VERSION 5.8 ;
BUSBITCHARS "[]" ;
DIVIDERCHAR "/" ;
UNITS
    DATABASE MICRONS 1000 ;
END UNITS

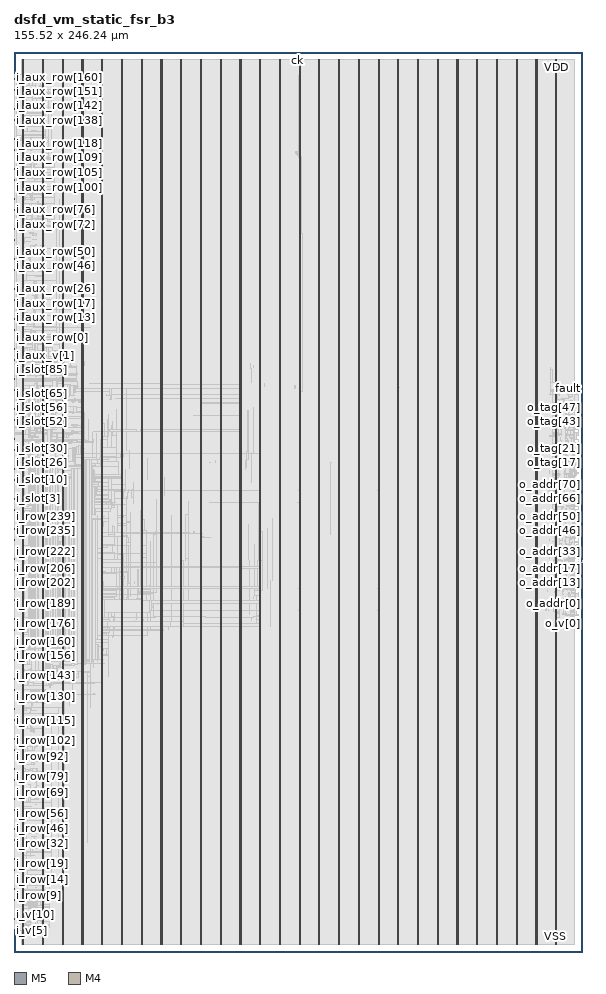
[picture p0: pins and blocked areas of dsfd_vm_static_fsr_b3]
MACRO dsfd_vm_static_fsr_b3
  FOREIGN dsfd_vm_static_fsr_b3 0 0 ;
  CLASS BLOCK ;
  SIZE 155.52 BY 246.24 ;
  PIN ck
    DIRECTION INPUT ;
    USE SIGNAL ;
    PORT
      LAYER M5 ;
        RECT  77.52 246.156 77.544 246.24 ;
    END
  END ck
  PIN fault
    DIRECTION OUTPUT ;
    USE SIGNAL ;
    PORT
      LAYER M4 ;
        RECT  155.436 154.176 155.52 154.2 ;
    END
  END fault
  PIN i_aux_row[0]
    DIRECTION INPUT ;
    USE SIGNAL ;
    PORT
      LAYER M4 ;
        RECT  0 168 0.084 168.024 ;
    END
  END i_aux_row[0]
  PIN i_aux_row[100]
    DIRECTION INPUT ;
    USE SIGNAL ;
    PORT
      LAYER M4 ;
        RECT  0 211.2 0.084 211.224 ;
    END
  END i_aux_row[100]
  PIN i_aux_row[101]
    DIRECTION INPUT ;
    USE SIGNAL ;
    PORT
      LAYER M4 ;
        RECT  0 211.632 0.084 211.656 ;
    END
  END i_aux_row[101]
  PIN i_aux_row[102]
    DIRECTION INPUT ;
    USE SIGNAL ;
    PORT
      LAYER M4 ;
        RECT  0 212.064 0.084 212.088 ;
    END
  END i_aux_row[102]
  PIN i_aux_row[103]
    DIRECTION INPUT ;
    USE SIGNAL ;
    PORT
      LAYER M4 ;
        RECT  0 212.496 0.084 212.52 ;
    END
  END i_aux_row[103]
  PIN i_aux_row[104]
    DIRECTION INPUT ;
    USE SIGNAL ;
    PORT
      LAYER M4 ;
        RECT  0 212.928 0.084 212.952 ;
    END
  END i_aux_row[104]
  PIN i_aux_row[105]
    DIRECTION INPUT ;
    USE SIGNAL ;
    PORT
      LAYER M4 ;
        RECT  0 213.36 0.084 213.384 ;
    END
  END i_aux_row[105]
  PIN i_aux_row[106]
    DIRECTION INPUT ;
    USE SIGNAL ;
    PORT
      LAYER M4 ;
        RECT  0 213.792 0.084 213.816 ;
    END
  END i_aux_row[106]
  PIN i_aux_row[107]
    DIRECTION INPUT ;
    USE SIGNAL ;
    PORT
      LAYER M4 ;
        RECT  0 214.224 0.084 214.248 ;
    END
  END i_aux_row[107]
  PIN i_aux_row[108]
    DIRECTION INPUT ;
    USE SIGNAL ;
    PORT
      LAYER M4 ;
        RECT  0 214.656 0.084 214.68 ;
    END
  END i_aux_row[108]
  PIN i_aux_row[109]
    DIRECTION INPUT ;
    USE SIGNAL ;
    PORT
      LAYER M4 ;
        RECT  0 215.088 0.084 215.112 ;
    END
  END i_aux_row[109]
  PIN i_aux_row[10]
    DIRECTION INPUT ;
    USE SIGNAL ;
    PORT
      LAYER M4 ;
        RECT  0 172.32 0.084 172.344 ;
    END
  END i_aux_row[10]
  PIN i_aux_row[110]
    DIRECTION INPUT ;
    USE SIGNAL ;
    PORT
      LAYER M4 ;
        RECT  0 215.52 0.084 215.544 ;
    END
  END i_aux_row[110]
  PIN i_aux_row[111]
    DIRECTION INPUT ;
    USE SIGNAL ;
    PORT
      LAYER M4 ;
        RECT  0 215.952 0.084 215.976 ;
    END
  END i_aux_row[111]
  PIN i_aux_row[112]
    DIRECTION INPUT ;
    USE SIGNAL ;
    PORT
      LAYER M4 ;
        RECT  0 216.384 0.084 216.408 ;
    END
  END i_aux_row[112]
  PIN i_aux_row[113]
    DIRECTION INPUT ;
    USE SIGNAL ;
    PORT
      LAYER M4 ;
        RECT  0 216.816 0.084 216.84 ;
    END
  END i_aux_row[113]
  PIN i_aux_row[114]
    DIRECTION INPUT ;
    USE SIGNAL ;
    PORT
      LAYER M4 ;
        RECT  0 217.248 0.084 217.272 ;
    END
  END i_aux_row[114]
  PIN i_aux_row[115]
    DIRECTION INPUT ;
    USE SIGNAL ;
    PORT
      LAYER M4 ;
        RECT  0 217.68 0.084 217.704 ;
    END
  END i_aux_row[115]
  PIN i_aux_row[116]
    DIRECTION INPUT ;
    USE SIGNAL ;
    PORT
      LAYER M4 ;
        RECT  0 218.112 0.084 218.136 ;
    END
  END i_aux_row[116]
  PIN i_aux_row[117]
    DIRECTION INPUT ;
    USE SIGNAL ;
    PORT
      LAYER M4 ;
        RECT  0 218.544 0.084 218.568 ;
    END
  END i_aux_row[117]
  PIN i_aux_row[118]
    DIRECTION INPUT ;
    USE SIGNAL ;
    PORT
      LAYER M4 ;
        RECT  0 218.976 0.084 219 ;
    END
  END i_aux_row[118]
  PIN i_aux_row[119]
    DIRECTION INPUT ;
    USE SIGNAL ;
    PORT
      LAYER M4 ;
        RECT  0 219.408 0.084 219.432 ;
    END
  END i_aux_row[119]
  PIN i_aux_row[11]
    DIRECTION INPUT ;
    USE SIGNAL ;
    PORT
      LAYER M4 ;
        RECT  0 172.752 0.084 172.776 ;
    END
  END i_aux_row[11]
  PIN i_aux_row[120]
    DIRECTION INPUT ;
    USE SIGNAL ;
    PORT
      LAYER M4 ;
        RECT  0 219.84 0.084 219.864 ;
    END
  END i_aux_row[120]
  PIN i_aux_row[121]
    DIRECTION INPUT ;
    USE SIGNAL ;
    PORT
      LAYER M4 ;
        RECT  0 220.272 0.084 220.296 ;
    END
  END i_aux_row[121]
  PIN i_aux_row[122]
    DIRECTION INPUT ;
    USE SIGNAL ;
    PORT
      LAYER M4 ;
        RECT  0 220.704 0.084 220.728 ;
    END
  END i_aux_row[122]
  PIN i_aux_row[123]
    DIRECTION INPUT ;
    USE SIGNAL ;
    PORT
      LAYER M4 ;
        RECT  0 221.136 0.084 221.16 ;
    END
  END i_aux_row[123]
  PIN i_aux_row[124]
    DIRECTION INPUT ;
    USE SIGNAL ;
    PORT
      LAYER M4 ;
        RECT  0 221.568 0.084 221.592 ;
    END
  END i_aux_row[124]
  PIN i_aux_row[125]
    DIRECTION INPUT ;
    USE SIGNAL ;
    PORT
      LAYER M4 ;
        RECT  0 222 0.084 222.024 ;
    END
  END i_aux_row[125]
  PIN i_aux_row[126]
    DIRECTION INPUT ;
    USE SIGNAL ;
    PORT
      LAYER M4 ;
        RECT  0 222.432 0.084 222.456 ;
    END
  END i_aux_row[126]
  PIN i_aux_row[127]
    DIRECTION INPUT ;
    USE SIGNAL ;
    PORT
      LAYER M4 ;
        RECT  0 222.864 0.084 222.888 ;
    END
  END i_aux_row[127]
  PIN i_aux_row[128]
    DIRECTION INPUT ;
    USE SIGNAL ;
    PORT
      LAYER M4 ;
        RECT  0 223.296 0.084 223.32 ;
    END
  END i_aux_row[128]
  PIN i_aux_row[129]
    DIRECTION INPUT ;
    USE SIGNAL ;
    PORT
      LAYER M4 ;
        RECT  0 223.728 0.084 223.752 ;
    END
  END i_aux_row[129]
  PIN i_aux_row[12]
    DIRECTION INPUT ;
    USE SIGNAL ;
    PORT
      LAYER M4 ;
        RECT  0 173.184 0.084 173.208 ;
    END
  END i_aux_row[12]
  PIN i_aux_row[130]
    DIRECTION INPUT ;
    USE SIGNAL ;
    PORT
      LAYER M4 ;
        RECT  0 224.16 0.084 224.184 ;
    END
  END i_aux_row[130]
  PIN i_aux_row[131]
    DIRECTION INPUT ;
    USE SIGNAL ;
    PORT
      LAYER M4 ;
        RECT  0 224.592 0.084 224.616 ;
    END
  END i_aux_row[131]
  PIN i_aux_row[132]
    DIRECTION INPUT ;
    USE SIGNAL ;
    PORT
      LAYER M4 ;
        RECT  0 225.024 0.084 225.048 ;
    END
  END i_aux_row[132]
  PIN i_aux_row[133]
    DIRECTION INPUT ;
    USE SIGNAL ;
    PORT
      LAYER M4 ;
        RECT  0 225.456 0.084 225.48 ;
    END
  END i_aux_row[133]
  PIN i_aux_row[134]
    DIRECTION INPUT ;
    USE SIGNAL ;
    PORT
      LAYER M4 ;
        RECT  0 225.888 0.084 225.912 ;
    END
  END i_aux_row[134]
  PIN i_aux_row[135]
    DIRECTION INPUT ;
    USE SIGNAL ;
    PORT
      LAYER M4 ;
        RECT  0 226.32 0.084 226.344 ;
    END
  END i_aux_row[135]
  PIN i_aux_row[136]
    DIRECTION INPUT ;
    USE SIGNAL ;
    PORT
      LAYER M4 ;
        RECT  0 226.752 0.084 226.776 ;
    END
  END i_aux_row[136]
  PIN i_aux_row[137]
    DIRECTION INPUT ;
    USE SIGNAL ;
    PORT
      LAYER M4 ;
        RECT  0 227.184 0.084 227.208 ;
    END
  END i_aux_row[137]
  PIN i_aux_row[138]
    DIRECTION INPUT ;
    USE SIGNAL ;
    PORT
      LAYER M4 ;
        RECT  0 227.616 0.084 227.64 ;
    END
  END i_aux_row[138]
  PIN i_aux_row[139]
    DIRECTION INPUT ;
    USE SIGNAL ;
    PORT
      LAYER M4 ;
        RECT  0 228.048 0.084 228.072 ;
    END
  END i_aux_row[139]
  PIN i_aux_row[13]
    DIRECTION INPUT ;
    USE SIGNAL ;
    PORT
      LAYER M4 ;
        RECT  0 173.616 0.084 173.64 ;
    END
  END i_aux_row[13]
  PIN i_aux_row[140]
    DIRECTION INPUT ;
    USE SIGNAL ;
    PORT
      LAYER M4 ;
        RECT  0 228.48 0.084 228.504 ;
    END
  END i_aux_row[140]
  PIN i_aux_row[141]
    DIRECTION INPUT ;
    USE SIGNAL ;
    PORT
      LAYER M4 ;
        RECT  0 228.912 0.084 228.936 ;
    END
  END i_aux_row[141]
  PIN i_aux_row[142]
    DIRECTION INPUT ;
    USE SIGNAL ;
    PORT
      LAYER M4 ;
        RECT  0 229.344 0.084 229.368 ;
    END
  END i_aux_row[142]
  PIN i_aux_row[143]
    DIRECTION INPUT ;
    USE SIGNAL ;
    PORT
      LAYER M4 ;
        RECT  0 229.776 0.084 229.8 ;
    END
  END i_aux_row[143]
  PIN i_aux_row[144]
    DIRECTION INPUT ;
    USE SIGNAL ;
    PORT
      LAYER M4 ;
        RECT  0 230.208 0.084 230.232 ;
    END
  END i_aux_row[144]
  PIN i_aux_row[145]
    DIRECTION INPUT ;
    USE SIGNAL ;
    PORT
      LAYER M4 ;
        RECT  0 230.64 0.084 230.664 ;
    END
  END i_aux_row[145]
  PIN i_aux_row[146]
    DIRECTION INPUT ;
    USE SIGNAL ;
    PORT
      LAYER M4 ;
        RECT  0 231.072 0.084 231.096 ;
    END
  END i_aux_row[146]
  PIN i_aux_row[147]
    DIRECTION INPUT ;
    USE SIGNAL ;
    PORT
      LAYER M4 ;
        RECT  0 231.504 0.084 231.528 ;
    END
  END i_aux_row[147]
  PIN i_aux_row[148]
    DIRECTION INPUT ;
    USE SIGNAL ;
    PORT
      LAYER M4 ;
        RECT  0 231.936 0.084 231.96 ;
    END
  END i_aux_row[148]
  PIN i_aux_row[149]
    DIRECTION INPUT ;
    USE SIGNAL ;
    PORT
      LAYER M4 ;
        RECT  0 232.368 0.084 232.392 ;
    END
  END i_aux_row[149]
  PIN i_aux_row[14]
    DIRECTION INPUT ;
    USE SIGNAL ;
    PORT
      LAYER M4 ;
        RECT  0 174.048 0.084 174.072 ;
    END
  END i_aux_row[14]
  PIN i_aux_row[150]
    DIRECTION INPUT ;
    USE SIGNAL ;
    PORT
      LAYER M4 ;
        RECT  0 232.8 0.084 232.824 ;
    END
  END i_aux_row[150]
  PIN i_aux_row[151]
    DIRECTION INPUT ;
    USE SIGNAL ;
    PORT
      LAYER M4 ;
        RECT  0 233.232 0.084 233.256 ;
    END
  END i_aux_row[151]
  PIN i_aux_row[152]
    DIRECTION INPUT ;
    USE SIGNAL ;
    PORT
      LAYER M4 ;
        RECT  0 233.664 0.084 233.688 ;
    END
  END i_aux_row[152]
  PIN i_aux_row[153]
    DIRECTION INPUT ;
    USE SIGNAL ;
    PORT
      LAYER M4 ;
        RECT  0 234.096 0.084 234.12 ;
    END
  END i_aux_row[153]
  PIN i_aux_row[154]
    DIRECTION INPUT ;
    USE SIGNAL ;
    PORT
      LAYER M4 ;
        RECT  0 234.528 0.084 234.552 ;
    END
  END i_aux_row[154]
  PIN i_aux_row[155]
    DIRECTION INPUT ;
    USE SIGNAL ;
    PORT
      LAYER M4 ;
        RECT  0 234.96 0.084 234.984 ;
    END
  END i_aux_row[155]
  PIN i_aux_row[156]
    DIRECTION INPUT ;
    USE SIGNAL ;
    PORT
      LAYER M4 ;
        RECT  0 235.392 0.084 235.416 ;
    END
  END i_aux_row[156]
  PIN i_aux_row[157]
    DIRECTION INPUT ;
    USE SIGNAL ;
    PORT
      LAYER M4 ;
        RECT  0 235.824 0.084 235.848 ;
    END
  END i_aux_row[157]
  PIN i_aux_row[158]
    DIRECTION INPUT ;
    USE SIGNAL ;
    PORT
      LAYER M4 ;
        RECT  0 236.256 0.084 236.28 ;
    END
  END i_aux_row[158]
  PIN i_aux_row[159]
    DIRECTION INPUT ;
    USE SIGNAL ;
    PORT
      LAYER M4 ;
        RECT  0 236.688 0.084 236.712 ;
    END
  END i_aux_row[159]
  PIN i_aux_row[15]
    DIRECTION INPUT ;
    USE SIGNAL ;
    PORT
      LAYER M4 ;
        RECT  0 174.48 0.084 174.504 ;
    END
  END i_aux_row[15]
  PIN i_aux_row[160]
    DIRECTION INPUT ;
    USE SIGNAL ;
    PORT
      LAYER M4 ;
        RECT  0 237.12 0.084 237.144 ;
    END
  END i_aux_row[160]
  PIN i_aux_row[161]
    DIRECTION INPUT ;
    USE SIGNAL ;
    PORT
      LAYER M4 ;
        RECT  0 237.552 0.084 237.576 ;
    END
  END i_aux_row[161]
  PIN i_aux_row[162]
    DIRECTION INPUT ;
    USE SIGNAL ;
    PORT
      LAYER M4 ;
        RECT  0 237.984 0.084 238.008 ;
    END
  END i_aux_row[162]
  PIN i_aux_row[163]
    DIRECTION INPUT ;
    USE SIGNAL ;
    PORT
      LAYER M4 ;
        RECT  0 238.416 0.084 238.44 ;
    END
  END i_aux_row[163]
  PIN i_aux_row[164]
    DIRECTION INPUT ;
    USE SIGNAL ;
    PORT
      LAYER M4 ;
        RECT  0 238.848 0.084 238.872 ;
    END
  END i_aux_row[164]
  PIN i_aux_row[165]
    DIRECTION INPUT ;
    USE SIGNAL ;
    PORT
      LAYER M4 ;
        RECT  0 239.28 0.084 239.304 ;
    END
  END i_aux_row[165]
  PIN i_aux_row[166]
    DIRECTION INPUT ;
    USE SIGNAL ;
    PORT
      LAYER M4 ;
        RECT  0 239.712 0.084 239.736 ;
    END
  END i_aux_row[166]
  PIN i_aux_row[167]
    DIRECTION INPUT ;
    USE SIGNAL ;
    PORT
      LAYER M4 ;
        RECT  0 240.144 0.084 240.168 ;
    END
  END i_aux_row[167]
  PIN i_aux_row[16]
    DIRECTION INPUT ;
    USE SIGNAL ;
    PORT
      LAYER M4 ;
        RECT  0 174.912 0.084 174.936 ;
    END
  END i_aux_row[16]
  PIN i_aux_row[17]
    DIRECTION INPUT ;
    USE SIGNAL ;
    PORT
      LAYER M4 ;
        RECT  0 175.344 0.084 175.368 ;
    END
  END i_aux_row[17]
  PIN i_aux_row[18]
    DIRECTION INPUT ;
    USE SIGNAL ;
    PORT
      LAYER M4 ;
        RECT  0 175.776 0.084 175.8 ;
    END
  END i_aux_row[18]
  PIN i_aux_row[19]
    DIRECTION INPUT ;
    USE SIGNAL ;
    PORT
      LAYER M4 ;
        RECT  0 176.208 0.084 176.232 ;
    END
  END i_aux_row[19]
  PIN i_aux_row[1]
    DIRECTION INPUT ;
    USE SIGNAL ;
    PORT
      LAYER M4 ;
        RECT  0 168.432 0.084 168.456 ;
    END
  END i_aux_row[1]
  PIN i_aux_row[20]
    DIRECTION INPUT ;
    USE SIGNAL ;
    PORT
      LAYER M4 ;
        RECT  0 176.64 0.084 176.664 ;
    END
  END i_aux_row[20]
  PIN i_aux_row[21]
    DIRECTION INPUT ;
    USE SIGNAL ;
    PORT
      LAYER M4 ;
        RECT  0 177.072 0.084 177.096 ;
    END
  END i_aux_row[21]
  PIN i_aux_row[22]
    DIRECTION INPUT ;
    USE SIGNAL ;
    PORT
      LAYER M4 ;
        RECT  0 177.504 0.084 177.528 ;
    END
  END i_aux_row[22]
  PIN i_aux_row[23]
    DIRECTION INPUT ;
    USE SIGNAL ;
    PORT
      LAYER M4 ;
        RECT  0 177.936 0.084 177.96 ;
    END
  END i_aux_row[23]
  PIN i_aux_row[24]
    DIRECTION INPUT ;
    USE SIGNAL ;
    PORT
      LAYER M4 ;
        RECT  0 178.368 0.084 178.392 ;
    END
  END i_aux_row[24]
  PIN i_aux_row[25]
    DIRECTION INPUT ;
    USE SIGNAL ;
    PORT
      LAYER M4 ;
        RECT  0 178.8 0.084 178.824 ;
    END
  END i_aux_row[25]
  PIN i_aux_row[26]
    DIRECTION INPUT ;
    USE SIGNAL ;
    PORT
      LAYER M4 ;
        RECT  0 179.232 0.084 179.256 ;
    END
  END i_aux_row[26]
  PIN i_aux_row[27]
    DIRECTION INPUT ;
    USE SIGNAL ;
    PORT
      LAYER M4 ;
        RECT  0 179.664 0.084 179.688 ;
    END
  END i_aux_row[27]
  PIN i_aux_row[28]
    DIRECTION INPUT ;
    USE SIGNAL ;
    PORT
      LAYER M4 ;
        RECT  0 180.096 0.084 180.12 ;
    END
  END i_aux_row[28]
  PIN i_aux_row[29]
    DIRECTION INPUT ;
    USE SIGNAL ;
    PORT
      LAYER M4 ;
        RECT  0 180.528 0.084 180.552 ;
    END
  END i_aux_row[29]
  PIN i_aux_row[2]
    DIRECTION INPUT ;
    USE SIGNAL ;
    PORT
      LAYER M4 ;
        RECT  0 168.864 0.084 168.888 ;
    END
  END i_aux_row[2]
  PIN i_aux_row[30]
    DIRECTION INPUT ;
    USE SIGNAL ;
    PORT
      LAYER M4 ;
        RECT  0 180.96 0.084 180.984 ;
    END
  END i_aux_row[30]
  PIN i_aux_row[31]
    DIRECTION INPUT ;
    USE SIGNAL ;
    PORT
      LAYER M4 ;
        RECT  0 181.392 0.084 181.416 ;
    END
  END i_aux_row[31]
  PIN i_aux_row[32]
    DIRECTION INPUT ;
    USE SIGNAL ;
    PORT
      LAYER M4 ;
        RECT  0 181.824 0.084 181.848 ;
    END
  END i_aux_row[32]
  PIN i_aux_row[33]
    DIRECTION INPUT ;
    USE SIGNAL ;
    PORT
      LAYER M4 ;
        RECT  0 182.256 0.084 182.28 ;
    END
  END i_aux_row[33]
  PIN i_aux_row[34]
    DIRECTION INPUT ;
    USE SIGNAL ;
    PORT
      LAYER M4 ;
        RECT  0 182.688 0.084 182.712 ;
    END
  END i_aux_row[34]
  PIN i_aux_row[35]
    DIRECTION INPUT ;
    USE SIGNAL ;
    PORT
      LAYER M4 ;
        RECT  0 183.12 0.084 183.144 ;
    END
  END i_aux_row[35]
  PIN i_aux_row[36]
    DIRECTION INPUT ;
    USE SIGNAL ;
    PORT
      LAYER M4 ;
        RECT  0 183.552 0.084 183.576 ;
    END
  END i_aux_row[36]
  PIN i_aux_row[37]
    DIRECTION INPUT ;
    USE SIGNAL ;
    PORT
      LAYER M4 ;
        RECT  0 183.984 0.084 184.008 ;
    END
  END i_aux_row[37]
  PIN i_aux_row[38]
    DIRECTION INPUT ;
    USE SIGNAL ;
    PORT
      LAYER M4 ;
        RECT  0 184.416 0.084 184.44 ;
    END
  END i_aux_row[38]
  PIN i_aux_row[39]
    DIRECTION INPUT ;
    USE SIGNAL ;
    PORT
      LAYER M4 ;
        RECT  0 184.848 0.084 184.872 ;
    END
  END i_aux_row[39]
  PIN i_aux_row[3]
    DIRECTION INPUT ;
    USE SIGNAL ;
    PORT
      LAYER M4 ;
        RECT  0 169.296 0.084 169.32 ;
    END
  END i_aux_row[3]
  PIN i_aux_row[40]
    DIRECTION INPUT ;
    USE SIGNAL ;
    PORT
      LAYER M4 ;
        RECT  0 185.28 0.084 185.304 ;
    END
  END i_aux_row[40]
  PIN i_aux_row[41]
    DIRECTION INPUT ;
    USE SIGNAL ;
    PORT
      LAYER M4 ;
        RECT  0 185.712 0.084 185.736 ;
    END
  END i_aux_row[41]
  PIN i_aux_row[42]
    DIRECTION INPUT ;
    USE SIGNAL ;
    PORT
      LAYER M4 ;
        RECT  0 186.144 0.084 186.168 ;
    END
  END i_aux_row[42]
  PIN i_aux_row[43]
    DIRECTION INPUT ;
    USE SIGNAL ;
    PORT
      LAYER M4 ;
        RECT  0 186.576 0.084 186.6 ;
    END
  END i_aux_row[43]
  PIN i_aux_row[44]
    DIRECTION INPUT ;
    USE SIGNAL ;
    PORT
      LAYER M4 ;
        RECT  0 187.008 0.084 187.032 ;
    END
  END i_aux_row[44]
  PIN i_aux_row[45]
    DIRECTION INPUT ;
    USE SIGNAL ;
    PORT
      LAYER M4 ;
        RECT  0 187.44 0.084 187.464 ;
    END
  END i_aux_row[45]
  PIN i_aux_row[46]
    DIRECTION INPUT ;
    USE SIGNAL ;
    PORT
      LAYER M4 ;
        RECT  0 187.872 0.084 187.896 ;
    END
  END i_aux_row[46]
  PIN i_aux_row[47]
    DIRECTION INPUT ;
    USE SIGNAL ;
    PORT
      LAYER M4 ;
        RECT  0 188.304 0.084 188.328 ;
    END
  END i_aux_row[47]
  PIN i_aux_row[48]
    DIRECTION INPUT ;
    USE SIGNAL ;
    PORT
      LAYER M4 ;
        RECT  0 188.736 0.084 188.76 ;
    END
  END i_aux_row[48]
  PIN i_aux_row[49]
    DIRECTION INPUT ;
    USE SIGNAL ;
    PORT
      LAYER M4 ;
        RECT  0 189.168 0.084 189.192 ;
    END
  END i_aux_row[49]
  PIN i_aux_row[4]
    DIRECTION INPUT ;
    USE SIGNAL ;
    PORT
      LAYER M4 ;
        RECT  0 169.728 0.084 169.752 ;
    END
  END i_aux_row[4]
  PIN i_aux_row[50]
    DIRECTION INPUT ;
    USE SIGNAL ;
    PORT
      LAYER M4 ;
        RECT  0 189.6 0.084 189.624 ;
    END
  END i_aux_row[50]
  PIN i_aux_row[51]
    DIRECTION INPUT ;
    USE SIGNAL ;
    PORT
      LAYER M4 ;
        RECT  0 190.032 0.084 190.056 ;
    END
  END i_aux_row[51]
  PIN i_aux_row[52]
    DIRECTION INPUT ;
    USE SIGNAL ;
    PORT
      LAYER M4 ;
        RECT  0 190.464 0.084 190.488 ;
    END
  END i_aux_row[52]
  PIN i_aux_row[53]
    DIRECTION INPUT ;
    USE SIGNAL ;
    PORT
      LAYER M4 ;
        RECT  0 190.896 0.084 190.92 ;
    END
  END i_aux_row[53]
  PIN i_aux_row[54]
    DIRECTION INPUT ;
    USE SIGNAL ;
    PORT
      LAYER M4 ;
        RECT  0 191.328 0.084 191.352 ;
    END
  END i_aux_row[54]
  PIN i_aux_row[55]
    DIRECTION INPUT ;
    USE SIGNAL ;
    PORT
      LAYER M4 ;
        RECT  0 191.76 0.084 191.784 ;
    END
  END i_aux_row[55]
  PIN i_aux_row[56]
    DIRECTION INPUT ;
    USE SIGNAL ;
    PORT
      LAYER M4 ;
        RECT  0 192.192 0.084 192.216 ;
    END
  END i_aux_row[56]
  PIN i_aux_row[57]
    DIRECTION INPUT ;
    USE SIGNAL ;
    PORT
      LAYER M4 ;
        RECT  0 192.624 0.084 192.648 ;
    END
  END i_aux_row[57]
  PIN i_aux_row[58]
    DIRECTION INPUT ;
    USE SIGNAL ;
    PORT
      LAYER M4 ;
        RECT  0 193.056 0.084 193.08 ;
    END
  END i_aux_row[58]
  PIN i_aux_row[59]
    DIRECTION INPUT ;
    USE SIGNAL ;
    PORT
      LAYER M4 ;
        RECT  0 193.488 0.084 193.512 ;
    END
  END i_aux_row[59]
  PIN i_aux_row[5]
    DIRECTION INPUT ;
    USE SIGNAL ;
    PORT
      LAYER M4 ;
        RECT  0 170.16 0.084 170.184 ;
    END
  END i_aux_row[5]
  PIN i_aux_row[60]
    DIRECTION INPUT ;
    USE SIGNAL ;
    PORT
      LAYER M4 ;
        RECT  0 193.92 0.084 193.944 ;
    END
  END i_aux_row[60]
  PIN i_aux_row[61]
    DIRECTION INPUT ;
    USE SIGNAL ;
    PORT
      LAYER M4 ;
        RECT  0 194.352 0.084 194.376 ;
    END
  END i_aux_row[61]
  PIN i_aux_row[62]
    DIRECTION INPUT ;
    USE SIGNAL ;
    PORT
      LAYER M4 ;
        RECT  0 194.784 0.084 194.808 ;
    END
  END i_aux_row[62]
  PIN i_aux_row[63]
    DIRECTION INPUT ;
    USE SIGNAL ;
    PORT
      LAYER M4 ;
        RECT  0 195.216 0.084 195.24 ;
    END
  END i_aux_row[63]
  PIN i_aux_row[64]
    DIRECTION INPUT ;
    USE SIGNAL ;
    PORT
      LAYER M4 ;
        RECT  0 195.648 0.084 195.672 ;
    END
  END i_aux_row[64]
  PIN i_aux_row[65]
    DIRECTION INPUT ;
    USE SIGNAL ;
    PORT
      LAYER M4 ;
        RECT  0 196.08 0.084 196.104 ;
    END
  END i_aux_row[65]
  PIN i_aux_row[66]
    DIRECTION INPUT ;
    USE SIGNAL ;
    PORT
      LAYER M4 ;
        RECT  0 196.512 0.084 196.536 ;
    END
  END i_aux_row[66]
  PIN i_aux_row[67]
    DIRECTION INPUT ;
    USE SIGNAL ;
    PORT
      LAYER M4 ;
        RECT  0 196.944 0.084 196.968 ;
    END
  END i_aux_row[67]
  PIN i_aux_row[68]
    DIRECTION INPUT ;
    USE SIGNAL ;
    PORT
      LAYER M4 ;
        RECT  0 197.376 0.084 197.4 ;
    END
  END i_aux_row[68]
  PIN i_aux_row[69]
    DIRECTION INPUT ;
    USE SIGNAL ;
    PORT
      LAYER M4 ;
        RECT  0 197.808 0.084 197.832 ;
    END
  END i_aux_row[69]
  PIN i_aux_row[6]
    DIRECTION INPUT ;
    USE SIGNAL ;
    PORT
      LAYER M4 ;
        RECT  0 170.592 0.084 170.616 ;
    END
  END i_aux_row[6]
  PIN i_aux_row[70]
    DIRECTION INPUT ;
    USE SIGNAL ;
    PORT
      LAYER M4 ;
        RECT  0 198.24 0.084 198.264 ;
    END
  END i_aux_row[70]
  PIN i_aux_row[71]
    DIRECTION INPUT ;
    USE SIGNAL ;
    PORT
      LAYER M4 ;
        RECT  0 198.672 0.084 198.696 ;
    END
  END i_aux_row[71]
  PIN i_aux_row[72]
    DIRECTION INPUT ;
    USE SIGNAL ;
    PORT
      LAYER M4 ;
        RECT  0 199.104 0.084 199.128 ;
    END
  END i_aux_row[72]
  PIN i_aux_row[73]
    DIRECTION INPUT ;
    USE SIGNAL ;
    PORT
      LAYER M4 ;
        RECT  0 199.536 0.084 199.56 ;
    END
  END i_aux_row[73]
  PIN i_aux_row[74]
    DIRECTION INPUT ;
    USE SIGNAL ;
    PORT
      LAYER M4 ;
        RECT  0 199.968 0.084 199.992 ;
    END
  END i_aux_row[74]
  PIN i_aux_row[75]
    DIRECTION INPUT ;
    USE SIGNAL ;
    PORT
      LAYER M4 ;
        RECT  0 200.4 0.084 200.424 ;
    END
  END i_aux_row[75]
  PIN i_aux_row[76]
    DIRECTION INPUT ;
    USE SIGNAL ;
    PORT
      LAYER M4 ;
        RECT  0 200.832 0.084 200.856 ;
    END
  END i_aux_row[76]
  PIN i_aux_row[77]
    DIRECTION INPUT ;
    USE SIGNAL ;
    PORT
      LAYER M4 ;
        RECT  0 201.264 0.084 201.288 ;
    END
  END i_aux_row[77]
  PIN i_aux_row[78]
    DIRECTION INPUT ;
    USE SIGNAL ;
    PORT
      LAYER M4 ;
        RECT  0 201.696 0.084 201.72 ;
    END
  END i_aux_row[78]
  PIN i_aux_row[79]
    DIRECTION INPUT ;
    USE SIGNAL ;
    PORT
      LAYER M4 ;
        RECT  0 202.128 0.084 202.152 ;
    END
  END i_aux_row[79]
  PIN i_aux_row[7]
    DIRECTION INPUT ;
    USE SIGNAL ;
    PORT
      LAYER M4 ;
        RECT  0 171.024 0.084 171.048 ;
    END
  END i_aux_row[7]
  PIN i_aux_row[80]
    DIRECTION INPUT ;
    USE SIGNAL ;
    PORT
      LAYER M4 ;
        RECT  0 202.56 0.084 202.584 ;
    END
  END i_aux_row[80]
  PIN i_aux_row[81]
    DIRECTION INPUT ;
    USE SIGNAL ;
    PORT
      LAYER M4 ;
        RECT  0 202.992 0.084 203.016 ;
    END
  END i_aux_row[81]
  PIN i_aux_row[82]
    DIRECTION INPUT ;
    USE SIGNAL ;
    PORT
      LAYER M4 ;
        RECT  0 203.424 0.084 203.448 ;
    END
  END i_aux_row[82]
  PIN i_aux_row[83]
    DIRECTION INPUT ;
    USE SIGNAL ;
    PORT
      LAYER M4 ;
        RECT  0 203.856 0.084 203.88 ;
    END
  END i_aux_row[83]
  PIN i_aux_row[84]
    DIRECTION INPUT ;
    USE SIGNAL ;
    PORT
      LAYER M4 ;
        RECT  0 204.288 0.084 204.312 ;
    END
  END i_aux_row[84]
  PIN i_aux_row[85]
    DIRECTION INPUT ;
    USE SIGNAL ;
    PORT
      LAYER M4 ;
        RECT  0 204.72 0.084 204.744 ;
    END
  END i_aux_row[85]
  PIN i_aux_row[86]
    DIRECTION INPUT ;
    USE SIGNAL ;
    PORT
      LAYER M4 ;
        RECT  0 205.152 0.084 205.176 ;
    END
  END i_aux_row[86]
  PIN i_aux_row[87]
    DIRECTION INPUT ;
    USE SIGNAL ;
    PORT
      LAYER M4 ;
        RECT  0 205.584 0.084 205.608 ;
    END
  END i_aux_row[87]
  PIN i_aux_row[88]
    DIRECTION INPUT ;
    USE SIGNAL ;
    PORT
      LAYER M4 ;
        RECT  0 206.016 0.084 206.04 ;
    END
  END i_aux_row[88]
  PIN i_aux_row[89]
    DIRECTION INPUT ;
    USE SIGNAL ;
    PORT
      LAYER M4 ;
        RECT  0 206.448 0.084 206.472 ;
    END
  END i_aux_row[89]
  PIN i_aux_row[8]
    DIRECTION INPUT ;
    USE SIGNAL ;
    PORT
      LAYER M4 ;
        RECT  0 171.456 0.084 171.48 ;
    END
  END i_aux_row[8]
  PIN i_aux_row[90]
    DIRECTION INPUT ;
    USE SIGNAL ;
    PORT
      LAYER M4 ;
        RECT  0 206.88 0.084 206.904 ;
    END
  END i_aux_row[90]
  PIN i_aux_row[91]
    DIRECTION INPUT ;
    USE SIGNAL ;
    PORT
      LAYER M4 ;
        RECT  0 207.312 0.084 207.336 ;
    END
  END i_aux_row[91]
  PIN i_aux_row[92]
    DIRECTION INPUT ;
    USE SIGNAL ;
    PORT
      LAYER M4 ;
        RECT  0 207.744 0.084 207.768 ;
    END
  END i_aux_row[92]
  PIN i_aux_row[93]
    DIRECTION INPUT ;
    USE SIGNAL ;
    PORT
      LAYER M4 ;
        RECT  0 208.176 0.084 208.2 ;
    END
  END i_aux_row[93]
  PIN i_aux_row[94]
    DIRECTION INPUT ;
    USE SIGNAL ;
    PORT
      LAYER M4 ;
        RECT  0 208.608 0.084 208.632 ;
    END
  END i_aux_row[94]
  PIN i_aux_row[95]
    DIRECTION INPUT ;
    USE SIGNAL ;
    PORT
      LAYER M4 ;
        RECT  0 209.04 0.084 209.064 ;
    END
  END i_aux_row[95]
  PIN i_aux_row[96]
    DIRECTION INPUT ;
    USE SIGNAL ;
    PORT
      LAYER M4 ;
        RECT  0 209.472 0.084 209.496 ;
    END
  END i_aux_row[96]
  PIN i_aux_row[97]
    DIRECTION INPUT ;
    USE SIGNAL ;
    PORT
      LAYER M4 ;
        RECT  0 209.904 0.084 209.928 ;
    END
  END i_aux_row[97]
  PIN i_aux_row[98]
    DIRECTION INPUT ;
    USE SIGNAL ;
    PORT
      LAYER M4 ;
        RECT  0 210.336 0.084 210.36 ;
    END
  END i_aux_row[98]
  PIN i_aux_row[99]
    DIRECTION INPUT ;
    USE SIGNAL ;
    PORT
      LAYER M4 ;
        RECT  0 210.768 0.084 210.792 ;
    END
  END i_aux_row[99]
  PIN i_aux_row[9]
    DIRECTION INPUT ;
    USE SIGNAL ;
    PORT
      LAYER M4 ;
        RECT  0 171.888 0.084 171.912 ;
    END
  END i_aux_row[9]
  PIN i_aux_v[0]
    DIRECTION INPUT ;
    USE SIGNAL ;
    PORT
      LAYER M4 ;
        RECT  0 162.816 0.084 162.84 ;
    END
  END i_aux_v[0]
  PIN i_aux_v[10]
    DIRECTION INPUT ;
    USE SIGNAL ;
    PORT
      LAYER M4 ;
        RECT  0 167.136 0.084 167.16 ;
    END
  END i_aux_v[10]
  PIN i_aux_v[11]
    DIRECTION INPUT ;
    USE SIGNAL ;
    PORT
      LAYER M4 ;
        RECT  0 167.568 0.084 167.592 ;
    END
  END i_aux_v[11]
  PIN i_aux_v[1]
    DIRECTION INPUT ;
    USE SIGNAL ;
    PORT
      LAYER M4 ;
        RECT  0 163.248 0.084 163.272 ;
    END
  END i_aux_v[1]
  PIN i_aux_v[2]
    DIRECTION INPUT ;
    USE SIGNAL ;
    PORT
      LAYER M4 ;
        RECT  0 163.68 0.084 163.704 ;
    END
  END i_aux_v[2]
  PIN i_aux_v[3]
    DIRECTION INPUT ;
    USE SIGNAL ;
    PORT
      LAYER M4 ;
        RECT  0 164.112 0.084 164.136 ;
    END
  END i_aux_v[3]
  PIN i_aux_v[4]
    DIRECTION INPUT ;
    USE SIGNAL ;
    PORT
      LAYER M4 ;
        RECT  0 164.544 0.084 164.568 ;
    END
  END i_aux_v[4]
  PIN i_aux_v[5]
    DIRECTION INPUT ;
    USE SIGNAL ;
    PORT
      LAYER M4 ;
        RECT  0 164.976 0.084 165 ;
    END
  END i_aux_v[5]
  PIN i_aux_v[6]
    DIRECTION INPUT ;
    USE SIGNAL ;
    PORT
      LAYER M4 ;
        RECT  0 165.408 0.084 165.432 ;
    END
  END i_aux_v[6]
  PIN i_aux_v[7]
    DIRECTION INPUT ;
    USE SIGNAL ;
    PORT
      LAYER M4 ;
        RECT  0 165.84 0.084 165.864 ;
    END
  END i_aux_v[7]
  PIN i_aux_v[8]
    DIRECTION INPUT ;
    USE SIGNAL ;
    PORT
      LAYER M4 ;
        RECT  0 166.272 0.084 166.296 ;
    END
  END i_aux_v[8]
  PIN i_aux_v[9]
    DIRECTION INPUT ;
    USE SIGNAL ;
    PORT
      LAYER M4 ;
        RECT  0 166.704 0.084 166.728 ;
    END
  END i_aux_v[9]
  PIN i_group[0]
    DIRECTION INPUT ;
    USE SIGNAL ;
    PORT
      LAYER M4 ;
        RECT  0 161.52 0.084 161.544 ;
    END
  END i_group[0]
  PIN i_group[1]
    DIRECTION INPUT ;
    USE SIGNAL ;
    PORT
      LAYER M4 ;
        RECT  0 161.952 0.084 161.976 ;
    END
  END i_group[1]
  PIN i_group[2]
    DIRECTION INPUT ;
    USE SIGNAL ;
    PORT
      LAYER M4 ;
        RECT  0 162.384 0.084 162.408 ;
    END
  END i_group[2]
  PIN i_row[0]
    DIRECTION INPUT ;
    USE SIGNAL ;
    PORT
      LAYER M4 ;
        RECT  0 13.776 0.084 13.8 ;
    END
  END i_row[0]
  PIN i_row[100]
    DIRECTION INPUT ;
    USE SIGNAL ;
    PORT
      LAYER M4 ;
        RECT  0 56.976 0.084 57 ;
    END
  END i_row[100]
  PIN i_row[101]
    DIRECTION INPUT ;
    USE SIGNAL ;
    PORT
      LAYER M4 ;
        RECT  0 57.408 0.084 57.432 ;
    END
  END i_row[101]
  PIN i_row[102]
    DIRECTION INPUT ;
    USE SIGNAL ;
    PORT
      LAYER M4 ;
        RECT  0 57.84 0.084 57.864 ;
    END
  END i_row[102]
  PIN i_row[103]
    DIRECTION INPUT ;
    USE SIGNAL ;
    PORT
      LAYER M4 ;
        RECT  0 58.272 0.084 58.296 ;
    END
  END i_row[103]
  PIN i_row[104]
    DIRECTION INPUT ;
    USE SIGNAL ;
    PORT
      LAYER M4 ;
        RECT  0 58.704 0.084 58.728 ;
    END
  END i_row[104]
  PIN i_row[105]
    DIRECTION INPUT ;
    USE SIGNAL ;
    PORT
      LAYER M4 ;
        RECT  0 59.136 0.084 59.16 ;
    END
  END i_row[105]
  PIN i_row[106]
    DIRECTION INPUT ;
    USE SIGNAL ;
    PORT
      LAYER M4 ;
        RECT  0 59.568 0.084 59.592 ;
    END
  END i_row[106]
  PIN i_row[107]
    DIRECTION INPUT ;
    USE SIGNAL ;
    PORT
      LAYER M4 ;
        RECT  0 60 0.084 60.024 ;
    END
  END i_row[107]
  PIN i_row[108]
    DIRECTION INPUT ;
    USE SIGNAL ;
    PORT
      LAYER M4 ;
        RECT  0 60.432 0.084 60.456 ;
    END
  END i_row[108]
  PIN i_row[109]
    DIRECTION INPUT ;
    USE SIGNAL ;
    PORT
      LAYER M4 ;
        RECT  0 60.864 0.084 60.888 ;
    END
  END i_row[109]
  PIN i_row[10]
    DIRECTION INPUT ;
    USE SIGNAL ;
    PORT
      LAYER M4 ;
        RECT  0 18.096 0.084 18.12 ;
    END
  END i_row[10]
  PIN i_row[110]
    DIRECTION INPUT ;
    USE SIGNAL ;
    PORT
      LAYER M4 ;
        RECT  0 61.296 0.084 61.32 ;
    END
  END i_row[110]
  PIN i_row[111]
    DIRECTION INPUT ;
    USE SIGNAL ;
    PORT
      LAYER M4 ;
        RECT  0 61.728 0.084 61.752 ;
    END
  END i_row[111]
  PIN i_row[112]
    DIRECTION INPUT ;
    USE SIGNAL ;
    PORT
      LAYER M4 ;
        RECT  0 62.16 0.084 62.184 ;
    END
  END i_row[112]
  PIN i_row[113]
    DIRECTION INPUT ;
    USE SIGNAL ;
    PORT
      LAYER M4 ;
        RECT  0 62.592 0.084 62.616 ;
    END
  END i_row[113]
  PIN i_row[114]
    DIRECTION INPUT ;
    USE SIGNAL ;
    PORT
      LAYER M4 ;
        RECT  0 63.024 0.084 63.048 ;
    END
  END i_row[114]
  PIN i_row[115]
    DIRECTION INPUT ;
    USE SIGNAL ;
    PORT
      LAYER M4 ;
        RECT  0 63.456 0.084 63.48 ;
    END
  END i_row[115]
  PIN i_row[116]
    DIRECTION INPUT ;
    USE SIGNAL ;
    PORT
      LAYER M4 ;
        RECT  0 63.888 0.084 63.912 ;
    END
  END i_row[116]
  PIN i_row[117]
    DIRECTION INPUT ;
    USE SIGNAL ;
    PORT
      LAYER M4 ;
        RECT  0 64.32 0.084 64.344 ;
    END
  END i_row[117]
  PIN i_row[118]
    DIRECTION INPUT ;
    USE SIGNAL ;
    PORT
      LAYER M4 ;
        RECT  0 64.752 0.084 64.776 ;
    END
  END i_row[118]
  PIN i_row[119]
    DIRECTION INPUT ;
    USE SIGNAL ;
    PORT
      LAYER M4 ;
        RECT  0 65.184 0.084 65.208 ;
    END
  END i_row[119]
  PIN i_row[11]
    DIRECTION INPUT ;
    USE SIGNAL ;
    PORT
      LAYER M4 ;
        RECT  0 18.528 0.084 18.552 ;
    END
  END i_row[11]
  PIN i_row[120]
    DIRECTION INPUT ;
    USE SIGNAL ;
    PORT
      LAYER M4 ;
        RECT  0 65.616 0.084 65.64 ;
    END
  END i_row[120]
  PIN i_row[121]
    DIRECTION INPUT ;
    USE SIGNAL ;
    PORT
      LAYER M4 ;
        RECT  0 66.048 0.084 66.072 ;
    END
  END i_row[121]
  PIN i_row[122]
    DIRECTION INPUT ;
    USE SIGNAL ;
    PORT
      LAYER M4 ;
        RECT  0 66.48 0.084 66.504 ;
    END
  END i_row[122]
  PIN i_row[123]
    DIRECTION INPUT ;
    USE SIGNAL ;
    PORT
      LAYER M4 ;
        RECT  0 66.912 0.084 66.936 ;
    END
  END i_row[123]
  PIN i_row[124]
    DIRECTION INPUT ;
    USE SIGNAL ;
    PORT
      LAYER M4 ;
        RECT  0 67.344 0.084 67.368 ;
    END
  END i_row[124]
  PIN i_row[125]
    DIRECTION INPUT ;
    USE SIGNAL ;
    PORT
      LAYER M4 ;
        RECT  0 67.776 0.084 67.8 ;
    END
  END i_row[125]
  PIN i_row[126]
    DIRECTION INPUT ;
    USE SIGNAL ;
    PORT
      LAYER M4 ;
        RECT  0 68.208 0.084 68.232 ;
    END
  END i_row[126]
  PIN i_row[127]
    DIRECTION INPUT ;
    USE SIGNAL ;
    PORT
      LAYER M4 ;
        RECT  0 68.64 0.084 68.664 ;
    END
  END i_row[127]
  PIN i_row[128]
    DIRECTION INPUT ;
    USE SIGNAL ;
    PORT
      LAYER M4 ;
        RECT  0 69.072 0.084 69.096 ;
    END
  END i_row[128]
  PIN i_row[129]
    DIRECTION INPUT ;
    USE SIGNAL ;
    PORT
      LAYER M4 ;
        RECT  0 69.504 0.084 69.528 ;
    END
  END i_row[129]
  PIN i_row[12]
    DIRECTION INPUT ;
    USE SIGNAL ;
    PORT
      LAYER M4 ;
        RECT  0 18.96 0.084 18.984 ;
    END
  END i_row[12]
  PIN i_row[130]
    DIRECTION INPUT ;
    USE SIGNAL ;
    PORT
      LAYER M4 ;
        RECT  0 69.936 0.084 69.96 ;
    END
  END i_row[130]
  PIN i_row[131]
    DIRECTION INPUT ;
    USE SIGNAL ;
    PORT
      LAYER M4 ;
        RECT  0 70.368 0.084 70.392 ;
    END
  END i_row[131]
  PIN i_row[132]
    DIRECTION INPUT ;
    USE SIGNAL ;
    PORT
      LAYER M4 ;
        RECT  0 70.8 0.084 70.824 ;
    END
  END i_row[132]
  PIN i_row[133]
    DIRECTION INPUT ;
    USE SIGNAL ;
    PORT
      LAYER M4 ;
        RECT  0 71.232 0.084 71.256 ;
    END
  END i_row[133]
  PIN i_row[134]
    DIRECTION INPUT ;
    USE SIGNAL ;
    PORT
      LAYER M4 ;
        RECT  0 71.664 0.084 71.688 ;
    END
  END i_row[134]
  PIN i_row[135]
    DIRECTION INPUT ;
    USE SIGNAL ;
    PORT
      LAYER M4 ;
        RECT  0 72.096 0.084 72.12 ;
    END
  END i_row[135]
  PIN i_row[136]
    DIRECTION INPUT ;
    USE SIGNAL ;
    PORT
      LAYER M4 ;
        RECT  0 72.528 0.084 72.552 ;
    END
  END i_row[136]
  PIN i_row[137]
    DIRECTION INPUT ;
    USE SIGNAL ;
    PORT
      LAYER M4 ;
        RECT  0 72.96 0.084 72.984 ;
    END
  END i_row[137]
  PIN i_row[138]
    DIRECTION INPUT ;
    USE SIGNAL ;
    PORT
      LAYER M4 ;
        RECT  0 73.392 0.084 73.416 ;
    END
  END i_row[138]
  PIN i_row[139]
    DIRECTION INPUT ;
    USE SIGNAL ;
    PORT
      LAYER M4 ;
        RECT  0 73.824 0.084 73.848 ;
    END
  END i_row[139]
  PIN i_row[13]
    DIRECTION INPUT ;
    USE SIGNAL ;
    PORT
      LAYER M4 ;
        RECT  0 19.392 0.084 19.416 ;
    END
  END i_row[13]
  PIN i_row[140]
    DIRECTION INPUT ;
    USE SIGNAL ;
    PORT
      LAYER M4 ;
        RECT  0 74.256 0.084 74.28 ;
    END
  END i_row[140]
  PIN i_row[141]
    DIRECTION INPUT ;
    USE SIGNAL ;
    PORT
      LAYER M4 ;
        RECT  0 74.688 0.084 74.712 ;
    END
  END i_row[141]
  PIN i_row[142]
    DIRECTION INPUT ;
    USE SIGNAL ;
    PORT
      LAYER M4 ;
        RECT  0 75.12 0.084 75.144 ;
    END
  END i_row[142]
  PIN i_row[143]
    DIRECTION INPUT ;
    USE SIGNAL ;
    PORT
      LAYER M4 ;
        RECT  0 75.552 0.084 75.576 ;
    END
  END i_row[143]
  PIN i_row[144]
    DIRECTION INPUT ;
    USE SIGNAL ;
    PORT
      LAYER M4 ;
        RECT  0 75.984 0.084 76.008 ;
    END
  END i_row[144]
  PIN i_row[145]
    DIRECTION INPUT ;
    USE SIGNAL ;
    PORT
      LAYER M4 ;
        RECT  0 76.416 0.084 76.44 ;
    END
  END i_row[145]
  PIN i_row[146]
    DIRECTION INPUT ;
    USE SIGNAL ;
    PORT
      LAYER M4 ;
        RECT  0 76.848 0.084 76.872 ;
    END
  END i_row[146]
  PIN i_row[147]
    DIRECTION INPUT ;
    USE SIGNAL ;
    PORT
      LAYER M4 ;
        RECT  0 77.28 0.084 77.304 ;
    END
  END i_row[147]
  PIN i_row[148]
    DIRECTION INPUT ;
    USE SIGNAL ;
    PORT
      LAYER M4 ;
        RECT  0 77.712 0.084 77.736 ;
    END
  END i_row[148]
  PIN i_row[149]
    DIRECTION INPUT ;
    USE SIGNAL ;
    PORT
      LAYER M4 ;
        RECT  0 78.144 0.084 78.168 ;
    END
  END i_row[149]
  PIN i_row[14]
    DIRECTION INPUT ;
    USE SIGNAL ;
    PORT
      LAYER M4 ;
        RECT  0 19.824 0.084 19.848 ;
    END
  END i_row[14]
  PIN i_row[150]
    DIRECTION INPUT ;
    USE SIGNAL ;
    PORT
      LAYER M4 ;
        RECT  0 78.576 0.084 78.6 ;
    END
  END i_row[150]
  PIN i_row[151]
    DIRECTION INPUT ;
    USE SIGNAL ;
    PORT
      LAYER M4 ;
        RECT  0 79.008 0.084 79.032 ;
    END
  END i_row[151]
  PIN i_row[152]
    DIRECTION INPUT ;
    USE SIGNAL ;
    PORT
      LAYER M4 ;
        RECT  0 79.44 0.084 79.464 ;
    END
  END i_row[152]
  PIN i_row[153]
    DIRECTION INPUT ;
    USE SIGNAL ;
    PORT
      LAYER M4 ;
        RECT  0 79.872 0.084 79.896 ;
    END
  END i_row[153]
  PIN i_row[154]
    DIRECTION INPUT ;
    USE SIGNAL ;
    PORT
      LAYER M4 ;
        RECT  0 80.304 0.084 80.328 ;
    END
  END i_row[154]
  PIN i_row[155]
    DIRECTION INPUT ;
    USE SIGNAL ;
    PORT
      LAYER M4 ;
        RECT  0 80.736 0.084 80.76 ;
    END
  END i_row[155]
  PIN i_row[156]
    DIRECTION INPUT ;
    USE SIGNAL ;
    PORT
      LAYER M4 ;
        RECT  0 81.168 0.084 81.192 ;
    END
  END i_row[156]
  PIN i_row[157]
    DIRECTION INPUT ;
    USE SIGNAL ;
    PORT
      LAYER M4 ;
        RECT  0 81.6 0.084 81.624 ;
    END
  END i_row[157]
  PIN i_row[158]
    DIRECTION INPUT ;
    USE SIGNAL ;
    PORT
      LAYER M4 ;
        RECT  0 82.032 0.084 82.056 ;
    END
  END i_row[158]
  PIN i_row[159]
    DIRECTION INPUT ;
    USE SIGNAL ;
    PORT
      LAYER M4 ;
        RECT  0 82.464 0.084 82.488 ;
    END
  END i_row[159]
  PIN i_row[15]
    DIRECTION INPUT ;
    USE SIGNAL ;
    PORT
      LAYER M4 ;
        RECT  0 20.256 0.084 20.28 ;
    END
  END i_row[15]
  PIN i_row[160]
    DIRECTION INPUT ;
    USE SIGNAL ;
    PORT
      LAYER M4 ;
        RECT  0 82.896 0.084 82.92 ;
    END
  END i_row[160]
  PIN i_row[161]
    DIRECTION INPUT ;
    USE SIGNAL ;
    PORT
      LAYER M4 ;
        RECT  0 83.328 0.084 83.352 ;
    END
  END i_row[161]
  PIN i_row[162]
    DIRECTION INPUT ;
    USE SIGNAL ;
    PORT
      LAYER M4 ;
        RECT  0 83.76 0.084 83.784 ;
    END
  END i_row[162]
  PIN i_row[163]
    DIRECTION INPUT ;
    USE SIGNAL ;
    PORT
      LAYER M4 ;
        RECT  0 84.192 0.084 84.216 ;
    END
  END i_row[163]
  PIN i_row[164]
    DIRECTION INPUT ;
    USE SIGNAL ;
    PORT
      LAYER M4 ;
        RECT  0 84.624 0.084 84.648 ;
    END
  END i_row[164]
  PIN i_row[165]
    DIRECTION INPUT ;
    USE SIGNAL ;
    PORT
      LAYER M4 ;
        RECT  0 85.056 0.084 85.08 ;
    END
  END i_row[165]
  PIN i_row[166]
    DIRECTION INPUT ;
    USE SIGNAL ;
    PORT
      LAYER M4 ;
        RECT  0 85.488 0.084 85.512 ;
    END
  END i_row[166]
  PIN i_row[167]
    DIRECTION INPUT ;
    USE SIGNAL ;
    PORT
      LAYER M4 ;
        RECT  0 85.92 0.084 85.944 ;
    END
  END i_row[167]
  PIN i_row[168]
    DIRECTION INPUT ;
    USE SIGNAL ;
    PORT
      LAYER M4 ;
        RECT  0 86.352 0.084 86.376 ;
    END
  END i_row[168]
  PIN i_row[169]
    DIRECTION INPUT ;
    USE SIGNAL ;
    PORT
      LAYER M4 ;
        RECT  0 86.784 0.084 86.808 ;
    END
  END i_row[169]
  PIN i_row[16]
    DIRECTION INPUT ;
    USE SIGNAL ;
    PORT
      LAYER M4 ;
        RECT  0 20.688 0.084 20.712 ;
    END
  END i_row[16]
  PIN i_row[170]
    DIRECTION INPUT ;
    USE SIGNAL ;
    PORT
      LAYER M4 ;
        RECT  0 87.216 0.084 87.24 ;
    END
  END i_row[170]
  PIN i_row[171]
    DIRECTION INPUT ;
    USE SIGNAL ;
    PORT
      LAYER M4 ;
        RECT  0 87.648 0.084 87.672 ;
    END
  END i_row[171]
  PIN i_row[172]
    DIRECTION INPUT ;
    USE SIGNAL ;
    PORT
      LAYER M4 ;
        RECT  0 88.08 0.084 88.104 ;
    END
  END i_row[172]
  PIN i_row[173]
    DIRECTION INPUT ;
    USE SIGNAL ;
    PORT
      LAYER M4 ;
        RECT  0 88.512 0.084 88.536 ;
    END
  END i_row[173]
  PIN i_row[174]
    DIRECTION INPUT ;
    USE SIGNAL ;
    PORT
      LAYER M4 ;
        RECT  0 88.944 0.084 88.968 ;
    END
  END i_row[174]
  PIN i_row[175]
    DIRECTION INPUT ;
    USE SIGNAL ;
    PORT
      LAYER M4 ;
        RECT  0 89.376 0.084 89.4 ;
    END
  END i_row[175]
  PIN i_row[176]
    DIRECTION INPUT ;
    USE SIGNAL ;
    PORT
      LAYER M4 ;
        RECT  0 89.808 0.084 89.832 ;
    END
  END i_row[176]
  PIN i_row[177]
    DIRECTION INPUT ;
    USE SIGNAL ;
    PORT
      LAYER M4 ;
        RECT  0 90.24 0.084 90.264 ;
    END
  END i_row[177]
  PIN i_row[178]
    DIRECTION INPUT ;
    USE SIGNAL ;
    PORT
      LAYER M4 ;
        RECT  0 90.672 0.084 90.696 ;
    END
  END i_row[178]
  PIN i_row[179]
    DIRECTION INPUT ;
    USE SIGNAL ;
    PORT
      LAYER M4 ;
        RECT  0 91.104 0.084 91.128 ;
    END
  END i_row[179]
  PIN i_row[17]
    DIRECTION INPUT ;
    USE SIGNAL ;
    PORT
      LAYER M4 ;
        RECT  0 21.12 0.084 21.144 ;
    END
  END i_row[17]
  PIN i_row[180]
    DIRECTION INPUT ;
    USE SIGNAL ;
    PORT
      LAYER M4 ;
        RECT  0 91.536 0.084 91.56 ;
    END
  END i_row[180]
  PIN i_row[181]
    DIRECTION INPUT ;
    USE SIGNAL ;
    PORT
      LAYER M4 ;
        RECT  0 91.968 0.084 91.992 ;
    END
  END i_row[181]
  PIN i_row[182]
    DIRECTION INPUT ;
    USE SIGNAL ;
    PORT
      LAYER M4 ;
        RECT  0 92.4 0.084 92.424 ;
    END
  END i_row[182]
  PIN i_row[183]
    DIRECTION INPUT ;
    USE SIGNAL ;
    PORT
      LAYER M4 ;
        RECT  0 92.832 0.084 92.856 ;
    END
  END i_row[183]
  PIN i_row[184]
    DIRECTION INPUT ;
    USE SIGNAL ;
    PORT
      LAYER M4 ;
        RECT  0 93.264 0.084 93.288 ;
    END
  END i_row[184]
  PIN i_row[185]
    DIRECTION INPUT ;
    USE SIGNAL ;
    PORT
      LAYER M4 ;
        RECT  0 93.696 0.084 93.72 ;
    END
  END i_row[185]
  PIN i_row[186]
    DIRECTION INPUT ;
    USE SIGNAL ;
    PORT
      LAYER M4 ;
        RECT  0 94.128 0.084 94.152 ;
    END
  END i_row[186]
  PIN i_row[187]
    DIRECTION INPUT ;
    USE SIGNAL ;
    PORT
      LAYER M4 ;
        RECT  0 94.56 0.084 94.584 ;
    END
  END i_row[187]
  PIN i_row[188]
    DIRECTION INPUT ;
    USE SIGNAL ;
    PORT
      LAYER M4 ;
        RECT  0 94.992 0.084 95.016 ;
    END
  END i_row[188]
  PIN i_row[189]
    DIRECTION INPUT ;
    USE SIGNAL ;
    PORT
      LAYER M4 ;
        RECT  0 95.424 0.084 95.448 ;
    END
  END i_row[189]
  PIN i_row[18]
    DIRECTION INPUT ;
    USE SIGNAL ;
    PORT
      LAYER M4 ;
        RECT  0 21.552 0.084 21.576 ;
    END
  END i_row[18]
  PIN i_row[190]
    DIRECTION INPUT ;
    USE SIGNAL ;
    PORT
      LAYER M4 ;
        RECT  0 95.856 0.084 95.88 ;
    END
  END i_row[190]
  PIN i_row[191]
    DIRECTION INPUT ;
    USE SIGNAL ;
    PORT
      LAYER M4 ;
        RECT  0 96.288 0.084 96.312 ;
    END
  END i_row[191]
  PIN i_row[192]
    DIRECTION INPUT ;
    USE SIGNAL ;
    PORT
      LAYER M4 ;
        RECT  0 96.72 0.084 96.744 ;
    END
  END i_row[192]
  PIN i_row[193]
    DIRECTION INPUT ;
    USE SIGNAL ;
    PORT
      LAYER M4 ;
        RECT  0 97.152 0.084 97.176 ;
    END
  END i_row[193]
  PIN i_row[194]
    DIRECTION INPUT ;
    USE SIGNAL ;
    PORT
      LAYER M4 ;
        RECT  0 97.584 0.084 97.608 ;
    END
  END i_row[194]
  PIN i_row[195]
    DIRECTION INPUT ;
    USE SIGNAL ;
    PORT
      LAYER M4 ;
        RECT  0 98.016 0.084 98.04 ;
    END
  END i_row[195]
  PIN i_row[196]
    DIRECTION INPUT ;
    USE SIGNAL ;
    PORT
      LAYER M4 ;
        RECT  0 98.448 0.084 98.472 ;
    END
  END i_row[196]
  PIN i_row[197]
    DIRECTION INPUT ;
    USE SIGNAL ;
    PORT
      LAYER M4 ;
        RECT  0 98.88 0.084 98.904 ;
    END
  END i_row[197]
  PIN i_row[198]
    DIRECTION INPUT ;
    USE SIGNAL ;
    PORT
      LAYER M4 ;
        RECT  0 99.312 0.084 99.336 ;
    END
  END i_row[198]
  PIN i_row[199]
    DIRECTION INPUT ;
    USE SIGNAL ;
    PORT
      LAYER M4 ;
        RECT  0 99.744 0.084 99.768 ;
    END
  END i_row[199]
  PIN i_row[19]
    DIRECTION INPUT ;
    USE SIGNAL ;
    PORT
      LAYER M4 ;
        RECT  0 21.984 0.084 22.008 ;
    END
  END i_row[19]
  PIN i_row[1]
    DIRECTION INPUT ;
    USE SIGNAL ;
    PORT
      LAYER M4 ;
        RECT  0 14.208 0.084 14.232 ;
    END
  END i_row[1]
  PIN i_row[200]
    DIRECTION INPUT ;
    USE SIGNAL ;
    PORT
      LAYER M4 ;
        RECT  0 100.176 0.084 100.2 ;
    END
  END i_row[200]
  PIN i_row[201]
    DIRECTION INPUT ;
    USE SIGNAL ;
    PORT
      LAYER M4 ;
        RECT  0 100.608 0.084 100.632 ;
    END
  END i_row[201]
  PIN i_row[202]
    DIRECTION INPUT ;
    USE SIGNAL ;
    PORT
      LAYER M4 ;
        RECT  0 101.04 0.084 101.064 ;
    END
  END i_row[202]
  PIN i_row[203]
    DIRECTION INPUT ;
    USE SIGNAL ;
    PORT
      LAYER M4 ;
        RECT  0 101.472 0.084 101.496 ;
    END
  END i_row[203]
  PIN i_row[204]
    DIRECTION INPUT ;
    USE SIGNAL ;
    PORT
      LAYER M4 ;
        RECT  0 101.904 0.084 101.928 ;
    END
  END i_row[204]
  PIN i_row[205]
    DIRECTION INPUT ;
    USE SIGNAL ;
    PORT
      LAYER M4 ;
        RECT  0 102.336 0.084 102.36 ;
    END
  END i_row[205]
  PIN i_row[206]
    DIRECTION INPUT ;
    USE SIGNAL ;
    PORT
      LAYER M4 ;
        RECT  0 102.768 0.084 102.792 ;
    END
  END i_row[206]
  PIN i_row[207]
    DIRECTION INPUT ;
    USE SIGNAL ;
    PORT
      LAYER M4 ;
        RECT  0 103.2 0.084 103.224 ;
    END
  END i_row[207]
  PIN i_row[208]
    DIRECTION INPUT ;
    USE SIGNAL ;
    PORT
      LAYER M4 ;
        RECT  0 103.632 0.084 103.656 ;
    END
  END i_row[208]
  PIN i_row[209]
    DIRECTION INPUT ;
    USE SIGNAL ;
    PORT
      LAYER M4 ;
        RECT  0 104.064 0.084 104.088 ;
    END
  END i_row[209]
  PIN i_row[20]
    DIRECTION INPUT ;
    USE SIGNAL ;
    PORT
      LAYER M4 ;
        RECT  0 22.416 0.084 22.44 ;
    END
  END i_row[20]
  PIN i_row[210]
    DIRECTION INPUT ;
    USE SIGNAL ;
    PORT
      LAYER M4 ;
        RECT  0 104.496 0.084 104.52 ;
    END
  END i_row[210]
  PIN i_row[211]
    DIRECTION INPUT ;
    USE SIGNAL ;
    PORT
      LAYER M4 ;
        RECT  0 104.928 0.084 104.952 ;
    END
  END i_row[211]
  PIN i_row[212]
    DIRECTION INPUT ;
    USE SIGNAL ;
    PORT
      LAYER M4 ;
        RECT  0 105.36 0.084 105.384 ;
    END
  END i_row[212]
  PIN i_row[213]
    DIRECTION INPUT ;
    USE SIGNAL ;
    PORT
      LAYER M4 ;
        RECT  0 105.792 0.084 105.816 ;
    END
  END i_row[213]
  PIN i_row[214]
    DIRECTION INPUT ;
    USE SIGNAL ;
    PORT
      LAYER M4 ;
        RECT  0 106.224 0.084 106.248 ;
    END
  END i_row[214]
  PIN i_row[215]
    DIRECTION INPUT ;
    USE SIGNAL ;
    PORT
      LAYER M4 ;
        RECT  0 106.656 0.084 106.68 ;
    END
  END i_row[215]
  PIN i_row[216]
    DIRECTION INPUT ;
    USE SIGNAL ;
    PORT
      LAYER M4 ;
        RECT  0 107.088 0.084 107.112 ;
    END
  END i_row[216]
  PIN i_row[217]
    DIRECTION INPUT ;
    USE SIGNAL ;
    PORT
      LAYER M4 ;
        RECT  0 107.52 0.084 107.544 ;
    END
  END i_row[217]
  PIN i_row[218]
    DIRECTION INPUT ;
    USE SIGNAL ;
    PORT
      LAYER M4 ;
        RECT  0 107.952 0.084 107.976 ;
    END
  END i_row[218]
  PIN i_row[219]
    DIRECTION INPUT ;
    USE SIGNAL ;
    PORT
      LAYER M4 ;
        RECT  0 108.384 0.084 108.408 ;
    END
  END i_row[219]
  PIN i_row[21]
    DIRECTION INPUT ;
    USE SIGNAL ;
    PORT
      LAYER M4 ;
        RECT  0 22.848 0.084 22.872 ;
    END
  END i_row[21]
  PIN i_row[220]
    DIRECTION INPUT ;
    USE SIGNAL ;
    PORT
      LAYER M4 ;
        RECT  0 108.816 0.084 108.84 ;
    END
  END i_row[220]
  PIN i_row[221]
    DIRECTION INPUT ;
    USE SIGNAL ;
    PORT
      LAYER M4 ;
        RECT  0 109.248 0.084 109.272 ;
    END
  END i_row[221]
  PIN i_row[222]
    DIRECTION INPUT ;
    USE SIGNAL ;
    PORT
      LAYER M4 ;
        RECT  0 109.68 0.084 109.704 ;
    END
  END i_row[222]
  PIN i_row[223]
    DIRECTION INPUT ;
    USE SIGNAL ;
    PORT
      LAYER M4 ;
        RECT  0 110.112 0.084 110.136 ;
    END
  END i_row[223]
  PIN i_row[224]
    DIRECTION INPUT ;
    USE SIGNAL ;
    PORT
      LAYER M4 ;
        RECT  0 110.544 0.084 110.568 ;
    END
  END i_row[224]
  PIN i_row[225]
    DIRECTION INPUT ;
    USE SIGNAL ;
    PORT
      LAYER M4 ;
        RECT  0 110.976 0.084 111 ;
    END
  END i_row[225]
  PIN i_row[226]
    DIRECTION INPUT ;
    USE SIGNAL ;
    PORT
      LAYER M4 ;
        RECT  0 111.408 0.084 111.432 ;
    END
  END i_row[226]
  PIN i_row[227]
    DIRECTION INPUT ;
    USE SIGNAL ;
    PORT
      LAYER M4 ;
        RECT  0 111.84 0.084 111.864 ;
    END
  END i_row[227]
  PIN i_row[228]
    DIRECTION INPUT ;
    USE SIGNAL ;
    PORT
      LAYER M4 ;
        RECT  0 112.272 0.084 112.296 ;
    END
  END i_row[228]
  PIN i_row[229]
    DIRECTION INPUT ;
    USE SIGNAL ;
    PORT
      LAYER M4 ;
        RECT  0 112.704 0.084 112.728 ;
    END
  END i_row[229]
  PIN i_row[22]
    DIRECTION INPUT ;
    USE SIGNAL ;
    PORT
      LAYER M4 ;
        RECT  0 23.28 0.084 23.304 ;
    END
  END i_row[22]
  PIN i_row[230]
    DIRECTION INPUT ;
    USE SIGNAL ;
    PORT
      LAYER M4 ;
        RECT  0 113.136 0.084 113.16 ;
    END
  END i_row[230]
  PIN i_row[231]
    DIRECTION INPUT ;
    USE SIGNAL ;
    PORT
      LAYER M4 ;
        RECT  0 113.568 0.084 113.592 ;
    END
  END i_row[231]
  PIN i_row[232]
    DIRECTION INPUT ;
    USE SIGNAL ;
    PORT
      LAYER M4 ;
        RECT  0 114 0.084 114.024 ;
    END
  END i_row[232]
  PIN i_row[233]
    DIRECTION INPUT ;
    USE SIGNAL ;
    PORT
      LAYER M4 ;
        RECT  0 114.432 0.084 114.456 ;
    END
  END i_row[233]
  PIN i_row[234]
    DIRECTION INPUT ;
    USE SIGNAL ;
    PORT
      LAYER M4 ;
        RECT  0 114.864 0.084 114.888 ;
    END
  END i_row[234]
  PIN i_row[235]
    DIRECTION INPUT ;
    USE SIGNAL ;
    PORT
      LAYER M4 ;
        RECT  0 115.296 0.084 115.32 ;
    END
  END i_row[235]
  PIN i_row[236]
    DIRECTION INPUT ;
    USE SIGNAL ;
    PORT
      LAYER M4 ;
        RECT  0 115.728 0.084 115.752 ;
    END
  END i_row[236]
  PIN i_row[237]
    DIRECTION INPUT ;
    USE SIGNAL ;
    PORT
      LAYER M4 ;
        RECT  0 116.16 0.084 116.184 ;
    END
  END i_row[237]
  PIN i_row[238]
    DIRECTION INPUT ;
    USE SIGNAL ;
    PORT
      LAYER M4 ;
        RECT  0 116.592 0.084 116.616 ;
    END
  END i_row[238]
  PIN i_row[239]
    DIRECTION INPUT ;
    USE SIGNAL ;
    PORT
      LAYER M4 ;
        RECT  0 117.024 0.084 117.048 ;
    END
  END i_row[239]
  PIN i_row[23]
    DIRECTION INPUT ;
    USE SIGNAL ;
    PORT
      LAYER M4 ;
        RECT  0 23.712 0.084 23.736 ;
    END
  END i_row[23]
  PIN i_row[240]
    DIRECTION INPUT ;
    USE SIGNAL ;
    PORT
      LAYER M4 ;
        RECT  0 117.456 0.084 117.48 ;
    END
  END i_row[240]
  PIN i_row[241]
    DIRECTION INPUT ;
    USE SIGNAL ;
    PORT
      LAYER M4 ;
        RECT  0 117.888 0.084 117.912 ;
    END
  END i_row[241]
  PIN i_row[242]
    DIRECTION INPUT ;
    USE SIGNAL ;
    PORT
      LAYER M4 ;
        RECT  0 118.32 0.084 118.344 ;
    END
  END i_row[242]
  PIN i_row[243]
    DIRECTION INPUT ;
    USE SIGNAL ;
    PORT
      LAYER M4 ;
        RECT  0 118.752 0.084 118.776 ;
    END
  END i_row[243]
  PIN i_row[244]
    DIRECTION INPUT ;
    USE SIGNAL ;
    PORT
      LAYER M4 ;
        RECT  0 119.184 0.084 119.208 ;
    END
  END i_row[244]
  PIN i_row[245]
    DIRECTION INPUT ;
    USE SIGNAL ;
    PORT
      LAYER M4 ;
        RECT  0 119.616 0.084 119.64 ;
    END
  END i_row[245]
  PIN i_row[246]
    DIRECTION INPUT ;
    USE SIGNAL ;
    PORT
      LAYER M4 ;
        RECT  0 120.048 0.084 120.072 ;
    END
  END i_row[246]
  PIN i_row[247]
    DIRECTION INPUT ;
    USE SIGNAL ;
    PORT
      LAYER M4 ;
        RECT  0 120.48 0.084 120.504 ;
    END
  END i_row[247]
  PIN i_row[248]
    DIRECTION INPUT ;
    USE SIGNAL ;
    PORT
      LAYER M4 ;
        RECT  0 120.912 0.084 120.936 ;
    END
  END i_row[248]
  PIN i_row[249]
    DIRECTION INPUT ;
    USE SIGNAL ;
    PORT
      LAYER M4 ;
        RECT  0 121.344 0.084 121.368 ;
    END
  END i_row[249]
  PIN i_row[24]
    DIRECTION INPUT ;
    USE SIGNAL ;
    PORT
      LAYER M4 ;
        RECT  0 24.144 0.084 24.168 ;
    END
  END i_row[24]
  PIN i_row[250]
    DIRECTION INPUT ;
    USE SIGNAL ;
    PORT
      LAYER M4 ;
        RECT  0 121.776 0.084 121.8 ;
    END
  END i_row[250]
  PIN i_row[251]
    DIRECTION INPUT ;
    USE SIGNAL ;
    PORT
      LAYER M4 ;
        RECT  0 122.208 0.084 122.232 ;
    END
  END i_row[251]
  PIN i_row[25]
    DIRECTION INPUT ;
    USE SIGNAL ;
    PORT
      LAYER M4 ;
        RECT  0 24.576 0.084 24.6 ;
    END
  END i_row[25]
  PIN i_row[26]
    DIRECTION INPUT ;
    USE SIGNAL ;
    PORT
      LAYER M4 ;
        RECT  0 25.008 0.084 25.032 ;
    END
  END i_row[26]
  PIN i_row[27]
    DIRECTION INPUT ;
    USE SIGNAL ;
    PORT
      LAYER M4 ;
        RECT  0 25.44 0.084 25.464 ;
    END
  END i_row[27]
  PIN i_row[28]
    DIRECTION INPUT ;
    USE SIGNAL ;
    PORT
      LAYER M4 ;
        RECT  0 25.872 0.084 25.896 ;
    END
  END i_row[28]
  PIN i_row[29]
    DIRECTION INPUT ;
    USE SIGNAL ;
    PORT
      LAYER M4 ;
        RECT  0 26.304 0.084 26.328 ;
    END
  END i_row[29]
  PIN i_row[2]
    DIRECTION INPUT ;
    USE SIGNAL ;
    PORT
      LAYER M4 ;
        RECT  0 14.64 0.084 14.664 ;
    END
  END i_row[2]
  PIN i_row[30]
    DIRECTION INPUT ;
    USE SIGNAL ;
    PORT
      LAYER M4 ;
        RECT  0 26.736 0.084 26.76 ;
    END
  END i_row[30]
  PIN i_row[31]
    DIRECTION INPUT ;
    USE SIGNAL ;
    PORT
      LAYER M4 ;
        RECT  0 27.168 0.084 27.192 ;
    END
  END i_row[31]
  PIN i_row[32]
    DIRECTION INPUT ;
    USE SIGNAL ;
    PORT
      LAYER M4 ;
        RECT  0 27.6 0.084 27.624 ;
    END
  END i_row[32]
  PIN i_row[33]
    DIRECTION INPUT ;
    USE SIGNAL ;
    PORT
      LAYER M4 ;
        RECT  0 28.032 0.084 28.056 ;
    END
  END i_row[33]
  PIN i_row[34]
    DIRECTION INPUT ;
    USE SIGNAL ;
    PORT
      LAYER M4 ;
        RECT  0 28.464 0.084 28.488 ;
    END
  END i_row[34]
  PIN i_row[35]
    DIRECTION INPUT ;
    USE SIGNAL ;
    PORT
      LAYER M4 ;
        RECT  0 28.896 0.084 28.92 ;
    END
  END i_row[35]
  PIN i_row[36]
    DIRECTION INPUT ;
    USE SIGNAL ;
    PORT
      LAYER M4 ;
        RECT  0 29.328 0.084 29.352 ;
    END
  END i_row[36]
  PIN i_row[37]
    DIRECTION INPUT ;
    USE SIGNAL ;
    PORT
      LAYER M4 ;
        RECT  0 29.76 0.084 29.784 ;
    END
  END i_row[37]
  PIN i_row[38]
    DIRECTION INPUT ;
    USE SIGNAL ;
    PORT
      LAYER M4 ;
        RECT  0 30.192 0.084 30.216 ;
    END
  END i_row[38]
  PIN i_row[39]
    DIRECTION INPUT ;
    USE SIGNAL ;
    PORT
      LAYER M4 ;
        RECT  0 30.624 0.084 30.648 ;
    END
  END i_row[39]
  PIN i_row[3]
    DIRECTION INPUT ;
    USE SIGNAL ;
    PORT
      LAYER M4 ;
        RECT  0 15.072 0.084 15.096 ;
    END
  END i_row[3]
  PIN i_row[40]
    DIRECTION INPUT ;
    USE SIGNAL ;
    PORT
      LAYER M4 ;
        RECT  0 31.056 0.084 31.08 ;
    END
  END i_row[40]
  PIN i_row[41]
    DIRECTION INPUT ;
    USE SIGNAL ;
    PORT
      LAYER M4 ;
        RECT  0 31.488 0.084 31.512 ;
    END
  END i_row[41]
  PIN i_row[42]
    DIRECTION INPUT ;
    USE SIGNAL ;
    PORT
      LAYER M4 ;
        RECT  0 31.92 0.084 31.944 ;
    END
  END i_row[42]
  PIN i_row[43]
    DIRECTION INPUT ;
    USE SIGNAL ;
    PORT
      LAYER M4 ;
        RECT  0 32.352 0.084 32.376 ;
    END
  END i_row[43]
  PIN i_row[44]
    DIRECTION INPUT ;
    USE SIGNAL ;
    PORT
      LAYER M4 ;
        RECT  0 32.784 0.084 32.808 ;
    END
  END i_row[44]
  PIN i_row[45]
    DIRECTION INPUT ;
    USE SIGNAL ;
    PORT
      LAYER M4 ;
        RECT  0 33.216 0.084 33.24 ;
    END
  END i_row[45]
  PIN i_row[46]
    DIRECTION INPUT ;
    USE SIGNAL ;
    PORT
      LAYER M4 ;
        RECT  0 33.648 0.084 33.672 ;
    END
  END i_row[46]
  PIN i_row[47]
    DIRECTION INPUT ;
    USE SIGNAL ;
    PORT
      LAYER M4 ;
        RECT  0 34.08 0.084 34.104 ;
    END
  END i_row[47]
  PIN i_row[48]
    DIRECTION INPUT ;
    USE SIGNAL ;
    PORT
      LAYER M4 ;
        RECT  0 34.512 0.084 34.536 ;
    END
  END i_row[48]
  PIN i_row[49]
    DIRECTION INPUT ;
    USE SIGNAL ;
    PORT
      LAYER M4 ;
        RECT  0 34.944 0.084 34.968 ;
    END
  END i_row[49]
  PIN i_row[4]
    DIRECTION INPUT ;
    USE SIGNAL ;
    PORT
      LAYER M4 ;
        RECT  0 15.504 0.084 15.528 ;
    END
  END i_row[4]
  PIN i_row[50]
    DIRECTION INPUT ;
    USE SIGNAL ;
    PORT
      LAYER M4 ;
        RECT  0 35.376 0.084 35.4 ;
    END
  END i_row[50]
  PIN i_row[51]
    DIRECTION INPUT ;
    USE SIGNAL ;
    PORT
      LAYER M4 ;
        RECT  0 35.808 0.084 35.832 ;
    END
  END i_row[51]
  PIN i_row[52]
    DIRECTION INPUT ;
    USE SIGNAL ;
    PORT
      LAYER M4 ;
        RECT  0 36.24 0.084 36.264 ;
    END
  END i_row[52]
  PIN i_row[53]
    DIRECTION INPUT ;
    USE SIGNAL ;
    PORT
      LAYER M4 ;
        RECT  0 36.672 0.084 36.696 ;
    END
  END i_row[53]
  PIN i_row[54]
    DIRECTION INPUT ;
    USE SIGNAL ;
    PORT
      LAYER M4 ;
        RECT  0 37.104 0.084 37.128 ;
    END
  END i_row[54]
  PIN i_row[55]
    DIRECTION INPUT ;
    USE SIGNAL ;
    PORT
      LAYER M4 ;
        RECT  0 37.536 0.084 37.56 ;
    END
  END i_row[55]
  PIN i_row[56]
    DIRECTION INPUT ;
    USE SIGNAL ;
    PORT
      LAYER M4 ;
        RECT  0 37.968 0.084 37.992 ;
    END
  END i_row[56]
  PIN i_row[57]
    DIRECTION INPUT ;
    USE SIGNAL ;
    PORT
      LAYER M4 ;
        RECT  0 38.4 0.084 38.424 ;
    END
  END i_row[57]
  PIN i_row[58]
    DIRECTION INPUT ;
    USE SIGNAL ;
    PORT
      LAYER M4 ;
        RECT  0 38.832 0.084 38.856 ;
    END
  END i_row[58]
  PIN i_row[59]
    DIRECTION INPUT ;
    USE SIGNAL ;
    PORT
      LAYER M4 ;
        RECT  0 39.264 0.084 39.288 ;
    END
  END i_row[59]
  PIN i_row[5]
    DIRECTION INPUT ;
    USE SIGNAL ;
    PORT
      LAYER M4 ;
        RECT  0 15.936 0.084 15.96 ;
    END
  END i_row[5]
  PIN i_row[60]
    DIRECTION INPUT ;
    USE SIGNAL ;
    PORT
      LAYER M4 ;
        RECT  0 39.696 0.084 39.72 ;
    END
  END i_row[60]
  PIN i_row[61]
    DIRECTION INPUT ;
    USE SIGNAL ;
    PORT
      LAYER M4 ;
        RECT  0 40.128 0.084 40.152 ;
    END
  END i_row[61]
  PIN i_row[62]
    DIRECTION INPUT ;
    USE SIGNAL ;
    PORT
      LAYER M4 ;
        RECT  0 40.56 0.084 40.584 ;
    END
  END i_row[62]
  PIN i_row[63]
    DIRECTION INPUT ;
    USE SIGNAL ;
    PORT
      LAYER M4 ;
        RECT  0 40.992 0.084 41.016 ;
    END
  END i_row[63]
  PIN i_row[64]
    DIRECTION INPUT ;
    USE SIGNAL ;
    PORT
      LAYER M4 ;
        RECT  0 41.424 0.084 41.448 ;
    END
  END i_row[64]
  PIN i_row[65]
    DIRECTION INPUT ;
    USE SIGNAL ;
    PORT
      LAYER M4 ;
        RECT  0 41.856 0.084 41.88 ;
    END
  END i_row[65]
  PIN i_row[66]
    DIRECTION INPUT ;
    USE SIGNAL ;
    PORT
      LAYER M4 ;
        RECT  0 42.288 0.084 42.312 ;
    END
  END i_row[66]
  PIN i_row[67]
    DIRECTION INPUT ;
    USE SIGNAL ;
    PORT
      LAYER M4 ;
        RECT  0 42.72 0.084 42.744 ;
    END
  END i_row[67]
  PIN i_row[68]
    DIRECTION INPUT ;
    USE SIGNAL ;
    PORT
      LAYER M4 ;
        RECT  0 43.152 0.084 43.176 ;
    END
  END i_row[68]
  PIN i_row[69]
    DIRECTION INPUT ;
    USE SIGNAL ;
    PORT
      LAYER M4 ;
        RECT  0 43.584 0.084 43.608 ;
    END
  END i_row[69]
  PIN i_row[6]
    DIRECTION INPUT ;
    USE SIGNAL ;
    PORT
      LAYER M4 ;
        RECT  0 16.368 0.084 16.392 ;
    END
  END i_row[6]
  PIN i_row[70]
    DIRECTION INPUT ;
    USE SIGNAL ;
    PORT
      LAYER M4 ;
        RECT  0 44.016 0.084 44.04 ;
    END
  END i_row[70]
  PIN i_row[71]
    DIRECTION INPUT ;
    USE SIGNAL ;
    PORT
      LAYER M4 ;
        RECT  0 44.448 0.084 44.472 ;
    END
  END i_row[71]
  PIN i_row[72]
    DIRECTION INPUT ;
    USE SIGNAL ;
    PORT
      LAYER M4 ;
        RECT  0 44.88 0.084 44.904 ;
    END
  END i_row[72]
  PIN i_row[73]
    DIRECTION INPUT ;
    USE SIGNAL ;
    PORT
      LAYER M4 ;
        RECT  0 45.312 0.084 45.336 ;
    END
  END i_row[73]
  PIN i_row[74]
    DIRECTION INPUT ;
    USE SIGNAL ;
    PORT
      LAYER M4 ;
        RECT  0 45.744 0.084 45.768 ;
    END
  END i_row[74]
  PIN i_row[75]
    DIRECTION INPUT ;
    USE SIGNAL ;
    PORT
      LAYER M4 ;
        RECT  0 46.176 0.084 46.2 ;
    END
  END i_row[75]
  PIN i_row[76]
    DIRECTION INPUT ;
    USE SIGNAL ;
    PORT
      LAYER M4 ;
        RECT  0 46.608 0.084 46.632 ;
    END
  END i_row[76]
  PIN i_row[77]
    DIRECTION INPUT ;
    USE SIGNAL ;
    PORT
      LAYER M4 ;
        RECT  0 47.04 0.084 47.064 ;
    END
  END i_row[77]
  PIN i_row[78]
    DIRECTION INPUT ;
    USE SIGNAL ;
    PORT
      LAYER M4 ;
        RECT  0 47.472 0.084 47.496 ;
    END
  END i_row[78]
  PIN i_row[79]
    DIRECTION INPUT ;
    USE SIGNAL ;
    PORT
      LAYER M4 ;
        RECT  0 47.904 0.084 47.928 ;
    END
  END i_row[79]
  PIN i_row[7]
    DIRECTION INPUT ;
    USE SIGNAL ;
    PORT
      LAYER M4 ;
        RECT  0 16.8 0.084 16.824 ;
    END
  END i_row[7]
  PIN i_row[80]
    DIRECTION INPUT ;
    USE SIGNAL ;
    PORT
      LAYER M4 ;
        RECT  0 48.336 0.084 48.36 ;
    END
  END i_row[80]
  PIN i_row[81]
    DIRECTION INPUT ;
    USE SIGNAL ;
    PORT
      LAYER M4 ;
        RECT  0 48.768 0.084 48.792 ;
    END
  END i_row[81]
  PIN i_row[82]
    DIRECTION INPUT ;
    USE SIGNAL ;
    PORT
      LAYER M4 ;
        RECT  0 49.2 0.084 49.224 ;
    END
  END i_row[82]
  PIN i_row[83]
    DIRECTION INPUT ;
    USE SIGNAL ;
    PORT
      LAYER M4 ;
        RECT  0 49.632 0.084 49.656 ;
    END
  END i_row[83]
  PIN i_row[84]
    DIRECTION INPUT ;
    USE SIGNAL ;
    PORT
      LAYER M4 ;
        RECT  0 50.064 0.084 50.088 ;
    END
  END i_row[84]
  PIN i_row[85]
    DIRECTION INPUT ;
    USE SIGNAL ;
    PORT
      LAYER M4 ;
        RECT  0 50.496 0.084 50.52 ;
    END
  END i_row[85]
  PIN i_row[86]
    DIRECTION INPUT ;
    USE SIGNAL ;
    PORT
      LAYER M4 ;
        RECT  0 50.928 0.084 50.952 ;
    END
  END i_row[86]
  PIN i_row[87]
    DIRECTION INPUT ;
    USE SIGNAL ;
    PORT
      LAYER M4 ;
        RECT  0 51.36 0.084 51.384 ;
    END
  END i_row[87]
  PIN i_row[88]
    DIRECTION INPUT ;
    USE SIGNAL ;
    PORT
      LAYER M4 ;
        RECT  0 51.792 0.084 51.816 ;
    END
  END i_row[88]
  PIN i_row[89]
    DIRECTION INPUT ;
    USE SIGNAL ;
    PORT
      LAYER M4 ;
        RECT  0 52.224 0.084 52.248 ;
    END
  END i_row[89]
  PIN i_row[8]
    DIRECTION INPUT ;
    USE SIGNAL ;
    PORT
      LAYER M4 ;
        RECT  0 17.232 0.084 17.256 ;
    END
  END i_row[8]
  PIN i_row[90]
    DIRECTION INPUT ;
    USE SIGNAL ;
    PORT
      LAYER M4 ;
        RECT  0 52.656 0.084 52.68 ;
    END
  END i_row[90]
  PIN i_row[91]
    DIRECTION INPUT ;
    USE SIGNAL ;
    PORT
      LAYER M4 ;
        RECT  0 53.088 0.084 53.112 ;
    END
  END i_row[91]
  PIN i_row[92]
    DIRECTION INPUT ;
    USE SIGNAL ;
    PORT
      LAYER M4 ;
        RECT  0 53.52 0.084 53.544 ;
    END
  END i_row[92]
  PIN i_row[93]
    DIRECTION INPUT ;
    USE SIGNAL ;
    PORT
      LAYER M4 ;
        RECT  0 53.952 0.084 53.976 ;
    END
  END i_row[93]
  PIN i_row[94]
    DIRECTION INPUT ;
    USE SIGNAL ;
    PORT
      LAYER M4 ;
        RECT  0 54.384 0.084 54.408 ;
    END
  END i_row[94]
  PIN i_row[95]
    DIRECTION INPUT ;
    USE SIGNAL ;
    PORT
      LAYER M4 ;
        RECT  0 54.816 0.084 54.84 ;
    END
  END i_row[95]
  PIN i_row[96]
    DIRECTION INPUT ;
    USE SIGNAL ;
    PORT
      LAYER M4 ;
        RECT  0 55.248 0.084 55.272 ;
    END
  END i_row[96]
  PIN i_row[97]
    DIRECTION INPUT ;
    USE SIGNAL ;
    PORT
      LAYER M4 ;
        RECT  0 55.68 0.084 55.704 ;
    END
  END i_row[97]
  PIN i_row[98]
    DIRECTION INPUT ;
    USE SIGNAL ;
    PORT
      LAYER M4 ;
        RECT  0 56.112 0.084 56.136 ;
    END
  END i_row[98]
  PIN i_row[99]
    DIRECTION INPUT ;
    USE SIGNAL ;
    PORT
      LAYER M4 ;
        RECT  0 56.544 0.084 56.568 ;
    END
  END i_row[99]
  PIN i_row[9]
    DIRECTION INPUT ;
    USE SIGNAL ;
    PORT
      LAYER M4 ;
        RECT  0 17.664 0.084 17.688 ;
    END
  END i_row[9]
  PIN i_slot[0]
    DIRECTION INPUT ;
    USE SIGNAL ;
    PORT
      LAYER M4 ;
        RECT  0 122.64 0.084 122.664 ;
    END
  END i_slot[0]
  PIN i_slot[10]
    DIRECTION INPUT ;
    USE SIGNAL ;
    PORT
      LAYER M4 ;
        RECT  0 126.96 0.084 126.984 ;
    END
  END i_slot[10]
  PIN i_slot[11]
    DIRECTION INPUT ;
    USE SIGNAL ;
    PORT
      LAYER M4 ;
        RECT  0 127.392 0.084 127.416 ;
    END
  END i_slot[11]
  PIN i_slot[12]
    DIRECTION INPUT ;
    USE SIGNAL ;
    PORT
      LAYER M4 ;
        RECT  0 127.824 0.084 127.848 ;
    END
  END i_slot[12]
  PIN i_slot[13]
    DIRECTION INPUT ;
    USE SIGNAL ;
    PORT
      LAYER M4 ;
        RECT  0 128.256 0.084 128.28 ;
    END
  END i_slot[13]
  PIN i_slot[14]
    DIRECTION INPUT ;
    USE SIGNAL ;
    PORT
      LAYER M4 ;
        RECT  0 128.688 0.084 128.712 ;
    END
  END i_slot[14]
  PIN i_slot[15]
    DIRECTION INPUT ;
    USE SIGNAL ;
    PORT
      LAYER M4 ;
        RECT  0 129.12 0.084 129.144 ;
    END
  END i_slot[15]
  PIN i_slot[16]
    DIRECTION INPUT ;
    USE SIGNAL ;
    PORT
      LAYER M4 ;
        RECT  0 129.552 0.084 129.576 ;
    END
  END i_slot[16]
  PIN i_slot[17]
    DIRECTION INPUT ;
    USE SIGNAL ;
    PORT
      LAYER M4 ;
        RECT  0 129.984 0.084 130.008 ;
    END
  END i_slot[17]
  PIN i_slot[18]
    DIRECTION INPUT ;
    USE SIGNAL ;
    PORT
      LAYER M4 ;
        RECT  0 130.416 0.084 130.44 ;
    END
  END i_slot[18]
  PIN i_slot[19]
    DIRECTION INPUT ;
    USE SIGNAL ;
    PORT
      LAYER M4 ;
        RECT  0 130.848 0.084 130.872 ;
    END
  END i_slot[19]
  PIN i_slot[1]
    DIRECTION INPUT ;
    USE SIGNAL ;
    PORT
      LAYER M4 ;
        RECT  0 123.072 0.084 123.096 ;
    END
  END i_slot[1]
  PIN i_slot[20]
    DIRECTION INPUT ;
    USE SIGNAL ;
    PORT
      LAYER M4 ;
        RECT  0 131.28 0.084 131.304 ;
    END
  END i_slot[20]
  PIN i_slot[21]
    DIRECTION INPUT ;
    USE SIGNAL ;
    PORT
      LAYER M4 ;
        RECT  0 131.712 0.084 131.736 ;
    END
  END i_slot[21]
  PIN i_slot[22]
    DIRECTION INPUT ;
    USE SIGNAL ;
    PORT
      LAYER M4 ;
        RECT  0 132.144 0.084 132.168 ;
    END
  END i_slot[22]
  PIN i_slot[23]
    DIRECTION INPUT ;
    USE SIGNAL ;
    PORT
      LAYER M4 ;
        RECT  0 132.576 0.084 132.6 ;
    END
  END i_slot[23]
  PIN i_slot[24]
    DIRECTION INPUT ;
    USE SIGNAL ;
    PORT
      LAYER M4 ;
        RECT  0 133.008 0.084 133.032 ;
    END
  END i_slot[24]
  PIN i_slot[25]
    DIRECTION INPUT ;
    USE SIGNAL ;
    PORT
      LAYER M4 ;
        RECT  0 133.44 0.084 133.464 ;
    END
  END i_slot[25]
  PIN i_slot[26]
    DIRECTION INPUT ;
    USE SIGNAL ;
    PORT
      LAYER M4 ;
        RECT  0 133.872 0.084 133.896 ;
    END
  END i_slot[26]
  PIN i_slot[27]
    DIRECTION INPUT ;
    USE SIGNAL ;
    PORT
      LAYER M4 ;
        RECT  0 134.304 0.084 134.328 ;
    END
  END i_slot[27]
  PIN i_slot[28]
    DIRECTION INPUT ;
    USE SIGNAL ;
    PORT
      LAYER M4 ;
        RECT  0 134.736 0.084 134.76 ;
    END
  END i_slot[28]
  PIN i_slot[29]
    DIRECTION INPUT ;
    USE SIGNAL ;
    PORT
      LAYER M4 ;
        RECT  0 135.168 0.084 135.192 ;
    END
  END i_slot[29]
  PIN i_slot[2]
    DIRECTION INPUT ;
    USE SIGNAL ;
    PORT
      LAYER M4 ;
        RECT  0 123.504 0.084 123.528 ;
    END
  END i_slot[2]
  PIN i_slot[30]
    DIRECTION INPUT ;
    USE SIGNAL ;
    PORT
      LAYER M4 ;
        RECT  0 135.6 0.084 135.624 ;
    END
  END i_slot[30]
  PIN i_slot[31]
    DIRECTION INPUT ;
    USE SIGNAL ;
    PORT
      LAYER M4 ;
        RECT  0 136.032 0.084 136.056 ;
    END
  END i_slot[31]
  PIN i_slot[32]
    DIRECTION INPUT ;
    USE SIGNAL ;
    PORT
      LAYER M4 ;
        RECT  0 136.464 0.084 136.488 ;
    END
  END i_slot[32]
  PIN i_slot[33]
    DIRECTION INPUT ;
    USE SIGNAL ;
    PORT
      LAYER M4 ;
        RECT  0 136.896 0.084 136.92 ;
    END
  END i_slot[33]
  PIN i_slot[34]
    DIRECTION INPUT ;
    USE SIGNAL ;
    PORT
      LAYER M4 ;
        RECT  0 137.328 0.084 137.352 ;
    END
  END i_slot[34]
  PIN i_slot[35]
    DIRECTION INPUT ;
    USE SIGNAL ;
    PORT
      LAYER M4 ;
        RECT  0 137.76 0.084 137.784 ;
    END
  END i_slot[35]
  PIN i_slot[36]
    DIRECTION INPUT ;
    USE SIGNAL ;
    PORT
      LAYER M4 ;
        RECT  0 138.192 0.084 138.216 ;
    END
  END i_slot[36]
  PIN i_slot[37]
    DIRECTION INPUT ;
    USE SIGNAL ;
    PORT
      LAYER M4 ;
        RECT  0 138.624 0.084 138.648 ;
    END
  END i_slot[37]
  PIN i_slot[38]
    DIRECTION INPUT ;
    USE SIGNAL ;
    PORT
      LAYER M4 ;
        RECT  0 139.056 0.084 139.08 ;
    END
  END i_slot[38]
  PIN i_slot[39]
    DIRECTION INPUT ;
    USE SIGNAL ;
    PORT
      LAYER M4 ;
        RECT  0 139.488 0.084 139.512 ;
    END
  END i_slot[39]
  PIN i_slot[3]
    DIRECTION INPUT ;
    USE SIGNAL ;
    PORT
      LAYER M4 ;
        RECT  0 123.936 0.084 123.96 ;
    END
  END i_slot[3]
  PIN i_slot[40]
    DIRECTION INPUT ;
    USE SIGNAL ;
    PORT
      LAYER M4 ;
        RECT  0 139.92 0.084 139.944 ;
    END
  END i_slot[40]
  PIN i_slot[41]
    DIRECTION INPUT ;
    USE SIGNAL ;
    PORT
      LAYER M4 ;
        RECT  0 140.352 0.084 140.376 ;
    END
  END i_slot[41]
  PIN i_slot[42]
    DIRECTION INPUT ;
    USE SIGNAL ;
    PORT
      LAYER M4 ;
        RECT  0 140.784 0.084 140.808 ;
    END
  END i_slot[42]
  PIN i_slot[43]
    DIRECTION INPUT ;
    USE SIGNAL ;
    PORT
      LAYER M4 ;
        RECT  0 141.216 0.084 141.24 ;
    END
  END i_slot[43]
  PIN i_slot[44]
    DIRECTION INPUT ;
    USE SIGNAL ;
    PORT
      LAYER M4 ;
        RECT  0 141.648 0.084 141.672 ;
    END
  END i_slot[44]
  PIN i_slot[45]
    DIRECTION INPUT ;
    USE SIGNAL ;
    PORT
      LAYER M4 ;
        RECT  0 142.08 0.084 142.104 ;
    END
  END i_slot[45]
  PIN i_slot[46]
    DIRECTION INPUT ;
    USE SIGNAL ;
    PORT
      LAYER M4 ;
        RECT  0 142.512 0.084 142.536 ;
    END
  END i_slot[46]
  PIN i_slot[47]
    DIRECTION INPUT ;
    USE SIGNAL ;
    PORT
      LAYER M4 ;
        RECT  0 142.944 0.084 142.968 ;
    END
  END i_slot[47]
  PIN i_slot[48]
    DIRECTION INPUT ;
    USE SIGNAL ;
    PORT
      LAYER M4 ;
        RECT  0 143.376 0.084 143.4 ;
    END
  END i_slot[48]
  PIN i_slot[49]
    DIRECTION INPUT ;
    USE SIGNAL ;
    PORT
      LAYER M4 ;
        RECT  0 143.808 0.084 143.832 ;
    END
  END i_slot[49]
  PIN i_slot[4]
    DIRECTION INPUT ;
    USE SIGNAL ;
    PORT
      LAYER M4 ;
        RECT  0 124.368 0.084 124.392 ;
    END
  END i_slot[4]
  PIN i_slot[50]
    DIRECTION INPUT ;
    USE SIGNAL ;
    PORT
      LAYER M4 ;
        RECT  0 144.24 0.084 144.264 ;
    END
  END i_slot[50]
  PIN i_slot[51]
    DIRECTION INPUT ;
    USE SIGNAL ;
    PORT
      LAYER M4 ;
        RECT  0 144.672 0.084 144.696 ;
    END
  END i_slot[51]
  PIN i_slot[52]
    DIRECTION INPUT ;
    USE SIGNAL ;
    PORT
      LAYER M4 ;
        RECT  0 145.104 0.084 145.128 ;
    END
  END i_slot[52]
  PIN i_slot[53]
    DIRECTION INPUT ;
    USE SIGNAL ;
    PORT
      LAYER M4 ;
        RECT  0 145.536 0.084 145.56 ;
    END
  END i_slot[53]
  PIN i_slot[54]
    DIRECTION INPUT ;
    USE SIGNAL ;
    PORT
      LAYER M4 ;
        RECT  0 145.968 0.084 145.992 ;
    END
  END i_slot[54]
  PIN i_slot[55]
    DIRECTION INPUT ;
    USE SIGNAL ;
    PORT
      LAYER M4 ;
        RECT  0 146.4 0.084 146.424 ;
    END
  END i_slot[55]
  PIN i_slot[56]
    DIRECTION INPUT ;
    USE SIGNAL ;
    PORT
      LAYER M4 ;
        RECT  0 146.832 0.084 146.856 ;
    END
  END i_slot[56]
  PIN i_slot[57]
    DIRECTION INPUT ;
    USE SIGNAL ;
    PORT
      LAYER M4 ;
        RECT  0 147.264 0.084 147.288 ;
    END
  END i_slot[57]
  PIN i_slot[58]
    DIRECTION INPUT ;
    USE SIGNAL ;
    PORT
      LAYER M4 ;
        RECT  0 147.696 0.084 147.72 ;
    END
  END i_slot[58]
  PIN i_slot[59]
    DIRECTION INPUT ;
    USE SIGNAL ;
    PORT
      LAYER M4 ;
        RECT  0 148.128 0.084 148.152 ;
    END
  END i_slot[59]
  PIN i_slot[5]
    DIRECTION INPUT ;
    USE SIGNAL ;
    PORT
      LAYER M4 ;
        RECT  0 124.8 0.084 124.824 ;
    END
  END i_slot[5]
  PIN i_slot[60]
    DIRECTION INPUT ;
    USE SIGNAL ;
    PORT
      LAYER M4 ;
        RECT  0 148.56 0.084 148.584 ;
    END
  END i_slot[60]
  PIN i_slot[61]
    DIRECTION INPUT ;
    USE SIGNAL ;
    PORT
      LAYER M4 ;
        RECT  0 148.992 0.084 149.016 ;
    END
  END i_slot[61]
  PIN i_slot[62]
    DIRECTION INPUT ;
    USE SIGNAL ;
    PORT
      LAYER M4 ;
        RECT  0 149.424 0.084 149.448 ;
    END
  END i_slot[62]
  PIN i_slot[63]
    DIRECTION INPUT ;
    USE SIGNAL ;
    PORT
      LAYER M4 ;
        RECT  0 149.856 0.084 149.88 ;
    END
  END i_slot[63]
  PIN i_slot[64]
    DIRECTION INPUT ;
    USE SIGNAL ;
    PORT
      LAYER M4 ;
        RECT  0 150.288 0.084 150.312 ;
    END
  END i_slot[64]
  PIN i_slot[65]
    DIRECTION INPUT ;
    USE SIGNAL ;
    PORT
      LAYER M4 ;
        RECT  0 150.72 0.084 150.744 ;
    END
  END i_slot[65]
  PIN i_slot[66]
    DIRECTION INPUT ;
    USE SIGNAL ;
    PORT
      LAYER M4 ;
        RECT  0 151.152 0.084 151.176 ;
    END
  END i_slot[66]
  PIN i_slot[67]
    DIRECTION INPUT ;
    USE SIGNAL ;
    PORT
      LAYER M4 ;
        RECT  0 151.584 0.084 151.608 ;
    END
  END i_slot[67]
  PIN i_slot[68]
    DIRECTION INPUT ;
    USE SIGNAL ;
    PORT
      LAYER M4 ;
        RECT  0 152.016 0.084 152.04 ;
    END
  END i_slot[68]
  PIN i_slot[69]
    DIRECTION INPUT ;
    USE SIGNAL ;
    PORT
      LAYER M4 ;
        RECT  0 152.448 0.084 152.472 ;
    END
  END i_slot[69]
  PIN i_slot[6]
    DIRECTION INPUT ;
    USE SIGNAL ;
    PORT
      LAYER M4 ;
        RECT  0 125.232 0.084 125.256 ;
    END
  END i_slot[6]
  PIN i_slot[70]
    DIRECTION INPUT ;
    USE SIGNAL ;
    PORT
      LAYER M4 ;
        RECT  0 152.88 0.084 152.904 ;
    END
  END i_slot[70]
  PIN i_slot[71]
    DIRECTION INPUT ;
    USE SIGNAL ;
    PORT
      LAYER M4 ;
        RECT  0 153.312 0.084 153.336 ;
    END
  END i_slot[71]
  PIN i_slot[72]
    DIRECTION INPUT ;
    USE SIGNAL ;
    PORT
      LAYER M4 ;
        RECT  0 153.744 0.084 153.768 ;
    END
  END i_slot[72]
  PIN i_slot[73]
    DIRECTION INPUT ;
    USE SIGNAL ;
    PORT
      LAYER M4 ;
        RECT  0 154.176 0.084 154.2 ;
    END
  END i_slot[73]
  PIN i_slot[74]
    DIRECTION INPUT ;
    USE SIGNAL ;
    PORT
      LAYER M4 ;
        RECT  0 154.608 0.084 154.632 ;
    END
  END i_slot[74]
  PIN i_slot[75]
    DIRECTION INPUT ;
    USE SIGNAL ;
    PORT
      LAYER M4 ;
        RECT  0 155.04 0.084 155.064 ;
    END
  END i_slot[75]
  PIN i_slot[76]
    DIRECTION INPUT ;
    USE SIGNAL ;
    PORT
      LAYER M4 ;
        RECT  0 155.472 0.084 155.496 ;
    END
  END i_slot[76]
  PIN i_slot[77]
    DIRECTION INPUT ;
    USE SIGNAL ;
    PORT
      LAYER M4 ;
        RECT  0 155.904 0.084 155.928 ;
    END
  END i_slot[77]
  PIN i_slot[78]
    DIRECTION INPUT ;
    USE SIGNAL ;
    PORT
      LAYER M4 ;
        RECT  0 156.336 0.084 156.36 ;
    END
  END i_slot[78]
  PIN i_slot[79]
    DIRECTION INPUT ;
    USE SIGNAL ;
    PORT
      LAYER M4 ;
        RECT  0 156.768 0.084 156.792 ;
    END
  END i_slot[79]
  PIN i_slot[7]
    DIRECTION INPUT ;
    USE SIGNAL ;
    PORT
      LAYER M4 ;
        RECT  0 125.664 0.084 125.688 ;
    END
  END i_slot[7]
  PIN i_slot[80]
    DIRECTION INPUT ;
    USE SIGNAL ;
    PORT
      LAYER M4 ;
        RECT  0 157.2 0.084 157.224 ;
    END
  END i_slot[80]
  PIN i_slot[81]
    DIRECTION INPUT ;
    USE SIGNAL ;
    PORT
      LAYER M4 ;
        RECT  0 157.632 0.084 157.656 ;
    END
  END i_slot[81]
  PIN i_slot[82]
    DIRECTION INPUT ;
    USE SIGNAL ;
    PORT
      LAYER M4 ;
        RECT  0 158.064 0.084 158.088 ;
    END
  END i_slot[82]
  PIN i_slot[83]
    DIRECTION INPUT ;
    USE SIGNAL ;
    PORT
      LAYER M4 ;
        RECT  0 158.496 0.084 158.52 ;
    END
  END i_slot[83]
  PIN i_slot[84]
    DIRECTION INPUT ;
    USE SIGNAL ;
    PORT
      LAYER M4 ;
        RECT  0 158.928 0.084 158.952 ;
    END
  END i_slot[84]
  PIN i_slot[85]
    DIRECTION INPUT ;
    USE SIGNAL ;
    PORT
      LAYER M4 ;
        RECT  0 159.36 0.084 159.384 ;
    END
  END i_slot[85]
  PIN i_slot[86]
    DIRECTION INPUT ;
    USE SIGNAL ;
    PORT
      LAYER M4 ;
        RECT  0 159.792 0.084 159.816 ;
    END
  END i_slot[86]
  PIN i_slot[87]
    DIRECTION INPUT ;
    USE SIGNAL ;
    PORT
      LAYER M4 ;
        RECT  0 160.224 0.084 160.248 ;
    END
  END i_slot[87]
  PIN i_slot[88]
    DIRECTION INPUT ;
    USE SIGNAL ;
    PORT
      LAYER M4 ;
        RECT  0 160.656 0.084 160.68 ;
    END
  END i_slot[88]
  PIN i_slot[89]
    DIRECTION INPUT ;
    USE SIGNAL ;
    PORT
      LAYER M4 ;
        RECT  0 161.088 0.084 161.112 ;
    END
  END i_slot[89]
  PIN i_slot[8]
    DIRECTION INPUT ;
    USE SIGNAL ;
    PORT
      LAYER M4 ;
        RECT  0 126.096 0.084 126.12 ;
    END
  END i_slot[8]
  PIN i_slot[9]
    DIRECTION INPUT ;
    USE SIGNAL ;
    PORT
      LAYER M4 ;
        RECT  0 126.528 0.084 126.552 ;
    END
  END i_slot[9]
  PIN i_v[0]
    DIRECTION INPUT ;
    USE SIGNAL ;
    PORT
      LAYER M4 ;
        RECT  0 6 0.084 6.024 ;
    END
  END i_v[0]
  PIN i_v[10]
    DIRECTION INPUT ;
    USE SIGNAL ;
    PORT
      LAYER M4 ;
        RECT  0 10.32 0.084 10.344 ;
    END
  END i_v[10]
  PIN i_v[11]
    DIRECTION INPUT ;
    USE SIGNAL ;
    PORT
      LAYER M4 ;
        RECT  0 10.752 0.084 10.776 ;
    END
  END i_v[11]
  PIN i_v[12]
    DIRECTION INPUT ;
    USE SIGNAL ;
    PORT
      LAYER M4 ;
        RECT  0 11.184 0.084 11.208 ;
    END
  END i_v[12]
  PIN i_v[13]
    DIRECTION INPUT ;
    USE SIGNAL ;
    PORT
      LAYER M4 ;
        RECT  0 11.616 0.084 11.64 ;
    END
  END i_v[13]
  PIN i_v[14]
    DIRECTION INPUT ;
    USE SIGNAL ;
    PORT
      LAYER M4 ;
        RECT  0 12.048 0.084 12.072 ;
    END
  END i_v[14]
  PIN i_v[15]
    DIRECTION INPUT ;
    USE SIGNAL ;
    PORT
      LAYER M4 ;
        RECT  0 12.48 0.084 12.504 ;
    END
  END i_v[15]
  PIN i_v[16]
    DIRECTION INPUT ;
    USE SIGNAL ;
    PORT
      LAYER M4 ;
        RECT  0 12.912 0.084 12.936 ;
    END
  END i_v[16]
  PIN i_v[17]
    DIRECTION INPUT ;
    USE SIGNAL ;
    PORT
      LAYER M4 ;
        RECT  0 13.344 0.084 13.368 ;
    END
  END i_v[17]
  PIN i_v[1]
    DIRECTION INPUT ;
    USE SIGNAL ;
    PORT
      LAYER M4 ;
        RECT  0 6.432 0.084 6.456 ;
    END
  END i_v[1]
  PIN i_v[2]
    DIRECTION INPUT ;
    USE SIGNAL ;
    PORT
      LAYER M4 ;
        RECT  0 6.864 0.084 6.888 ;
    END
  END i_v[2]
  PIN i_v[3]
    DIRECTION INPUT ;
    USE SIGNAL ;
    PORT
      LAYER M4 ;
        RECT  0 7.296 0.084 7.32 ;
    END
  END i_v[3]
  PIN i_v[4]
    DIRECTION INPUT ;
    USE SIGNAL ;
    PORT
      LAYER M4 ;
        RECT  0 7.728 0.084 7.752 ;
    END
  END i_v[4]
  PIN i_v[5]
    DIRECTION INPUT ;
    USE SIGNAL ;
    PORT
      LAYER M4 ;
        RECT  0 8.16 0.084 8.184 ;
    END
  END i_v[5]
  PIN i_v[6]
    DIRECTION INPUT ;
    USE SIGNAL ;
    PORT
      LAYER M4 ;
        RECT  0 8.592 0.084 8.616 ;
    END
  END i_v[6]
  PIN i_v[7]
    DIRECTION INPUT ;
    USE SIGNAL ;
    PORT
      LAYER M4 ;
        RECT  0 9.024 0.084 9.048 ;
    END
  END i_v[7]
  PIN i_v[8]
    DIRECTION INPUT ;
    USE SIGNAL ;
    PORT
      LAYER M4 ;
        RECT  0 9.456 0.084 9.48 ;
    END
  END i_v[8]
  PIN i_v[9]
    DIRECTION INPUT ;
    USE SIGNAL ;
    PORT
      LAYER M4 ;
        RECT  0 9.888 0.084 9.912 ;
    END
  END i_v[9]
  PIN o_addr[0]
    DIRECTION OUTPUT ;
    USE SIGNAL ;
    PORT
      LAYER M4 ;
        RECT  155.436 95.424 155.52 95.448 ;
    END
  END o_addr[0]
  PIN o_addr[10]
    DIRECTION OUTPUT ;
    USE SIGNAL ;
    PORT
      LAYER M4 ;
        RECT  155.436 99.744 155.52 99.768 ;
    END
  END o_addr[10]
  PIN o_addr[11]
    DIRECTION OUTPUT ;
    USE SIGNAL ;
    PORT
      LAYER M4 ;
        RECT  155.436 100.176 155.52 100.2 ;
    END
  END o_addr[11]
  PIN o_addr[12]
    DIRECTION OUTPUT ;
    USE SIGNAL ;
    PORT
      LAYER M4 ;
        RECT  155.436 100.608 155.52 100.632 ;
    END
  END o_addr[12]
  PIN o_addr[13]
    DIRECTION OUTPUT ;
    USE SIGNAL ;
    PORT
      LAYER M4 ;
        RECT  155.436 101.04 155.52 101.064 ;
    END
  END o_addr[13]
  PIN o_addr[14]
    DIRECTION OUTPUT ;
    USE SIGNAL ;
    PORT
      LAYER M4 ;
        RECT  155.436 101.472 155.52 101.496 ;
    END
  END o_addr[14]
  PIN o_addr[15]
    DIRECTION OUTPUT ;
    USE SIGNAL ;
    PORT
      LAYER M4 ;
        RECT  155.436 101.904 155.52 101.928 ;
    END
  END o_addr[15]
  PIN o_addr[16]
    DIRECTION OUTPUT ;
    USE SIGNAL ;
    PORT
      LAYER M4 ;
        RECT  155.436 102.336 155.52 102.36 ;
    END
  END o_addr[16]
  PIN o_addr[17]
    DIRECTION OUTPUT ;
    USE SIGNAL ;
    PORT
      LAYER M4 ;
        RECT  155.436 102.768 155.52 102.792 ;
    END
  END o_addr[17]
  PIN o_addr[18]
    DIRECTION OUTPUT ;
    USE SIGNAL ;
    PORT
      LAYER M4 ;
        RECT  155.436 103.2 155.52 103.224 ;
    END
  END o_addr[18]
  PIN o_addr[19]
    DIRECTION OUTPUT ;
    USE SIGNAL ;
    PORT
      LAYER M4 ;
        RECT  155.436 103.632 155.52 103.656 ;
    END
  END o_addr[19]
  PIN o_addr[1]
    DIRECTION OUTPUT ;
    USE SIGNAL ;
    PORT
      LAYER M4 ;
        RECT  155.436 95.856 155.52 95.88 ;
    END
  END o_addr[1]
  PIN o_addr[20]
    DIRECTION OUTPUT ;
    USE SIGNAL ;
    PORT
      LAYER M4 ;
        RECT  155.436 104.064 155.52 104.088 ;
    END
  END o_addr[20]
  PIN o_addr[21]
    DIRECTION OUTPUT ;
    USE SIGNAL ;
    PORT
      LAYER M4 ;
        RECT  155.436 104.496 155.52 104.52 ;
    END
  END o_addr[21]
  PIN o_addr[22]
    DIRECTION OUTPUT ;
    USE SIGNAL ;
    PORT
      LAYER M4 ;
        RECT  155.436 104.928 155.52 104.952 ;
    END
  END o_addr[22]
  PIN o_addr[23]
    DIRECTION OUTPUT ;
    USE SIGNAL ;
    PORT
      LAYER M4 ;
        RECT  155.436 105.36 155.52 105.384 ;
    END
  END o_addr[23]
  PIN o_addr[24]
    DIRECTION OUTPUT ;
    USE SIGNAL ;
    PORT
      LAYER M4 ;
        RECT  155.436 105.792 155.52 105.816 ;
    END
  END o_addr[24]
  PIN o_addr[25]
    DIRECTION OUTPUT ;
    USE SIGNAL ;
    PORT
      LAYER M4 ;
        RECT  155.436 106.224 155.52 106.248 ;
    END
  END o_addr[25]
  PIN o_addr[26]
    DIRECTION OUTPUT ;
    USE SIGNAL ;
    PORT
      LAYER M4 ;
        RECT  155.436 106.656 155.52 106.68 ;
    END
  END o_addr[26]
  PIN o_addr[27]
    DIRECTION OUTPUT ;
    USE SIGNAL ;
    PORT
      LAYER M4 ;
        RECT  155.436 107.088 155.52 107.112 ;
    END
  END o_addr[27]
  PIN o_addr[28]
    DIRECTION OUTPUT ;
    USE SIGNAL ;
    PORT
      LAYER M4 ;
        RECT  155.436 107.52 155.52 107.544 ;
    END
  END o_addr[28]
  PIN o_addr[29]
    DIRECTION OUTPUT ;
    USE SIGNAL ;
    PORT
      LAYER M4 ;
        RECT  155.436 107.952 155.52 107.976 ;
    END
  END o_addr[29]
  PIN o_addr[2]
    DIRECTION OUTPUT ;
    USE SIGNAL ;
    PORT
      LAYER M4 ;
        RECT  155.436 96.288 155.52 96.312 ;
    END
  END o_addr[2]
  PIN o_addr[30]
    DIRECTION OUTPUT ;
    USE SIGNAL ;
    PORT
      LAYER M4 ;
        RECT  155.436 108.384 155.52 108.408 ;
    END
  END o_addr[30]
  PIN o_addr[31]
    DIRECTION OUTPUT ;
    USE SIGNAL ;
    PORT
      LAYER M4 ;
        RECT  155.436 108.816 155.52 108.84 ;
    END
  END o_addr[31]
  PIN o_addr[32]
    DIRECTION OUTPUT ;
    USE SIGNAL ;
    PORT
      LAYER M4 ;
        RECT  155.436 109.248 155.52 109.272 ;
    END
  END o_addr[32]
  PIN o_addr[33]
    DIRECTION OUTPUT ;
    USE SIGNAL ;
    PORT
      LAYER M4 ;
        RECT  155.436 109.68 155.52 109.704 ;
    END
  END o_addr[33]
  PIN o_addr[34]
    DIRECTION OUTPUT ;
    USE SIGNAL ;
    PORT
      LAYER M4 ;
        RECT  155.436 110.112 155.52 110.136 ;
    END
  END o_addr[34]
  PIN o_addr[35]
    DIRECTION OUTPUT ;
    USE SIGNAL ;
    PORT
      LAYER M4 ;
        RECT  155.436 110.544 155.52 110.568 ;
    END
  END o_addr[35]
  PIN o_addr[36]
    DIRECTION OUTPUT ;
    USE SIGNAL ;
    PORT
      LAYER M4 ;
        RECT  155.436 110.976 155.52 111 ;
    END
  END o_addr[36]
  PIN o_addr[37]
    DIRECTION OUTPUT ;
    USE SIGNAL ;
    PORT
      LAYER M4 ;
        RECT  155.436 111.408 155.52 111.432 ;
    END
  END o_addr[37]
  PIN o_addr[38]
    DIRECTION OUTPUT ;
    USE SIGNAL ;
    PORT
      LAYER M4 ;
        RECT  155.436 111.84 155.52 111.864 ;
    END
  END o_addr[38]
  PIN o_addr[39]
    DIRECTION OUTPUT ;
    USE SIGNAL ;
    PORT
      LAYER M4 ;
        RECT  155.436 112.272 155.52 112.296 ;
    END
  END o_addr[39]
  PIN o_addr[3]
    DIRECTION OUTPUT ;
    USE SIGNAL ;
    PORT
      LAYER M4 ;
        RECT  155.436 96.72 155.52 96.744 ;
    END
  END o_addr[3]
  PIN o_addr[40]
    DIRECTION OUTPUT ;
    USE SIGNAL ;
    PORT
      LAYER M4 ;
        RECT  155.436 112.704 155.52 112.728 ;
    END
  END o_addr[40]
  PIN o_addr[41]
    DIRECTION OUTPUT ;
    USE SIGNAL ;
    PORT
      LAYER M4 ;
        RECT  155.436 113.136 155.52 113.16 ;
    END
  END o_addr[41]
  PIN o_addr[42]
    DIRECTION OUTPUT ;
    USE SIGNAL ;
    PORT
      LAYER M4 ;
        RECT  155.436 113.568 155.52 113.592 ;
    END
  END o_addr[42]
  PIN o_addr[43]
    DIRECTION OUTPUT ;
    USE SIGNAL ;
    PORT
      LAYER M4 ;
        RECT  155.436 114 155.52 114.024 ;
    END
  END o_addr[43]
  PIN o_addr[44]
    DIRECTION OUTPUT ;
    USE SIGNAL ;
    PORT
      LAYER M4 ;
        RECT  155.436 114.432 155.52 114.456 ;
    END
  END o_addr[44]
  PIN o_addr[45]
    DIRECTION OUTPUT ;
    USE SIGNAL ;
    PORT
      LAYER M4 ;
        RECT  155.436 114.864 155.52 114.888 ;
    END
  END o_addr[45]
  PIN o_addr[46]
    DIRECTION OUTPUT ;
    USE SIGNAL ;
    PORT
      LAYER M4 ;
        RECT  155.436 115.296 155.52 115.32 ;
    END
  END o_addr[46]
  PIN o_addr[47]
    DIRECTION OUTPUT ;
    USE SIGNAL ;
    PORT
      LAYER M4 ;
        RECT  155.436 115.728 155.52 115.752 ;
    END
  END o_addr[47]
  PIN o_addr[48]
    DIRECTION OUTPUT ;
    USE SIGNAL ;
    PORT
      LAYER M4 ;
        RECT  155.436 116.16 155.52 116.184 ;
    END
  END o_addr[48]
  PIN o_addr[49]
    DIRECTION OUTPUT ;
    USE SIGNAL ;
    PORT
      LAYER M4 ;
        RECT  155.436 116.592 155.52 116.616 ;
    END
  END o_addr[49]
  PIN o_addr[4]
    DIRECTION OUTPUT ;
    USE SIGNAL ;
    PORT
      LAYER M4 ;
        RECT  155.436 97.152 155.52 97.176 ;
    END
  END o_addr[4]
  PIN o_addr[50]
    DIRECTION OUTPUT ;
    USE SIGNAL ;
    PORT
      LAYER M4 ;
        RECT  155.436 117.024 155.52 117.048 ;
    END
  END o_addr[50]
  PIN o_addr[51]
    DIRECTION OUTPUT ;
    USE SIGNAL ;
    PORT
      LAYER M4 ;
        RECT  155.436 117.456 155.52 117.48 ;
    END
  END o_addr[51]
  PIN o_addr[52]
    DIRECTION OUTPUT ;
    USE SIGNAL ;
    PORT
      LAYER M4 ;
        RECT  155.436 117.888 155.52 117.912 ;
    END
  END o_addr[52]
  PIN o_addr[53]
    DIRECTION OUTPUT ;
    USE SIGNAL ;
    PORT
      LAYER M4 ;
        RECT  155.436 118.32 155.52 118.344 ;
    END
  END o_addr[53]
  PIN o_addr[54]
    DIRECTION OUTPUT ;
    USE SIGNAL ;
    PORT
      LAYER M4 ;
        RECT  155.436 118.752 155.52 118.776 ;
    END
  END o_addr[54]
  PIN o_addr[55]
    DIRECTION OUTPUT ;
    USE SIGNAL ;
    PORT
      LAYER M4 ;
        RECT  155.436 119.184 155.52 119.208 ;
    END
  END o_addr[55]
  PIN o_addr[56]
    DIRECTION OUTPUT ;
    USE SIGNAL ;
    PORT
      LAYER M4 ;
        RECT  155.436 119.616 155.52 119.64 ;
    END
  END o_addr[56]
  PIN o_addr[57]
    DIRECTION OUTPUT ;
    USE SIGNAL ;
    PORT
      LAYER M4 ;
        RECT  155.436 120.048 155.52 120.072 ;
    END
  END o_addr[57]
  PIN o_addr[58]
    DIRECTION OUTPUT ;
    USE SIGNAL ;
    PORT
      LAYER M4 ;
        RECT  155.436 120.48 155.52 120.504 ;
    END
  END o_addr[58]
  PIN o_addr[59]
    DIRECTION OUTPUT ;
    USE SIGNAL ;
    PORT
      LAYER M4 ;
        RECT  155.436 120.912 155.52 120.936 ;
    END
  END o_addr[59]
  PIN o_addr[5]
    DIRECTION OUTPUT ;
    USE SIGNAL ;
    PORT
      LAYER M4 ;
        RECT  155.436 97.584 155.52 97.608 ;
    END
  END o_addr[5]
  PIN o_addr[60]
    DIRECTION OUTPUT ;
    USE SIGNAL ;
    PORT
      LAYER M4 ;
        RECT  155.436 121.344 155.52 121.368 ;
    END
  END o_addr[60]
  PIN o_addr[61]
    DIRECTION OUTPUT ;
    USE SIGNAL ;
    PORT
      LAYER M4 ;
        RECT  155.436 121.776 155.52 121.8 ;
    END
  END o_addr[61]
  PIN o_addr[62]
    DIRECTION OUTPUT ;
    USE SIGNAL ;
    PORT
      LAYER M4 ;
        RECT  155.436 122.208 155.52 122.232 ;
    END
  END o_addr[62]
  PIN o_addr[63]
    DIRECTION OUTPUT ;
    USE SIGNAL ;
    PORT
      LAYER M4 ;
        RECT  155.436 122.64 155.52 122.664 ;
    END
  END o_addr[63]
  PIN o_addr[64]
    DIRECTION OUTPUT ;
    USE SIGNAL ;
    PORT
      LAYER M4 ;
        RECT  155.436 123.072 155.52 123.096 ;
    END
  END o_addr[64]
  PIN o_addr[65]
    DIRECTION OUTPUT ;
    USE SIGNAL ;
    PORT
      LAYER M4 ;
        RECT  155.436 123.504 155.52 123.528 ;
    END
  END o_addr[65]
  PIN o_addr[66]
    DIRECTION OUTPUT ;
    USE SIGNAL ;
    PORT
      LAYER M4 ;
        RECT  155.436 123.936 155.52 123.96 ;
    END
  END o_addr[66]
  PIN o_addr[67]
    DIRECTION OUTPUT ;
    USE SIGNAL ;
    PORT
      LAYER M4 ;
        RECT  155.436 124.368 155.52 124.392 ;
    END
  END o_addr[67]
  PIN o_addr[68]
    DIRECTION OUTPUT ;
    USE SIGNAL ;
    PORT
      LAYER M4 ;
        RECT  155.436 124.8 155.52 124.824 ;
    END
  END o_addr[68]
  PIN o_addr[69]
    DIRECTION OUTPUT ;
    USE SIGNAL ;
    PORT
      LAYER M4 ;
        RECT  155.436 125.232 155.52 125.256 ;
    END
  END o_addr[69]
  PIN o_addr[6]
    DIRECTION OUTPUT ;
    USE SIGNAL ;
    PORT
      LAYER M4 ;
        RECT  155.436 98.016 155.52 98.04 ;
    END
  END o_addr[6]
  PIN o_addr[70]
    DIRECTION OUTPUT ;
    USE SIGNAL ;
    PORT
      LAYER M4 ;
        RECT  155.436 125.664 155.52 125.688 ;
    END
  END o_addr[70]
  PIN o_addr[71]
    DIRECTION OUTPUT ;
    USE SIGNAL ;
    PORT
      LAYER M4 ;
        RECT  155.436 126.096 155.52 126.12 ;
    END
  END o_addr[71]
  PIN o_addr[7]
    DIRECTION OUTPUT ;
    USE SIGNAL ;
    PORT
      LAYER M4 ;
        RECT  155.436 98.448 155.52 98.472 ;
    END
  END o_addr[7]
  PIN o_addr[8]
    DIRECTION OUTPUT ;
    USE SIGNAL ;
    PORT
      LAYER M4 ;
        RECT  155.436 98.88 155.52 98.904 ;
    END
  END o_addr[8]
  PIN o_addr[9]
    DIRECTION OUTPUT ;
    USE SIGNAL ;
    PORT
      LAYER M4 ;
        RECT  155.436 99.312 155.52 99.336 ;
    END
  END o_addr[9]
  PIN o_tag[0]
    DIRECTION OUTPUT ;
    USE SIGNAL ;
    PORT
      LAYER M4 ;
        RECT  155.436 126.528 155.52 126.552 ;
    END
  END o_tag[0]
  PIN o_tag[10]
    DIRECTION OUTPUT ;
    USE SIGNAL ;
    PORT
      LAYER M4 ;
        RECT  155.436 130.848 155.52 130.872 ;
    END
  END o_tag[10]
  PIN o_tag[11]
    DIRECTION OUTPUT ;
    USE SIGNAL ;
    PORT
      LAYER M4 ;
        RECT  155.436 131.28 155.52 131.304 ;
    END
  END o_tag[11]
  PIN o_tag[12]
    DIRECTION OUTPUT ;
    USE SIGNAL ;
    PORT
      LAYER M4 ;
        RECT  155.436 131.712 155.52 131.736 ;
    END
  END o_tag[12]
  PIN o_tag[13]
    DIRECTION OUTPUT ;
    USE SIGNAL ;
    PORT
      LAYER M4 ;
        RECT  155.436 132.144 155.52 132.168 ;
    END
  END o_tag[13]
  PIN o_tag[14]
    DIRECTION OUTPUT ;
    USE SIGNAL ;
    PORT
      LAYER M4 ;
        RECT  155.436 132.576 155.52 132.6 ;
    END
  END o_tag[14]
  PIN o_tag[15]
    DIRECTION OUTPUT ;
    USE SIGNAL ;
    PORT
      LAYER M4 ;
        RECT  155.436 133.008 155.52 133.032 ;
    END
  END o_tag[15]
  PIN o_tag[16]
    DIRECTION OUTPUT ;
    USE SIGNAL ;
    PORT
      LAYER M4 ;
        RECT  155.436 133.44 155.52 133.464 ;
    END
  END o_tag[16]
  PIN o_tag[17]
    DIRECTION OUTPUT ;
    USE SIGNAL ;
    PORT
      LAYER M4 ;
        RECT  155.436 133.872 155.52 133.896 ;
    END
  END o_tag[17]
  PIN o_tag[18]
    DIRECTION OUTPUT ;
    USE SIGNAL ;
    PORT
      LAYER M4 ;
        RECT  155.436 134.304 155.52 134.328 ;
    END
  END o_tag[18]
  PIN o_tag[19]
    DIRECTION OUTPUT ;
    USE SIGNAL ;
    PORT
      LAYER M4 ;
        RECT  155.436 134.736 155.52 134.76 ;
    END
  END o_tag[19]
  PIN o_tag[1]
    DIRECTION OUTPUT ;
    USE SIGNAL ;
    PORT
      LAYER M4 ;
        RECT  155.436 126.96 155.52 126.984 ;
    END
  END o_tag[1]
  PIN o_tag[20]
    DIRECTION OUTPUT ;
    USE SIGNAL ;
    PORT
      LAYER M4 ;
        RECT  155.436 135.168 155.52 135.192 ;
    END
  END o_tag[20]
  PIN o_tag[21]
    DIRECTION OUTPUT ;
    USE SIGNAL ;
    PORT
      LAYER M4 ;
        RECT  155.436 135.6 155.52 135.624 ;
    END
  END o_tag[21]
  PIN o_tag[22]
    DIRECTION OUTPUT ;
    USE SIGNAL ;
    PORT
      LAYER M4 ;
        RECT  155.436 136.032 155.52 136.056 ;
    END
  END o_tag[22]
  PIN o_tag[23]
    DIRECTION OUTPUT ;
    USE SIGNAL ;
    PORT
      LAYER M4 ;
        RECT  155.436 136.464 155.52 136.488 ;
    END
  END o_tag[23]
  PIN o_tag[24]
    DIRECTION OUTPUT ;
    USE SIGNAL ;
    PORT
      LAYER M4 ;
        RECT  155.436 136.896 155.52 136.92 ;
    END
  END o_tag[24]
  PIN o_tag[25]
    DIRECTION OUTPUT ;
    USE SIGNAL ;
    PORT
      LAYER M4 ;
        RECT  155.436 137.328 155.52 137.352 ;
    END
  END o_tag[25]
  PIN o_tag[26]
    DIRECTION OUTPUT ;
    USE SIGNAL ;
    PORT
      LAYER M4 ;
        RECT  155.436 137.76 155.52 137.784 ;
    END
  END o_tag[26]
  PIN o_tag[27]
    DIRECTION OUTPUT ;
    USE SIGNAL ;
    PORT
      LAYER M4 ;
        RECT  155.436 138.192 155.52 138.216 ;
    END
  END o_tag[27]
  PIN o_tag[28]
    DIRECTION OUTPUT ;
    USE SIGNAL ;
    PORT
      LAYER M4 ;
        RECT  155.436 138.624 155.52 138.648 ;
    END
  END o_tag[28]
  PIN o_tag[29]
    DIRECTION OUTPUT ;
    USE SIGNAL ;
    PORT
      LAYER M4 ;
        RECT  155.436 139.056 155.52 139.08 ;
    END
  END o_tag[29]
  PIN o_tag[2]
    DIRECTION OUTPUT ;
    USE SIGNAL ;
    PORT
      LAYER M4 ;
        RECT  155.436 127.392 155.52 127.416 ;
    END
  END o_tag[2]
  PIN o_tag[30]
    DIRECTION OUTPUT ;
    USE SIGNAL ;
    PORT
      LAYER M4 ;
        RECT  155.436 139.488 155.52 139.512 ;
    END
  END o_tag[30]
  PIN o_tag[31]
    DIRECTION OUTPUT ;
    USE SIGNAL ;
    PORT
      LAYER M4 ;
        RECT  155.436 139.92 155.52 139.944 ;
    END
  END o_tag[31]
  PIN o_tag[32]
    DIRECTION OUTPUT ;
    USE SIGNAL ;
    PORT
      LAYER M4 ;
        RECT  155.436 140.352 155.52 140.376 ;
    END
  END o_tag[32]
  PIN o_tag[33]
    DIRECTION OUTPUT ;
    USE SIGNAL ;
    PORT
      LAYER M4 ;
        RECT  155.436 140.784 155.52 140.808 ;
    END
  END o_tag[33]
  PIN o_tag[34]
    DIRECTION OUTPUT ;
    USE SIGNAL ;
    PORT
      LAYER M4 ;
        RECT  155.436 141.216 155.52 141.24 ;
    END
  END o_tag[34]
  PIN o_tag[35]
    DIRECTION OUTPUT ;
    USE SIGNAL ;
    PORT
      LAYER M4 ;
        RECT  155.436 141.648 155.52 141.672 ;
    END
  END o_tag[35]
  PIN o_tag[36]
    DIRECTION OUTPUT ;
    USE SIGNAL ;
    PORT
      LAYER M4 ;
        RECT  155.436 142.08 155.52 142.104 ;
    END
  END o_tag[36]
  PIN o_tag[37]
    DIRECTION OUTPUT ;
    USE SIGNAL ;
    PORT
      LAYER M4 ;
        RECT  155.436 142.512 155.52 142.536 ;
    END
  END o_tag[37]
  PIN o_tag[38]
    DIRECTION OUTPUT ;
    USE SIGNAL ;
    PORT
      LAYER M4 ;
        RECT  155.436 142.944 155.52 142.968 ;
    END
  END o_tag[38]
  PIN o_tag[39]
    DIRECTION OUTPUT ;
    USE SIGNAL ;
    PORT
      LAYER M4 ;
        RECT  155.436 143.376 155.52 143.4 ;
    END
  END o_tag[39]
  PIN o_tag[3]
    DIRECTION OUTPUT ;
    USE SIGNAL ;
    PORT
      LAYER M4 ;
        RECT  155.436 127.824 155.52 127.848 ;
    END
  END o_tag[3]
  PIN o_tag[40]
    DIRECTION OUTPUT ;
    USE SIGNAL ;
    PORT
      LAYER M4 ;
        RECT  155.436 143.808 155.52 143.832 ;
    END
  END o_tag[40]
  PIN o_tag[41]
    DIRECTION OUTPUT ;
    USE SIGNAL ;
    PORT
      LAYER M4 ;
        RECT  155.436 144.24 155.52 144.264 ;
    END
  END o_tag[41]
  PIN o_tag[42]
    DIRECTION OUTPUT ;
    USE SIGNAL ;
    PORT
      LAYER M4 ;
        RECT  155.436 144.672 155.52 144.696 ;
    END
  END o_tag[42]
  PIN o_tag[43]
    DIRECTION OUTPUT ;
    USE SIGNAL ;
    PORT
      LAYER M4 ;
        RECT  155.436 145.104 155.52 145.128 ;
    END
  END o_tag[43]
  PIN o_tag[44]
    DIRECTION OUTPUT ;
    USE SIGNAL ;
    PORT
      LAYER M4 ;
        RECT  155.436 145.536 155.52 145.56 ;
    END
  END o_tag[44]
  PIN o_tag[45]
    DIRECTION OUTPUT ;
    USE SIGNAL ;
    PORT
      LAYER M4 ;
        RECT  155.436 145.968 155.52 145.992 ;
    END
  END o_tag[45]
  PIN o_tag[46]
    DIRECTION OUTPUT ;
    USE SIGNAL ;
    PORT
      LAYER M4 ;
        RECT  155.436 146.4 155.52 146.424 ;
    END
  END o_tag[46]
  PIN o_tag[47]
    DIRECTION OUTPUT ;
    USE SIGNAL ;
    PORT
      LAYER M4 ;
        RECT  155.436 146.832 155.52 146.856 ;
    END
  END o_tag[47]
  PIN o_tag[48]
    DIRECTION OUTPUT ;
    USE SIGNAL ;
    PORT
      LAYER M4 ;
        RECT  155.436 147.264 155.52 147.288 ;
    END
  END o_tag[48]
  PIN o_tag[49]
    DIRECTION OUTPUT ;
    USE SIGNAL ;
    PORT
      LAYER M4 ;
        RECT  155.436 147.696 155.52 147.72 ;
    END
  END o_tag[49]
  PIN o_tag[4]
    DIRECTION OUTPUT ;
    USE SIGNAL ;
    PORT
      LAYER M4 ;
        RECT  155.436 128.256 155.52 128.28 ;
    END
  END o_tag[4]
  PIN o_tag[50]
    DIRECTION OUTPUT ;
    USE SIGNAL ;
    PORT
      LAYER M4 ;
        RECT  155.436 148.128 155.52 148.152 ;
    END
  END o_tag[50]
  PIN o_tag[51]
    DIRECTION OUTPUT ;
    USE SIGNAL ;
    PORT
      LAYER M4 ;
        RECT  155.436 148.56 155.52 148.584 ;
    END
  END o_tag[51]
  PIN o_tag[52]
    DIRECTION OUTPUT ;
    USE SIGNAL ;
    PORT
      LAYER M4 ;
        RECT  155.436 148.992 155.52 149.016 ;
    END
  END o_tag[52]
  PIN o_tag[53]
    DIRECTION OUTPUT ;
    USE SIGNAL ;
    PORT
      LAYER M4 ;
        RECT  155.436 149.424 155.52 149.448 ;
    END
  END o_tag[53]
  PIN o_tag[54]
    DIRECTION OUTPUT ;
    USE SIGNAL ;
    PORT
      LAYER M4 ;
        RECT  155.436 149.856 155.52 149.88 ;
    END
  END o_tag[54]
  PIN o_tag[55]
    DIRECTION OUTPUT ;
    USE SIGNAL ;
    PORT
      LAYER M4 ;
        RECT  155.436 150.288 155.52 150.312 ;
    END
  END o_tag[55]
  PIN o_tag[56]
    DIRECTION OUTPUT ;
    USE SIGNAL ;
    PORT
      LAYER M4 ;
        RECT  155.436 150.72 155.52 150.744 ;
    END
  END o_tag[56]
  PIN o_tag[57]
    DIRECTION OUTPUT ;
    USE SIGNAL ;
    PORT
      LAYER M4 ;
        RECT  155.436 151.152 155.52 151.176 ;
    END
  END o_tag[57]
  PIN o_tag[58]
    DIRECTION OUTPUT ;
    USE SIGNAL ;
    PORT
      LAYER M4 ;
        RECT  155.436 151.584 155.52 151.608 ;
    END
  END o_tag[58]
  PIN o_tag[59]
    DIRECTION OUTPUT ;
    USE SIGNAL ;
    PORT
      LAYER M4 ;
        RECT  155.436 152.016 155.52 152.04 ;
    END
  END o_tag[59]
  PIN o_tag[5]
    DIRECTION OUTPUT ;
    USE SIGNAL ;
    PORT
      LAYER M4 ;
        RECT  155.436 128.688 155.52 128.712 ;
    END
  END o_tag[5]
  PIN o_tag[60]
    DIRECTION OUTPUT ;
    USE SIGNAL ;
    PORT
      LAYER M4 ;
        RECT  155.436 152.448 155.52 152.472 ;
    END
  END o_tag[60]
  PIN o_tag[61]
    DIRECTION OUTPUT ;
    USE SIGNAL ;
    PORT
      LAYER M4 ;
        RECT  155.436 152.88 155.52 152.904 ;
    END
  END o_tag[61]
  PIN o_tag[62]
    DIRECTION OUTPUT ;
    USE SIGNAL ;
    PORT
      LAYER M4 ;
        RECT  155.436 153.312 155.52 153.336 ;
    END
  END o_tag[62]
  PIN o_tag[63]
    DIRECTION OUTPUT ;
    USE SIGNAL ;
    PORT
      LAYER M4 ;
        RECT  155.436 153.744 155.52 153.768 ;
    END
  END o_tag[63]
  PIN o_tag[6]
    DIRECTION OUTPUT ;
    USE SIGNAL ;
    PORT
      LAYER M4 ;
        RECT  155.436 129.12 155.52 129.144 ;
    END
  END o_tag[6]
  PIN o_tag[7]
    DIRECTION OUTPUT ;
    USE SIGNAL ;
    PORT
      LAYER M4 ;
        RECT  155.436 129.552 155.52 129.576 ;
    END
  END o_tag[7]
  PIN o_tag[8]
    DIRECTION OUTPUT ;
    USE SIGNAL ;
    PORT
      LAYER M4 ;
        RECT  155.436 129.984 155.52 130.008 ;
    END
  END o_tag[8]
  PIN o_tag[9]
    DIRECTION OUTPUT ;
    USE SIGNAL ;
    PORT
      LAYER M4 ;
        RECT  155.436 130.416 155.52 130.44 ;
    END
  END o_tag[9]
  PIN o_v[0]
    DIRECTION OUTPUT ;
    USE SIGNAL ;
    PORT
      LAYER M4 ;
        RECT  155.436 91.968 155.52 91.992 ;
    END
  END o_v[0]
  PIN o_v[1]
    DIRECTION OUTPUT ;
    USE SIGNAL ;
    PORT
      LAYER M4 ;
        RECT  155.436 92.4 155.52 92.424 ;
    END
  END o_v[1]
  PIN o_v[2]
    DIRECTION OUTPUT ;
    USE SIGNAL ;
    PORT
      LAYER M4 ;
        RECT  155.436 92.832 155.52 92.856 ;
    END
  END o_v[2]
  PIN o_v[3]
    DIRECTION OUTPUT ;
    USE SIGNAL ;
    PORT
      LAYER M4 ;
        RECT  155.436 93.264 155.52 93.288 ;
    END
  END o_v[3]
  PIN o_v[4]
    DIRECTION OUTPUT ;
    USE SIGNAL ;
    PORT
      LAYER M4 ;
        RECT  155.436 93.696 155.52 93.72 ;
    END
  END o_v[4]
  PIN o_v[5]
    DIRECTION OUTPUT ;
    USE SIGNAL ;
    PORT
      LAYER M4 ;
        RECT  155.436 94.128 155.52 94.152 ;
    END
  END o_v[5]
  PIN o_v[6]
    DIRECTION OUTPUT ;
    USE SIGNAL ;
    PORT
      LAYER M4 ;
        RECT  155.436 94.56 155.52 94.584 ;
    END
  END o_v[6]
  PIN o_v[7]
    DIRECTION OUTPUT ;
    USE SIGNAL ;
    PORT
      LAYER M4 ;
        RECT  155.436 94.992 155.52 95.016 ;
    END
  END o_v[7]
  PIN rst_n
    DIRECTION INPUT ;
    USE SIGNAL ;
    PORT
      LAYER M5 ;
        RECT  77.952 246.156 77.976 246.24 ;
    END
  END rst_n
  PIN VDD
    DIRECTION INOUT ;
    USE POWER ;
    PORT
      LAYER M5 ;
        RECT  148.392 2.151 148.512 244.089 ;
        RECT  142.992 2.151 143.112 244.089 ;
        RECT  137.592 2.151 137.712 244.089 ;
        RECT  132.192 2.151 132.312 244.089 ;
        RECT  126.792 2.151 126.912 244.089 ;
        RECT  121.392 2.151 121.512 244.089 ;
        RECT  115.992 2.151 116.112 244.089 ;
        RECT  110.592 2.151 110.712 244.089 ;
        RECT  105.192 2.151 105.312 244.089 ;
        RECT  99.792 2.151 99.912 244.089 ;
        RECT  94.392 2.151 94.512 244.089 ;
        RECT  88.992 2.151 89.112 244.089 ;
        RECT  83.592 2.151 83.712 244.089 ;
        RECT  78.192 2.151 78.312 244.089 ;
        RECT  72.792 2.151 72.912 244.089 ;
        RECT  67.392 2.151 67.512 244.089 ;
        RECT  61.992 2.151 62.112 244.089 ;
        RECT  56.592 2.151 56.712 244.089 ;
        RECT  51.192 2.151 51.312 244.089 ;
        RECT  45.792 2.151 45.912 244.089 ;
        RECT  40.392 2.151 40.512 244.089 ;
        RECT  34.992 2.151 35.112 244.089 ;
        RECT  29.592 2.151 29.712 244.089 ;
        RECT  24.192 2.151 24.312 244.089 ;
        RECT  18.792 2.151 18.912 244.089 ;
        RECT  13.392 2.151 13.512 244.089 ;
        RECT  7.992 2.151 8.112 244.089 ;
        RECT  2.592 2.151 2.712 244.089 ;
    END
  END VDD
  PIN VSS
    DIRECTION INOUT ;
    USE GROUND ;
    PORT
      LAYER M5 ;
        RECT  148.2 2.137 148.32 244.103 ;
        RECT  142.8 2.137 142.92 244.103 ;
        RECT  137.4 2.137 137.52 244.103 ;
        RECT  132 2.137 132.12 244.103 ;
        RECT  126.6 2.137 126.72 244.103 ;
        RECT  121.2 2.137 121.32 244.103 ;
        RECT  115.8 2.137 115.92 244.103 ;
        RECT  110.4 2.137 110.52 244.103 ;
        RECT  105 2.137 105.12 244.103 ;
        RECT  99.6 2.137 99.72 244.103 ;
        RECT  94.2 2.137 94.32 244.103 ;
        RECT  88.8 2.137 88.92 244.103 ;
        RECT  83.4 2.137 83.52 244.103 ;
        RECT  78 2.137 78.12 244.103 ;
        RECT  72.6 2.137 72.72 244.103 ;
        RECT  67.2 2.137 67.32 244.103 ;
        RECT  61.8 2.137 61.92 244.103 ;
        RECT  56.4 2.137 56.52 244.103 ;
        RECT  51 2.137 51.12 244.103 ;
        RECT  45.6 2.137 45.72 244.103 ;
        RECT  40.2 2.137 40.32 244.103 ;
        RECT  34.8 2.137 34.92 244.103 ;
        RECT  29.4 2.137 29.52 244.103 ;
        RECT  24 2.137 24.12 244.103 ;
        RECT  18.6 2.137 18.72 244.103 ;
        RECT  13.2 2.137 13.32 244.103 ;
        RECT  7.8 2.137 7.92 244.103 ;
        RECT  2.4 2.137 2.52 244.103 ;
    END
  END VSS
  # OT_OBS_CLOSED layer=M5 d_um=1.536 added=72
  OBS
    LAYER RVTN ;
     RECT  2.16 2.16 153.36 2.295 ;
     RECT  2.16 2.565 153.36 2.835 ;
     RECT  2.16 3.105 153.36 3.375 ;
     RECT  2.16 3.645 153.36 3.915 ;
     RECT  2.16 4.185 153.36 4.455 ;
     RECT  2.16 4.725 153.36 4.995 ;
     RECT  2.16 5.265 153.36 5.535 ;
     RECT  2.16 5.805 153.36 6.075 ;
     RECT  2.16 6.345 153.36 6.615 ;
     RECT  2.16 6.885 153.36 7.155 ;
     RECT  2.16 7.425 153.36 7.695 ;
     RECT  2.16 7.965 153.36 8.235 ;
     RECT  2.16 8.505 153.36 8.775 ;
     RECT  2.16 9.045 153.36 9.315 ;
     RECT  2.16 9.585 153.36 9.855 ;
     RECT  2.16 10.125 153.36 10.395 ;
     RECT  2.16 10.665 153.36 10.935 ;
     RECT  2.16 11.205 153.36 11.475 ;
     RECT  2.16 11.745 153.36 12.015 ;
     RECT  2.16 12.285 153.36 12.555 ;
     RECT  2.16 12.825 153.36 13.095 ;
     RECT  2.16 13.365 153.36 13.635 ;
     RECT  2.16 13.905 153.36 14.175 ;
     RECT  2.16 14.445 153.36 14.715 ;
     RECT  2.16 14.985 153.36 15.255 ;
     RECT  2.16 15.525 153.36 15.795 ;
     RECT  2.16 16.065 153.36 16.335 ;
     RECT  2.16 16.605 153.36 16.875 ;
     RECT  2.16 17.145 153.36 17.415 ;
     RECT  2.16 17.685 153.36 17.955 ;
     RECT  2.16 18.225 153.36 18.495 ;
     RECT  2.16 18.765 153.36 19.035 ;
     RECT  2.16 19.305 153.36 19.575 ;
     RECT  2.16 19.845 153.36 20.115 ;
     RECT  2.16 20.385 153.36 20.655 ;
     RECT  2.16 20.925 153.36 21.195 ;
     RECT  2.16 21.465 153.36 21.735 ;
     RECT  2.16 22.005 153.36 22.275 ;
     RECT  2.16 22.545 153.36 22.815 ;
     RECT  2.16 23.085 153.36 23.355 ;
     RECT  2.16 23.625 153.36 23.895 ;
     RECT  2.16 24.165 153.36 24.435 ;
     RECT  2.16 24.705 153.36 24.975 ;
     RECT  2.16 25.245 153.36 25.515 ;
     RECT  2.16 25.785 153.36 26.055 ;
     RECT  2.16 26.325 153.36 26.595 ;
     RECT  2.16 26.865 153.36 27.135 ;
     RECT  2.16 27.405 153.36 27.675 ;
     RECT  2.16 27.945 153.36 28.215 ;
     RECT  2.16 28.485 153.36 28.755 ;
     RECT  2.16 29.025 153.36 29.295 ;
     RECT  2.16 29.565 153.36 29.835 ;
     RECT  2.16 30.105 153.36 30.375 ;
     RECT  2.16 30.645 153.36 30.915 ;
     RECT  2.16 31.185 153.36 31.455 ;
     RECT  2.16 31.725 153.36 31.995 ;
     RECT  2.16 32.265 153.36 32.535 ;
     RECT  2.16 32.805 153.36 33.075 ;
     RECT  2.16 33.345 153.36 33.615 ;
     RECT  2.16 33.885 153.36 34.155 ;
     RECT  2.16 34.425 153.36 34.695 ;
     RECT  2.16 34.965 153.36 35.235 ;
     RECT  2.16 35.505 153.36 35.775 ;
     RECT  2.16 36.045 153.36 36.315 ;
     RECT  2.16 36.585 153.36 36.855 ;
     RECT  2.16 37.125 153.36 37.395 ;
     RECT  2.16 37.665 153.36 37.935 ;
     RECT  2.16 38.205 153.36 38.475 ;
     RECT  2.16 38.745 153.36 39.015 ;
     RECT  2.16 39.285 153.36 39.555 ;
     RECT  2.16 39.825 153.36 40.095 ;
     RECT  2.16 40.365 153.36 40.635 ;
     RECT  2.16 40.905 153.36 41.175 ;
     RECT  2.16 41.445 153.36 41.715 ;
     RECT  2.16 41.985 153.36 42.255 ;
     RECT  2.16 42.525 153.36 42.795 ;
     RECT  2.16 43.065 153.36 43.335 ;
     RECT  2.16 43.605 153.36 43.875 ;
     RECT  2.16 44.145 153.36 44.415 ;
     RECT  2.16 44.685 153.36 44.955 ;
     RECT  2.16 45.225 153.36 45.495 ;
     RECT  2.16 45.765 153.36 46.035 ;
     RECT  2.16 46.305 153.36 46.575 ;
     RECT  2.16 46.845 153.36 47.115 ;
     RECT  2.16 47.385 153.36 47.655 ;
     RECT  2.16 47.925 153.36 48.195 ;
     RECT  2.16 48.465 153.36 48.735 ;
     RECT  2.16 49.005 153.36 49.275 ;
     RECT  2.16 49.545 153.36 49.815 ;
     RECT  2.16 50.085 153.36 50.355 ;
     RECT  2.16 50.625 153.36 50.895 ;
     RECT  2.16 51.165 153.36 51.435 ;
     RECT  2.16 51.705 153.36 51.975 ;
     RECT  2.16 52.245 153.36 52.515 ;
     RECT  2.16 52.785 153.36 53.055 ;
     RECT  2.16 53.325 153.36 53.595 ;
     RECT  2.16 53.865 153.36 54.135 ;
     RECT  2.16 54.405 153.36 54.675 ;
     RECT  2.16 54.945 153.36 55.215 ;
     RECT  2.16 55.485 153.36 55.755 ;
     RECT  2.16 56.025 153.36 56.295 ;
     RECT  2.16 56.565 153.36 56.835 ;
     RECT  2.16 57.105 153.36 57.375 ;
     RECT  2.16 57.645 153.36 57.915 ;
     RECT  2.16 58.185 153.36 58.455 ;
     RECT  2.16 58.725 153.36 58.995 ;
     RECT  2.16 59.265 153.36 59.535 ;
     RECT  2.16 59.805 153.36 60.075 ;
     RECT  2.16 60.345 153.36 60.615 ;
     RECT  2.16 60.885 153.36 61.155 ;
     RECT  2.16 61.425 153.36 61.695 ;
     RECT  2.16 61.965 153.36 62.235 ;
     RECT  2.16 62.505 153.36 62.775 ;
     RECT  2.16 63.045 153.36 63.315 ;
     RECT  2.16 63.585 153.36 63.855 ;
     RECT  2.16 64.125 153.36 64.395 ;
     RECT  2.16 64.665 153.36 64.935 ;
     RECT  2.16 65.205 153.36 65.475 ;
     RECT  2.16 65.745 153.36 66.015 ;
     RECT  2.16 66.285 153.36 66.555 ;
     RECT  2.16 66.825 153.36 67.095 ;
     RECT  2.16 67.365 153.36 67.635 ;
     RECT  2.16 67.905 153.36 68.175 ;
     RECT  2.16 68.445 153.36 68.715 ;
     RECT  2.16 68.985 153.36 69.255 ;
     RECT  2.16 69.525 153.36 69.795 ;
     RECT  2.16 70.065 153.36 70.335 ;
     RECT  2.16 70.605 153.36 70.875 ;
     RECT  2.16 71.145 153.36 71.415 ;
     RECT  2.16 71.685 153.36 71.955 ;
     RECT  2.16 72.225 153.36 72.495 ;
     RECT  2.16 72.765 153.36 73.035 ;
     RECT  2.16 73.305 153.36 73.575 ;
     RECT  2.16 73.845 153.36 74.115 ;
     RECT  2.16 74.385 153.36 74.655 ;
     RECT  2.16 74.925 153.36 75.195 ;
     RECT  2.16 75.465 153.36 75.735 ;
     RECT  2.16 76.005 153.36 76.275 ;
     RECT  2.16 76.545 153.36 76.815 ;
     RECT  2.16 77.085 153.36 77.355 ;
     RECT  2.16 77.625 153.36 77.895 ;
     RECT  2.16 78.165 153.36 78.435 ;
     RECT  2.16 78.705 153.36 78.975 ;
     RECT  2.16 79.245 153.36 79.515 ;
     RECT  2.16 79.785 153.36 80.055 ;
     RECT  2.16 80.325 153.36 80.595 ;
     RECT  2.16 80.865 153.36 81.135 ;
     RECT  2.16 81.405 153.36 81.675 ;
     RECT  2.16 81.945 153.36 82.215 ;
     RECT  2.16 82.485 153.36 82.755 ;
     RECT  2.16 83.025 153.36 83.295 ;
     RECT  2.16 83.565 153.36 83.835 ;
     RECT  2.16 84.105 153.36 84.375 ;
     RECT  2.16 84.645 153.36 84.915 ;
     RECT  2.16 85.185 153.36 85.455 ;
     RECT  2.16 85.725 153.36 85.995 ;
     RECT  2.16 86.265 153.36 86.535 ;
     RECT  2.16 86.805 153.36 87.075 ;
     RECT  2.16 87.345 153.36 87.615 ;
     RECT  2.16 87.885 153.36 88.155 ;
     RECT  2.16 88.425 153.36 88.695 ;
     RECT  2.16 88.965 153.36 89.235 ;
     RECT  2.16 89.505 153.36 89.775 ;
     RECT  2.16 90.045 153.36 90.315 ;
     RECT  2.16 90.585 153.36 90.855 ;
     RECT  2.16 91.125 153.36 91.395 ;
     RECT  2.16 91.665 153.36 91.935 ;
     RECT  2.16 92.205 153.36 92.475 ;
     RECT  2.16 92.745 153.36 93.015 ;
     RECT  2.16 93.285 153.36 93.555 ;
     RECT  2.16 93.825 153.36 94.095 ;
     RECT  2.16 94.365 153.36 94.635 ;
     RECT  2.16 94.905 153.36 95.175 ;
     RECT  2.16 95.445 153.36 95.715 ;
     RECT  2.16 95.985 153.36 96.255 ;
     RECT  2.16 96.525 153.36 96.795 ;
     RECT  2.16 97.065 153.36 97.335 ;
     RECT  2.16 97.605 153.36 97.875 ;
     RECT  2.16 98.145 153.36 98.415 ;
     RECT  2.16 98.685 153.36 98.955 ;
     RECT  2.16 99.225 153.36 99.495 ;
     RECT  2.16 99.765 153.36 100.035 ;
     RECT  2.16 100.305 153.36 100.575 ;
     RECT  2.16 100.845 153.36 101.115 ;
     RECT  2.16 101.385 153.36 101.655 ;
     RECT  2.16 101.925 153.36 102.195 ;
     RECT  2.16 102.465 153.36 102.735 ;
     RECT  2.16 103.005 153.36 103.275 ;
     RECT  2.16 103.545 153.36 103.815 ;
     RECT  2.16 104.085 153.36 104.355 ;
     RECT  2.16 104.625 153.36 104.895 ;
     RECT  2.16 105.165 153.36 105.435 ;
     RECT  2.16 105.705 153.36 105.975 ;
     RECT  2.16 106.245 153.36 106.515 ;
     RECT  2.16 106.785 153.36 107.055 ;
     RECT  2.16 107.325 153.36 107.595 ;
     RECT  2.16 107.865 153.36 108.135 ;
     RECT  2.16 108.405 153.36 108.675 ;
     RECT  2.16 108.945 153.36 109.215 ;
     RECT  2.16 109.485 153.36 109.755 ;
     RECT  2.16 110.025 153.36 110.295 ;
     RECT  2.16 110.565 153.36 110.835 ;
     RECT  2.16 111.105 153.36 111.375 ;
     RECT  2.16 111.645 153.36 111.915 ;
     RECT  2.16 112.185 153.36 112.455 ;
     RECT  2.16 112.725 153.36 112.995 ;
     RECT  2.16 113.265 153.36 113.535 ;
     RECT  2.16 113.805 153.36 114.075 ;
     RECT  2.16 114.345 153.36 114.615 ;
     RECT  2.16 114.885 153.36 115.155 ;
     RECT  2.16 115.425 153.36 115.695 ;
     RECT  2.16 115.965 153.36 116.235 ;
     RECT  2.16 116.505 153.36 116.775 ;
     RECT  2.16 117.045 153.36 117.315 ;
     RECT  2.16 117.585 153.36 117.855 ;
     RECT  2.16 118.125 153.36 118.395 ;
     RECT  2.16 118.665 153.36 118.935 ;
     RECT  2.16 119.205 153.36 119.475 ;
     RECT  2.16 119.745 153.36 120.015 ;
     RECT  2.16 120.285 153.36 120.555 ;
     RECT  2.16 120.825 153.36 121.095 ;
     RECT  2.16 121.365 153.36 121.635 ;
     RECT  2.16 121.905 153.36 122.175 ;
     RECT  2.16 122.445 153.36 122.715 ;
     RECT  2.16 122.985 153.36 123.255 ;
     RECT  2.16 123.525 153.36 123.795 ;
     RECT  2.16 124.065 153.36 124.335 ;
     RECT  2.16 124.605 153.36 124.875 ;
     RECT  2.16 125.145 153.36 125.415 ;
     RECT  2.16 125.685 153.36 125.955 ;
     RECT  2.16 126.225 153.36 126.495 ;
     RECT  2.16 126.765 153.36 127.035 ;
     RECT  2.16 127.305 153.36 127.575 ;
     RECT  2.16 127.845 153.36 128.115 ;
     RECT  2.16 128.385 153.36 128.655 ;
     RECT  2.16 128.925 153.36 129.195 ;
     RECT  2.16 129.465 153.36 129.735 ;
     RECT  2.16 130.005 153.36 130.275 ;
     RECT  2.16 130.545 153.36 130.815 ;
     RECT  2.16 131.085 153.36 131.355 ;
     RECT  2.16 131.625 153.36 131.895 ;
     RECT  2.16 132.165 153.36 132.435 ;
     RECT  2.16 132.705 153.36 132.975 ;
     RECT  2.16 133.245 153.36 133.515 ;
     RECT  2.16 133.785 153.36 134.055 ;
     RECT  2.16 134.325 153.36 134.595 ;
     RECT  2.16 134.865 153.36 135.135 ;
     RECT  2.16 135.405 153.36 135.675 ;
     RECT  2.16 135.945 153.36 136.215 ;
     RECT  2.16 136.485 153.36 136.755 ;
     RECT  2.16 137.025 153.36 137.295 ;
     RECT  2.16 137.565 153.36 137.835 ;
     RECT  2.16 138.105 153.36 138.375 ;
     RECT  2.16 138.645 153.36 138.915 ;
     RECT  2.16 139.185 153.36 139.455 ;
     RECT  2.16 139.725 153.36 139.995 ;
     RECT  2.16 140.265 153.36 140.535 ;
     RECT  2.16 140.805 153.36 141.075 ;
     RECT  2.16 141.345 153.36 141.615 ;
     RECT  2.16 141.885 153.36 142.155 ;
     RECT  2.16 142.425 153.36 142.695 ;
     RECT  2.16 142.965 153.36 143.235 ;
     RECT  2.16 143.505 153.36 143.775 ;
     RECT  2.16 144.045 153.36 144.315 ;
     RECT  2.16 144.585 153.36 144.855 ;
     RECT  2.16 145.125 153.36 145.395 ;
     RECT  2.16 145.665 153.36 145.935 ;
     RECT  2.16 146.205 153.36 146.475 ;
     RECT  2.16 146.745 153.36 147.015 ;
     RECT  2.16 147.285 153.36 147.555 ;
     RECT  2.16 147.825 153.36 148.095 ;
     RECT  2.16 148.365 153.36 148.635 ;
     RECT  2.16 148.905 153.36 149.175 ;
     RECT  2.16 149.445 153.36 149.715 ;
     RECT  2.16 149.985 153.36 150.255 ;
     RECT  2.16 150.525 153.36 150.795 ;
     RECT  2.16 151.065 153.36 151.335 ;
     RECT  2.16 151.605 153.36 151.875 ;
     RECT  2.16 152.145 153.36 152.415 ;
     RECT  2.16 152.685 153.36 152.955 ;
     RECT  2.16 153.225 153.36 153.495 ;
     RECT  2.16 153.765 153.36 154.035 ;
     RECT  2.16 154.305 153.36 154.575 ;
     RECT  2.16 154.845 153.36 155.115 ;
     RECT  2.16 155.385 153.36 155.655 ;
     RECT  2.16 155.925 153.36 156.195 ;
     RECT  2.16 156.465 153.36 156.735 ;
     RECT  2.16 157.005 153.36 157.275 ;
     RECT  2.16 157.545 153.36 157.815 ;
     RECT  2.16 158.085 153.36 158.355 ;
     RECT  2.16 158.625 153.36 158.895 ;
     RECT  2.16 159.165 153.36 159.435 ;
     RECT  2.16 159.705 153.36 159.975 ;
     RECT  2.16 160.245 153.36 160.515 ;
     RECT  2.16 160.785 153.36 161.055 ;
     RECT  2.16 161.325 153.36 161.595 ;
     RECT  2.16 161.865 153.36 162.135 ;
     RECT  2.16 162.405 153.36 162.675 ;
     RECT  2.16 162.945 153.36 163.215 ;
     RECT  2.16 163.485 153.36 163.755 ;
     RECT  2.16 164.025 153.36 164.295 ;
     RECT  2.16 164.565 153.36 164.835 ;
     RECT  2.16 165.105 153.36 165.375 ;
     RECT  2.16 165.645 153.36 165.915 ;
     RECT  2.16 166.185 153.36 166.455 ;
     RECT  2.16 166.725 153.36 166.995 ;
     RECT  2.16 167.265 153.36 167.535 ;
     RECT  2.16 167.805 153.36 168.075 ;
     RECT  2.16 168.345 153.36 168.615 ;
     RECT  2.16 168.885 153.36 169.155 ;
     RECT  2.16 169.425 153.36 169.695 ;
     RECT  2.16 169.965 153.36 170.235 ;
     RECT  2.16 170.505 153.36 170.775 ;
     RECT  2.16 171.045 153.36 171.315 ;
     RECT  2.16 171.585 153.36 171.855 ;
     RECT  2.16 172.125 153.36 172.395 ;
     RECT  2.16 172.665 153.36 172.935 ;
     RECT  2.16 173.205 153.36 173.475 ;
     RECT  2.16 173.745 153.36 174.015 ;
     RECT  2.16 174.285 153.36 174.555 ;
     RECT  2.16 174.825 153.36 175.095 ;
     RECT  2.16 175.365 153.36 175.635 ;
     RECT  2.16 175.905 153.36 176.175 ;
     RECT  2.16 176.445 153.36 176.715 ;
     RECT  2.16 176.985 153.36 177.255 ;
     RECT  2.16 177.525 153.36 177.795 ;
     RECT  2.16 178.065 153.36 178.335 ;
     RECT  2.16 178.605 153.36 178.875 ;
     RECT  2.16 179.145 153.36 179.415 ;
     RECT  2.16 179.685 153.36 179.955 ;
     RECT  2.16 180.225 153.36 180.495 ;
     RECT  2.16 180.765 153.36 181.035 ;
     RECT  2.16 181.305 153.36 181.575 ;
     RECT  2.16 181.845 153.36 182.115 ;
     RECT  2.16 182.385 153.36 182.655 ;
     RECT  2.16 182.925 153.36 183.195 ;
     RECT  2.16 183.465 153.36 183.735 ;
     RECT  2.16 184.005 153.36 184.275 ;
     RECT  2.16 184.545 153.36 184.815 ;
     RECT  2.16 185.085 153.36 185.355 ;
     RECT  2.16 185.625 153.36 185.895 ;
     RECT  2.16 186.165 153.36 186.435 ;
     RECT  2.16 186.705 153.36 186.975 ;
     RECT  2.16 187.245 153.36 187.515 ;
     RECT  2.16 187.785 153.36 188.055 ;
     RECT  2.16 188.325 153.36 188.595 ;
     RECT  2.16 188.865 153.36 189.135 ;
     RECT  2.16 189.405 153.36 189.675 ;
     RECT  2.16 189.945 153.36 190.215 ;
     RECT  2.16 190.485 153.36 190.755 ;
     RECT  2.16 191.025 153.36 191.295 ;
     RECT  2.16 191.565 153.36 191.835 ;
     RECT  2.16 192.105 153.36 192.375 ;
     RECT  2.16 192.645 153.36 192.915 ;
     RECT  2.16 193.185 153.36 193.455 ;
     RECT  2.16 193.725 153.36 193.995 ;
     RECT  2.16 194.265 153.36 194.535 ;
     RECT  2.16 194.805 153.36 195.075 ;
     RECT  2.16 195.345 153.36 195.615 ;
     RECT  2.16 195.885 153.36 196.155 ;
     RECT  2.16 196.425 153.36 196.695 ;
     RECT  2.16 196.965 153.36 197.235 ;
     RECT  2.16 197.505 153.36 197.775 ;
     RECT  2.16 198.045 153.36 198.315 ;
     RECT  2.16 198.585 153.36 198.855 ;
     RECT  2.16 199.125 153.36 199.395 ;
     RECT  2.16 199.665 153.36 199.935 ;
     RECT  2.16 200.205 153.36 200.475 ;
     RECT  2.16 200.745 153.36 201.015 ;
     RECT  2.16 201.285 153.36 201.555 ;
     RECT  2.16 201.825 153.36 202.095 ;
     RECT  2.16 202.365 153.36 202.635 ;
     RECT  2.16 202.905 153.36 203.175 ;
     RECT  2.16 203.445 153.36 203.715 ;
     RECT  2.16 203.985 153.36 204.255 ;
     RECT  2.16 204.525 153.36 204.795 ;
     RECT  2.16 205.065 153.36 205.335 ;
     RECT  2.16 205.605 153.36 205.875 ;
     RECT  2.16 206.145 153.36 206.415 ;
     RECT  2.16 206.685 153.36 206.955 ;
     RECT  2.16 207.225 153.36 207.495 ;
     RECT  2.16 207.765 153.36 208.035 ;
     RECT  2.16 208.305 153.36 208.575 ;
     RECT  2.16 208.845 153.36 209.115 ;
     RECT  2.16 209.385 153.36 209.655 ;
     RECT  2.16 209.925 153.36 210.195 ;
     RECT  2.16 210.465 153.36 210.735 ;
     RECT  2.16 211.005 153.36 211.275 ;
     RECT  2.16 211.545 153.36 211.815 ;
     RECT  2.16 212.085 153.36 212.355 ;
     RECT  2.16 212.625 153.36 212.895 ;
     RECT  2.16 213.165 153.36 213.435 ;
     RECT  2.16 213.705 153.36 213.975 ;
     RECT  2.16 214.245 153.36 214.515 ;
     RECT  2.16 214.785 153.36 215.055 ;
     RECT  2.16 215.325 153.36 215.595 ;
     RECT  2.16 215.865 153.36 216.135 ;
     RECT  2.16 216.405 153.36 216.675 ;
     RECT  2.16 216.945 153.36 217.215 ;
     RECT  2.16 217.485 153.36 217.755 ;
     RECT  2.16 218.025 153.36 218.295 ;
     RECT  2.16 218.565 153.36 218.835 ;
     RECT  2.16 219.105 153.36 219.375 ;
     RECT  2.16 219.645 153.36 219.915 ;
     RECT  2.16 220.185 153.36 220.455 ;
     RECT  2.16 220.725 153.36 220.995 ;
     RECT  2.16 221.265 153.36 221.535 ;
     RECT  2.16 221.805 153.36 222.075 ;
     RECT  2.16 222.345 153.36 222.615 ;
     RECT  2.16 222.885 153.36 223.155 ;
     RECT  2.16 223.425 153.36 223.695 ;
     RECT  2.16 223.965 153.36 224.235 ;
     RECT  2.16 224.505 153.36 224.775 ;
     RECT  2.16 225.045 153.36 225.315 ;
     RECT  2.16 225.585 153.36 225.855 ;
     RECT  2.16 226.125 153.36 226.395 ;
     RECT  2.16 226.665 153.36 226.935 ;
     RECT  2.16 227.205 153.36 227.475 ;
     RECT  2.16 227.745 153.36 228.015 ;
     RECT  2.16 228.285 153.36 228.555 ;
     RECT  2.16 228.825 153.36 229.095 ;
     RECT  2.16 229.365 153.36 229.635 ;
     RECT  2.16 229.905 153.36 230.175 ;
     RECT  2.16 230.445 153.36 230.715 ;
     RECT  2.16 230.985 153.36 231.255 ;
     RECT  2.16 231.525 153.36 231.795 ;
     RECT  2.16 232.065 153.36 232.335 ;
     RECT  2.16 232.605 153.36 232.875 ;
     RECT  2.16 233.145 153.36 233.415 ;
     RECT  2.16 233.685 153.36 233.955 ;
     RECT  2.16 234.225 153.36 234.495 ;
     RECT  2.16 234.765 153.36 235.035 ;
     RECT  2.16 235.305 153.36 235.575 ;
     RECT  2.16 235.845 153.36 236.115 ;
     RECT  2.16 236.385 153.36 236.655 ;
     RECT  2.16 236.925 153.36 237.195 ;
     RECT  2.16 237.465 153.36 237.735 ;
     RECT  2.16 238.005 153.36 238.275 ;
     RECT  2.16 238.545 153.36 238.815 ;
     RECT  2.16 239.085 153.36 239.355 ;
     RECT  2.16 239.625 153.36 239.895 ;
     RECT  2.16 240.165 153.36 240.435 ;
     RECT  2.16 240.705 153.36 240.975 ;
     RECT  2.16 241.245 153.36 241.515 ;
     RECT  2.16 241.785 153.36 242.055 ;
     RECT  2.16 242.325 153.36 242.595 ;
     RECT  2.16 242.865 153.36 243.135 ;
     RECT  2.16 243.405 153.36 243.675 ;
     RECT  2.16 243.945 153.36 244.08 ;
    LAYER RVTP ;
     RECT  2.16 2.295 153.36 2.565 ;
     RECT  2.16 2.835 153.36 3.105 ;
     RECT  2.16 3.375 153.36 3.645 ;
     RECT  2.16 3.915 153.36 4.185 ;
     RECT  2.16 4.455 153.36 4.725 ;
     RECT  2.16 4.995 153.36 5.265 ;
     RECT  2.16 5.535 153.36 5.805 ;
     RECT  2.16 6.075 153.36 6.345 ;
     RECT  2.16 6.615 153.36 6.885 ;
     RECT  2.16 7.155 153.36 7.425 ;
     RECT  2.16 7.695 153.36 7.965 ;
     RECT  2.16 8.235 153.36 8.505 ;
     RECT  2.16 8.775 153.36 9.045 ;
     RECT  2.16 9.315 153.36 9.585 ;
     RECT  2.16 9.855 153.36 10.125 ;
     RECT  2.16 10.395 153.36 10.665 ;
     RECT  2.16 10.935 153.36 11.205 ;
     RECT  2.16 11.475 153.36 11.745 ;
     RECT  2.16 12.015 153.36 12.285 ;
     RECT  2.16 12.555 153.36 12.825 ;
     RECT  2.16 13.095 153.36 13.365 ;
     RECT  2.16 13.635 153.36 13.905 ;
     RECT  2.16 14.175 153.36 14.445 ;
     RECT  2.16 14.715 153.36 14.985 ;
     RECT  2.16 15.255 153.36 15.525 ;
     RECT  2.16 15.795 153.36 16.065 ;
     RECT  2.16 16.335 153.36 16.605 ;
     RECT  2.16 16.875 153.36 17.145 ;
     RECT  2.16 17.415 153.36 17.685 ;
     RECT  2.16 17.955 153.36 18.225 ;
     RECT  2.16 18.495 153.36 18.765 ;
     RECT  2.16 19.035 153.36 19.305 ;
     RECT  2.16 19.575 153.36 19.845 ;
     RECT  2.16 20.115 153.36 20.385 ;
     RECT  2.16 20.655 153.36 20.925 ;
     RECT  2.16 21.195 153.36 21.465 ;
     RECT  2.16 21.735 153.36 22.005 ;
     RECT  2.16 22.275 153.36 22.545 ;
     RECT  2.16 22.815 153.36 23.085 ;
     RECT  2.16 23.355 153.36 23.625 ;
     RECT  2.16 23.895 153.36 24.165 ;
     RECT  2.16 24.435 153.36 24.705 ;
     RECT  2.16 24.975 153.36 25.245 ;
     RECT  2.16 25.515 153.36 25.785 ;
     RECT  2.16 26.055 153.36 26.325 ;
     RECT  2.16 26.595 153.36 26.865 ;
     RECT  2.16 27.135 153.36 27.405 ;
     RECT  2.16 27.675 153.36 27.945 ;
     RECT  2.16 28.215 153.36 28.485 ;
     RECT  2.16 28.755 153.36 29.025 ;
     RECT  2.16 29.295 153.36 29.565 ;
     RECT  2.16 29.835 153.36 30.105 ;
     RECT  2.16 30.375 153.36 30.645 ;
     RECT  2.16 30.915 153.36 31.185 ;
     RECT  2.16 31.455 153.36 31.725 ;
     RECT  2.16 31.995 153.36 32.265 ;
     RECT  2.16 32.535 153.36 32.805 ;
     RECT  2.16 33.075 153.36 33.345 ;
     RECT  2.16 33.615 153.36 33.885 ;
     RECT  2.16 34.155 153.36 34.425 ;
     RECT  2.16 34.695 153.36 34.965 ;
     RECT  2.16 35.235 153.36 35.505 ;
     RECT  2.16 35.775 153.36 36.045 ;
     RECT  2.16 36.315 153.36 36.585 ;
     RECT  2.16 36.855 153.36 37.125 ;
     RECT  2.16 37.395 153.36 37.665 ;
     RECT  2.16 37.935 153.36 38.205 ;
     RECT  2.16 38.475 153.36 38.745 ;
     RECT  2.16 39.015 153.36 39.285 ;
     RECT  2.16 39.555 153.36 39.825 ;
     RECT  2.16 40.095 153.36 40.365 ;
     RECT  2.16 40.635 153.36 40.905 ;
     RECT  2.16 41.175 153.36 41.445 ;
     RECT  2.16 41.715 153.36 41.985 ;
     RECT  2.16 42.255 153.36 42.525 ;
     RECT  2.16 42.795 153.36 43.065 ;
     RECT  2.16 43.335 153.36 43.605 ;
     RECT  2.16 43.875 153.36 44.145 ;
     RECT  2.16 44.415 153.36 44.685 ;
     RECT  2.16 44.955 153.36 45.225 ;
     RECT  2.16 45.495 153.36 45.765 ;
     RECT  2.16 46.035 153.36 46.305 ;
     RECT  2.16 46.575 153.36 46.845 ;
     RECT  2.16 47.115 153.36 47.385 ;
     RECT  2.16 47.655 153.36 47.925 ;
     RECT  2.16 48.195 153.36 48.465 ;
     RECT  2.16 48.735 153.36 49.005 ;
     RECT  2.16 49.275 153.36 49.545 ;
     RECT  2.16 49.815 153.36 50.085 ;
     RECT  2.16 50.355 153.36 50.625 ;
     RECT  2.16 50.895 153.36 51.165 ;
     RECT  2.16 51.435 153.36 51.705 ;
     RECT  2.16 51.975 153.36 52.245 ;
     RECT  2.16 52.515 153.36 52.785 ;
     RECT  2.16 53.055 153.36 53.325 ;
     RECT  2.16 53.595 153.36 53.865 ;
     RECT  2.16 54.135 153.36 54.405 ;
     RECT  2.16 54.675 153.36 54.945 ;
     RECT  2.16 55.215 153.36 55.485 ;
     RECT  2.16 55.755 153.36 56.025 ;
     RECT  2.16 56.295 153.36 56.565 ;
     RECT  2.16 56.835 153.36 57.105 ;
     RECT  2.16 57.375 153.36 57.645 ;
     RECT  2.16 57.915 153.36 58.185 ;
     RECT  2.16 58.455 153.36 58.725 ;
     RECT  2.16 58.995 153.36 59.265 ;
     RECT  2.16 59.535 153.36 59.805 ;
     RECT  2.16 60.075 153.36 60.345 ;
     RECT  2.16 60.615 153.36 60.885 ;
     RECT  2.16 61.155 153.36 61.425 ;
     RECT  2.16 61.695 153.36 61.965 ;
     RECT  2.16 62.235 153.36 62.505 ;
     RECT  2.16 62.775 153.36 63.045 ;
     RECT  2.16 63.315 153.36 63.585 ;
     RECT  2.16 63.855 153.36 64.125 ;
     RECT  2.16 64.395 153.36 64.665 ;
     RECT  2.16 64.935 153.36 65.205 ;
     RECT  2.16 65.475 153.36 65.745 ;
     RECT  2.16 66.015 153.36 66.285 ;
     RECT  2.16 66.555 153.36 66.825 ;
     RECT  2.16 67.095 153.36 67.365 ;
     RECT  2.16 67.635 153.36 67.905 ;
     RECT  2.16 68.175 153.36 68.445 ;
     RECT  2.16 68.715 153.36 68.985 ;
     RECT  2.16 69.255 153.36 69.525 ;
     RECT  2.16 69.795 153.36 70.065 ;
     RECT  2.16 70.335 153.36 70.605 ;
     RECT  2.16 70.875 153.36 71.145 ;
     RECT  2.16 71.415 153.36 71.685 ;
     RECT  2.16 71.955 153.36 72.225 ;
     RECT  2.16 72.495 153.36 72.765 ;
     RECT  2.16 73.035 153.36 73.305 ;
     RECT  2.16 73.575 153.36 73.845 ;
     RECT  2.16 74.115 153.36 74.385 ;
     RECT  2.16 74.655 153.36 74.925 ;
     RECT  2.16 75.195 153.36 75.465 ;
     RECT  2.16 75.735 153.36 76.005 ;
     RECT  2.16 76.275 153.36 76.545 ;
     RECT  2.16 76.815 153.36 77.085 ;
     RECT  2.16 77.355 153.36 77.625 ;
     RECT  2.16 77.895 153.36 78.165 ;
     RECT  2.16 78.435 153.36 78.705 ;
     RECT  2.16 78.975 153.36 79.245 ;
     RECT  2.16 79.515 153.36 79.785 ;
     RECT  2.16 80.055 153.36 80.325 ;
     RECT  2.16 80.595 153.36 80.865 ;
     RECT  2.16 81.135 153.36 81.405 ;
     RECT  2.16 81.675 153.36 81.945 ;
     RECT  2.16 82.215 153.36 82.485 ;
     RECT  2.16 82.755 153.36 83.025 ;
     RECT  2.16 83.295 153.36 83.565 ;
     RECT  2.16 83.835 153.36 84.105 ;
     RECT  2.16 84.375 153.36 84.645 ;
     RECT  2.16 84.915 153.36 85.185 ;
     RECT  2.16 85.455 153.36 85.725 ;
     RECT  2.16 85.995 153.36 86.265 ;
     RECT  2.16 86.535 153.36 86.805 ;
     RECT  2.16 87.075 153.36 87.345 ;
     RECT  2.16 87.615 153.36 87.885 ;
     RECT  2.16 88.155 153.36 88.425 ;
     RECT  2.16 88.695 153.36 88.965 ;
     RECT  2.16 89.235 153.36 89.505 ;
     RECT  2.16 89.775 153.36 90.045 ;
     RECT  2.16 90.315 153.36 90.585 ;
     RECT  2.16 90.855 153.36 91.125 ;
     RECT  2.16 91.395 153.36 91.665 ;
     RECT  2.16 91.935 153.36 92.205 ;
     RECT  2.16 92.475 153.36 92.745 ;
     RECT  2.16 93.015 153.36 93.285 ;
     RECT  2.16 93.555 153.36 93.825 ;
     RECT  2.16 94.095 153.36 94.365 ;
     RECT  2.16 94.635 153.36 94.905 ;
     RECT  2.16 95.175 153.36 95.445 ;
     RECT  2.16 95.715 153.36 95.985 ;
     RECT  2.16 96.255 153.36 96.525 ;
     RECT  2.16 96.795 153.36 97.065 ;
     RECT  2.16 97.335 153.36 97.605 ;
     RECT  2.16 97.875 153.36 98.145 ;
     RECT  2.16 98.415 153.36 98.685 ;
     RECT  2.16 98.955 153.36 99.225 ;
     RECT  2.16 99.495 153.36 99.765 ;
     RECT  2.16 100.035 153.36 100.305 ;
     RECT  2.16 100.575 153.36 100.845 ;
     RECT  2.16 101.115 153.36 101.385 ;
     RECT  2.16 101.655 153.36 101.925 ;
     RECT  2.16 102.195 153.36 102.465 ;
     RECT  2.16 102.735 153.36 103.005 ;
     RECT  2.16 103.275 153.36 103.545 ;
     RECT  2.16 103.815 153.36 104.085 ;
     RECT  2.16 104.355 153.36 104.625 ;
     RECT  2.16 104.895 153.36 105.165 ;
     RECT  2.16 105.435 153.36 105.705 ;
     RECT  2.16 105.975 153.36 106.245 ;
     RECT  2.16 106.515 153.36 106.785 ;
     RECT  2.16 107.055 153.36 107.325 ;
     RECT  2.16 107.595 153.36 107.865 ;
     RECT  2.16 108.135 153.36 108.405 ;
     RECT  2.16 108.675 153.36 108.945 ;
     RECT  2.16 109.215 153.36 109.485 ;
     RECT  2.16 109.755 153.36 110.025 ;
     RECT  2.16 110.295 153.36 110.565 ;
     RECT  2.16 110.835 153.36 111.105 ;
     RECT  2.16 111.375 153.36 111.645 ;
     RECT  2.16 111.915 153.36 112.185 ;
     RECT  2.16 112.455 153.36 112.725 ;
     RECT  2.16 112.995 153.36 113.265 ;
     RECT  2.16 113.535 153.36 113.805 ;
     RECT  2.16 114.075 153.36 114.345 ;
     RECT  2.16 114.615 153.36 114.885 ;
     RECT  2.16 115.155 153.36 115.425 ;
     RECT  2.16 115.695 153.36 115.965 ;
     RECT  2.16 116.235 153.36 116.505 ;
     RECT  2.16 116.775 153.36 117.045 ;
     RECT  2.16 117.315 153.36 117.585 ;
     RECT  2.16 117.855 153.36 118.125 ;
     RECT  2.16 118.395 153.36 118.665 ;
     RECT  2.16 118.935 153.36 119.205 ;
     RECT  2.16 119.475 153.36 119.745 ;
     RECT  2.16 120.015 153.36 120.285 ;
     RECT  2.16 120.555 153.36 120.825 ;
     RECT  2.16 121.095 153.36 121.365 ;
     RECT  2.16 121.635 153.36 121.905 ;
     RECT  2.16 122.175 153.36 122.445 ;
     RECT  2.16 122.715 153.36 122.985 ;
     RECT  2.16 123.255 153.36 123.525 ;
     RECT  2.16 123.795 153.36 124.065 ;
     RECT  2.16 124.335 153.36 124.605 ;
     RECT  2.16 124.875 153.36 125.145 ;
     RECT  2.16 125.415 153.36 125.685 ;
     RECT  2.16 125.955 153.36 126.225 ;
     RECT  2.16 126.495 153.36 126.765 ;
     RECT  2.16 127.035 153.36 127.305 ;
     RECT  2.16 127.575 153.36 127.845 ;
     RECT  2.16 128.115 153.36 128.385 ;
     RECT  2.16 128.655 153.36 128.925 ;
     RECT  2.16 129.195 153.36 129.465 ;
     RECT  2.16 129.735 153.36 130.005 ;
     RECT  2.16 130.275 153.36 130.545 ;
     RECT  2.16 130.815 153.36 131.085 ;
     RECT  2.16 131.355 153.36 131.625 ;
     RECT  2.16 131.895 153.36 132.165 ;
     RECT  2.16 132.435 153.36 132.705 ;
     RECT  2.16 132.975 153.36 133.245 ;
     RECT  2.16 133.515 153.36 133.785 ;
     RECT  2.16 134.055 153.36 134.325 ;
     RECT  2.16 134.595 153.36 134.865 ;
     RECT  2.16 135.135 153.36 135.405 ;
     RECT  2.16 135.675 153.36 135.945 ;
     RECT  2.16 136.215 153.36 136.485 ;
     RECT  2.16 136.755 153.36 137.025 ;
     RECT  2.16 137.295 153.36 137.565 ;
     RECT  2.16 137.835 153.36 138.105 ;
     RECT  2.16 138.375 153.36 138.645 ;
     RECT  2.16 138.915 153.36 139.185 ;
     RECT  2.16 139.455 153.36 139.725 ;
     RECT  2.16 139.995 153.36 140.265 ;
     RECT  2.16 140.535 153.36 140.805 ;
     RECT  2.16 141.075 153.36 141.345 ;
     RECT  2.16 141.615 153.36 141.885 ;
     RECT  2.16 142.155 153.36 142.425 ;
     RECT  2.16 142.695 153.36 142.965 ;
     RECT  2.16 143.235 153.36 143.505 ;
     RECT  2.16 143.775 153.36 144.045 ;
     RECT  2.16 144.315 153.36 144.585 ;
     RECT  2.16 144.855 153.36 145.125 ;
     RECT  2.16 145.395 153.36 145.665 ;
     RECT  2.16 145.935 153.36 146.205 ;
     RECT  2.16 146.475 153.36 146.745 ;
     RECT  2.16 147.015 153.36 147.285 ;
     RECT  2.16 147.555 153.36 147.825 ;
     RECT  2.16 148.095 153.36 148.365 ;
     RECT  2.16 148.635 153.36 148.905 ;
     RECT  2.16 149.175 153.36 149.445 ;
     RECT  2.16 149.715 153.36 149.985 ;
     RECT  2.16 150.255 153.36 150.525 ;
     RECT  2.16 150.795 153.36 151.065 ;
     RECT  2.16 151.335 153.36 151.605 ;
     RECT  2.16 151.875 153.36 152.145 ;
     RECT  2.16 152.415 153.36 152.685 ;
     RECT  2.16 152.955 153.36 153.225 ;
     RECT  2.16 153.495 153.36 153.765 ;
     RECT  2.16 154.035 153.36 154.305 ;
     RECT  2.16 154.575 153.36 154.845 ;
     RECT  2.16 155.115 153.36 155.385 ;
     RECT  2.16 155.655 153.36 155.925 ;
     RECT  2.16 156.195 153.36 156.465 ;
     RECT  2.16 156.735 153.36 157.005 ;
     RECT  2.16 157.275 153.36 157.545 ;
     RECT  2.16 157.815 153.36 158.085 ;
     RECT  2.16 158.355 153.36 158.625 ;
     RECT  2.16 158.895 153.36 159.165 ;
     RECT  2.16 159.435 153.36 159.705 ;
     RECT  2.16 159.975 153.36 160.245 ;
     RECT  2.16 160.515 153.36 160.785 ;
     RECT  2.16 161.055 153.36 161.325 ;
     RECT  2.16 161.595 153.36 161.865 ;
     RECT  2.16 162.135 153.36 162.405 ;
     RECT  2.16 162.675 153.36 162.945 ;
     RECT  2.16 163.215 153.36 163.485 ;
     RECT  2.16 163.755 153.36 164.025 ;
     RECT  2.16 164.295 153.36 164.565 ;
     RECT  2.16 164.835 153.36 165.105 ;
     RECT  2.16 165.375 153.36 165.645 ;
     RECT  2.16 165.915 153.36 166.185 ;
     RECT  2.16 166.455 153.36 166.725 ;
     RECT  2.16 166.995 153.36 167.265 ;
     RECT  2.16 167.535 153.36 167.805 ;
     RECT  2.16 168.075 153.36 168.345 ;
     RECT  2.16 168.615 153.36 168.885 ;
     RECT  2.16 169.155 153.36 169.425 ;
     RECT  2.16 169.695 153.36 169.965 ;
     RECT  2.16 170.235 153.36 170.505 ;
     RECT  2.16 170.775 153.36 171.045 ;
     RECT  2.16 171.315 153.36 171.585 ;
     RECT  2.16 171.855 153.36 172.125 ;
     RECT  2.16 172.395 153.36 172.665 ;
     RECT  2.16 172.935 153.36 173.205 ;
     RECT  2.16 173.475 153.36 173.745 ;
     RECT  2.16 174.015 153.36 174.285 ;
     RECT  2.16 174.555 153.36 174.825 ;
     RECT  2.16 175.095 153.36 175.365 ;
     RECT  2.16 175.635 153.36 175.905 ;
     RECT  2.16 176.175 153.36 176.445 ;
     RECT  2.16 176.715 153.36 176.985 ;
     RECT  2.16 177.255 153.36 177.525 ;
     RECT  2.16 177.795 153.36 178.065 ;
     RECT  2.16 178.335 153.36 178.605 ;
     RECT  2.16 178.875 153.36 179.145 ;
     RECT  2.16 179.415 153.36 179.685 ;
     RECT  2.16 179.955 153.36 180.225 ;
     RECT  2.16 180.495 153.36 180.765 ;
     RECT  2.16 181.035 153.36 181.305 ;
     RECT  2.16 181.575 153.36 181.845 ;
     RECT  2.16 182.115 153.36 182.385 ;
     RECT  2.16 182.655 153.36 182.925 ;
     RECT  2.16 183.195 153.36 183.465 ;
     RECT  2.16 183.735 153.36 184.005 ;
     RECT  2.16 184.275 153.36 184.545 ;
     RECT  2.16 184.815 153.36 185.085 ;
     RECT  2.16 185.355 153.36 185.625 ;
     RECT  2.16 185.895 153.36 186.165 ;
     RECT  2.16 186.435 153.36 186.705 ;
     RECT  2.16 186.975 153.36 187.245 ;
     RECT  2.16 187.515 153.36 187.785 ;
     RECT  2.16 188.055 153.36 188.325 ;
     RECT  2.16 188.595 153.36 188.865 ;
     RECT  2.16 189.135 153.36 189.405 ;
     RECT  2.16 189.675 153.36 189.945 ;
     RECT  2.16 190.215 153.36 190.485 ;
     RECT  2.16 190.755 153.36 191.025 ;
     RECT  2.16 191.295 153.36 191.565 ;
     RECT  2.16 191.835 153.36 192.105 ;
     RECT  2.16 192.375 153.36 192.645 ;
     RECT  2.16 192.915 153.36 193.185 ;
     RECT  2.16 193.455 153.36 193.725 ;
     RECT  2.16 193.995 153.36 194.265 ;
     RECT  2.16 194.535 153.36 194.805 ;
     RECT  2.16 195.075 153.36 195.345 ;
     RECT  2.16 195.615 153.36 195.885 ;
     RECT  2.16 196.155 153.36 196.425 ;
     RECT  2.16 196.695 153.36 196.965 ;
     RECT  2.16 197.235 153.36 197.505 ;
     RECT  2.16 197.775 153.36 198.045 ;
     RECT  2.16 198.315 153.36 198.585 ;
     RECT  2.16 198.855 153.36 199.125 ;
     RECT  2.16 199.395 153.36 199.665 ;
     RECT  2.16 199.935 153.36 200.205 ;
     RECT  2.16 200.475 153.36 200.745 ;
     RECT  2.16 201.015 153.36 201.285 ;
     RECT  2.16 201.555 153.36 201.825 ;
     RECT  2.16 202.095 153.36 202.365 ;
     RECT  2.16 202.635 153.36 202.905 ;
     RECT  2.16 203.175 153.36 203.445 ;
     RECT  2.16 203.715 153.36 203.985 ;
     RECT  2.16 204.255 153.36 204.525 ;
     RECT  2.16 204.795 153.36 205.065 ;
     RECT  2.16 205.335 153.36 205.605 ;
     RECT  2.16 205.875 153.36 206.145 ;
     RECT  2.16 206.415 153.36 206.685 ;
     RECT  2.16 206.955 153.36 207.225 ;
     RECT  2.16 207.495 153.36 207.765 ;
     RECT  2.16 208.035 153.36 208.305 ;
     RECT  2.16 208.575 153.36 208.845 ;
     RECT  2.16 209.115 153.36 209.385 ;
     RECT  2.16 209.655 153.36 209.925 ;
     RECT  2.16 210.195 153.36 210.465 ;
     RECT  2.16 210.735 153.36 211.005 ;
     RECT  2.16 211.275 153.36 211.545 ;
     RECT  2.16 211.815 153.36 212.085 ;
     RECT  2.16 212.355 153.36 212.625 ;
     RECT  2.16 212.895 153.36 213.165 ;
     RECT  2.16 213.435 153.36 213.705 ;
     RECT  2.16 213.975 153.36 214.245 ;
     RECT  2.16 214.515 153.36 214.785 ;
     RECT  2.16 215.055 153.36 215.325 ;
     RECT  2.16 215.595 153.36 215.865 ;
     RECT  2.16 216.135 153.36 216.405 ;
     RECT  2.16 216.675 153.36 216.945 ;
     RECT  2.16 217.215 153.36 217.485 ;
     RECT  2.16 217.755 153.36 218.025 ;
     RECT  2.16 218.295 153.36 218.565 ;
     RECT  2.16 218.835 153.36 219.105 ;
     RECT  2.16 219.375 153.36 219.645 ;
     RECT  2.16 219.915 153.36 220.185 ;
     RECT  2.16 220.455 153.36 220.725 ;
     RECT  2.16 220.995 153.36 221.265 ;
     RECT  2.16 221.535 153.36 221.805 ;
     RECT  2.16 222.075 153.36 222.345 ;
     RECT  2.16 222.615 153.36 222.885 ;
     RECT  2.16 223.155 153.36 223.425 ;
     RECT  2.16 223.695 153.36 223.965 ;
     RECT  2.16 224.235 153.36 224.505 ;
     RECT  2.16 224.775 153.36 225.045 ;
     RECT  2.16 225.315 153.36 225.585 ;
     RECT  2.16 225.855 153.36 226.125 ;
     RECT  2.16 226.395 153.36 226.665 ;
     RECT  2.16 226.935 153.36 227.205 ;
     RECT  2.16 227.475 153.36 227.745 ;
     RECT  2.16 228.015 153.36 228.285 ;
     RECT  2.16 228.555 153.36 228.825 ;
     RECT  2.16 229.095 153.36 229.365 ;
     RECT  2.16 229.635 153.36 229.905 ;
     RECT  2.16 230.175 153.36 230.445 ;
     RECT  2.16 230.715 153.36 230.985 ;
     RECT  2.16 231.255 153.36 231.525 ;
     RECT  2.16 231.795 153.36 232.065 ;
     RECT  2.16 232.335 153.36 232.605 ;
     RECT  2.16 232.875 153.36 233.145 ;
     RECT  2.16 233.415 153.36 233.685 ;
     RECT  2.16 233.955 153.36 234.225 ;
     RECT  2.16 234.495 153.36 234.765 ;
     RECT  2.16 235.035 153.36 235.305 ;
     RECT  2.16 235.575 153.36 235.845 ;
     RECT  2.16 236.115 153.36 236.385 ;
     RECT  2.16 236.655 153.36 236.925 ;
     RECT  2.16 237.195 153.36 237.465 ;
     RECT  2.16 237.735 153.36 238.005 ;
     RECT  2.16 238.275 153.36 238.545 ;
     RECT  2.16 238.815 153.36 239.085 ;
     RECT  2.16 239.355 153.36 239.625 ;
     RECT  2.16 239.895 153.36 240.165 ;
     RECT  2.16 240.435 153.36 240.705 ;
     RECT  2.16 240.975 153.36 241.245 ;
     RECT  2.16 241.515 153.36 241.785 ;
     RECT  2.16 242.055 153.36 242.325 ;
     RECT  2.16 242.595 153.36 242.865 ;
     RECT  2.16 243.135 153.36 243.405 ;
     RECT  2.16 243.675 153.36 243.945 ;
    LAYER M1 ;
     RECT  2.16 2.151 153.36 244.089 ;
    LAYER M2 ;
     RECT  0.103 125.19 0.319 125.208 ;
     RECT  0.427 170.046 0.463 170.064 ;
     RECT  0.463 178.416 0.499 178.434 ;
     RECT  0.103 129.942 0.535 129.96 ;
     RECT  0.463 181.89 0.535 182.412 ;
     RECT  0.463 183.636 0.535 183.654 ;
     RECT  0.103 222.282 0.535 222.3 ;
     RECT  0.463 170.046 0.563 171.108 ;
     RECT  0.499 178.146 0.563 178.434 ;
     RECT  0.535 181.782 0.563 182.412 ;
     RECT  0.535 183.51 0.563 183.654 ;
     RECT  0.463 186.408 0.563 187.119 ;
     RECT  0.103 79.758 0.787 79.776 ;
     RECT  0.319 125.19 0.823 125.514 ;
     RECT  0.103 88.902 0.859 88.92 ;
     RECT  0.751 98.082 0.895 98.1 ;
     RECT  0.859 119.826 0.895 119.844 ;
     RECT  0.103 151.002 0.895 151.02 ;
     RECT  0.751 102.546 0.931 102.564 ;
     RECT  0.931 102.474 0.959 102.564 ;
     RECT  0.427 96.606 0.967 96.624 ;
     RECT  0.895 97.416 0.967 98.64 ;
     RECT  0.535 129.744 0.967 129.96 ;
     RECT  0.103 167.544 0.967 167.562 ;
     RECT  0.967 36.9 1.003 36.918 ;
     RECT  0.967 167.076 1.003 167.562 ;
     RECT  0.391 166.158 1.039 166.176 ;
     RECT  0.895 30.96 1.075 30.978 ;
     RECT  0.463 24.444 1.111 24.462 ;
     RECT  0.823 124.956 1.147 125.514 ;
     RECT  1.039 166.158 1.175 166.284 ;
     RECT  0.103 126.432 1.435 126.45 ;
     RECT  0.967 129.744 1.435 130.068 ;
     RECT  0.103 197.712 1.435 197.73 ;
     RECT  1.435 91.44 1.471 91.458 ;
     RECT  1.435 129.744 1.471 130.104 ;
     RECT  1.471 91.44 1.507 91.494 ;
     RECT  0.787 79.758 1.543 79.884 ;
     RECT  0.895 119.754 1.543 119.844 ;
     RECT  1.111 192.456 1.543 192.474 ;
     RECT  1.111 118.134 1.579 118.152 ;
     RECT  1.543 191.916 1.579 192.474 ;
     RECT  1.579 118.134 1.615 118.224 ;
     RECT  1.579 191.916 1.615 193.014 ;
     RECT  0.931 124.11 1.723 124.128 ;
     RECT  1.543 79.758 1.831 80.118 ;
     RECT  0.931 80.946 1.831 80.964 ;
     RECT  1.651 32.31 1.867 32.328 ;
     RECT  0.959 102.474 1.867 102.492 ;
     RECT  1.831 117.09 1.939 117.108 ;
     RECT  1.615 118.134 1.939 118.494 ;
     RECT  1.075 121.986 1.975 122.004 ;
     RECT  0.895 151.002 1.975 151.128 ;
     RECT  1.003 104.976 2.011 104.994 ;
     RECT  1.831 79.758 2.047 80.964 ;
     RECT  1.723 123.192 2.083 124.128 ;
     RECT  1.147 124.884 2.083 125.514 ;
     RECT  0.535 200.754 2.083 200.772 ;
     RECT  1.471 129.006 2.119 130.104 ;
     RECT  2.083 133.056 2.119 133.074 ;
     RECT  1.003 36.9 2.155 37.494 ;
     RECT  2.011 104.976 2.155 105.12 ;
     RECT  2.119 133.056 2.155 133.614 ;
     RECT  2.119 204.804 2.155 204.822 ;
     RECT  0.103 6.822 2.16 6.84 ;
     RECT  0.103 8.514 2.16 8.532 ;
     RECT  0.103 17.658 2.16 17.676 ;
     RECT  0.535 20.196 2.16 20.214 ;
     RECT  0.103 22.752 2.16 22.77 ;
     RECT  1.111 24.444 2.16 24.732 ;
     RECT  1.075 30.96 2.16 31.518 ;
     RECT  1.867 32.31 2.16 32.868 ;
     RECT  2.155 36.9 2.16 37.764 ;
     RECT  1.579 43.11 2.16 43.128 ;
     RECT  1.615 45.27 2.16 45.288 ;
     RECT  0.103 58.662 2.16 58.68 ;
     RECT  0.103 74.592 2.16 74.61 ;
     RECT  2.119 78.408 2.16 78.426 ;
     RECT  2.047 79.596 2.16 80.964 ;
     RECT  1.975 82.53 2.16 82.548 ;
     RECT  0.283 84.726 2.16 84.744 ;
     RECT  0.859 88.902 2.16 89.064 ;
     RECT  0.319 90.018 2.16 90.036 ;
     RECT  1.507 90.9 2.16 91.494 ;
     RECT  1.147 92.952 2.16 92.97 ;
     RECT  0.391 94.95 2.16 94.968 ;
     RECT  0.967 96.606 2.16 98.982 ;
     RECT  0.463 100.926 2.16 100.944 ;
     RECT  1.867 102.474 2.16 103.032 ;
     RECT  2.155 104.706 2.16 105.12 ;
     RECT  0.283 107.91 2.16 107.928 ;
     RECT  1.147 108.882 2.16 108.9 ;
     RECT  1.975 113.274 2.16 113.292 ;
     RECT  2.011 116.046 2.16 116.064 ;
     RECT  1.939 117.09 2.16 118.494 ;
     RECT  1.543 119.556 2.16 119.844 ;
     RECT  0.787 120.6 2.16 120.618 ;
     RECT  1.975 121.68 2.16 122.004 ;
     RECT  2.083 123.192 2.16 125.514 ;
     RECT  1.435 126.432 2.16 126.594 ;
     RECT  1.471 128.016 2.16 128.034 ;
     RECT  2.119 129.006 2.16 130.644 ;
     RECT  2.155 131.976 2.16 131.994 ;
     RECT  2.155 133.056 2.16 133.884 ;
     RECT  2.047 136.566 2.16 136.584 ;
     RECT  0.103 142.092 2.16 143.46 ;
     RECT  0.355 144.666 2.16 144.684 ;
     RECT  0.103 145.872 2.16 145.89 ;
     RECT  1.975 151.002 2.16 151.362 ;
     RECT  0.103 156.708 2.16 156.726 ;
     RECT  0.211 157.896 2.16 157.914 ;
     RECT  2.011 162.486 2.16 162.504 ;
     RECT  1.687 164.772 2.16 164.79 ;
     RECT  1.175 166.158 2.16 166.212 ;
     RECT  1.003 167.076 2.16 167.868 ;
     RECT  1.507 169.164 2.16 169.182 ;
     RECT  0.563 170.046 2.16 170.064 ;
     RECT  0.563 170.982 2.16 171 ;
     RECT  0.103 176.112 2.16 176.13 ;
     RECT  0.563 178.146 2.16 178.164 ;
     RECT  1.075 180.846 2.16 180.864 ;
     RECT  0.563 181.782 2.16 181.8 ;
     RECT  0.563 183.51 2.16 183.528 ;
     RECT  0.563 186.912 2.16 186.93 ;
     RECT  1.615 191.916 2.16 193.284 ;
     RECT  1.651 194.508 2.16 194.526 ;
     RECT  1.435 197.712 2.16 198.414 ;
     RECT  2.083 200.286 2.16 200.772 ;
     RECT  2.155 204.804 2.16 204.894 ;
     RECT  0.103 208.512 2.16 208.53 ;
     RECT  0.535 212.022 2.16 212.04 ;
     RECT  0.103 213.642 2.16 213.66 ;
     RECT  0.103 217.152 2.16 217.17 ;
     RECT  0.535 222.282 2.16 222.876 ;
     RECT  0.103 227.952 2.16 227.97 ;
     RECT  0.103 238.788 2.16 238.806 ;
     RECT  2.16 2.151 153.36 244.089 ;
     RECT  153.36 130.284 153.455 139.374 ;
     RECT  153.36 113.346 153.491 121.014 ;
     RECT  153.36 142.866 153.527 143.604 ;
     RECT  153.36 105.714 153.599 106.704 ;
     RECT  153.455 130.284 153.599 133.974 ;
     RECT  153.36 94.536 153.635 98.244 ;
     RECT  153.36 140.166 153.887 142.11 ;
     RECT  153.36 144.486 153.887 149.904 ;
     RECT  153.36 154.206 153.887 155.034 ;
     RECT  153.36 91.98 153.923 93.744 ;
     RECT  153.599 105.786 153.923 106.704 ;
     RECT  153.491 113.346 153.923 118.854 ;
     RECT  153.599 130.356 153.923 133.974 ;
     RECT  153.887 144.486 153.923 146.394 ;
     RECT  153.887 147.6 153.923 149.904 ;
     RECT  153.635 94.536 154.427 98.172 ;
     RECT  153.36 104.526 154.427 104.814 ;
     RECT  153.36 150.732 154.427 152.604 ;
     RECT  153.887 154.206 154.427 154.224 ;
     RECT  153.923 91.98 154.463 92.43 ;
     RECT  153.923 93.726 154.463 93.744 ;
     RECT  154.427 94.536 154.463 95.904 ;
     RECT  154.427 96.696 154.463 98.172 ;
     RECT  153.36 99.162 154.463 100.764 ;
     RECT  153.36 101.556 154.463 103.734 ;
     RECT  154.427 104.526 154.463 104.724 ;
     RECT  153.923 106.218 154.463 106.704 ;
     RECT  153.36 107.532 154.463 109.134 ;
     RECT  153.36 109.926 154.463 111.294 ;
     RECT  153.36 112.086 154.463 112.374 ;
     RECT  153.923 115.056 154.463 118.854 ;
     RECT  153.491 119.682 154.463 121.014 ;
     RECT  153.36 121.842 154.463 122.094 ;
     RECT  153.36 123.156 154.463 124.254 ;
     RECT  153.36 125.046 154.463 129.384 ;
     RECT  153.923 130.896 154.463 131.31 ;
     RECT  153.923 132.138 154.463 133.974 ;
     RECT  153.455 135.036 154.463 139.374 ;
     RECT  153.887 140.166 154.463 140.184 ;
     RECT  153.887 141.246 154.463 142.11 ;
     RECT  153.527 142.866 154.463 143.532 ;
     RECT  153.923 144.486 154.463 145.854 ;
     RECT  153.923 147.6 154.463 148.662 ;
     RECT  153.923 149.418 154.463 149.904 ;
     RECT  154.427 150.732 154.463 151.254 ;
     RECT  154.427 152.046 154.463 152.604 ;
     RECT  153.887 155.016 154.463 155.034 ;
     RECT  154.463 95.148 154.499 95.166 ;
     RECT  154.463 99.162 154.499 99.756 ;
     RECT  154.463 100.656 154.499 100.674 ;
     RECT  154.463 102.276 154.499 102.294 ;
     RECT  154.463 104.526 154.499 104.544 ;
     RECT  154.463 108.846 154.499 108.864 ;
     RECT  153.923 113.346 154.499 113.994 ;
     RECT  154.463 115.506 154.499 115.524 ;
     RECT  154.463 119.682 154.499 119.7 ;
     RECT  154.463 121.842 154.499 121.86 ;
     RECT  154.463 124.146 154.499 124.164 ;
     RECT  154.463 126.306 154.499 126.324 ;
     RECT  154.463 128.196 154.499 128.214 ;
     RECT  154.463 129.366 154.499 129.384 ;
     RECT  154.463 136.764 154.499 136.782 ;
     RECT  154.463 138.996 154.499 139.014 ;
     RECT  154.463 143.514 154.499 143.532 ;
     RECT  154.463 145.746 154.499 145.764 ;
     RECT  154.463 147.6 154.499 147.618 ;
     RECT  154.463 148.644 154.499 148.662 ;
     RECT  154.463 106.56 155.435 106.578 ;
    LAYER M3 ;
     RECT  2.415 2.143 2.505 2.413 ;
     RECT  7.815 2.143 7.905 2.413 ;
     RECT  13.215 2.143 13.305 2.413 ;
     RECT  18.615 2.143 18.705 2.413 ;
     RECT  24.015 2.143 24.105 2.413 ;
     RECT  29.415 2.143 29.505 2.413 ;
     RECT  34.815 2.143 34.905 2.413 ;
     RECT  40.215 2.143 40.305 2.413 ;
     RECT  45.615 2.143 45.705 2.413 ;
     RECT  51.015 2.143 51.105 2.413 ;
     RECT  56.415 2.143 56.505 2.413 ;
     RECT  61.815 2.143 61.905 2.413 ;
     RECT  67.215 2.143 67.305 2.413 ;
     RECT  72.615 2.143 72.705 2.413 ;
     RECT  78.015 2.143 78.105 2.413 ;
     RECT  83.415 2.143 83.505 2.413 ;
     RECT  88.815 2.143 88.905 2.413 ;
     RECT  94.215 2.143 94.305 2.413 ;
     RECT  99.615 2.143 99.705 2.413 ;
     RECT  105.015 2.143 105.105 2.413 ;
     RECT  110.415 2.143 110.505 2.413 ;
     RECT  115.815 2.143 115.905 2.413 ;
     RECT  121.215 2.143 121.305 2.413 ;
     RECT  126.615 2.143 126.705 2.413 ;
     RECT  132.015 2.143 132.105 2.413 ;
     RECT  137.415 2.143 137.505 2.413 ;
     RECT  142.815 2.143 142.905 2.413 ;
     RECT  148.215 2.143 148.305 2.413 ;
     RECT  2.415 2.413 2.697 5.845 ;
     RECT  2.415 5.845 3.366 5.881 ;
     RECT  2.415 5.881 3.438 5.995 ;
     RECT  2.304 5.995 3.438 6.079 ;
     RECT  2.304 6.079 3.834 6.115 ;
     RECT  2.304 6.115 4.086 6.575 ;
     RECT  2.412 6.575 4.086 6.655 ;
     RECT  4.824 6.283 4.842 6.655 ;
     RECT  6.192 6.151 6.21 6.691 ;
     RECT  7.815 2.413 8.097 6.691 ;
     RECT  5.616 6.691 6.21 6.781 ;
     RECT  2.412 6.655 4.842 6.845 ;
     RECT  0.108 6.817 0.126 6.893 ;
     RECT  7.524 6.691 8.097 6.925 ;
     RECT  5.616 6.781 6.318 7.051 ;
     RECT  5.148 7.051 6.318 7.151 ;
     RECT  5.796 7.151 6.318 7.231 ;
     RECT  7.2 6.925 8.097 7.231 ;
     RECT  9.576 6.781 9.594 7.231 ;
     RECT  2.412 6.845 4.266 7.385 ;
     RECT  5.796 7.231 8.097 7.393 ;
     RECT  9.288 7.231 9.594 7.393 ;
     RECT  5.796 7.393 9.594 7.427 ;
     RECT  2.415 7.385 4.266 7.591 ;
     RECT  2.415 7.591 4.626 8.041 ;
     RECT  2.415 8.041 4.914 8.275 ;
     RECT  5.796 7.427 6.318 8.275 ;
     RECT  2.415 8.275 6.318 8.299 ;
     RECT  7.416 7.427 9.594 8.437 ;
     RECT  2.415 8.299 6.462 8.465 ;
     RECT  0.108 8.509 0.126 8.621 ;
     RECT  5.364 8.465 6.462 8.779 ;
     RECT  7.2 8.437 9.594 8.779 ;
     RECT  2.415 8.465 4.302 8.977 ;
     RECT  2.412 8.977 4.302 9.211 ;
     RECT  2.412 9.211 4.518 9.451 ;
     RECT  2.304 9.451 4.518 9.545 ;
     RECT  2.412 9.545 4.518 9.661 ;
     RECT  5.364 8.779 9.594 9.689 ;
     RECT  2.412 9.661 4.59 9.815 ;
     RECT  5.364 9.689 6.318 9.931 ;
     RECT  4.824 9.931 6.318 10.085 ;
     RECT  5.004 10.085 6.318 10.319 ;
     RECT  5.292 10.319 6.318 10.669 ;
     RECT  2.412 9.815 3.978 10.705 ;
     RECT  5.292 10.669 6.462 10.733 ;
     RECT  2.412 10.705 4.086 10.747 ;
     RECT  2.304 10.747 4.086 10.831 ;
     RECT  2.304 10.831 4.302 11.137 ;
     RECT  2.304 11.137 4.446 11.281 ;
     RECT  2.304 11.281 4.518 11.371 ;
     RECT  5.292 10.733 6.318 11.371 ;
     RECT  2.304 11.371 6.318 11.975 ;
     RECT  3.96 11.975 6.318 12.181 ;
     RECT  7.2 9.689 9.594 12.181 ;
     RECT  3.96 12.181 9.594 12.479 ;
     RECT  3.96 12.479 6.354 12.557 ;
     RECT  3.96 12.557 6.318 12.865 ;
     RECT  2.304 11.975 2.697 12.901 ;
     RECT  3.456 12.865 6.318 12.901 ;
     RECT  7.2 12.479 9.594 12.991 ;
     RECT  2.304 12.901 6.318 13.373 ;
     RECT  2.415 13.373 6.318 13.595 ;
     RECT  3.42 13.595 6.318 13.819 ;
     RECT  7.2 12.991 9.63 13.819 ;
     RECT  2.415 13.595 2.697 14.203 ;
     RECT  3.42 13.819 9.63 14.405 ;
     RECT  3.744 14.405 9.63 14.441 ;
     RECT  3.744 14.441 5.31 15.331 ;
     RECT  6.084 14.441 9.63 15.331 ;
     RECT  2.304 14.203 2.697 15.457 ;
     RECT  2.304 15.457 2.826 15.533 ;
     RECT  3.744 15.331 9.63 15.601 ;
     RECT  3.564 15.601 9.63 15.755 ;
     RECT  2.304 15.533 2.697 16.403 ;
     RECT  2.415 16.403 2.697 16.951 ;
     RECT  3.672 15.755 9.63 16.951 ;
     RECT  2.415 16.951 9.63 17.105 ;
     RECT  2.415 17.105 2.697 17.227 ;
     RECT  0.108 17.653 0.126 17.693 ;
     RECT  2.304 17.227 2.697 18.031 ;
     RECT  2.268 18.031 2.697 18.265 ;
     RECT  3.708 17.105 9.63 18.265 ;
     RECT  2.268 18.265 9.63 18.725 ;
     RECT  2.268 18.725 3.798 19.301 ;
     RECT  4.752 18.725 9.63 19.651 ;
     RECT  2.268 19.301 3.438 20.191 ;
     RECT  4.284 19.651 9.63 20.191 ;
     RECT  2.268 20.191 9.63 20.551 ;
     RECT  2.268 20.551 10.35 20.885 ;
     RECT  3.6 20.885 10.35 21.155 ;
     RECT  2.268 20.885 2.697 21.937 ;
     RECT  2.268 21.937 2.754 22.081 ;
     RECT  2.268 22.081 2.934 22.199 ;
     RECT  3.708 21.155 10.35 22.207 ;
     RECT  0.54 20.191 0.558 22.747 ;
     RECT  0.108 22.747 0.558 22.877 ;
     RECT  2.268 22.199 2.697 23.275 ;
     RECT  2.268 23.275 2.754 23.315 ;
     RECT  3.528 22.207 10.35 23.701 ;
     RECT  0.54 22.877 0.558 24.439 ;
     RECT  2.268 23.315 2.697 24.511 ;
     RECT  3.456 23.701 10.35 24.511 ;
     RECT  0.468 24.439 0.558 24.709 ;
     RECT  2.268 24.511 10.35 24.737 ;
     RECT  3.456 24.737 10.35 27.301 ;
     RECT  3.42 27.301 10.35 27.599 ;
     RECT  3.456 27.599 10.35 30.181 ;
     RECT  2.268 24.737 2.697 30.613 ;
     RECT  3.42 30.181 10.35 30.613 ;
     RECT  2.268 30.613 10.35 30.653 ;
     RECT  0.468 24.709 1.134 32.305 ;
     RECT  2.268 30.653 2.697 32.305 ;
     RECT  3.456 30.653 10.35 32.305 ;
     RECT  0.468 32.305 10.35 32.873 ;
     RECT  0.468 32.873 2.697 34.231 ;
     RECT  3.456 32.873 10.35 34.231 ;
     RECT  0.468 34.231 10.35 36.005 ;
     RECT  0.468 36.005 2.697 36.823 ;
     RECT  3.456 36.005 10.35 36.823 ;
     RECT  13.215 2.413 13.497 37.021 ;
     RECT  0.468 36.823 10.35 37.355 ;
     RECT  3.42 37.355 10.35 37.895 ;
     RECT  0.468 37.355 2.697 39.289 ;
     RECT  3.456 37.895 10.35 39.289 ;
     RECT  0.468 39.289 10.35 40.891 ;
     RECT  0.108 40.891 10.35 41.021 ;
     RECT  12.24 23.521 12.258 54.301 ;
     RECT  0.468 41.021 10.35 58.657 ;
     RECT  0.108 58.657 10.35 58.733 ;
     RECT  12.096 54.301 12.258 62.203 ;
     RECT  0.468 58.733 10.35 62.401 ;
     RECT  0.468 62.401 10.53 63.121 ;
     RECT  0.468 63.121 10.962 65.209 ;
     RECT  11.808 62.203 12.258 65.209 ;
     RECT  0.468 65.209 12.258 66.991 ;
     RECT  13.215 37.021 13.806 66.991 ;
     RECT  15.084 67.405 15.102 68.611 ;
     RECT  15.84 68.341 15.858 68.611 ;
     RECT  0.468 66.991 13.806 68.989 ;
     RECT  15.084 68.611 15.858 68.989 ;
     RECT  22.212 70.501 22.23 70.541 ;
     RECT  21.888 70.645 21.906 70.685 ;
     RECT  0.468 68.989 15.858 71.149 ;
     RECT  0.468 71.149 15.93 73.345 ;
     RECT  18.615 2.413 18.897 73.531 ;
     RECT  18.615 73.531 18.954 73.651 ;
     RECT  18.615 73.651 19.206 73.769 ;
     RECT  0.468 73.345 16.182 74.587 ;
     RECT  0.108 74.587 16.182 74.717 ;
     RECT  17.1 74.929 17.118 75.199 ;
     RECT  20.196 30.001 20.214 75.397 ;
     RECT  21.024 66.793 21.042 75.397 ;
     RECT  0.468 74.717 16.182 76.315 ;
     RECT  17.1 75.199 17.658 76.315 ;
     RECT  18.615 73.769 18.897 76.351 ;
     RECT  18.615 76.351 18.954 76.513 ;
     RECT  20.196 75.397 21.042 76.513 ;
     RECT  0.468 76.315 17.658 76.711 ;
     RECT  18.615 76.513 21.042 76.711 ;
     RECT  0.468 76.711 21.042 79.411 ;
     RECT  21.852 77.935 21.87 79.411 ;
     RECT  0.468 79.411 21.87 79.753 ;
     RECT  0.108 79.753 21.87 79.901 ;
     RECT  22.788 79.483 22.806 79.963 ;
     RECT  0.468 79.901 21.87 80.059 ;
     RECT  22.788 79.963 22.842 80.093 ;
     RECT  0.468 80.059 21.906 80.329 ;
     RECT  22.788 80.093 22.806 80.329 ;
     RECT  24.015 2.413 24.297 81.139 ;
     RECT  25.848 75.271 25.866 81.175 ;
     RECT  0.468 80.329 22.806 81.307 ;
     RECT  23.688 81.139 24.297 81.307 ;
     RECT  25.272 81.175 25.866 81.337 ;
     RECT  0.468 81.307 24.297 82.939 ;
     RECT  25.2 81.337 25.866 82.939 ;
     RECT  0.468 82.939 25.866 84.721 ;
     RECT  27.036 86.071 27.054 86.225 ;
     RECT  36.324 86.467 36.342 86.525 ;
     RECT  0.288 84.721 25.866 87.421 ;
     RECT  40.215 2.413 40.497 88.075 ;
     RECT  27.288 86.341 27.306 88.231 ;
     RECT  40.215 88.075 40.914 88.349 ;
     RECT  0.288 87.421 26.262 88.897 ;
     RECT  42.192 88.321 42.21 88.925 ;
     RECT  0.108 88.897 26.262 88.973 ;
     RECT  0.288 88.973 26.262 89.159 ;
     RECT  43.056 89.041 43.074 90.379 ;
     RECT  0.288 89.159 25.866 90.391 ;
     RECT  45.615 2.413 45.897 90.523 ;
     RECT  42.768 90.379 43.074 90.557 ;
     RECT  33.084 89.941 33.102 90.779 ;
     RECT  34.815 2.413 35.097 90.787 ;
     RECT  66.384 89.947 66.402 90.895 ;
     RECT  67.215 2.413 67.497 90.895 ;
     RECT  0.288 90.391 26.262 90.959 ;
     RECT  34.815 90.787 35.442 90.959 ;
     RECT  148.215 2.413 148.497 91.471 ;
     RECT  64.98 90.787 64.998 91.499 ;
     RECT  38.232 91.471 38.25 91.561 ;
     RECT  38.232 91.561 38.754 91.613 ;
     RECT  65.412 91.624 65.43 91.661 ;
     RECT  51.015 2.413 51.297 91.669 ;
     RECT  52.344 91.627 52.362 91.669 ;
     RECT  153.036 91.669 153.054 91.705 ;
     RECT  38.232 91.613 38.43 91.709 ;
     RECT  51.015 91.669 52.362 91.709 ;
     RECT  66.384 90.895 67.497 91.723 ;
     RECT  152.424 91.705 153.054 91.741 ;
     RECT  52.344 91.709 52.362 91.757 ;
     RECT  65.772 91.723 67.497 91.769 ;
     RECT  27.288 88.231 27.45 91.831 ;
     RECT  152.424 91.741 153.234 91.831 ;
     RECT  151.416 91.939 151.434 91.975 ;
     RECT  152.244 91.831 153.234 91.975 ;
     RECT  151.416 91.975 153.234 92.011 ;
     RECT  66.384 91.769 67.497 92.165 ;
     RECT  154.44 91.963 154.458 92.435 ;
     RECT  150.804 92.011 153.234 92.443 ;
     RECT  150.192 92.443 153.234 92.471 ;
     RECT  150.192 92.471 151.29 92.515 ;
     RECT  148.215 91.471 149.202 92.551 ;
     RECT  150.012 92.515 151.29 92.669 ;
     RECT  36.576 86.611 36.594 92.779 ;
     RECT  37.368 87.961 37.386 92.779 ;
     RECT  152.136 92.471 153.234 92.861 ;
     RECT  148.215 92.551 149.274 92.909 ;
     RECT  0.288 90.959 25.866 92.911 ;
     RECT  26.748 91.831 27.45 92.911 ;
     RECT  148.215 92.909 149.202 93.055 ;
     RECT  152.136 92.861 153.054 93.209 ;
     RECT  29.415 2.413 29.697 93.211 ;
     RECT  153.9 93.091 153.918 93.293 ;
     RECT  142.815 2.413 143.097 93.307 ;
     RECT  152.136 93.209 152.982 93.325 ;
     RECT  150.264 92.669 150.822 93.437 ;
     RECT  34.815 90.959 35.097 93.445 ;
     RECT  110.415 2.413 110.697 93.445 ;
     RECT  45.615 90.523 46.422 93.451 ;
     RECT  56.415 2.413 56.697 93.451 ;
     RECT  66.384 92.165 66.402 93.451 ;
     RECT  67.176 92.165 67.497 93.451 ;
     RECT  78.015 2.413 78.297 93.451 ;
     RECT  88.815 2.413 89.097 93.451 ;
     RECT  99.615 2.413 99.897 93.451 ;
     RECT  121.215 2.413 121.497 93.451 ;
     RECT  132.015 2.413 132.297 93.451 ;
     RECT  34.704 93.445 35.097 93.485 ;
     RECT  110.304 93.445 110.697 93.485 ;
     RECT  142.524 93.307 143.097 93.485 ;
     RECT  45.504 93.451 46.422 93.488 ;
     RECT  56.304 93.451 56.697 93.488 ;
     RECT  66.384 93.451 67.497 93.488 ;
     RECT  77.904 93.451 78.297 93.488 ;
     RECT  88.704 93.451 89.097 93.488 ;
     RECT  99.504 93.451 99.897 93.488 ;
     RECT  121.104 93.451 121.497 93.488 ;
     RECT  131.904 93.451 132.297 93.488 ;
     RECT  34.815 93.485 35.097 93.595 ;
     RECT  145.548 93.307 145.566 93.595 ;
     RECT  34.815 93.595 35.154 93.749 ;
     RECT  36.576 92.779 37.386 93.865 ;
     RECT  150.804 93.437 150.822 93.901 ;
     RECT  146.34 93.559 146.358 94.013 ;
     RECT  152.028 93.325 152.982 94.019 ;
     RECT  145.404 93.595 145.566 94.024 ;
     RECT  35.892 93.865 37.386 94.055 ;
     RECT  145.404 94.024 145.962 94.055 ;
     RECT  150.804 93.901 150.966 94.075 ;
     RECT  152.028 94.019 152.73 94.075 ;
     RECT  147.6 93.055 149.202 94.219 ;
     RECT  34.815 93.749 35.097 94.267 ;
     RECT  147.6 94.219 149.274 94.289 ;
     RECT  150.804 94.075 152.73 94.289 ;
     RECT  150.012 94.075 150.03 94.297 ;
     RECT  32.544 94.261 32.562 94.349 ;
     RECT  36.144 94.055 37.386 94.363 ;
     RECT  38.232 91.709 38.25 94.363 ;
     RECT  34.776 94.267 35.097 94.397 ;
     RECT  33.516 90.931 33.534 94.441 ;
     RECT  149.976 94.297 150.03 94.531 ;
     RECT  150.804 94.289 151.47 94.531 ;
     RECT  154.44 93.691 154.458 94.555 ;
     RECT  149.976 94.531 151.47 94.559 ;
     RECT  149.976 94.559 150.966 94.595 ;
     RECT  147.6 94.289 149.202 94.631 ;
     RECT  150.48 94.595 150.498 94.631 ;
     RECT  36.144 94.363 38.25 94.739 ;
     RECT  154.404 94.555 154.458 94.829 ;
     RECT  0.288 92.911 27.45 94.891 ;
     RECT  31.176 94.531 31.194 94.945 ;
     RECT  145.944 94.055 145.962 94.945 ;
     RECT  36.144 94.739 37.386 95.071 ;
     RECT  33.084 94.441 33.534 95.135 ;
     RECT  154.44 94.829 154.458 95.143 ;
     RECT  145.944 94.945 146.214 95.173 ;
     RECT  145.944 95.173 146.61 95.213 ;
     RECT  152.208 94.289 152.73 95.215 ;
     RECT  66.384 93.488 66.402 95.227 ;
     RECT  67.176 93.488 67.497 95.227 ;
     RECT  145.944 95.213 145.962 95.243 ;
     RECT  33.516 95.135 33.534 95.251 ;
     RECT  146.88 95.215 146.898 95.369 ;
     RECT  39.348 94.981 39.366 95.405 ;
     RECT  152.208 95.215 153.054 95.449 ;
     RECT  154.44 95.143 154.494 95.453 ;
     RECT  40.215 88.349 40.497 95.485 ;
     RECT  150.444 95.449 150.462 95.521 ;
     RECT  151.884 95.449 153.054 95.521 ;
     RECT  150.444 95.521 150.858 95.639 ;
     RECT  151.812 95.521 153.054 95.639 ;
     RECT  28.764 93.211 29.697 95.647 ;
     RECT  35.928 95.071 37.386 95.675 ;
     RECT  150.444 95.639 150.714 95.741 ;
     RECT  151.812 95.639 152.226 95.791 ;
     RECT  33.516 95.251 33.93 95.909 ;
     RECT  150.156 95.791 150.354 95.909 ;
     RECT  150.156 95.909 150.318 95.945 ;
     RECT  151.632 95.791 152.226 95.945 ;
     RECT  31.104 94.945 31.194 96.187 ;
     RECT  148.215 94.631 149.202 96.187 ;
     RECT  30.636 96.187 31.194 96.224 ;
     RECT  148.215 96.187 149.454 96.224 ;
     RECT  33.624 95.909 33.93 96.427 ;
     RECT  34.815 94.397 35.097 96.427 ;
     RECT  150.264 95.945 150.318 96.485 ;
     RECT  28.512 95.647 29.697 96.529 ;
     RECT  28.512 96.529 29.826 96.557 ;
     RECT  152.064 95.945 152.226 96.601 ;
     RECT  153.036 96.565 153.054 96.601 ;
     RECT  154.44 95.453 154.458 96.601 ;
     RECT  150.3 96.485 150.318 96.719 ;
     RECT  148.215 96.224 149.058 96.749 ;
     RECT  154.404 96.601 154.458 96.749 ;
     RECT  33.624 96.427 35.097 96.755 ;
     RECT  147.348 96.715 147.366 96.755 ;
     RECT  152.064 96.601 153.054 96.989 ;
     RECT  30.744 96.224 31.194 97.025 ;
     RECT  0.252 94.891 27.45 97.051 ;
     RECT  148.215 96.749 148.734 97.097 ;
     RECT  152.064 96.989 153.018 97.141 ;
     RECT  148.215 97.097 148.662 97.181 ;
     RECT  150.84 97.105 150.858 97.181 ;
     RECT  0.216 97.051 27.45 97.231 ;
     RECT  65.592 96.601 65.61 97.295 ;
     RECT  151.812 97.141 153.018 97.331 ;
     RECT  66.384 95.227 67.497 97.411 ;
     RECT  151.812 97.331 152.334 97.681 ;
     RECT  36.144 95.675 37.386 97.771 ;
     RECT  150.336 97.723 150.354 97.771 ;
     RECT  150.156 97.771 150.354 97.799 ;
     RECT  151.452 97.681 152.334 97.799 ;
     RECT  36.144 97.771 37.458 97.951 ;
     RECT  38.232 94.739 38.25 97.951 ;
     RECT  0.216 97.231 27.954 98.105 ;
     RECT  153.612 98.011 153.63 98.185 ;
     RECT  33.912 96.755 35.097 98.221 ;
     RECT  36.144 97.951 38.25 98.221 ;
     RECT  152.64 98.185 153.63 98.249 ;
     RECT  151.704 97.799 151.902 98.375 ;
     RECT  148.215 97.181 148.497 98.455 ;
     RECT  154.44 96.749 154.458 98.477 ;
     RECT  33.912 98.221 38.25 98.483 ;
     RECT  38.232 98.483 38.25 98.491 ;
     RECT  150.156 97.799 150.174 98.581 ;
     RECT  147.78 98.455 148.497 98.621 ;
     RECT  33.912 98.483 37.386 98.645 ;
     RECT  152.64 98.249 153.522 98.851 ;
     RECT  148.215 98.621 148.497 98.875 ;
     RECT  146.052 98.725 146.07 98.909 ;
     RECT  65.844 97.411 67.497 98.915 ;
     RECT  66.708 98.915 67.497 98.959 ;
     RECT  0.216 98.105 27.918 99.031 ;
     RECT  28.764 96.557 29.826 99.031 ;
     RECT  148.215 98.875 149.094 99.031 ;
     RECT  34.704 98.645 37.386 99.059 ;
     RECT  151.38 99.031 151.398 99.121 ;
     RECT  152.136 98.851 153.522 99.121 ;
     RECT  148.215 99.031 149.238 99.149 ;
     RECT  150.156 98.581 150.462 99.163 ;
     RECT  148.215 99.149 149.094 99.208 ;
     RECT  0.216 99.031 27.99 99.301 ;
     RECT  28.764 99.031 29.898 99.301 ;
     RECT  149.904 99.163 150.462 99.301 ;
     RECT  151.38 99.121 153.522 99.301 ;
     RECT  34.704 99.059 36.162 99.391 ;
     RECT  45.615 93.488 46.422 99.391 ;
     RECT  56.415 93.488 56.697 99.391 ;
     RECT  78.015 93.488 78.297 99.391 ;
     RECT  88.815 93.488 89.097 99.391 ;
     RECT  99.615 93.488 99.897 99.391 ;
     RECT  110.415 93.485 110.697 99.391 ;
     RECT  121.215 93.488 121.497 99.391 ;
     RECT  132.015 93.488 132.297 99.391 ;
     RECT  142.815 93.485 143.097 99.391 ;
     RECT  149.904 99.301 153.522 99.419 ;
     RECT  34.668 99.391 36.162 99.437 ;
     RECT  45.504 99.391 46.422 99.437 ;
     RECT  56.304 99.391 56.697 99.437 ;
     RECT  77.904 99.391 78.297 99.437 ;
     RECT  88.704 99.391 89.097 99.437 ;
     RECT  99.504 99.391 99.897 99.437 ;
     RECT  110.304 99.391 110.697 99.437 ;
     RECT  121.104 99.391 121.497 99.437 ;
     RECT  131.904 99.391 132.297 99.437 ;
     RECT  142.704 99.391 143.097 99.437 ;
     RECT  0.216 99.301 29.898 99.455 ;
     RECT  149.904 99.419 151.47 99.455 ;
     RECT  150.912 99.455 151.47 99.527 ;
     RECT  146.484 99.403 146.502 99.533 ;
     RECT  154.476 99.157 154.494 99.773 ;
     RECT  37.152 99.059 37.386 99.869 ;
     RECT  147.456 99.841 147.474 99.883 ;
     RECT  147.312 99.883 147.474 99.959 ;
     RECT  150.912 99.527 151.038 99.959 ;
     RECT  148.215 99.208 148.497 99.979 ;
     RECT  150.912 99.959 150.93 99.995 ;
     RECT  152.424 99.419 153.522 99.995 ;
     RECT  31.104 97.025 31.194 100.111 ;
     RECT  31.932 97.141 31.95 100.111 ;
     RECT  152.568 99.995 153.522 100.139 ;
     RECT  37.152 99.869 37.242 100.409 ;
     RECT  149.904 99.455 150.066 100.499 ;
     RECT  154.44 100.171 154.458 100.651 ;
     RECT  31.104 100.111 31.95 100.769 ;
     RECT  150.84 100.651 150.858 100.805 ;
     RECT  152.568 100.139 153.018 100.885 ;
     RECT  40.215 95.485 40.59 101.039 ;
     RECT  152.568 100.885 153.054 101.039 ;
     RECT  154.44 100.651 154.494 101.069 ;
     RECT  147.924 99.979 148.497 101.155 ;
     RECT  152.568 101.039 153.018 101.191 ;
     RECT  151.02 101.191 151.038 101.309 ;
     RECT  33.084 100.741 33.102 101.345 ;
     RECT  149.904 100.499 149.922 101.345 ;
     RECT  147.924 101.155 148.986 101.419 ;
     RECT  152.388 101.191 153.018 101.425 ;
     RECT  147.6 101.419 148.986 101.453 ;
     RECT  70.128 89.179 70.146 101.579 ;
     RECT  152.208 101.425 153.018 101.651 ;
     RECT  152.208 101.651 152.946 101.731 ;
     RECT  150.156 101.731 150.174 101.885 ;
     RECT  28.764 99.455 29.898 102.091 ;
     RECT  147.6 101.453 148.497 102.119 ;
     RECT  147.888 102.119 148.497 102.271 ;
     RECT  154.44 101.069 154.458 102.271 ;
     RECT  151.812 101.731 152.946 102.389 ;
     RECT  147.888 102.271 148.914 102.425 ;
     RECT  152.136 102.389 152.946 102.541 ;
     RECT  147.888 102.425 148.497 102.605 ;
     RECT  28.764 102.091 30.186 102.667 ;
     RECT  28.764 102.667 30.258 102.767 ;
     RECT  154.44 102.271 154.494 102.797 ;
     RECT  152.136 102.541 153.09 102.929 ;
     RECT  152.496 102.929 153.09 102.965 ;
     RECT  146.484 101.587 146.502 103.073 ;
     RECT  149.904 102.811 149.922 103.081 ;
     RECT  152.496 102.965 153.054 103.271 ;
     RECT  149.328 103.081 149.922 103.351 ;
     RECT  151.056 102.811 151.074 103.351 ;
     RECT  149.328 103.351 150.066 103.505 ;
     RECT  150.84 103.351 151.074 103.505 ;
     RECT  0.216 99.455 27.99 103.531 ;
     RECT  0.108 103.531 27.99 103.649 ;
     RECT  0.108 103.649 26.802 103.661 ;
     RECT  28.764 102.767 29.898 103.711 ;
     RECT  147.924 102.605 148.497 103.711 ;
     RECT  146.88 103.621 147.042 103.739 ;
     RECT  147.924 103.711 148.806 103.855 ;
     RECT  28.764 103.711 30.294 103.891 ;
     RECT  31.104 100.769 31.194 103.891 ;
     RECT  149.904 103.505 150.066 103.891 ;
     RECT  147.852 103.855 148.806 104.009 ;
     RECT  149.904 103.891 150.606 104.009 ;
     RECT  152.568 103.271 153.054 104.009 ;
     RECT  28.764 103.891 31.194 104.045 ;
     RECT  30.672 104.045 31.194 104.153 ;
     RECT  149.904 104.009 150.426 104.153 ;
     RECT  152.568 104.009 152.982 104.161 ;
     RECT  154.44 102.797 154.458 104.491 ;
     RECT  154.404 104.491 154.458 104.521 ;
     RECT  147.852 104.009 148.497 104.665 ;
     RECT  33.912 98.645 33.93 104.729 ;
     RECT  147.78 104.665 148.497 104.779 ;
     RECT  147.636 104.779 148.497 104.819 ;
     RECT  154.404 104.521 154.494 104.819 ;
     RECT  147.708 104.819 148.497 104.861 ;
     RECT  61.815 2.413 62.097 104.923 ;
     RECT  154.476 104.819 154.494 104.957 ;
     RECT  147.924 104.861 148.497 104.971 ;
     RECT  150.228 104.153 150.426 105.061 ;
     RECT  151.38 104.161 152.982 105.061 ;
     RECT  94.215 2.413 94.497 105.067 ;
     RECT  61.815 104.923 62.73 105.089 ;
     RECT  147.924 104.971 148.878 105.089 ;
     RECT  150.228 105.061 152.982 105.089 ;
     RECT  58.716 105.067 58.734 105.197 ;
     RECT  94.215 105.067 94.626 105.197 ;
     RECT  63.036 105.163 63.054 105.269 ;
     RECT  91.26 105.163 91.278 105.269 ;
     RECT  150.264 105.089 152.982 105.355 ;
     RECT  0.216 103.661 26.802 105.511 ;
     RECT  27.612 103.649 27.99 105.511 ;
     RECT  147.924 105.089 148.77 105.629 ;
     RECT  150.264 105.355 153.594 105.629 ;
     RECT  151.992 105.629 153.594 105.737 ;
     RECT  0.216 105.511 27.99 105.739 ;
     RECT  28.764 104.045 29.898 105.739 ;
     RECT  150.264 105.629 150.75 105.809 ;
     RECT  153.9 105.781 153.918 105.821 ;
     RECT  151.992 105.737 153.054 105.899 ;
     RECT  38.232 98.491 38.97 106.447 ;
     RECT  38.196 106.447 38.97 106.493 ;
     RECT  146.484 105.067 146.502 106.511 ;
     RECT  147.924 105.629 148.662 106.549 ;
     RECT  151.992 105.899 153.018 106.555 ;
     RECT  147.924 106.549 148.806 106.681 ;
     RECT  154.44 106.213 154.458 106.709 ;
     RECT  149.904 106.555 149.922 106.825 ;
     RECT  151.596 106.555 153.018 106.825 ;
     RECT  149.904 106.825 149.994 106.861 ;
     RECT  45.615 99.437 46.422 106.979 ;
     RECT  149.688 106.861 149.994 106.979 ;
     RECT  151.596 106.825 153.054 106.979 ;
     RECT  66.708 98.959 67.914 107.015 ;
     RECT  147.708 106.681 148.806 107.095 ;
     RECT  155.412 106.555 155.43 107.117 ;
     RECT  147.564 107.095 148.806 107.131 ;
     RECT  149.688 106.979 149.85 107.131 ;
     RECT  150.732 105.809 150.75 107.131 ;
     RECT  151.596 106.979 153.018 107.131 ;
     RECT  147.564 107.131 149.85 107.165 ;
     RECT  64.332 92.371 64.35 107.249 ;
     RECT  150.732 107.131 153.018 107.249 ;
     RECT  147.924 107.165 149.634 107.285 ;
     RECT  150.732 107.249 152.946 107.285 ;
     RECT  0.216 105.739 29.898 107.357 ;
     RECT  46.836 107.131 46.854 107.555 ;
     RECT  151.164 107.285 152.946 107.555 ;
     RECT  47.628 95.251 47.646 107.671 ;
     RECT  146.484 107.761 146.502 107.897 ;
     RECT  34.704 99.437 36.162 108.059 ;
     RECT  151.668 107.555 152.946 108.059 ;
     RECT  149.76 107.941 149.778 108.095 ;
     RECT  147.924 107.285 148.806 108.175 ;
     RECT  147.78 108.175 148.806 108.221 ;
     RECT  150.768 108.175 150.786 108.329 ;
     RECT  152.46 108.059 152.946 108.329 ;
     RECT  149.94 108.211 149.958 108.365 ;
     RECT  151.668 108.059 151.686 108.599 ;
     RECT  154.44 107.515 154.458 108.841 ;
     RECT  28.44 107.357 29.898 108.869 ;
     RECT  34.704 108.059 35.097 108.955 ;
     RECT  36.144 108.059 36.162 108.955 ;
     RECT  153 108.445 153.018 108.985 ;
     RECT  146.268 108.985 146.286 109.037 ;
     RECT  151.704 108.841 151.722 109.111 ;
     RECT  150.444 108.841 150.606 109.139 ;
     RECT  147.924 108.221 148.497 109.183 ;
     RECT  149.292 108.841 149.31 109.183 ;
     RECT  0.216 107.357 27.63 109.211 ;
     RECT  147.924 109.183 149.31 109.255 ;
     RECT  154.44 108.841 154.494 109.277 ;
     RECT  147.924 109.255 149.346 109.283 ;
     RECT  149.328 109.283 149.346 109.291 ;
     RECT  151.704 109.111 152.262 109.381 ;
     RECT  153 108.985 153.054 109.381 ;
     RECT  151.704 109.381 153.054 109.759 ;
     RECT  151.524 109.759 153.054 109.949 ;
     RECT  150.66 109.831 150.678 109.985 ;
     RECT  151.74 109.949 153.054 109.985 ;
     RECT  149.328 109.291 149.814 109.997 ;
     RECT  152.856 109.985 153.054 110.107 ;
     RECT  147.924 109.283 148.497 110.191 ;
     RECT  149.328 109.997 149.562 110.191 ;
     RECT  151.74 109.985 152.01 110.219 ;
     RECT  152.856 110.107 153.522 110.219 ;
     RECT  147.924 110.191 149.562 110.227 ;
     RECT  147.492 110.227 149.562 110.237 ;
     RECT  146.484 110.191 146.502 110.399 ;
     RECT  153 110.219 153.522 110.399 ;
     RECT  150.408 110.371 150.426 110.489 ;
     RECT  147.492 110.237 148.497 110.497 ;
     RECT  147.348 110.497 148.497 110.573 ;
     RECT  152.1 110.911 152.118 111.001 ;
     RECT  153 110.399 153.018 111.001 ;
     RECT  154.44 109.277 154.458 111.073 ;
     RECT  0.216 109.211 27.054 111.181 ;
     RECT  149.328 110.237 149.562 111.181 ;
     RECT  34.704 108.955 36.162 111.209 ;
     RECT  149.328 111.181 150.066 111.299 ;
     RECT  30.852 104.153 31.194 111.307 ;
     RECT  31.932 100.769 31.95 111.307 ;
     RECT  152.1 111.001 153.018 111.335 ;
     RECT  151.128 110.839 151.146 111.415 ;
     RECT  153.9 111.073 154.458 111.437 ;
     RECT  0.216 111.181 27.27 111.451 ;
     RECT  150.948 111.415 151.146 111.451 ;
     RECT  152.1 111.335 152.586 111.451 ;
     RECT  150.84 111.451 151.146 111.541 ;
     RECT  151.92 111.451 152.586 111.541 ;
     RECT  65.844 98.915 65.862 111.569 ;
     RECT  150.84 111.541 152.586 111.605 ;
     RECT  150.84 111.605 151.29 111.641 ;
     RECT  149.328 111.299 149.742 111.725 ;
     RECT  150.948 111.641 151.29 111.875 ;
     RECT  30.852 111.307 31.95 112.019 ;
     RECT  152.1 111.605 152.586 112.019 ;
     RECT  152.892 112.081 152.91 112.181 ;
     RECT  147.924 110.573 148.497 112.315 ;
     RECT  37.224 100.409 37.242 112.379 ;
     RECT  150.948 111.875 151.002 112.387 ;
     RECT  147.348 112.315 148.497 112.415 ;
     RECT  147.924 112.415 148.497 112.531 ;
     RECT  150.48 112.387 151.002 112.559 ;
     RECT  147.924 112.531 148.554 112.649 ;
     RECT  149.328 111.725 149.346 112.651 ;
     RECT  150.84 112.559 151.002 112.685 ;
     RECT  152.1 112.019 152.118 112.801 ;
     RECT  146.484 112.621 146.502 112.829 ;
     RECT  151.92 112.801 152.55 113.071 ;
     RECT  151.92 113.071 153.018 113.131 ;
     RECT  150.984 112.685 151.002 113.341 ;
     RECT  151.92 113.131 153.558 113.341 ;
     RECT  154.44 111.437 154.458 113.341 ;
     RECT  147.924 112.649 148.497 113.419 ;
     RECT  149.328 112.651 150.066 113.419 ;
     RECT  30.852 112.019 31.194 113.459 ;
     RECT  52.272 113.419 52.29 113.459 ;
     RECT  150.984 113.341 153.558 113.459 ;
     RECT  154.44 113.341 154.494 113.459 ;
     RECT  150.984 113.459 151.146 113.495 ;
     RECT  151.92 113.459 153.558 113.495 ;
     RECT  51.015 91.709 51.297 113.503 ;
     RECT  151.92 113.495 152.154 113.531 ;
     RECT  51.015 113.503 51.93 113.549 ;
     RECT  28.44 108.869 29.697 113.563 ;
     RECT  30.852 113.459 30.942 113.563 ;
     RECT  152.892 113.495 153.558 113.639 ;
     RECT  150.984 113.495 151.11 113.881 ;
     RECT  147.924 113.419 150.066 113.885 ;
     RECT  28.44 113.563 30.942 113.999 ;
     RECT  150.912 113.881 151.11 113.999 ;
     RECT  154.476 113.459 154.494 114.029 ;
     RECT  149.364 113.885 150.066 114.035 ;
     RECT  38.232 106.493 38.97 114.269 ;
     RECT  38.376 114.269 38.97 114.377 ;
     RECT  152.892 113.639 152.946 114.385 ;
     RECT  153.9 114.421 153.918 114.461 ;
     RECT  34.74 111.209 36.162 114.511 ;
     RECT  45.615 106.979 45.897 114.511 ;
     RECT  51.015 113.549 51.297 114.511 ;
     RECT  149.652 114.035 150.066 114.511 ;
     RECT  150.912 113.999 151.038 114.511 ;
     RECT  28.44 113.999 30.87 114.539 ;
     RECT  149.652 114.511 151.038 114.539 ;
     RECT  152.892 114.385 152.982 114.539 ;
     RECT  30.744 114.539 30.87 114.557 ;
     RECT  34.704 114.511 36.162 114.557 ;
     RECT  45.504 114.511 45.897 114.557 ;
     RECT  50.724 114.511 51.606 114.557 ;
     RECT  152.136 113.531 152.154 114.655 ;
     RECT  46.98 107.671 47.646 114.781 ;
     RECT  0.216 111.451 27.522 114.809 ;
     RECT  46.98 114.781 48.114 114.845 ;
     RECT  0.216 114.809 25.938 114.893 ;
     RECT  152.136 114.655 152.802 114.961 ;
     RECT  66.852 107.015 67.914 114.989 ;
     RECT  147.924 113.885 148.497 115.087 ;
     RECT  38.628 114.377 38.97 115.115 ;
     RECT  49.212 114.961 49.23 115.133 ;
     RECT  147.924 115.087 149.094 115.133 ;
     RECT  150.084 114.539 151.038 115.133 ;
     RECT  150.984 115.133 151.038 115.231 ;
     RECT  151.812 114.961 152.802 115.231 ;
     RECT  150.084 115.133 150.246 115.393 ;
     RECT  34.74 114.557 36.162 115.421 ;
     RECT  150.984 115.231 152.802 115.465 ;
     RECT  154.44 114.859 154.458 115.501 ;
     RECT  149.868 115.393 150.246 115.591 ;
     RECT  149.292 115.591 150.246 115.619 ;
     RECT  147.924 115.133 148.497 115.627 ;
     RECT  147.78 115.627 148.497 115.709 ;
     RECT  154.44 115.501 154.494 115.757 ;
     RECT  150.984 115.465 152.946 115.867 ;
     RECT  69.336 99.571 69.354 115.889 ;
     RECT  150.84 115.867 152.946 115.889 ;
     RECT  149.292 115.619 149.886 115.925 ;
     RECT  150.84 115.889 151.002 115.925 ;
     RECT  146.484 115.861 146.502 116.069 ;
     RECT  151.812 115.889 152.874 116.195 ;
     RECT  148.215 115.709 148.497 116.311 ;
     RECT  27.036 114.809 27.522 116.339 ;
     RECT  148.215 116.311 148.986 116.429 ;
     RECT  151.992 116.195 152.874 116.429 ;
     RECT  152.532 116.429 152.874 116.501 ;
     RECT  28.44 114.539 29.697 116.581 ;
     RECT  30.852 114.557 30.87 116.581 ;
     RECT  149.76 115.925 149.886 116.671 ;
     RECT  27.036 116.339 27.054 116.699 ;
     RECT  152.568 116.501 152.874 116.969 ;
     RECT  64.08 107.365 64.098 117.077 ;
     RECT  152.856 116.969 152.874 117.085 ;
     RECT  28.44 116.581 30.87 117.275 ;
     RECT  149.364 116.671 149.886 117.275 ;
     RECT  30.852 117.275 30.87 117.391 ;
     RECT  31.932 112.019 31.95 117.391 ;
     RECT  150.984 115.925 151.002 117.451 ;
     RECT  150.84 117.451 151.002 117.509 ;
     RECT  150.84 117.509 150.858 117.545 ;
     RECT  154.44 115.757 154.458 117.661 ;
     RECT  30.852 117.391 31.95 117.779 ;
     RECT  149.868 117.275 149.886 117.787 ;
     RECT  151.812 117.661 151.83 117.815 ;
     RECT  152.856 117.085 153.018 117.815 ;
     RECT  149.868 117.787 150.498 117.887 ;
     RECT  153.9 117.661 154.458 117.917 ;
     RECT  147.384 117.481 147.402 117.931 ;
     RECT  148.215 116.429 148.497 117.931 ;
     RECT  152.856 117.815 152.874 117.931 ;
     RECT  146.592 117.895 146.61 117.965 ;
     RECT  152.136 117.931 152.874 118.049 ;
     RECT  30.852 117.779 30.87 118.165 ;
     RECT  147.384 117.931 148.497 118.201 ;
     RECT  34.74 115.421 35.622 118.229 ;
     RECT  147.384 118.201 148.986 118.319 ;
     RECT  152.424 118.049 152.874 118.319 ;
     RECT  30.744 118.165 30.87 118.355 ;
     RECT  0.216 114.893 25.866 118.471 ;
     RECT  147.384 118.319 148.842 118.499 ;
     RECT  0.216 118.471 26.118 118.541 ;
     RECT  151.164 118.471 151.182 118.589 ;
     RECT  152.424 118.319 152.802 118.589 ;
     RECT  149.868 117.887 149.922 118.625 ;
     RECT  70.596 101.731 70.614 118.697 ;
     RECT  146.484 118.561 146.502 118.697 ;
     RECT  147.384 118.499 148.497 118.739 ;
     RECT  152.424 118.589 152.55 118.831 ;
     RECT  154.44 117.917 154.458 118.859 ;
     RECT  152.028 118.831 152.55 118.931 ;
     RECT  28.44 117.275 29.697 119.011 ;
     RECT  148.215 118.739 148.497 119.281 ;
     RECT  43.056 90.557 43.074 119.399 ;
     RECT  148.215 119.281 148.698 119.399 ;
     RECT  146.556 119.371 146.574 119.435 ;
     RECT  28.44 119.011 30.042 119.443 ;
     RECT  30.852 118.355 30.87 119.443 ;
     RECT  153.468 119.179 153.486 119.507 ;
     RECT  149.868 118.625 149.886 119.551 ;
     RECT  46.98 114.845 47.646 119.579 ;
     RECT  152.244 118.931 152.55 119.641 ;
     RECT  149.868 119.551 150.282 119.669 ;
     RECT  154.44 119.611 154.458 119.677 ;
     RECT  149.868 119.669 150.102 119.705 ;
     RECT  152.244 119.641 152.694 119.785 ;
     RECT  154.44 119.677 154.494 120.077 ;
     RECT  149.868 119.705 149.886 120.091 ;
     RECT  31.932 117.779 31.95 120.119 ;
     RECT  149.616 120.091 149.886 120.139 ;
     RECT  149.472 120.139 149.886 120.209 ;
     RECT  152.244 119.785 153.054 120.209 ;
     RECT  151.164 119.821 151.326 120.217 ;
     RECT  147.384 118.739 147.438 120.475 ;
     RECT  148.215 119.399 148.497 120.475 ;
     RECT  152.244 120.209 153.018 120.479 ;
     RECT  150.948 120.217 151.326 120.515 ;
     RECT  151.02 120.515 151.326 120.595 ;
     RECT  0.216 118.541 25.866 120.631 ;
     RECT  147.384 120.475 148.497 120.631 ;
     RECT  151.02 120.595 151.398 120.749 ;
     RECT  147.384 120.631 148.914 120.785 ;
     RECT  34.74 118.229 35.097 120.929 ;
     RECT  147.384 120.785 148.626 121.019 ;
     RECT  146.484 120.829 146.502 121.055 ;
     RECT  152.496 120.479 153.018 121.091 ;
     RECT  0.216 120.631 26.514 121.325 ;
     RECT  151.02 120.749 151.038 121.369 ;
     RECT  152.496 121.091 152.982 121.369 ;
     RECT  149.868 120.209 149.886 121.387 ;
     RECT  150.84 121.369 151.038 121.421 ;
     RECT  152.352 121.369 152.982 121.441 ;
     RECT  149.868 121.387 150.102 121.531 ;
     RECT  26.748 121.369 26.766 121.675 ;
     RECT  154.44 120.077 154.458 121.771 ;
     RECT  151.92 121.441 152.982 121.801 ;
     RECT  149.868 121.531 150.282 121.829 ;
     RECT  153.9 121.771 154.458 121.837 ;
     RECT  153.9 121.837 154.494 121.937 ;
     RECT  148.215 121.019 148.626 121.945 ;
     RECT  149.868 121.829 150.102 121.945 ;
     RECT  151.776 121.801 152.982 121.945 ;
     RECT  148.215 121.945 150.102 121.973 ;
     RECT  151.776 121.945 153.054 121.981 ;
     RECT  151.056 121.981 153.054 122.099 ;
     RECT  151.056 122.099 151.074 122.135 ;
     RECT  154.44 121.937 154.494 122.237 ;
     RECT  26.748 121.675 27.486 122.251 ;
     RECT  152.568 122.099 153.054 122.369 ;
     RECT  26.748 122.251 27.558 122.405 ;
     RECT  28.44 119.443 30.87 122.449 ;
     RECT  0.216 121.325 25.974 122.485 ;
     RECT  26.748 122.405 26.838 122.485 ;
     RECT  0.216 122.485 26.838 122.525 ;
     RECT  147.384 121.019 147.438 122.539 ;
     RECT  148.215 121.973 149.886 122.539 ;
     RECT  66.852 114.989 67.497 122.675 ;
     RECT  26.748 122.525 26.838 122.819 ;
     RECT  78.015 99.437 78.297 122.872 ;
     RECT  26.748 122.819 26.802 122.945 ;
     RECT  147.384 122.539 149.886 122.945 ;
     RECT  77.832 122.872 78.297 122.953 ;
     RECT  74.664 122.875 74.682 123.005 ;
     RECT  77.508 122.953 78.297 123.005 ;
     RECT  152.568 122.369 153.018 123.061 ;
     RECT  154.44 122.237 154.458 123.067 ;
     RECT  152.424 123.061 153.018 123.215 ;
     RECT  47.628 119.579 47.646 123.251 ;
     RECT  0.216 122.525 25.974 123.331 ;
     RECT  26.748 122.945 26.766 123.331 ;
     RECT  150.804 123.295 150.822 123.331 ;
     RECT  149.724 122.945 149.886 123.421 ;
     RECT  150.66 123.331 150.966 123.421 ;
     RECT  149.724 123.421 150.966 123.449 ;
     RECT  154.404 123.067 154.458 123.449 ;
     RECT  149.76 123.449 150.966 123.485 ;
     RECT  146.484 123.223 146.502 123.557 ;
     RECT  150.948 123.485 150.966 123.557 ;
     RECT  152.424 123.215 152.586 123.601 ;
     RECT  0.216 123.331 26.766 123.677 ;
     RECT  38.952 115.115 38.97 123.755 ;
     RECT  147.384 122.945 148.806 123.869 ;
     RECT  152.244 123.601 152.586 123.899 ;
     RECT  27.612 122.449 30.87 123.989 ;
     RECT  151.236 123.871 151.326 123.989 ;
     RECT  26.748 123.677 26.766 123.997 ;
     RECT  0.216 123.677 25.974 124.025 ;
     RECT  149.76 123.485 149.778 124.025 ;
     RECT  30.78 123.989 30.87 124.069 ;
     RECT  26.748 123.997 26.802 124.097 ;
     RECT  154.44 123.449 154.458 124.141 ;
     RECT  30.78 124.069 31.086 124.295 ;
     RECT  152.244 123.899 152.262 124.295 ;
     RECT  153 124.105 153.054 124.331 ;
     RECT  32.76 122.647 32.778 124.375 ;
     RECT  154.44 124.141 154.494 124.397 ;
     RECT  147.384 123.869 148.497 124.411 ;
     RECT  153.036 124.331 153.054 124.529 ;
     RECT  146.952 124.411 148.497 124.645 ;
     RECT  146.808 124.645 148.497 124.681 ;
     RECT  30.852 124.295 31.086 124.709 ;
     RECT  0.216 124.025 25.938 124.771 ;
     RECT  150.84 124.609 150.858 124.795 ;
     RECT  146.808 124.681 148.77 124.799 ;
     RECT  150.696 124.795 150.858 124.807 ;
     RECT  150.336 124.807 150.858 124.835 ;
     RECT  151.632 124.951 152.01 125.105 ;
     RECT  0.216 124.771 25.974 125.185 ;
     RECT  0.108 125.185 25.974 125.261 ;
     RECT  150.336 124.835 150.354 125.375 ;
     RECT  151.632 125.105 151.866 125.411 ;
     RECT  31.068 124.709 31.086 125.609 ;
     RECT  151.236 125.419 151.362 125.609 ;
     RECT  151.236 125.609 151.254 125.645 ;
     RECT  149.364 125.761 149.382 125.915 ;
     RECT  27.612 123.989 30.042 126.031 ;
     RECT  146.808 124.799 148.59 126.031 ;
     RECT  146.484 126.031 148.59 126.121 ;
     RECT  146.34 126.121 148.59 126.173 ;
     RECT  153 125.725 153.018 126.265 ;
     RECT  34.815 120.929 35.097 126.283 ;
     RECT  45.615 114.557 45.897 126.283 ;
     RECT  56.415 99.437 56.697 126.283 ;
     RECT  67.215 122.675 67.497 126.283 ;
     RECT  78.015 123.005 78.297 126.283 ;
     RECT  88.815 99.437 89.097 126.283 ;
     RECT  99.615 99.437 99.897 126.283 ;
     RECT  110.415 99.437 110.697 126.283 ;
     RECT  121.215 99.437 121.497 126.283 ;
     RECT  132.015 99.437 132.297 126.283 ;
     RECT  142.815 99.437 143.097 126.283 ;
     RECT  147.276 126.173 148.59 126.301 ;
     RECT  154.44 124.397 154.458 126.301 ;
     RECT  34.704 126.283 35.097 126.329 ;
     RECT  45.504 126.283 45.897 126.329 ;
     RECT  56.304 126.283 56.697 126.329 ;
     RECT  67.104 126.283 67.497 126.329 ;
     RECT  77.904 126.283 78.297 126.329 ;
     RECT  88.704 126.283 89.097 126.329 ;
     RECT  99.504 126.283 99.897 126.329 ;
     RECT  110.304 126.283 110.697 126.329 ;
     RECT  121.104 126.283 121.497 126.329 ;
     RECT  131.904 126.283 132.297 126.329 ;
     RECT  142.704 126.283 143.097 126.329 ;
     RECT  26.748 124.097 26.766 126.391 ;
     RECT  27.612 126.031 30.258 126.391 ;
     RECT  147.276 126.301 148.662 126.419 ;
     RECT  0.216 125.261 25.974 126.427 ;
     RECT  26.748 126.391 30.258 126.427 ;
     RECT  150.48 126.121 150.498 126.427 ;
     RECT  31.248 125.761 31.266 126.455 ;
     RECT  147.276 126.419 148.497 126.455 ;
     RECT  150.48 126.427 151.002 126.455 ;
     RECT  146.484 126.173 146.502 126.461 ;
     RECT  150.624 126.455 151.002 126.535 ;
     RECT  0.108 126.427 25.974 126.557 ;
     RECT  32.148 124.375 32.778 126.563 ;
     RECT  152.928 126.265 153.018 126.571 ;
     RECT  154.44 126.301 154.494 126.653 ;
     RECT  155.412 126.523 155.43 126.653 ;
     RECT  149.832 126.571 149.85 126.661 ;
     RECT  149.688 126.661 149.85 126.689 ;
     RECT  150.624 126.535 151.038 126.689 ;
     RECT  149.688 126.689 149.706 126.701 ;
     RECT  152.928 126.571 153.054 126.725 ;
     RECT  152.172 126.391 152.19 126.841 ;
     RECT  152.928 126.725 153.018 126.841 ;
     RECT  150.624 126.689 151.002 126.995 ;
     RECT  0.216 126.557 25.974 127.265 ;
     RECT  151.992 126.841 153.018 127.301 ;
     RECT  150.984 126.995 151.002 127.741 ;
     RECT  151.992 127.301 152.802 127.741 ;
     RECT  150.984 127.741 152.802 127.805 ;
     RECT  0.216 127.265 23.094 127.819 ;
     RECT  154.44 126.653 154.458 127.819 ;
     RECT  26.748 126.427 30.474 127.877 ;
     RECT  147.384 126.455 148.497 127.921 ;
     RECT  0.108 127.819 23.094 127.949 ;
     RECT  146.484 127.849 146.502 127.949 ;
     RECT  153.9 127.819 154.458 127.949 ;
     RECT  147.384 127.921 148.806 128.039 ;
     RECT  150.984 127.805 151.686 128.039 ;
     RECT  147.384 128.039 148.59 128.075 ;
     RECT  152.424 127.805 152.802 128.155 ;
     RECT  154.44 127.949 154.458 128.191 ;
     RECT  152.424 128.155 153.018 128.461 ;
     RECT  0.216 127.949 23.094 128.551 ;
     RECT  24.015 127.265 25.974 128.551 ;
     RECT  32.76 126.563 32.778 128.579 ;
     RECT  152.424 128.461 153.054 128.615 ;
     RECT  150.984 128.039 151.002 128.965 ;
     RECT  150.84 128.965 151.002 129.001 ;
     RECT  152.424 128.615 153.018 129.001 ;
     RECT  150.84 129.001 153.018 129.119 ;
     RECT  147.384 128.075 148.497 129.127 ;
     RECT  154.44 128.191 154.494 129.149 ;
     RECT  147.384 129.127 148.806 129.271 ;
     RECT  150.84 129.119 151.722 129.271 ;
     RECT  147.384 129.271 149.13 129.355 ;
     RECT  150.48 129.271 151.722 129.425 ;
     RECT  0.216 128.551 25.974 129.541 ;
     RECT  26.748 127.877 29.697 129.541 ;
     RECT  147.384 129.355 149.382 129.541 ;
     RECT  154.476 129.149 154.494 129.581 ;
     RECT  147.384 129.541 149.526 129.659 ;
     RECT  147.384 129.659 148.95 129.731 ;
     RECT  41.292 124.807 41.31 129.839 ;
     RECT  150.66 129.425 151.722 129.839 ;
     RECT  150.66 129.839 151.038 129.929 ;
     RECT  0.216 129.541 29.697 129.937 ;
     RECT  152.568 129.119 153.018 129.937 ;
     RECT  151.776 129.937 153.018 129.979 ;
     RECT  0.108 129.937 29.697 130.013 ;
     RECT  151.776 129.979 153.594 130.307 ;
     RECT  153.9 130.351 153.918 130.445 ;
     RECT  147.384 129.731 148.878 130.507 ;
     RECT  147.384 130.507 149.382 130.621 ;
     RECT  150.696 129.929 151.038 130.621 ;
     RECT  151.776 130.307 152.874 130.621 ;
     RECT  0.216 130.013 29.697 130.649 ;
     RECT  147.384 130.621 149.526 130.739 ;
     RECT  147.384 130.739 149.382 130.781 ;
     RECT  150.696 130.621 152.874 130.819 ;
     RECT  150.48 130.819 152.874 130.891 ;
     RECT  150.3 130.891 152.874 131.045 ;
     RECT  146.376 131.017 146.394 131.069 ;
     RECT  151.884 131.045 152.874 131.315 ;
     RECT  154.44 130.843 154.458 131.315 ;
     RECT  151.92 131.315 152.874 131.395 ;
     RECT  150.696 131.045 151.002 131.645 ;
     RECT  146.484 131.521 146.502 131.657 ;
     RECT  153.9 131.593 153.918 131.741 ;
     RECT  151.92 131.395 153.018 131.855 ;
     RECT  30.456 127.877 30.474 131.963 ;
     RECT  152.1 131.855 153.018 132.089 ;
     RECT  31.5 132.205 31.518 132.331 ;
     RECT  31.5 132.331 31.662 132.395 ;
     RECT  147.384 130.781 148.878 132.475 ;
     RECT  147.384 132.475 149.562 132.511 ;
     RECT  150.984 131.645 151.002 132.511 ;
     RECT  63.288 131.935 63.306 132.637 ;
     RECT  150.516 132.511 151.038 132.665 ;
     RECT  152.208 132.089 153.018 132.665 ;
     RECT  0.216 130.649 28.494 132.899 ;
     RECT  146.736 132.511 149.562 133.015 ;
     RECT  150.732 132.665 151.038 133.051 ;
     RECT  152.208 132.665 152.226 133.051 ;
     RECT  0.216 132.899 22.41 133.169 ;
     RECT  146.736 133.015 149.742 133.169 ;
     RECT  150.732 133.051 152.226 133.313 ;
     RECT  146.736 133.169 149.562 133.325 ;
     RECT  86.688 114.277 86.706 133.951 ;
     RECT  146.736 133.325 148.878 133.951 ;
     RECT  154.44 132.133 154.458 133.979 ;
     RECT  53.604 133.951 53.622 133.997 ;
     RECT  86.688 133.951 86.958 134.015 ;
     RECT  150.156 133.963 150.174 134.015 ;
     RECT  86.94 134.015 86.958 134.051 ;
     RECT  153 132.665 153.018 134.095 ;
     RECT  23.616 132.899 28.494 134.123 ;
     RECT  146.484 133.951 148.878 134.123 ;
     RECT  0.216 133.169 22.194 134.131 ;
     RECT  146.556 134.123 148.878 134.131 ;
     RECT  150.984 133.313 152.226 134.131 ;
     RECT  152.964 134.095 153.018 134.131 ;
     RECT  146.556 134.131 149.094 134.249 ;
     RECT  150.3 134.131 153.018 134.249 ;
     RECT  150.912 134.249 153.018 134.285 ;
     RECT  151.812 134.285 153.018 134.299 ;
     RECT  146.592 134.249 149.094 134.401 ;
     RECT  151.812 134.299 153.45 134.429 ;
     RECT  63.288 132.637 63.594 134.519 ;
     RECT  146.592 134.401 149.454 134.519 ;
     RECT  151.812 134.429 153.234 134.519 ;
     RECT  55.152 134.059 55.17 134.525 ;
     RECT  146.592 134.519 149.094 134.555 ;
     RECT  146.592 134.555 148.878 134.573 ;
     RECT  63.576 134.519 63.594 134.671 ;
     RECT  36.504 129.271 36.522 134.969 ;
     RECT  150.912 134.285 151.002 135.019 ;
     RECT  150.732 135.019 151.002 135.095 ;
     RECT  151.992 134.519 153.234 135.197 ;
     RECT  0.216 134.131 22.554 135.239 ;
     RECT  23.616 134.123 27.954 135.301 ;
     RECT  151.992 135.197 153.054 135.329 ;
     RECT  23.616 135.301 28.53 135.341 ;
     RECT  151.992 135.329 153.018 135.365 ;
     RECT  29.415 130.649 29.697 135.481 ;
     RECT  149.904 135.547 149.922 135.571 ;
     RECT  23.616 135.341 27.954 135.635 ;
     RECT  147.204 134.573 148.878 135.643 ;
     RECT  150.984 135.095 151.002 135.643 ;
     RECT  149.832 135.571 149.922 135.671 ;
     RECT  152.244 135.365 153.018 135.671 ;
     RECT  29.232 135.481 29.697 135.677 ;
     RECT  150.984 135.643 151.254 135.751 ;
     RECT  150.984 135.751 151.434 135.869 ;
     RECT  152.784 135.671 153.018 135.869 ;
     RECT  150.984 135.869 151.254 135.905 ;
     RECT  147.204 135.643 148.914 135.977 ;
     RECT  67.215 126.329 67.497 136.111 ;
     RECT  150.984 135.905 151.182 136.183 ;
     RECT  152.82 135.869 153.018 136.255 ;
     RECT  150.372 136.183 151.182 136.409 ;
     RECT  150.372 136.409 151.146 136.445 ;
     RECT  154.44 134.731 154.458 136.459 ;
     RECT  153.864 136.459 154.458 136.589 ;
     RECT  152.82 136.255 153.054 136.651 ;
     RECT  65.052 128.587 65.07 136.679 ;
     RECT  149.724 136.759 150.066 136.831 ;
     RECT  154.476 136.759 154.494 136.925 ;
     RECT  63.576 134.671 64.242 136.949 ;
     RECT  149.616 136.831 150.066 136.985 ;
     RECT  152.352 136.651 153.054 137.065 ;
     RECT  31.644 132.395 31.662 137.129 ;
     RECT  149.904 136.985 150.066 137.179 ;
     RECT  150.984 136.445 151.146 137.179 ;
     RECT  149.904 137.179 151.146 137.219 ;
     RECT  152.028 137.065 153.054 137.219 ;
     RECT  150.444 137.219 151.146 137.255 ;
     RECT  150.48 137.255 151.146 137.641 ;
     RECT  150.48 137.641 151.362 137.759 ;
     RECT  147.204 135.977 148.806 137.911 ;
     RECT  147.204 137.911 149.094 138.001 ;
     RECT  150.48 137.759 151.002 138.029 ;
     RECT  146.484 138.001 149.094 138.065 ;
     RECT  23.796 135.635 27.954 138.137 ;
     RECT  146.484 138.065 148.914 138.137 ;
     RECT  152.568 137.219 153.018 138.145 ;
     RECT  147.204 138.137 148.914 138.299 ;
     RECT  151.776 138.145 153.018 138.721 ;
     RECT  151.74 138.721 153.018 138.955 ;
     RECT  154.44 137.323 154.458 138.991 ;
     RECT  154.44 138.991 154.494 139.051 ;
     RECT  147.204 138.299 148.806 139.109 ;
     RECT  154.404 139.051 154.494 139.109 ;
     RECT  150.876 138.029 151.002 139.261 ;
     RECT  150.84 139.261 151.002 139.415 ;
     RECT  151.74 138.955 153.054 139.451 ;
     RECT  154.44 139.109 154.494 139.517 ;
     RECT  0.216 135.239 21.474 139.531 ;
     RECT  150.984 139.415 151.002 139.621 ;
     RECT  0.216 139.531 21.654 139.685 ;
     RECT  0.216 139.685 20.358 139.721 ;
     RECT  150.984 139.621 151.722 139.919 ;
     RECT  0.216 139.721 20.286 139.955 ;
     RECT  149.904 139.081 149.922 139.955 ;
     RECT  0.216 139.955 19.53 140.189 ;
     RECT  23.796 138.137 25.542 140.189 ;
     RECT  149.616 140.071 149.634 140.189 ;
     RECT  154.44 139.517 154.458 140.189 ;
     RECT  21.456 139.685 21.654 140.225 ;
     RECT  150.984 139.919 151.362 140.459 ;
     RECT  152.496 139.451 153.054 140.611 ;
     RECT  152.136 140.611 153.054 140.701 ;
     RECT  152.064 140.701 153.054 140.729 ;
     RECT  149.58 140.611 149.598 140.765 ;
     RECT  24.015 140.189 25.542 140.999 ;
     RECT  25.524 140.999 25.542 141.151 ;
     RECT  147.204 139.109 148.626 141.151 ;
     RECT  153.864 140.347 153.882 141.179 ;
     RECT  26.748 138.137 27.954 141.269 ;
     RECT  146.484 141.151 148.77 141.269 ;
     RECT  150.984 140.459 151.218 141.313 ;
     RECT  152.064 140.729 153.018 141.313 ;
     RECT  147.204 141.269 148.77 141.355 ;
     RECT  147.204 141.355 149.166 141.499 ;
     RECT  149.904 141.277 149.922 141.499 ;
     RECT  150.984 141.313 153.018 141.539 ;
     RECT  22.536 135.239 22.554 141.809 ;
     RECT  147.204 141.499 149.922 141.809 ;
     RECT  150.984 141.539 151.398 141.809 ;
     RECT  149.832 141.809 149.922 141.881 ;
     RECT  0.216 140.189 19.35 141.925 ;
     RECT  0.216 141.925 19.422 142.075 ;
     RECT  0.108 142.075 19.422 142.079 ;
     RECT  147.204 141.809 148.986 142.079 ;
     RECT  21.456 140.225 21.474 142.151 ;
     RECT  40.215 101.039 40.497 142.357 ;
     RECT  41.58 142.321 41.598 142.357 ;
     RECT  40.215 142.357 41.598 142.397 ;
     RECT  150.984 141.809 151.362 142.771 ;
     RECT  152.136 141.539 153.018 142.771 ;
     RECT  34.815 126.329 35.097 142.888 ;
     RECT  150.84 142.771 153.054 142.889 ;
     RECT  33.408 142.861 33.426 142.925 ;
     RECT  34.524 142.888 35.097 142.925 ;
     RECT  147.204 142.079 148.842 142.925 ;
     RECT  149.904 141.881 149.922 143.083 ;
     RECT  149.652 143.083 149.922 143.117 ;
     RECT  154.44 141.211 154.458 143.159 ;
     RECT  150.84 142.889 151.002 143.311 ;
     RECT  151.776 142.889 153.054 143.371 ;
     RECT  151.776 143.371 153.522 143.429 ;
     RECT  0.108 142.079 19.35 143.465 ;
     RECT  151.884 143.429 153.522 143.609 ;
     RECT  147.204 142.925 148.806 143.699 ;
     RECT  154.476 143.509 154.494 143.837 ;
     RECT  149.652 143.117 149.67 143.851 ;
     RECT  150.624 143.311 151.002 143.851 ;
     RECT  147.204 143.699 148.662 143.885 ;
     RECT  147.204 143.885 148.59 143.941 ;
     RECT  26.748 141.269 27.054 143.969 ;
     RECT  149.58 143.851 149.742 143.969 ;
     RECT  151.884 143.609 153.018 143.969 ;
     RECT  149.58 143.969 149.598 144.005 ;
     RECT  151.884 143.969 152.874 144.275 ;
     RECT  152.568 144.275 152.874 144.311 ;
     RECT  24.015 140.999 24.786 144.509 ;
     RECT  150.588 143.851 151.002 144.545 ;
     RECT  150.804 144.545 151.002 144.589 ;
     RECT  146.484 143.941 148.59 144.653 ;
     RECT  154.44 144.235 154.458 144.661 ;
     RECT  153.864 144.661 154.458 144.701 ;
     RECT  152.604 144.311 152.874 144.779 ;
     RECT  150.804 144.589 151.83 144.815 ;
     RECT  147.024 144.653 148.59 144.895 ;
     RECT  147.024 144.895 149.202 144.941 ;
     RECT  142.815 126.329 143.097 145.021 ;
     RECT  27.036 143.969 27.054 145.049 ;
     RECT  147.024 144.941 148.59 145.085 ;
     RECT  150.804 144.815 151.002 145.085 ;
     RECT  142.524 145.021 143.097 145.193 ;
     RECT  147.204 145.085 148.59 145.355 ;
     RECT  20.268 139.955 20.286 145.625 ;
     RECT  152.676 144.779 152.694 145.669 ;
     RECT  25.524 141.151 25.938 145.697 ;
     RECT  151.812 144.815 151.83 145.741 ;
     RECT  152.676 145.669 153.054 145.741 ;
     RECT  154.44 144.701 154.458 145.741 ;
     RECT  0.216 143.465 19.35 145.867 ;
     RECT  150.84 145.085 151.002 145.901 ;
     RECT  0.108 145.867 19.35 145.997 ;
     RECT  154.44 145.741 154.494 145.997 ;
     RECT  151.812 145.741 153.054 146.129 ;
     RECT  0.216 145.997 19.35 146.399 ;
     RECT  153.9 146.371 153.918 146.429 ;
     RECT  150.984 145.901 151.002 146.443 ;
     RECT  151.812 146.129 152.982 146.443 ;
     RECT  150.984 146.443 152.982 146.669 ;
     RECT  147.204 145.355 147.294 146.677 ;
     RECT  149.688 145.867 149.706 146.785 ;
     RECT  147.204 146.677 147.402 146.821 ;
     RECT  148.215 145.355 148.59 146.821 ;
     RECT  150.984 146.669 152.802 146.821 ;
     RECT  147.204 146.821 148.59 146.911 ;
     RECT  149.688 146.785 149.85 146.911 ;
     RECT  147.204 146.911 149.85 146.939 ;
     RECT  150.768 146.821 152.802 146.939 ;
     RECT  153.864 146.827 153.882 146.939 ;
     RECT  150.768 146.939 151.038 146.975 ;
     RECT  147.204 146.939 147.366 147.005 ;
     RECT  148.215 146.939 149.85 147.101 ;
     RECT  25.92 145.697 25.938 147.119 ;
     RECT  148.215 147.101 149.634 147.209 ;
     RECT  150.84 146.975 151.038 147.209 ;
     RECT  148.215 147.209 148.986 147.245 ;
     RECT  150.84 147.209 151.002 147.245 ;
     RECT  0.216 146.399 19.17 147.479 ;
     RECT  151.812 146.939 152.802 147.515 ;
     RECT  152.136 147.515 152.802 147.595 ;
     RECT  154.44 147.259 154.458 147.595 ;
     RECT  154.44 147.595 154.494 147.691 ;
     RECT  152.136 147.595 153.054 147.749 ;
     RECT  154.404 147.691 154.494 147.749 ;
     RECT  0.216 147.479 18.99 147.821 ;
     RECT  63.792 136.949 64.242 148.019 ;
     RECT  150.984 147.245 151.002 148.171 ;
     RECT  63.792 148.019 63.81 148.289 ;
     RECT  150.624 148.171 151.074 148.289 ;
     RECT  148.215 147.245 148.554 148.405 ;
     RECT  149.292 148.135 149.31 148.405 ;
     RECT  147.204 147.005 147.294 148.441 ;
     RECT  148.215 148.405 149.31 148.441 ;
     RECT  27.936 141.269 27.954 148.469 ;
     RECT  154.44 147.749 154.494 148.555 ;
     RECT  146.484 148.441 147.294 148.559 ;
     RECT  148.215 148.441 149.598 148.595 ;
     RECT  148.215 148.595 149.382 148.651 ;
     RECT  152.424 147.749 153.054 148.675 ;
     RECT  148.032 148.651 149.382 148.685 ;
     RECT  148.032 148.685 148.554 148.703 ;
     RECT  150.624 148.289 151.002 148.711 ;
     RECT  153.9 148.555 154.494 148.739 ;
     RECT  150.48 148.711 151.002 148.801 ;
     RECT  152.244 148.675 153.054 148.829 ;
     RECT  149.364 148.685 149.382 148.865 ;
     RECT  65.52 136.759 65.538 148.937 ;
     RECT  150.444 148.801 151.002 148.937 ;
     RECT  152.244 148.829 153.018 148.981 ;
     RECT  150.48 148.937 151.002 149.009 ;
     RECT  154.44 148.739 154.494 149.021 ;
     RECT  151.812 148.981 153.018 149.135 ;
     RECT  152.1 149.135 153.018 149.369 ;
     RECT  148.215 148.703 148.554 149.611 ;
     RECT  148.215 149.611 148.59 149.755 ;
     RECT  148.215 149.755 149.346 149.791 ;
     RECT  150.876 149.009 151.002 149.791 ;
     RECT  154.44 149.021 154.458 149.791 ;
     RECT  150.876 149.791 151.146 149.909 ;
     RECT  152.712 149.369 153.018 149.909 ;
     RECT  153.9 149.791 154.458 149.909 ;
     RECT  148.215 149.791 149.67 150.089 ;
     RECT  152.856 149.909 153.018 150.179 ;
     RECT  147.204 148.559 147.294 150.181 ;
     RECT  147.204 150.181 147.402 150.295 ;
     RECT  148.215 150.089 149.346 150.295 ;
     RECT  153.9 149.909 153.918 150.317 ;
     RECT  147.204 150.295 149.346 150.323 ;
     RECT  150.876 149.909 151.002 150.331 ;
     RECT  147.204 150.323 149.202 150.449 ;
     RECT  150.372 150.331 151.002 150.449 ;
     RECT  151.992 150.223 152.046 150.449 ;
     RECT  147.204 150.449 147.366 150.485 ;
     RECT  152.028 150.449 152.046 150.799 ;
     RECT  152.856 150.179 152.874 150.799 ;
     RECT  67.215 136.111 67.554 150.989 ;
     RECT  152.028 150.799 152.874 150.989 ;
     RECT  0.216 147.821 18.897 150.997 ;
     RECT  152.856 150.989 152.874 151.025 ;
     RECT  148.215 150.449 149.202 151.105 ;
     RECT  150.372 150.449 150.642 151.105 ;
     RECT  148.215 151.105 150.642 151.133 ;
     RECT  0.108 150.997 18.897 151.181 ;
     RECT  149.904 151.133 150.642 151.375 ;
     RECT  149.904 151.375 151.11 151.411 ;
     RECT  149.904 151.411 151.722 151.469 ;
     RECT  27.648 151.501 27.666 151.565 ;
     RECT  150.048 151.469 151.722 151.565 ;
     RECT  151.704 151.565 151.722 151.771 ;
     RECT  151.704 151.771 152.154 151.915 ;
     RECT  154.44 150.715 154.458 151.951 ;
     RECT  154.404 151.951 154.458 152.045 ;
     RECT  147.204 150.485 147.294 152.443 ;
     RECT  150.732 152.443 150.75 152.455 ;
     RECT  146.484 152.443 147.294 152.491 ;
     RECT  148.215 151.133 148.59 152.491 ;
     RECT  149.328 152.221 149.346 152.491 ;
     RECT  151.704 151.915 152.694 152.491 ;
     RECT  150.588 152.455 150.75 152.525 ;
     RECT  26.532 151.051 26.55 152.581 ;
     RECT  151.524 152.491 152.694 152.581 ;
     RECT  25.344 152.203 25.362 152.609 ;
     RECT  26.208 152.581 26.55 152.609 ;
     RECT  146.484 152.491 149.346 152.609 ;
     RECT  154.44 152.045 154.458 152.609 ;
     RECT  26.208 152.609 26.226 152.621 ;
     RECT  146.484 152.609 148.95 152.621 ;
     RECT  146.736 152.621 148.95 152.645 ;
     RECT  27.324 152.581 27.342 152.669 ;
     RECT  151.524 152.581 152.874 152.725 ;
     RECT  151.524 152.725 153.054 152.879 ;
     RECT  151.524 152.879 153.018 153.031 ;
     RECT  150.84 153.031 153.018 153.149 ;
     RECT  150.84 153.149 150.858 153.185 ;
     RECT  79.128 153.157 79.146 153.197 ;
     RECT  95.868 153.157 95.886 153.197 ;
     RECT  96.984 153.121 97.002 153.197 ;
     RECT  0.216 151.181 18.897 153.221 ;
     RECT  78.015 126.329 78.297 153.301 ;
     RECT  29.415 135.677 29.697 153.355 ;
     RECT  149.904 153.019 149.922 153.389 ;
     RECT  78.015 153.301 78.39 153.391 ;
     RECT  146.736 152.645 147.294 153.391 ;
     RECT  148.215 152.645 148.95 153.391 ;
     RECT  30.852 137.101 30.87 153.419 ;
     RECT  29.415 153.355 29.754 153.451 ;
     RECT  0.216 153.221 17.442 153.527 ;
     RECT  29.415 153.451 30.762 153.527 ;
     RECT  146.736 153.391 148.95 153.571 ;
     RECT  146.736 153.571 149.742 153.599 ;
     RECT  149.544 153.599 149.742 153.689 ;
     RECT  149.544 153.689 149.562 153.725 ;
     RECT  153.864 152.875 154.422 153.739 ;
     RECT  146.736 153.599 148.806 153.959 ;
     RECT  146.736 153.959 148.662 153.995 ;
     RECT  150.48 153.841 150.498 154.111 ;
     RECT  153.828 153.739 154.422 154.171 ;
     RECT  53.532 154.075 53.55 154.201 ;
     RECT  150.444 154.111 150.498 154.201 ;
     RECT  151.236 154.111 151.254 154.201 ;
     RECT  53.532 154.201 54.018 154.229 ;
     RECT  150.444 154.201 151.254 154.229 ;
     RECT  150.516 154.229 151.254 154.265 ;
     RECT  54 154.229 54.018 154.301 ;
     RECT  150.696 154.265 151.11 154.301 ;
     RECT  151.092 154.301 151.11 154.349 ;
     RECT  0.216 153.527 17.226 154.381 ;
     RECT  152.1 153.149 153.018 154.381 ;
     RECT  105.015 2.413 105.297 154.507 ;
     RECT  151.92 154.381 153.018 154.535 ;
     RECT  105.015 154.507 105.39 154.544 ;
     RECT  0.216 154.381 17.442 154.615 ;
     RECT  0.216 154.615 17.514 154.769 ;
     RECT  152.1 154.535 153.018 154.769 ;
     RECT  103.824 154.651 103.842 154.781 ;
     RECT  152.532 154.769 153.018 154.805 ;
     RECT  76.824 154.201 76.95 154.877 ;
     RECT  153.828 154.171 154.458 154.949 ;
     RECT  77.184 154.921 77.202 154.973 ;
     RECT  0.216 154.769 17.406 155.039 ;
     RECT  154.44 154.949 154.458 155.039 ;
     RECT  153 154.805 153.018 155.075 ;
     RECT  40.215 142.397 40.497 155.371 ;
     RECT  67.215 150.989 67.497 155.371 ;
     RECT  24.015 144.509 24.297 155.551 ;
     RECT  34.815 142.925 35.097 155.551 ;
     RECT  40.104 155.371 40.497 155.563 ;
     RECT  67.104 155.371 67.497 155.579 ;
     RECT  68.652 154.747 68.67 155.579 ;
     RECT  23.904 155.551 24.297 155.597 ;
     RECT  34.704 155.551 35.097 155.597 ;
     RECT  40.032 155.563 40.497 155.759 ;
     RECT  146.736 153.995 148.497 155.921 ;
     RECT  0.216 155.039 17.262 155.957 ;
     RECT  0.216 155.957 17.226 156.191 ;
     RECT  0.216 156.191 17.154 156.461 ;
     RECT  0.216 156.461 17.118 156.703 ;
     RECT  0.108 156.703 17.118 156.797 ;
     RECT  0.216 156.797 17.118 157.621 ;
     RECT  0.216 157.621 17.226 157.891 ;
     RECT  0.216 157.891 17.334 157.919 ;
     RECT  0.396 157.919 17.334 158.009 ;
     RECT  0.396 158.009 17.298 158.279 ;
     RECT  0.396 158.279 17.118 158.315 ;
     RECT  146.736 155.921 147.258 159.359 ;
     RECT  64.908 155.893 64.926 159.629 ;
     RECT  146.736 159.359 146.754 159.899 ;
     RECT  0.396 158.315 17.082 159.943 ;
     RECT  0.396 159.943 17.19 160.043 ;
     RECT  0.396 160.043 13.842 160.169 ;
     RECT  14.76 160.043 17.19 160.169 ;
     RECT  14.76 160.169 17.01 160.277 ;
     RECT  16.524 160.277 17.01 160.313 ;
     RECT  14.76 160.277 15.714 160.439 ;
     RECT  18.615 153.221 18.897 160.447 ;
     RECT  15.408 160.439 15.714 160.475 ;
     RECT  16.992 160.313 17.01 160.475 ;
     RECT  65.592 160.015 65.61 160.475 ;
     RECT  64.764 159.745 64.782 161.051 ;
     RECT  0.396 160.169 13.554 161.401 ;
     RECT  0.396 161.401 13.842 161.555 ;
     RECT  18.615 160.447 19.422 161.663 ;
     RECT  0.396 161.555 13.698 161.789 ;
     RECT  15.408 160.475 15.426 161.969 ;
     RECT  0.396 161.789 13.662 162.059 ;
     RECT  0.396 162.059 13.497 162.473 ;
     RECT  0.396 162.473 12.474 162.599 ;
     RECT  0.396 162.599 12.402 166.181 ;
     RECT  0.432 166.181 12.402 167.539 ;
     RECT  0.108 167.539 12.402 167.597 ;
     RECT  0.432 167.597 12.402 167.999 ;
     RECT  0.432 167.999 11.574 170.069 ;
     RECT  17.352 170.779 17.37 171.005 ;
     RECT  0.468 170.069 11.574 171.113 ;
     RECT  0.504 171.113 11.574 174.043 ;
     RECT  0.108 174.043 11.574 174.173 ;
     RECT  20.808 173.851 20.826 174.181 ;
     RECT  20.808 174.181 21.15 174.209 ;
     RECT  21.132 174.209 21.15 174.221 ;
     RECT  0.504 174.173 11.574 176.107 ;
     RECT  0.108 176.107 11.574 176.237 ;
     RECT  0.504 176.237 11.574 178.411 ;
     RECT  0.468 178.411 11.574 183.659 ;
     RECT  0.54 183.659 11.574 186.403 ;
     RECT  0.468 186.403 11.574 187.124 ;
     RECT  0.54 187.124 11.574 192.479 ;
     RECT  78.015 153.391 78.822 196.619 ;
     RECT  0.54 192.479 0.558 197.707 ;
     RECT  0.108 197.707 0.558 197.837 ;
     RECT  1.44 192.479 11.574 198.419 ;
     RECT  2.088 198.419 11.574 198.779 ;
     RECT  2.088 198.779 10.962 200.309 ;
     RECT  0.54 197.837 0.558 200.777 ;
     RECT  2.124 200.309 10.962 204.827 ;
     RECT  2.16 204.827 10.962 204.899 ;
     RECT  12.384 167.999 12.402 205.799 ;
     RECT  2.304 204.899 10.962 206.483 ;
     RECT  2.376 206.483 10.962 207.307 ;
     RECT  2.304 207.307 10.962 207.455 ;
     RECT  0.108 208.507 0.126 208.637 ;
     RECT  2.376 207.455 10.962 208.637 ;
     RECT  2.412 208.637 10.962 209.425 ;
     RECT  2.304 209.425 10.962 210.803 ;
     RECT  2.415 210.803 10.962 211.627 ;
     RECT  0.54 212.017 0.558 212.093 ;
     RECT  2.304 211.627 10.962 212.585 ;
     RECT  2.415 212.585 10.962 213.355 ;
     RECT  2.304 213.355 10.962 213.395 ;
     RECT  0.108 213.637 0.126 213.821 ;
     RECT  2.415 213.395 10.962 214.177 ;
     RECT  2.412 214.177 10.962 214.651 ;
     RECT  2.304 214.651 10.962 214.745 ;
     RECT  2.415 214.745 10.962 215.905 ;
     RECT  2.304 215.905 10.962 215.981 ;
     RECT  2.412 215.981 10.962 216.239 ;
     RECT  2.412 216.239 10.53 216.811 ;
     RECT  2.304 216.811 10.53 216.905 ;
     RECT  2.415 216.905 10.53 217.049 ;
     RECT  0.108 217.147 0.126 217.277 ;
     RECT  78.015 196.619 78.714 217.381 ;
     RECT  2.415 217.049 10.278 217.409 ;
     RECT  77.904 217.381 78.714 217.489 ;
     RECT  77.832 217.489 78.714 217.561 ;
     RECT  2.415 217.409 9.45 217.675 ;
     RECT  77.796 217.561 78.714 217.679 ;
     RECT  77.796 217.679 78.354 217.795 ;
     RECT  77.508 217.795 78.354 217.949 ;
     RECT  77.508 217.949 78.297 218.299 ;
     RECT  2.304 217.675 9.45 218.489 ;
     RECT  77.184 218.299 78.297 218.605 ;
     RECT  77.04 218.605 78.297 218.875 ;
     RECT  77.04 218.875 78.354 218.911 ;
     RECT  76.968 218.911 78.354 219.029 ;
     RECT  77.652 219.029 78.354 219.065 ;
     RECT  77.724 219.065 78.354 219.299 ;
     RECT  2.304 218.489 9.414 219.443 ;
     RECT  2.415 219.443 9.414 220.267 ;
     RECT  2.304 220.267 9.414 220.415 ;
     RECT  2.415 220.415 9.414 221.563 ;
     RECT  2.304 221.563 9.414 222.035 ;
     RECT  0.108 222.277 0.126 222.461 ;
     RECT  2.415 222.035 9.414 222.809 ;
     RECT  0.54 222.853 0.558 222.893 ;
     RECT  2.415 222.809 8.658 223.291 ;
     RECT  2.412 223.291 8.658 223.723 ;
     RECT  2.304 223.723 8.658 223.763 ;
     RECT  2.412 223.763 8.658 224.587 ;
     RECT  2.304 224.587 8.658 225.923 ;
     RECT  2.415 225.923 8.658 226.705 ;
     RECT  2.304 226.705 8.658 226.781 ;
     RECT  2.415 226.781 8.658 227.611 ;
     RECT  2.304 227.611 8.658 227.705 ;
     RECT  0.108 227.947 0.126 228.077 ;
     RECT  2.415 227.705 8.658 228.475 ;
     RECT  2.412 228.475 8.658 228.865 ;
     RECT  2.304 228.865 8.658 228.941 ;
     RECT  2.34 228.941 8.658 229.433 ;
     RECT  3.528 229.433 8.658 229.595 ;
     RECT  2.34 229.433 2.697 229.771 ;
     RECT  2.304 229.771 2.697 229.865 ;
     RECT  2.412 229.865 2.697 230.243 ;
     RECT  2.415 230.243 2.697 231.067 ;
     RECT  2.304 231.067 2.697 231.215 ;
     RECT  2.412 231.215 2.697 231.533 ;
     RECT  77.724 219.299 78.297 232.025 ;
     RECT  3.564 229.595 8.658 232.141 ;
     RECT  2.415 231.533 2.697 232.363 ;
     RECT  2.304 232.363 2.697 232.375 ;
     RECT  3.456 232.141 8.658 232.375 ;
     RECT  2.304 232.375 8.658 233.609 ;
     RECT  6.768 233.609 8.658 233.879 ;
     RECT  10.26 217.409 10.278 234.149 ;
     RECT  2.304 233.609 5.814 234.185 ;
     RECT  2.415 234.185 5.814 234.805 ;
     RECT  9.396 222.809 9.414 234.859 ;
     RECT  2.415 234.805 6.21 234.995 ;
     RECT  3.996 234.995 6.21 235.003 ;
     RECT  7.128 233.879 8.658 235.003 ;
     RECT  9.396 234.859 10.026 235.229 ;
     RECT  0.108 235.291 0.126 235.421 ;
     RECT  3.996 235.003 8.658 235.499 ;
     RECT  2.415 234.995 3.114 235.535 ;
     RECT  9.396 235.229 9.414 235.571 ;
     RECT  2.415 235.535 2.826 235.853 ;
     RECT  3.996 235.499 8.097 235.885 ;
     RECT  2.415 235.853 2.697 236.251 ;
     RECT  2.304 236.251 2.697 236.345 ;
     RECT  3.708 235.885 8.097 236.461 ;
     RECT  3.528 236.461 8.097 236.573 ;
     RECT  6.768 236.573 8.097 236.579 ;
     RECT  6.948 236.579 8.097 236.885 ;
     RECT  2.415 236.345 2.697 237.115 ;
     RECT  7.092 236.885 8.097 237.119 ;
     RECT  3.528 236.573 5.814 237.155 ;
     RECT  2.412 237.115 2.697 237.505 ;
     RECT  2.304 237.505 2.697 237.581 ;
     RECT  4.932 237.155 5.814 237.929 ;
     RECT  2.415 237.581 2.697 237.973 ;
     RECT  3.852 237.155 4.158 238.045 ;
     RECT  4.932 237.929 5.058 238.045 ;
     RECT  5.796 237.929 5.814 238.199 ;
     RECT  2.415 237.973 2.826 238.351 ;
     RECT  2.415 238.351 3.042 238.411 ;
     RECT  2.34 238.411 3.042 238.441 ;
     RECT  3.852 238.045 5.058 238.441 ;
     RECT  2.34 238.441 5.058 238.505 ;
     RECT  3.528 238.505 5.058 238.541 ;
     RECT  7.128 237.119 8.097 238.739 ;
     RECT  6.12 238.711 6.246 238.829 ;
     RECT  0.108 238.783 0.126 238.877 ;
     RECT  6.228 238.829 6.246 239.009 ;
     RECT  3.636 238.541 5.058 239.125 ;
     RECT  2.415 238.505 2.697 239.275 ;
     RECT  3.636 239.125 5.13 239.279 ;
     RECT  2.304 239.275 2.697 239.395 ;
     RECT  3.636 239.279 4.626 239.395 ;
     RECT  2.304 239.395 4.626 239.549 ;
     RECT  2.304 239.549 3.15 239.585 ;
     RECT  6.84 239.521 6.858 239.597 ;
     RECT  77.832 232.025 78.297 239.657 ;
     RECT  7.815 238.739 8.097 239.755 ;
     RECT  5.472 239.701 5.49 239.803 ;
     RECT  5.472 239.803 5.778 239.819 ;
     RECT  7.524 239.755 8.097 239.819 ;
     RECT  2.304 239.585 2.826 239.855 ;
     RECT  5.76 239.819 5.778 239.855 ;
     RECT  77.94 239.657 78.297 239.885 ;
     RECT  5.904 239.863 5.922 240.089 ;
     RECT  2.415 239.855 2.826 240.173 ;
     RECT  3.996 239.549 4.626 240.205 ;
     RECT  3.996 240.205 4.95 240.359 ;
     RECT  3.996 240.359 4.518 240.395 ;
     RECT  4.5 240.395 4.518 240.431 ;
     RECT  78.015 239.885 78.297 243.175 ;
     RECT  78.012 243.175 78.297 243.389 ;
     RECT  2.415 240.173 2.697 243.827 ;
     RECT  7.815 239.819 8.097 243.827 ;
     RECT  13.215 162.473 13.497 243.827 ;
     RECT  18.615 161.663 18.897 243.827 ;
     RECT  24.015 155.597 24.297 243.827 ;
     RECT  29.415 153.527 29.697 243.827 ;
     RECT  34.815 155.597 35.097 243.827 ;
     RECT  40.215 155.759 40.497 243.827 ;
     RECT  45.615 126.329 45.897 243.827 ;
     RECT  51.015 114.557 51.297 243.827 ;
     RECT  56.415 126.329 56.697 243.827 ;
     RECT  61.815 105.089 62.097 243.827 ;
     RECT  67.215 155.579 67.497 243.827 ;
     RECT  72.615 2.413 72.897 243.827 ;
     RECT  78.015 243.389 78.297 243.827 ;
     RECT  83.415 2.413 83.697 243.827 ;
     RECT  88.815 126.329 89.097 243.827 ;
     RECT  94.215 105.197 94.497 243.827 ;
     RECT  99.615 126.329 99.897 243.827 ;
     RECT  105.015 154.544 105.297 243.827 ;
     RECT  110.415 126.329 110.697 243.827 ;
     RECT  115.815 2.413 116.097 243.827 ;
     RECT  121.215 126.329 121.497 243.827 ;
     RECT  126.615 2.413 126.897 243.827 ;
     RECT  132.015 126.329 132.297 243.827 ;
     RECT  137.415 2.413 137.697 243.827 ;
     RECT  142.815 145.193 143.097 243.827 ;
     RECT  148.215 155.921 148.497 243.827 ;
     RECT  2.415 243.827 2.505 244.097 ;
     RECT  7.815 243.827 7.905 244.097 ;
     RECT  13.215 243.827 13.305 244.097 ;
     RECT  18.615 243.827 18.705 244.097 ;
     RECT  24.015 243.827 24.105 244.097 ;
     RECT  29.415 243.827 29.505 244.097 ;
     RECT  34.815 243.827 34.905 244.097 ;
     RECT  40.215 243.827 40.305 244.097 ;
     RECT  45.615 243.827 45.705 244.097 ;
     RECT  51.015 243.827 51.105 244.097 ;
     RECT  56.415 243.827 56.505 244.097 ;
     RECT  61.815 243.827 61.905 244.097 ;
     RECT  67.215 243.827 67.305 244.097 ;
     RECT  72.615 243.827 72.705 244.097 ;
     RECT  78.015 243.827 78.105 244.097 ;
     RECT  83.415 243.827 83.505 244.097 ;
     RECT  88.815 243.827 88.905 244.097 ;
     RECT  94.215 243.827 94.305 244.097 ;
     RECT  99.615 243.827 99.705 244.097 ;
     RECT  105.015 243.827 105.105 244.097 ;
     RECT  110.415 243.827 110.505 244.097 ;
     RECT  115.815 243.827 115.905 244.097 ;
     RECT  121.215 243.827 121.305 244.097 ;
     RECT  126.615 243.827 126.705 244.097 ;
     RECT  132.015 243.827 132.105 244.097 ;
     RECT  137.415 243.827 137.505 244.097 ;
     RECT  142.815 243.827 142.905 244.097 ;
     RECT  148.215 243.827 148.305 244.097 ;
    LAYER M4 ;
     RECT  0.06 6 0.137 240.168 ;
     RECT  0.137 143.808 0.569 240.168 ;
     RECT  0.137 6 2.408 141.672 ;
     RECT  0.569 143.808 2.408 222.024 ;
     RECT  0.569 223.296 2.408 240.168 ;
     RECT  2.408 2.148 2.512 244.092 ;
     RECT  2.512 2.418 2.704 243.822 ;
     RECT  2.704 140.784 2.729 147.288 ;
     RECT  2.704 21.984 2.765 22.008 ;
     RECT  2.704 23.28 2.765 23.304 ;
     RECT  2.704 76.944 2.765 77.304 ;
     RECT  2.704 156.528 2.765 165.432 ;
     RECT  2.704 190.464 2.765 192.648 ;
     RECT  2.704 193.92 2.765 195.528 ;
     RECT  2.704 30.192 2.801 30.648 ;
     RECT  2.704 91.392 2.801 110.04 ;
     RECT  2.704 118.944 2.801 120.84 ;
     RECT  2.704 121.968 2.801 136.056 ;
     RECT  2.704 176.928 2.801 178.632 ;
     RECT  2.704 226.32 2.801 227.544 ;
     RECT  2.704 171.648 2.819 175.416 ;
     RECT  2.704 15.504 2.837 15.528 ;
     RECT  2.704 34.944 2.837 35.88 ;
     RECT  2.704 51.312 2.837 52.248 ;
     RECT  2.704 66.048 2.837 68.952 ;
     RECT  2.704 81.504 2.837 84.12 ;
     RECT  2.704 179.664 2.837 181.272 ;
     RECT  2.765 194.304 2.837 195.528 ;
     RECT  2.704 205.584 2.837 207.48 ;
     RECT  2.704 235.296 2.837 235.848 ;
     RECT  2.704 237.984 2.837 238.008 ;
     RECT  2.704 239.568 2.837 240.168 ;
     RECT  2.837 205.776 2.845 207.48 ;
     RECT  2.837 194.304 2.867 194.52 ;
     RECT  2.704 208.608 2.873 209.784 ;
     RECT  2.704 211.44 2.873 212.088 ;
     RECT  2.704 219.408 2.873 219.432 ;
     RECT  2.704 223.44 2.873 223.464 ;
     RECT  2.765 156.528 2.88 160.2 ;
     RECT  2.704 199.392 2.917 204.072 ;
     RECT  2.729 141.504 3.011 147.096 ;
     RECT  2.765 190.464 3.011 192.072 ;
     RECT  2.704 49.44 3.089 50.328 ;
     RECT  2.837 235.296 3.125 235.32 ;
     RECT  2.845 205.776 3.203 206.952 ;
     RECT  2.704 53.568 3.241 56.232 ;
     RECT  2.704 12.768 3.305 13.128 ;
     RECT  2.837 66.048 3.305 66.696 ;
     RECT  2.704 166.416 3.305 166.488 ;
     RECT  2.704 7.872 3.34 7.896 ;
     RECT  2.704 10.848 3.34 11.208 ;
     RECT  2.704 232.416 3.34 233.784 ;
     RECT  2.704 40.896 3.341 42.168 ;
     RECT  2.704 9.12 3.349 9.624 ;
     RECT  3.34 10.848 3.349 10.872 ;
     RECT  2.704 183.696 3.377 187.704 ;
     RECT  2.88 158.16 3.395 160.2 ;
     RECT  2.765 161.52 3.395 163.992 ;
     RECT  3.377 185.088 3.395 187.704 ;
     RECT  2.704 149.376 3.443 152.664 ;
     RECT  2.704 182.352 3.443 182.472 ;
     RECT  2.801 226.32 3.443 226.392 ;
     RECT  2.917 199.584 3.449 204.072 ;
     RECT  3.443 149.376 3.539 151.656 ;
     RECT  3.203 206.928 3.539 206.952 ;
     RECT  3.241 54.096 3.557 56.232 ;
     RECT  2.819 171.648 3.601 175.032 ;
     RECT  3.443 152.64 3.635 152.664 ;
     RECT  3.395 162.576 3.635 163.992 ;
     RECT  2.704 168.672 3.635 168.696 ;
     RECT  3.557 54.096 3.673 55.08 ;
     RECT  2.704 78.624 3.685 78.648 ;
     RECT  2.704 79.872 3.685 80.328 ;
     RECT  2.704 61.104 3.697 61.992 ;
     RECT  2.704 63.024 3.697 63.192 ;
     RECT  3.635 163.056 3.733 163.992 ;
     RECT  2.765 165.072 3.733 165.432 ;
     RECT  2.704 224.544 3.733 225.192 ;
     RECT  3.685 75.168 3.769 75.192 ;
     RECT  2.765 76.944 3.769 76.968 ;
     RECT  2.88 156.528 3.773 156.792 ;
     RECT  3.733 224.496 3.773 225.192 ;
     RECT  2.704 116.592 3.781 117.864 ;
     RECT  2.801 176.928 3.805 178.536 ;
     RECT  2.704 72.816 3.829 74.088 ;
     RECT  3.769 75.168 3.829 76.968 ;
     RECT  2.704 88.608 3.829 89.976 ;
     RECT  3.011 145.296 3.841 147.096 ;
     RECT  2.873 208.704 3.877 209.784 ;
     RECT  3.805 176.688 3.889 178.536 ;
     RECT  3.341 41.232 3.913 42.168 ;
     RECT  2.801 121.968 3.913 121.992 ;
     RECT  3.011 141.504 3.913 143.016 ;
     RECT  2.704 213.408 3.916 213.72 ;
     RECT  3.443 182.448 3.917 182.472 ;
     RECT  3.089 49.44 3.923 50.04 ;
     RECT  2.837 180.144 3.923 181.272 ;
     RECT  3.877 47.808 3.949 48.408 ;
     RECT  2.704 85.392 3.949 86.76 ;
     RECT  3.829 87.792 3.949 89.976 ;
     RECT  2.704 111.168 3.949 114.312 ;
     RECT  2.801 123.312 3.949 136.056 ;
     RECT  3.829 72.816 3.971 76.968 ;
     RECT  2.801 91.488 3.973 110.04 ;
     RECT  3.781 116.304 3.973 117.864 ;
     RECT  3.841 145.296 3.973 147.288 ;
     RECT  3.913 121.968 3.989 122.088 ;
     RECT  3.913 41.232 4.019 42.216 ;
     RECT  3.949 47.28 4.019 48.408 ;
     RECT  3.539 150.192 4.019 151.656 ;
     RECT  3.971 75.168 4.021 76.968 ;
     RECT  2.837 82.848 4.021 84.12 ;
     RECT  2.704 137.28 4.021 139.656 ;
     RECT  3.973 145.152 4.021 147.288 ;
     RECT  3.011 190.464 4.021 191.592 ;
     RECT  3.949 111.168 4.057 114.504 ;
     RECT  3.443 226.32 4.057 226.344 ;
     RECT  3.989 122.064 4.061 122.088 ;
     RECT  3.98 52.944 4.067 52.968 ;
     RECT  4.021 189.84 4.067 191.592 ;
     RECT  3.973 91.44 4.093 110.04 ;
     RECT  4.057 111.168 4.093 115.272 ;
     RECT  3.973 116.304 4.093 118.008 ;
     RECT  4.067 189.84 4.115 190.488 ;
     RECT  3.913 140.736 4.117 143.016 ;
     RECT  4.021 144.336 4.117 147.288 ;
     RECT  3.685 78.624 4.124 80.328 ;
     RECT  2.837 81.504 4.124 81.528 ;
     RECT  4.021 82.656 4.124 84.12 ;
     RECT  4.093 111.168 4.129 118.008 ;
     RECT  2.801 119.04 4.129 120.84 ;
     RECT  4.117 144.192 4.129 147.288 ;
     RECT  4.124 82.656 4.163 84.216 ;
     RECT  4.093 91.296 4.165 110.04 ;
     RECT  2.704 154.272 4.165 155.064 ;
     RECT  3.395 187.392 4.165 187.704 ;
     RECT  2.704 188.688 4.165 188.808 ;
     RECT  4.057 226.272 4.169 226.344 ;
     RECT  3.949 123.264 4.201 136.056 ;
     RECT  4.019 150.432 4.205 151.608 ;
     RECT  4.124 78.624 4.211 81.528 ;
     RECT  4.165 187.392 4.213 188.808 ;
     RECT  4.115 189.84 4.213 190.344 ;
     RECT  2.873 212.064 4.237 212.088 ;
     RECT  2.837 35.856 4.277 35.88 ;
     RECT  3.733 163.056 4.277 165.432 ;
     RECT  4.019 47.28 4.307 47.304 ;
     RECT  2.837 195.504 4.309 195.528 ;
     RECT  3.449 201.456 4.345 204.072 ;
     RECT  4.237 211.872 4.373 212.088 ;
     RECT  3.916 213.408 4.373 213.432 ;
     RECT  4.117 140.736 4.381 143.112 ;
     RECT  4.129 144.192 4.381 147.624 ;
     RECT  3.395 186.096 4.381 186.36 ;
     RECT  4.213 187.392 4.381 190.344 ;
     RECT  4.019 41.232 4.403 42.168 ;
     RECT  2.704 26.496 4.405 26.52 ;
     RECT  3.913 27.6 4.405 27.624 ;
     RECT  3.697 61.104 4.405 63.192 ;
     RECT  2.704 70.56 4.405 71.688 ;
     RECT  4.201 122.112 4.405 136.056 ;
     RECT  4.021 137.04 4.405 139.656 ;
     RECT  3.913 168.72 4.405 168.744 ;
     RECT  3.973 45.84 4.412 45.864 ;
     RECT  2.704 43.824 4.453 43.848 ;
     RECT  4.412 44.976 4.453 45.864 ;
     RECT  3.395 159.888 4.453 160.2 ;
     RECT  3.395 161.52 4.453 161.544 ;
     RECT  4.316 192.576 4.453 192.6 ;
     RECT  4.373 211.872 4.457 213.432 ;
     RECT  4.453 220.08 4.481 220.104 ;
     RECT  4.201 221.184 4.481 221.208 ;
     RECT  3.557 56.208 4.489 56.232 ;
     RECT  4.405 61.104 4.489 63.24 ;
     RECT  4.021 75.168 4.489 77.352 ;
     RECT  4.405 26.208 4.493 27.624 ;
     RECT  4.489 60.384 4.493 63.24 ;
     RECT  4.453 159.888 4.493 161.544 ;
     RECT  2.867 194.304 4.493 194.328 ;
     RECT  4.165 91.008 4.501 110.04 ;
     RECT  4.129 111.168 4.501 120.84 ;
     RECT  4.481 220.08 4.501 221.208 ;
     RECT  2.704 14.496 4.525 14.52 ;
     RECT  4.497 22.464 4.525 22.488 ;
     RECT  4.405 168.72 4.525 168.792 ;
     RECT  2.704 169.872 4.525 170.424 ;
     RECT  2.837 239.568 4.525 239.784 ;
     RECT  4.493 26.208 4.529 26.52 ;
     RECT  4.453 43.824 4.529 45.864 ;
     RECT  3.773 156.768 4.529 156.792 ;
     RECT  4.493 27.6 4.549 27.624 ;
     RECT  4.345 28.656 4.549 28.68 ;
     RECT  3.923 49.536 4.549 50.04 ;
     RECT  3.949 85.392 4.549 89.976 ;
     RECT  4.501 91.008 4.549 120.84 ;
     RECT  2.704 214.896 4.549 215.496 ;
     RECT  4.021 216.864 4.549 216.888 ;
     RECT  4.529 43.824 4.561 45 ;
     RECT  4.165 65.52 4.561 65.544 ;
     RECT  3.305 66.672 4.561 66.696 ;
     RECT  2.704 197.808 4.561 197.832 ;
     RECT  3.203 205.776 4.561 205.8 ;
     RECT  4.345 206.88 4.561 206.904 ;
     RECT  4.561 43.776 4.565 45 ;
     RECT  4.525 168.72 4.565 170.424 ;
     RECT  4.381 186.096 4.565 190.344 ;
     RECT  4.501 219.216 4.588 221.208 ;
     RECT  4.549 214.896 4.595 217.416 ;
     RECT  4.405 70.368 4.597 71.688 ;
     RECT  3.973 149.088 4.597 149.112 ;
     RECT  4.277 163.056 4.597 163.176 ;
     RECT  4.019 48.384 4.601 48.408 ;
     RECT  4.561 65.52 4.601 66.696 ;
     RECT  4.381 140.736 4.601 147.72 ;
     RECT  4.309 195.456 4.601 195.528 ;
     RECT  4.525 22.464 4.609 23.4 ;
     RECT  4.163 82.704 4.637 84.216 ;
     RECT  4.601 140.736 4.637 147.624 ;
     RECT  3.889 177.168 4.643 178.536 ;
     RECT  3.877 222.24 4.645 222.264 ;
     RECT  4.597 70.08 4.655 71.688 ;
     RECT  2.837 68.16 4.669 68.952 ;
     RECT  4.655 70.08 4.669 71.832 ;
     RECT  4.595 217.392 4.669 217.416 ;
     RECT  4.549 182.4 4.691 182.424 ;
     RECT  4.565 190.32 4.691 190.344 ;
     RECT  4.645 222.24 4.691 222.888 ;
     RECT  4.561 205.776 4.693 206.904 ;
     RECT  4.652 235.152 4.693 235.176 ;
     RECT  4.489 75.168 4.709 77.448 ;
     RECT  4.669 217.392 4.709 217.752 ;
     RECT  4.669 68.16 4.739 71.832 ;
     RECT  2.704 18.768 4.741 18.792 ;
     RECT  4.601 66.144 4.741 66.696 ;
     RECT  4.739 68.16 4.741 70.584 ;
     RECT  3.923 180.672 4.741 181.272 ;
     RECT  3.449 199.584 4.741 199.752 ;
     RECT  4.345 201.456 4.741 204.744 ;
     RECT  3.773 224.496 4.741 224.52 ;
     RECT  2.704 39.888 4.745 39.912 ;
     RECT  4.067 191.52 4.745 191.592 ;
     RECT  4.165 153.408 4.748 155.064 ;
     RECT  4.489 56.208 4.777 56.616 ;
     RECT  4.345 57.6 4.777 57.624 ;
     RECT  4.493 60.384 4.781 63.192 ;
     RECT  4.597 163.008 4.781 163.176 ;
     RECT  4.565 169.008 4.781 170.424 ;
     RECT  4.7 17.52 4.787 17.544 ;
     RECT  4.7 36.432 4.787 36.456 ;
     RECT  4.741 66.144 4.787 70.584 ;
     RECT  3.349 9.12 4.789 9.144 ;
     RECT  2.837 51.312 4.789 51.336 ;
     RECT  4.709 76.944 4.789 77.448 ;
     RECT  4.211 78.624 4.789 80.28 ;
     RECT  4.525 14.496 4.805 15.384 ;
     RECT  3.305 12.768 4.813 12.792 ;
     RECT  3.395 158.64 4.813 158.664 ;
     RECT  4.741 224.496 4.813 224.712 ;
     RECT  4.777 56.208 4.817 57.624 ;
     RECT  4.643 177.648 4.817 178.536 ;
     RECT  4.741 199.584 4.817 204.744 ;
     RECT  4.748 152.64 4.835 155.064 ;
     RECT  4.588 219.264 4.835 221.208 ;
     RECT  4.813 11.952 4.837 12.792 ;
     RECT  4.805 13.92 4.837 15.384 ;
     RECT  4.595 214.896 4.844 215.928 ;
     RECT  3.305 166.416 4.849 166.44 ;
     RECT  2.704 167.568 4.849 167.592 ;
     RECT  2.704 6.288 4.853 6.312 ;
     RECT  4.789 8.304 4.876 10.056 ;
     RECT  4.835 220.032 4.876 221.208 ;
     RECT  4.693 235.152 4.883 235.992 ;
     RECT  4.549 85.392 4.885 120.84 ;
     RECT  4.405 122.112 4.885 139.656 ;
     RECT  4.637 140.736 4.885 141.288 ;
     RECT  4.457 213.168 4.885 213.432 ;
     RECT  4.844 214.704 4.885 215.928 ;
     RECT  4.693 205.776 4.895 207.576 ;
     RECT  4.837 11.952 4.897 15.384 ;
     RECT  4.561 197.808 4.921 198.456 ;
     RECT  4.897 12.768 4.924 15.384 ;
     RECT  4.849 166.416 4.925 167.592 ;
     RECT  4.817 199.584 4.931 204.36 ;
     RECT  4.813 224.4 4.931 224.712 ;
     RECT  4.417 230.832 4.933 230.856 ;
     RECT  3.34 232.56 4.933 233.784 ;
     RECT  4.549 27.6 4.961 29.208 ;
     RECT  4.741 18.672 4.979 19.416 ;
     RECT  4.933 230.832 4.979 234.264 ;
     RECT  4.777 33.024 4.981 33.048 ;
     RECT  4.549 49.536 4.981 50.088 ;
     RECT  4.895 205.488 4.981 207.576 ;
     RECT  3.877 208.608 4.981 209.784 ;
     RECT  4.165 196.704 4.988 196.728 ;
     RECT  3.673 55.056 4.993 55.08 ;
     RECT  4.817 56.208 4.993 57.48 ;
     RECT  4.277 164.736 4.993 165.432 ;
     RECT  4.925 166.416 4.993 167.544 ;
     RECT  4.493 159.888 4.997 160.776 ;
     RECT  4.931 199.584 4.997 203.016 ;
     RECT  4.979 231.6 5.02 234.264 ;
     RECT  4.981 33.024 5.027 33.384 ;
     RECT  4.981 205.488 5.027 209.784 ;
     RECT  4.957 34.848 5.029 34.872 ;
     RECT  3.769 37.632 5.033 37.656 ;
     RECT  5.027 207.456 5.069 207.72 ;
     RECT  4.565 43.776 5.075 44.088 ;
     RECT  4.787 67.488 5.075 70.584 ;
     RECT  4.565 186.096 5.075 188.808 ;
     RECT  5.027 205.488 5.075 206.328 ;
     RECT  2.704 24.672 5.077 24.696 ;
     RECT  4.885 85.392 5.101 120.984 ;
     RECT  4.885 122.112 5.101 141.288 ;
     RECT  2.801 227.52 5.101 227.544 ;
     RECT  4.997 201.888 5.105 203.016 ;
     RECT  5.069 207.552 5.105 207.72 ;
     RECT  5.029 34.56 5.123 34.872 ;
     RECT  4.781 60.384 5.123 61.56 ;
     RECT  5.101 85.392 5.123 141.288 ;
     RECT  4.924 13.824 5.137 15.384 ;
     RECT  5.073 16.752 5.137 16.776 ;
     RECT  4.637 84.096 5.137 84.216 ;
     RECT  5.123 85.392 5.137 138.744 ;
     RECT  4.961 28.416 5.141 29.208 ;
     RECT  5.077 24.672 5.164 25.416 ;
     RECT  4.979 19.392 5.171 19.416 ;
     RECT  5.137 13.824 5.177 16.776 ;
     RECT  3.377 183.696 5.209 183.72 ;
     RECT  4.883 235.968 5.209 235.992 ;
     RECT  4.781 169.008 5.213 169.896 ;
     RECT  5.075 186.096 5.213 186.984 ;
     RECT  4.885 213.168 5.249 215.928 ;
     RECT  3.971 72.816 5.269 73.8 ;
     RECT  4.745 191.568 5.281 191.592 ;
     RECT  4.453 192.576 5.281 193.272 ;
     RECT  4.169 226.32 5.285 226.344 ;
     RECT  4.876 220.032 5.329 220.056 ;
     RECT  5.125 20.544 5.357 20.568 ;
     RECT  5.077 58.704 5.357 58.728 ;
     RECT  5.137 84.096 5.357 138.744 ;
     RECT  3.601 171.648 5.365 174.744 ;
     RECT  4.876 8.304 5.393 9.672 ;
     RECT  5.164 24.672 5.393 25.08 ;
     RECT  5.075 68.16 5.411 70.584 ;
     RECT  5.269 72.816 5.411 74.088 ;
     RECT  5.123 140.64 5.411 141.288 ;
     RECT  4.205 151.008 5.413 151.608 ;
     RECT  5.123 60.384 5.42 61.272 ;
     RECT  4.988 196.032 5.429 196.728 ;
     RECT  4.789 51.312 5.461 51.816 ;
     RECT  5.365 170.976 5.461 174.744 ;
     RECT  4.559 176.16 5.461 176.184 ;
     RECT  4.529 26.496 5.501 26.52 ;
     RECT  5.461 51.312 5.501 52.2 ;
     RECT  5.105 201.888 5.501 202.968 ;
     RECT  5.249 213.408 5.501 215.928 ;
     RECT  5.177 16.224 5.507 16.776 ;
     RECT  5.42 60.192 5.507 61.272 ;
     RECT  5.393 9.648 5.509 9.672 ;
     RECT  5.281 191.568 5.509 193.272 ;
     RECT  5.413 150.384 5.533 151.608 ;
     RECT  4.817 177.696 5.533 178.536 ;
     RECT  4.993 179.568 5.533 179.592 ;
     RECT  5.075 205.776 5.537 206.328 ;
     RECT  5.501 214.32 5.537 215.928 ;
     RECT  2.801 30.192 5.569 30.216 ;
     RECT  4.849 31.632 5.569 31.656 ;
     RECT  5.497 48.432 5.581 48.456 ;
     RECT  4.637 142.704 5.605 147.624 ;
     RECT  4.403 41.808 5.609 42.168 ;
     RECT  4.993 55.056 5.609 57.48 ;
     RECT  5.507 60.384 5.609 61.272 ;
     RECT  5.461 170.976 5.609 176.184 ;
     RECT  5.209 182.88 5.609 183.72 ;
     RECT  4.211 81.504 5.641 81.528 ;
     RECT  4.637 82.704 5.641 82.968 ;
     RECT  5.609 41.856 5.651 42.168 ;
     RECT  5.569 30.192 5.653 31.656 ;
     RECT  5.281 210.816 5.653 210.84 ;
     RECT  4.457 211.872 5.653 212.088 ;
     RECT  5.653 210.816 5.699 212.088 ;
     RECT  4.835 153.408 5.701 155.064 ;
     RECT  4.813 158.496 5.701 158.664 ;
     RECT  4.993 164.736 5.701 167.544 ;
     RECT  5.641 81.504 5.708 82.968 ;
     RECT  5.357 84.096 5.708 135.672 ;
     RECT  5.411 140.784 5.708 141.288 ;
     RECT  5.609 55.872 5.717 57.48 ;
     RECT  5.708 140.784 5.749 141.72 ;
     RECT  5.605 142.704 5.749 147.672 ;
     RECT  5.701 158.4 5.749 158.664 ;
     RECT  5.213 186.912 5.753 186.984 ;
     RECT  5.537 206.304 5.753 206.328 ;
     RECT  5.717 57.456 5.785 57.48 ;
     RECT  4.781 163.056 5.789 163.176 ;
     RECT  5.701 164.16 5.789 167.544 ;
     RECT  4.709 217.728 5.789 217.752 ;
     RECT  5.708 81.504 5.795 135.672 ;
     RECT  5.749 140.784 5.795 147.672 ;
     RECT  4.709 75.168 5.804 75.192 ;
     RECT  4.597 148.752 5.821 149.112 ;
     RECT  5.533 150.384 5.821 152.232 ;
     RECT  5.789 163.152 5.821 163.176 ;
     RECT  5.789 164.16 5.821 166.536 ;
     RECT  5.795 142.08 5.825 147.672 ;
     RECT  5.101 46.944 5.857 46.968 ;
     RECT  3.395 185.088 5.857 185.112 ;
     RECT  4.739 71.616 5.861 71.832 ;
     RECT  5.804 75.072 5.861 75.192 ;
     RECT  5.785 57.456 5.869 57.576 ;
     RECT  5.861 75.072 5.891 75.096 ;
     RECT  5.749 158.4 5.891 159.576 ;
     RECT  5.717 55.872 5.897 56.424 ;
     RECT  5.609 172.368 5.897 176.184 ;
     RECT  5.075 188.688 5.897 188.808 ;
     RECT  5.857 46.464 5.929 46.968 ;
     RECT  4.789 76.944 5.929 80.28 ;
     RECT  5.795 81.504 5.929 83.064 ;
     RECT  4.849 64.32 5.933 64.344 ;
     RECT  5.213 169.392 5.933 169.896 ;
     RECT  5.825 142.08 5.939 145.416 ;
     RECT  5.533 177.696 5.941 179.592 ;
     RECT  4.741 180.672 5.941 181.464 ;
     RECT  5.101 227.52 5.941 227.976 ;
     RECT  5.941 226.752 5.969 228.36 ;
     RECT  5.9 38.592 5.987 38.616 ;
     RECT  5.969 227.952 5.987 228.36 ;
     RECT  5.857 229.728 5.987 229.752 ;
     RECT  5.941 177.696 5.989 181.464 ;
     RECT  4.921 197.712 5.989 198.456 ;
     RECT  4.997 199.584 5.989 200.664 ;
     RECT  5.989 197.712 5.996 200.664 ;
     RECT  5.509 193.248 5.999 193.272 ;
     RECT  5.411 69.84 6.005 70.584 ;
     RECT  5.027 208.704 6.005 209.784 ;
     RECT  5.987 228.336 6.028 228.36 ;
     RECT  5.996 197.616 6.035 200.664 ;
     RECT  4.781 62.736 6.037 63.192 ;
     RECT  5.965 157.344 6.037 157.368 ;
     RECT  5.891 158.4 6.037 158.616 ;
     RECT  5.957 17.616 6.041 17.64 ;
     RECT  5.653 31.632 6.041 31.656 ;
     RECT  5.027 33.36 6.041 33.384 ;
     RECT  5.941 40.464 6.041 40.488 ;
     RECT  5.501 201.888 6.041 202.632 ;
     RECT  5.989 177.264 6.048 181.464 ;
     RECT  6.035 197.616 6.076 198.936 ;
     RECT  5.075 43.776 6.077 43.848 ;
     RECT  4.705 53.568 6.077 53.592 ;
     RECT  5.869 57.456 6.077 57.48 ;
     RECT  4.787 66.144 6.077 66.168 ;
     RECT  5.939 142.08 6.077 145.32 ;
     RECT  5.537 215.472 6.077 215.928 ;
     RECT  4.876 221.184 6.077 221.208 ;
     RECT  4.691 222.864 6.077 222.888 ;
     RECT  4.931 224.688 6.077 224.712 ;
     RECT  5.609 182.88 6.083 183.528 ;
     RECT  5.429 196.032 6.083 196.632 ;
     RECT  6.076 197.616 6.083 198.456 ;
     RECT  6.083 197.712 6.085 198.456 ;
     RECT  4.525 239.568 6.085 239.832 ;
     RECT  5.101 194.928 6.121 194.952 ;
     RECT  6.083 183.504 6.124 183.528 ;
     RECT  5.893 37.008 6.131 37.032 ;
     RECT  6.077 144.336 6.131 145.32 ;
     RECT  6.085 238.8 6.131 239.832 ;
     RECT  6.048 177.264 6.149 181.224 ;
     RECT  5.969 226.752 6.149 226.776 ;
     RECT  5.02 231.6 6.149 233.4 ;
     RECT  6.131 238.8 6.172 239.784 ;
     RECT  5.933 169.392 6.179 169.512 ;
     RECT  4.609 22.464 6.185 22.488 ;
     RECT  6.005 209.184 6.227 209.784 ;
     RECT  5.533 44.976 6.229 45 ;
     RECT  5.929 46.464 6.229 47.256 ;
     RECT  4.981 49.488 6.229 50.088 ;
     RECT  5.701 153.408 6.229 155.496 ;
     RECT  5.789 167.52 6.229 167.544 ;
     RECT  6.077 215.904 6.229 215.928 ;
     RECT  6.227 209.76 6.257 209.784 ;
     RECT  6.229 44.976 6.275 47.256 ;
     RECT  6.037 157.344 6.275 158.616 ;
     RECT  6.179 169.392 6.275 169.416 ;
     RECT  6.109 187.536 6.275 187.56 ;
     RECT  5.999 193.248 6.275 193.608 ;
     RECT  6.229 215.904 6.275 216.36 ;
     RECT  6.229 153.408 6.277 156.024 ;
     RECT  6.181 234.816 6.277 234.84 ;
     RECT  5.209 235.968 6.277 236.568 ;
     RECT  5.609 61.104 6.293 61.272 ;
     RECT  5.795 84.096 6.293 135.672 ;
     RECT  6.149 178.368 6.293 181.224 ;
     RECT  6.149 231.6 6.293 232.584 ;
     RECT  6.277 234.816 6.323 236.568 ;
     RECT  4.924 12.768 6.325 12.792 ;
     RECT  5.821 148.752 6.325 152.232 ;
     RECT  6.277 153.264 6.325 156.024 ;
     RECT  5.509 191.568 6.325 192.024 ;
     RECT  6.293 178.368 6.329 179.016 ;
     RECT  6.229 190.32 6.329 190.344 ;
     RECT  6.229 49.008 6.365 50.088 ;
     RECT  5.897 56.208 6.365 56.424 ;
     RECT  5.795 140.784 6.373 141 ;
     RECT  6.293 134.832 6.419 135.672 ;
     RECT  6.077 142.08 6.419 143.16 ;
     RECT  5.393 8.304 6.433 8.328 ;
     RECT  5.699 211.344 6.437 211.368 ;
     RECT  6.325 12.528 6.469 12.792 ;
     RECT  5.357 136.656 6.469 138.744 ;
     RECT  6.433 8.304 6.473 8.52 ;
     RECT  5.177 13.824 6.473 14.52 ;
     RECT  5.821 163.152 6.473 166.536 ;
     RECT  6.229 167.52 6.473 167.592 ;
     RECT  5.537 214.32 6.473 214.344 ;
     RECT  6.293 84.096 6.509 133.272 ;
     RECT  6.035 200.64 6.517 200.664 ;
     RECT  6.041 201.888 6.517 202.44 ;
     RECT  4.931 204.336 6.533 204.36 ;
     RECT  6.325 191.52 6.541 192.024 ;
     RECT  5.393 25.056 6.545 25.08 ;
     RECT  6.131 144.384 6.545 145.32 ;
     RECT  6.325 148.752 6.545 156.024 ;
     RECT  6.005 69.984 6.577 70.584 ;
     RECT  5.861 71.616 6.577 71.736 ;
     RECT  5.141 28.416 6.581 28.44 ;
     RECT  5.651 41.856 6.581 41.88 ;
     RECT  6.509 115.536 6.581 133.272 ;
     RECT  6.469 135.84 6.581 138.744 ;
     RECT  5.105 207.696 6.581 207.72 ;
     RECT  6.275 45.648 6.617 45.672 ;
     RECT  5.929 76.944 6.617 83.064 ;
     RECT  6.533 204.336 6.617 205.224 ;
     RECT  5.501 52.176 6.653 52.2 ;
     RECT  6.149 177.264 6.653 177.288 ;
     RECT  6.541 191.52 6.659 192.12 ;
     RECT  5.123 34.848 6.689 34.872 ;
     RECT  6.037 62.736 6.725 63.24 ;
     RECT  6.581 115.632 6.725 133.272 ;
     RECT  4.997 160.752 6.725 160.776 ;
     RECT  6.517 200.64 6.725 202.44 ;
     RECT  6.577 168.24 6.749 168.264 ;
     RECT  6.509 84.096 6.757 114.552 ;
     RECT  5.641 21.12 6.761 21.144 ;
     RECT  5.857 184.8 6.764 185.112 ;
     RECT  5.825 146.4 6.793 147.672 ;
     RECT  6.545 148.752 6.793 155.112 ;
     RECT  6.749 168.24 6.803 168.84 ;
     RECT  6.581 136.656 6.829 138.744 ;
     RECT  6.793 139.728 6.829 139.752 ;
     RECT  6.253 186.336 6.829 186.36 ;
     RECT  6.757 231.168 6.829 231.192 ;
     RECT  6.365 56.4 6.833 56.424 ;
     RECT  6.373 140.736 6.833 141 ;
     RECT  5.897 188.784 6.833 188.808 ;
     RECT  6.473 8.496 6.853 8.52 ;
     RECT  6.433 10.704 6.853 10.728 ;
     RECT  6.275 158.256 6.965 158.616 ;
     RECT  6.473 163.152 7.009 164.616 ;
     RECT  7.009 162.864 7.045 164.616 ;
     RECT  7.045 161.904 7.081 164.616 ;
     RECT  6.577 69.984 7.093 71.736 ;
     RECT  6.829 136.656 7.117 139.752 ;
     RECT  6.419 142.416 7.189 143.16 ;
     RECT  6.545 144.384 7.189 144.792 ;
     RECT  6.617 204.336 7.189 204.6 ;
     RECT  6.793 146.4 7.237 155.112 ;
     RECT  7.237 146.352 7.297 155.112 ;
     RECT  6.829 231.024 7.333 231.192 ;
     RECT  6.293 180.528 7.369 181.224 ;
     RECT  7.189 204.048 7.549 204.6 ;
     RECT  7.513 66.768 7.669 66.792 ;
     RECT  5.411 72.816 7.693 73.56 ;
     RECT  6.757 84.048 7.693 114.552 ;
     RECT  5.411 68.16 7.729 68.664 ;
     RECT  7.093 69.888 7.729 71.736 ;
     RECT  6.725 200.64 7.729 201.192 ;
     RECT  6.853 7.392 7.808 7.416 ;
     RECT  6.853 8.496 7.808 9.672 ;
     RECT  6.853 10.704 7.808 11.016 ;
     RECT  6.469 12.192 7.808 12.792 ;
     RECT  6.473 13.824 7.808 13.848 ;
     RECT  5.507 16.224 7.808 16.248 ;
     RECT  5.653 30.192 7.808 30.216 ;
     RECT  6.077 43.824 7.808 43.848 ;
     RECT  6.365 49.488 7.808 49.512 ;
     RECT  6.293 61.104 7.808 61.128 ;
     RECT  6.725 63.024 7.808 63.24 ;
     RECT  6.901 64.416 7.808 64.44 ;
     RECT  7.669 66.768 7.808 67.08 ;
     RECT  7.729 68.16 7.808 71.736 ;
     RECT  7.693 72.816 7.808 73.8 ;
     RECT  6.617 77.136 7.808 83.064 ;
     RECT  7.693 84.048 7.808 114.6 ;
     RECT  6.725 115.968 7.808 133.272 ;
     RECT  6.419 134.832 7.808 134.856 ;
     RECT  7.117 136.656 7.808 140.088 ;
     RECT  7.189 142.416 7.808 144.792 ;
     RECT  7.297 145.968 7.808 155.112 ;
     RECT  6.965 158.256 7.808 159.192 ;
     RECT  7.081 161.328 7.808 164.616 ;
     RECT  6.473 166.224 7.808 166.536 ;
     RECT  6.803 168.576 7.808 168.84 ;
     RECT  5.609 170.976 7.808 171 ;
     RECT  5.897 172.368 7.808 175.704 ;
     RECT  7.369 180.144 7.808 181.224 ;
     RECT  6.764 184.704 7.808 185.112 ;
     RECT  6.829 186.192 7.808 186.36 ;
     RECT  6.659 191.52 7.808 191.544 ;
     RECT  7.285 193.248 7.808 193.272 ;
     RECT  6.085 197.712 7.808 197.736 ;
     RECT  7.729 199.872 7.808 201.192 ;
     RECT  6.725 202.416 7.808 202.44 ;
     RECT  7.549 203.664 7.808 204.6 ;
     RECT  7.541 206.928 7.808 206.952 ;
     RECT  7.513 212.064 7.808 212.088 ;
     RECT  6.275 216.336 7.808 216.36 ;
     RECT  7.405 218.88 7.808 218.904 ;
     RECT  6.325 220.608 7.808 220.632 ;
     RECT  7.333 231.024 7.808 232.008 ;
     RECT  6.323 235.008 7.808 236.568 ;
     RECT  6.172 239.568 7.808 239.784 ;
     RECT  7.808 2.148 7.912 244.092 ;
     RECT  7.912 2.418 8.104 243.822 ;
     RECT  8.104 76.896 8.165 136.008 ;
     RECT  8.104 63.072 8.201 63.096 ;
     RECT  8.104 139.2 8.237 141.576 ;
     RECT  8.104 162.336 8.273 166.488 ;
     RECT  8.104 193.248 8.353 193.272 ;
     RECT  8.104 153.216 8.381 155.112 ;
     RECT  8.381 153.216 8.435 155.016 ;
     RECT  8.104 185.808 8.461 186.216 ;
     RECT  8.104 213.744 8.483 213.768 ;
     RECT  8.165 76.896 8.525 135.96 ;
     RECT  8.104 137.04 8.525 138.12 ;
     RECT  8.104 149.184 8.531 150.504 ;
     RECT  8.104 158.4 8.531 159.192 ;
     RECT  8.104 71.664 8.633 71.688 ;
     RECT  8.525 76.896 8.669 135.672 ;
     RECT  8.273 166.464 8.675 166.488 ;
     RECT  8.104 203.664 8.723 204.6 ;
     RECT  8.104 175.68 8.771 175.848 ;
     RECT  8.104 72.816 8.777 75.72 ;
     RECT  8.669 76.896 8.819 135.144 ;
     RECT  8.273 162.336 8.819 165.336 ;
     RECT  8.531 158.496 8.885 159.192 ;
     RECT  8.885 158.88 8.957 159.192 ;
     RECT  8.104 13.056 9.001 13.08 ;
     RECT  8.104 152.208 9.073 152.232 ;
     RECT  8.104 199.872 9.107 200.664 ;
     RECT  8.104 67.92 9.133 68.664 ;
     RECT  8.104 11.376 9.145 11.4 ;
     RECT  8.723 203.664 9.155 203.688 ;
     RECT  9.133 67.92 9.157 68.856 ;
     RECT  8.237 139.44 9.157 141.576 ;
     RECT  8.104 142.752 9.157 143.064 ;
     RECT  9.097 151.056 9.169 151.08 ;
     RECT  9.157 67.92 9.173 68.952 ;
     RECT  8.104 145.968 9.203 146.472 ;
     RECT  8.104 212.064 9.203 212.088 ;
     RECT  8.525 137.04 9.205 137.064 ;
     RECT  8.531 149.184 9.209 149.64 ;
     RECT  9.173 68.16 9.245 68.952 ;
     RECT  8.104 180.144 9.251 180.552 ;
     RECT  8.104 69.984 9.277 70.68 ;
     RECT  9.097 156.432 9.277 156.456 ;
     RECT  8.819 76.896 9.281 135.048 ;
     RECT  8.461 186.192 9.299 186.216 ;
     RECT  9.097 64.32 9.347 64.344 ;
     RECT  9.203 146.064 9.347 146.472 ;
     RECT  9.277 156.288 9.385 156.456 ;
     RECT  9.245 68.16 9.389 68.856 ;
     RECT  9.281 76.896 9.389 109.512 ;
     RECT  8.819 162.336 9.443 165.288 ;
     RECT  8.777 72.96 9.493 75.72 ;
     RECT  9.389 76.896 9.493 80.088 ;
     RECT  9.205 136.752 9.529 137.064 ;
     RECT  9.347 146.448 9.533 146.472 ;
     RECT  9.493 72.96 9.569 80.088 ;
     RECT  9.277 69.984 9.637 70.728 ;
     RECT  9.569 72.96 9.641 79.608 ;
     RECT  9.281 110.592 9.641 135.048 ;
     RECT  9.529 136.176 9.641 137.064 ;
     RECT  9.389 68.16 9.677 68.712 ;
     RECT  9.641 75.168 9.713 79.608 ;
     RECT  8.957 158.88 9.713 158.904 ;
     RECT  8.104 19.776 9.731 19.8 ;
     RECT  8.104 210.96 9.731 210.984 ;
     RECT  9.457 186.336 9.779 186.36 ;
     RECT  9.637 69.984 9.781 70.968 ;
     RECT  8.435 153.264 9.781 155.016 ;
     RECT  9.781 69.984 9.817 71.112 ;
     RECT  9.641 72.96 9.829 73.8 ;
     RECT  8.525 138.096 9.853 138.12 ;
     RECT  9.157 139.44 9.853 143.064 ;
     RECT  9.169 151.056 9.889 151.656 ;
     RECT  9.641 110.592 9.893 133.944 ;
     RECT  9.889 151.008 9.893 151.656 ;
     RECT  9.713 75.168 9.929 78.696 ;
     RECT  9.829 72.288 9.965 73.8 ;
     RECT  8.104 235.008 9.971 235.032 ;
     RECT  9.781 152.832 10.001 155.016 ;
     RECT  9.893 151.008 10.021 151.176 ;
     RECT  9.781 147.888 10.028 147.912 ;
     RECT  9.209 149.184 10.028 149.4 ;
     RECT  9.929 75.792 10.067 78.696 ;
     RECT  8.104 160.464 10.069 160.488 ;
     RECT  9.389 81.696 10.073 109.512 ;
     RECT  9.997 234.864 10.081 234.888 ;
     RECT  10.069 160.416 10.105 160.488 ;
     RECT  9.157 144.192 10.241 144.216 ;
     RECT  9.641 135.024 10.253 135.048 ;
     RECT  9.853 138.096 10.253 143.064 ;
     RECT  10.241 144.192 10.325 144.792 ;
     RECT  10.253 140.064 10.355 143.064 ;
     RECT  10.028 147.888 10.357 149.4 ;
     RECT  9.965 72.816 10.361 73.8 ;
     RECT  9.893 115.92 10.397 133.944 ;
     RECT  9.385 156.288 10.397 156.744 ;
     RECT  9.443 164.352 10.403 165.288 ;
     RECT  10.355 140.976 10.429 143.064 ;
     RECT  10.073 81.696 10.432 82.104 ;
     RECT  9.251 180.144 10.451 180.168 ;
     RECT  10.432 81.648 10.501 82.104 ;
     RECT  10.001 152.88 10.501 155.016 ;
     RECT  10.397 156.288 10.501 156.312 ;
     RECT  10.429 140.976 10.513 143.976 ;
     RECT  10.073 83.088 10.537 109.512 ;
     RECT  9.893 110.592 10.537 114.936 ;
     RECT  10.397 115.92 10.541 133.752 ;
     RECT  10.513 140.976 10.541 143.064 ;
     RECT  10.105 160.32 10.573 160.488 ;
     RECT  10.067 75.792 10.577 78.648 ;
     RECT  9.641 136.368 10.604 137.064 ;
     RECT  10.253 138.096 10.604 138.6 ;
     RECT  10.357 146.976 10.609 149.4 ;
     RECT  10.501 80.976 10.645 82.104 ;
     RECT  10.537 83.088 10.685 114.936 ;
     RECT  10.021 150.384 10.685 151.176 ;
     RECT  8.104 231.024 10.691 231.048 ;
     RECT  10.609 146.448 10.717 149.4 ;
     RECT  10.645 80.4 10.739 82.104 ;
     RECT  10.361 73.152 10.757 73.8 ;
     RECT  10.573 160.32 10.757 160.68 ;
     RECT  10.717 145.776 10.793 149.4 ;
     RECT  10.793 145.776 10.835 145.8 ;
     RECT  9.457 212.592 10.835 212.616 ;
     RECT  8.104 236.064 10.883 236.088 ;
     RECT  10.757 73.248 10.901 73.8 ;
     RECT  10.739 80.4 10.931 81.816 ;
     RECT  9.443 162.336 10.931 162.888 ;
     RECT  10.577 77.568 10.937 78.504 ;
     RECT  10.604 136.368 10.937 138.6 ;
     RECT  10.285 157.776 10.937 157.8 ;
     RECT  9.817 69.984 11.075 71.208 ;
     RECT  10.577 75.792 11.161 75.816 ;
     RECT  10.931 162.336 11.171 162.84 ;
     RECT  10.757 160.32 11.221 160.344 ;
     RECT  10.793 146.976 11.225 149.4 ;
     RECT  10.685 83.184 11.257 114.936 ;
     RECT  10.541 115.92 11.257 133.032 ;
     RECT  10.937 136.368 11.269 138.12 ;
     RECT  10.685 150.48 11.333 151.176 ;
     RECT  11.221 134.832 11.365 134.856 ;
     RECT  11.269 136.08 11.365 138.12 ;
     RECT  11.365 134.832 11.411 138.12 ;
     RECT  11.411 134.832 11.438 136.824 ;
     RECT  11.438 134.832 11.473 136.776 ;
     RECT  11.473 134.544 11.477 136.776 ;
     RECT  11.225 147.888 11.513 149.4 ;
     RECT  10.541 140.976 11.581 141.816 ;
     RECT  10.501 152.88 11.581 156.312 ;
     RECT  10.937 77.568 11.617 78.456 ;
     RECT  11.581 152.88 11.693 157.128 ;
     RECT  10.541 143.04 11.747 143.064 ;
     RECT  11.693 152.88 11.801 156.312 ;
     RECT  11.581 140.208 11.845 141.96 ;
     RECT  11.333 150.48 11.873 150.744 ;
     RECT  11.873 150.48 11.909 150.504 ;
     RECT  11.509 144.768 11.945 144.792 ;
     RECT  11.257 83.184 11.969 133.032 ;
     RECT  10.931 80.928 11.977 81.816 ;
     RECT  11.969 83.184 11.977 133.416 ;
     RECT  11.617 76.944 11.981 78.456 ;
     RECT  11.977 82.992 11.981 133.416 ;
     RECT  11.845 140.112 11.987 141.96 ;
     RECT  11.171 162.672 11.987 162.84 ;
     RECT  11.981 77.76 12.017 78.456 ;
     RECT  11.941 161.328 12.179 161.352 ;
     RECT  12.017 77.952 12.193 78.456 ;
     RECT  11.981 82.992 12.227 132.12 ;
     RECT  11.411 137.856 12.236 138.12 ;
     RECT  12.121 76.512 12.265 76.776 ;
     RECT  11.977 80.832 12.284 81.816 ;
     RECT  11.941 146.352 12.409 146.376 ;
     RECT  12.265 76.464 12.437 76.776 ;
     RECT  12.409 146.256 12.445 146.376 ;
     RECT  12.193 77.952 12.481 78.504 ;
     RECT  12.284 80.496 12.517 81.816 ;
     RECT  12.227 82.992 12.517 112.44 ;
     RECT  11.981 133.392 12.517 133.416 ;
     RECT  11.477 134.544 12.517 135.624 ;
     RECT  11.477 136.752 12.517 136.776 ;
     RECT  12.236 137.856 12.517 138.36 ;
     RECT  12.445 146.256 12.553 146.424 ;
     RECT  12.553 146.208 12.589 146.424 ;
     RECT  12.481 77.952 12.661 79.032 ;
     RECT  12.517 80.496 12.661 112.44 ;
     RECT  11.513 147.888 12.661 148.104 ;
     RECT  12.517 136.752 12.805 138.36 ;
     RECT  12.553 139.488 12.805 139.512 ;
     RECT  12.437 76.368 13.093 76.776 ;
     RECT  9.677 68.688 13.208 68.712 ;
     RECT  11.075 69.984 13.208 70.536 ;
     RECT  10.901 73.536 13.208 73.8 ;
     RECT  13.093 76.368 13.208 76.872 ;
     RECT  12.661 77.952 13.208 112.44 ;
     RECT  12.227 113.568 13.208 132.12 ;
     RECT  12.517 133.392 13.208 135.624 ;
     RECT  12.805 136.752 13.208 139.512 ;
     RECT  11.987 140.88 13.208 141.96 ;
     RECT  12.589 145.872 13.208 146.472 ;
     RECT  12.661 147.6 13.208 148.104 ;
     RECT  11.513 149.136 13.208 149.4 ;
     RECT  12.445 151.488 13.208 151.608 ;
     RECT  11.801 152.88 13.208 155.64 ;
     RECT  12.553 157.296 13.208 157.32 ;
     RECT  11.221 160.176 13.208 160.344 ;
     RECT  11.987 162.672 13.208 162.696 ;
     RECT  10.403 164.352 13.208 164.52 ;
     RECT  8.104 168.288 13.208 168.84 ;
     RECT  8.104 170.976 13.208 171 ;
     RECT  8.104 174.192 13.208 174.216 ;
     RECT  8.771 175.824 13.208 175.848 ;
     RECT  8.104 197.712 13.208 197.736 ;
     RECT  9.107 199.872 13.208 199.896 ;
     RECT  8.104 216.336 13.208 216.36 ;
     RECT  13.208 2.148 13.312 244.092 ;
     RECT  13.312 2.418 13.504 243.822 ;
     RECT  13.504 76.464 13.667 131.976 ;
     RECT  13.667 78.336 13.673 131.976 ;
     RECT  13.504 140.736 13.673 143.112 ;
     RECT  13.673 79.824 13.709 131.976 ;
     RECT  13.504 168.816 13.715 168.84 ;
     RECT  13.667 76.464 13.745 76.872 ;
     RECT  13.709 130.752 13.745 131.976 ;
     RECT  13.504 146.112 13.763 149.256 ;
     RECT  13.504 133.968 13.853 138.024 ;
     RECT  13.673 140.736 13.933 142.536 ;
     RECT  13.504 159.984 13.997 160.008 ;
     RECT  13.709 79.824 14.003 129.768 ;
     RECT  13.763 146.208 14.033 149.256 ;
     RECT  13.504 139.104 14.041 139.512 ;
     RECT  14.003 80.4 14.099 129.768 ;
     RECT  13.853 134.064 14.208 138.024 ;
     RECT  14.033 146.256 14.213 149.256 ;
     RECT  14.099 117.552 14.249 129.768 ;
     RECT  13.504 150.48 14.249 150.504 ;
     RECT  13.504 158.544 14.285 158.568 ;
     RECT  13.504 164.352 14.291 164.52 ;
     RECT  14.213 146.448 14.429 149.256 ;
     RECT  13.933 140.736 14.465 141.72 ;
     RECT  13.504 68.688 14.531 68.712 ;
     RECT  14.429 147.456 14.537 149.256 ;
     RECT  14.537 147.456 14.609 147.912 ;
     RECT  13.504 152.88 14.713 155.16 ;
     RECT  14.465 140.832 14.825 141.72 ;
     RECT  14.099 80.4 14.861 116.472 ;
     RECT  13.504 162.672 14.867 162.696 ;
     RECT  14.537 149.136 14.915 149.256 ;
     RECT  14.208 134.064 15.011 137.88 ;
     RECT  13.673 78.336 15.037 78.648 ;
     RECT  14.861 80.496 15.061 116.472 ;
     RECT  14.249 117.552 15.061 129.528 ;
     RECT  13.504 199.872 15.107 199.896 ;
     RECT  14.713 151.92 15.113 155.16 ;
     RECT  14.825 141.36 15.185 141.72 ;
     RECT  15.113 152.16 15.401 155.16 ;
     RECT  13.504 175.824 15.443 175.848 ;
     RECT  15.397 132.768 15.539 132.792 ;
     RECT  13.745 76.464 15.541 76.488 ;
     RECT  14.429 146.448 15.581 146.472 ;
     RECT  15.185 141.696 15.613 141.72 ;
     RECT  15.541 76.464 15.649 76.872 ;
     RECT  13.745 130.752 15.649 131.688 ;
     RECT  14.041 139.2 15.649 139.512 ;
     RECT  15.649 139.2 15.685 139.752 ;
     RECT  15.037 78.336 15.721 78.696 ;
     RECT  14.609 147.888 15.721 147.912 ;
     RECT  15.613 141.696 15.793 142.488 ;
     RECT  15.649 76.464 15.833 76.968 ;
     RECT  15.685 139.2 15.833 140.088 ;
     RECT  15.061 80.496 15.865 129.528 ;
     RECT  15.649 130.752 15.865 132.408 ;
     RECT  15.721 147.504 15.937 147.912 ;
     RECT  15.011 134.256 15.973 137.88 ;
     RECT  14.291 164.352 16.019 164.376 ;
     RECT  15.833 76.464 16.049 76.872 ;
     RECT  15.833 139.488 16.049 140.088 ;
     RECT  15.793 141.696 16.049 142.632 ;
     RECT  15.829 150.72 16.117 150.744 ;
     RECT  16.117 150.48 16.229 150.744 ;
     RECT  15.865 144.144 16.261 144.36 ;
     RECT  15.401 152.16 16.301 154.968 ;
     RECT  15.865 80.496 16.333 132.408 ;
     RECT  15.973 134.256 16.333 138.024 ;
     RECT  16.049 142.464 16.373 142.632 ;
     RECT  15.937 147.264 16.373 147.912 ;
     RECT  16.373 147.504 16.405 147.912 ;
     RECT  14.915 149.232 16.405 149.256 ;
     RECT  16.333 80.304 16.413 132.408 ;
     RECT  16.229 150.72 16.441 150.744 ;
     RECT  16.301 152.16 16.445 152.184 ;
     RECT  16.301 153.168 16.445 154.968 ;
     RECT  16.441 150.72 16.513 151.08 ;
     RECT  15.721 78.336 16.517 78.984 ;
     RECT  16.049 76.848 16.553 76.872 ;
     RECT  16.261 143.76 16.553 144.36 ;
     RECT  16.333 134.256 16.585 138.072 ;
     RECT  16.517 78.528 16.621 78.984 ;
     RECT  16.413 80.256 16.621 132.408 ;
     RECT  16.585 133.44 16.697 138.072 ;
     RECT  16.513 150.72 16.733 151.368 ;
     RECT  16.445 153.168 16.769 154.536 ;
     RECT  16.733 150.72 16.877 151.08 ;
     RECT  16.769 153.456 16.877 154.536 ;
     RECT  16.877 150.72 16.913 150.744 ;
     RECT  16.697 136.176 16.981 138.072 ;
     RECT  16.049 139.488 17.057 139.992 ;
     RECT  16.553 143.76 17.129 144.216 ;
     RECT  16.405 147.504 17.129 149.256 ;
     RECT  17.129 147.504 17.165 149.112 ;
     RECT  17.165 148.944 17.237 149.112 ;
     RECT  13.504 170.976 17.341 171 ;
     RECT  16.621 78.528 17.363 132.408 ;
     RECT  17.341 170.784 17.381 171 ;
     RECT  17.057 139.728 17.413 139.992 ;
     RECT  17.129 144.144 17.497 144.216 ;
     RECT  16.373 142.464 17.665 142.488 ;
     RECT  16.981 136.176 17.701 138.408 ;
     RECT  17.701 136.176 18.097 138.456 ;
     RECT  17.413 139.728 18.457 140.088 ;
     RECT  13.504 70.512 18.608 70.536 ;
     RECT  13.504 73.536 18.608 73.8 ;
     RECT  17.363 78.96 18.608 132.408 ;
     RECT  16.697 133.44 18.608 135.192 ;
     RECT  18.097 136.176 18.608 138.504 ;
     RECT  18.457 139.584 18.608 140.088 ;
     RECT  17.665 141.936 18.608 142.488 ;
     RECT  17.497 144.144 18.608 144.168 ;
     RECT  17.165 147.888 18.608 147.912 ;
     RECT  17.237 149.088 18.608 149.112 ;
     RECT  17.688 150.432 18.608 150.552 ;
     RECT  16.877 153.456 18.608 154.248 ;
     RECT  17.381 170.784 18.608 170.808 ;
     RECT  13.504 174.192 18.608 174.216 ;
     RECT  18.608 2.148 18.712 244.092 ;
     RECT  18.712 2.418 18.904 243.822 ;
     RECT  18.904 139.728 18.929 139.944 ;
     RECT  18.904 136.416 18.965 137.832 ;
     RECT  18.904 142.464 19.181 142.488 ;
     RECT  18.904 78.624 19.331 134.856 ;
     RECT  18.965 137.808 19.397 137.832 ;
     RECT  18.929 139.92 19.505 139.944 ;
     RECT  19.331 78.672 19.613 134.856 ;
     RECT  19.613 78.912 19.757 134.856 ;
     RECT  19.757 80.064 20.725 134.856 ;
     RECT  18.904 174.192 20.753 174.216 ;
     RECT  19.757 78.912 20.761 78.984 ;
     RECT  20.725 79.968 20.761 134.856 ;
     RECT  18.904 170.784 20.819 170.808 ;
     RECT  20.753 173.856 20.837 174.216 ;
     RECT  20.761 78.912 21.089 134.856 ;
     RECT  21.089 79.968 21.125 134.856 ;
     RECT  20.837 174.192 21.161 174.216 ;
     RECT  21.125 119.808 21.305 134.856 ;
     RECT  21.305 119.808 21.341 132.456 ;
     RECT  21.125 79.968 21.413 118.68 ;
     RECT  21.341 128.256 21.413 132.408 ;
     RECT  21.413 128.256 21.521 131.88 ;
     RECT  21.521 128.64 21.773 131.88 ;
     RECT  18.904 70.512 21.836 70.536 ;
     RECT  21.836 70.512 21.923 70.68 ;
     RECT  18.904 73.488 21.923 73.8 ;
     RECT  21.773 128.64 21.953 131.832 ;
     RECT  21.953 131.52 21.989 131.832 ;
     RECT  21.989 131.52 22.019 131.64 ;
     RECT  21.341 119.808 22.097 127.272 ;
     RECT  22.097 122.448 22.115 127.272 ;
     RECT  21.953 128.64 22.133 130.344 ;
     RECT  22.019 131.616 22.133 131.64 ;
     RECT  22.133 128.64 22.169 129.96 ;
     RECT  22.169 129.648 22.204 129.96 ;
     RECT  21.923 70.512 22.241 70.536 ;
     RECT  22.097 119.808 22.249 121.416 ;
     RECT  21.413 79.968 22.259 118.392 ;
     RECT  22.249 119.808 22.268 119.832 ;
     RECT  22.268 119.52 22.277 119.832 ;
     RECT  22.115 124.56 22.277 127.272 ;
     RECT  22.277 119.52 22.355 119.544 ;
     RECT  22.204 129.648 22.355 129.672 ;
     RECT  22.277 125.376 22.673 127.272 ;
     RECT  22.259 85.392 22.781 118.392 ;
     RECT  22.781 108.912 22.844 118.392 ;
     RECT  22.259 79.968 22.853 84.216 ;
     RECT  22.844 108.912 22.853 119.352 ;
     RECT  22.673 125.952 22.883 127.272 ;
     RECT  22.781 85.392 22.925 107.928 ;
     RECT  22.853 110.448 22.931 119.352 ;
     RECT  21.305 133.632 22.931 134.856 ;
     RECT  22.853 80.064 23.027 84.216 ;
     RECT  22.925 85.392 23.027 85.512 ;
     RECT  22.931 134.832 23.509 134.856 ;
     RECT  21.923 73.776 24.008 73.8 ;
     RECT  21.089 78.912 24.008 78.984 ;
     RECT  23.027 80.064 24.008 83.496 ;
     RECT  23.027 85.488 24.008 85.512 ;
     RECT  22.925 86.496 24.008 107.784 ;
     RECT  22.853 108.912 24.008 108.984 ;
     RECT  22.931 110.448 24.008 118.392 ;
     RECT  22.249 121.296 24.008 121.416 ;
     RECT  22.115 122.448 24.008 123 ;
     RECT  22.883 125.952 24.008 126.456 ;
     RECT  22.169 128.64 24.008 128.664 ;
     RECT  22.931 133.632 24.008 133.656 ;
     RECT  23.509 134.832 24.008 135.192 ;
     RECT  18.965 136.416 24.008 136.44 ;
     RECT  21.829 142.368 24.008 142.392 ;
     RECT  18.904 153.456 24.008 154.248 ;
     RECT  20.773 155.568 24.008 155.592 ;
     RECT  24.008 2.148 24.112 244.092 ;
     RECT  24.112 2.418 24.304 243.822 ;
     RECT  24.304 82.416 24.419 82.968 ;
     RECT  24.304 99.408 24.419 101.352 ;
     RECT  24.419 82.944 24.545 82.968 ;
     RECT  24.304 78.912 24.563 78.984 ;
     RECT  24.304 116.496 24.563 117.816 ;
     RECT  24.419 99.408 24.581 100.824 ;
     RECT  24.304 80.064 24.611 80.088 ;
     RECT  24.563 116.496 24.611 116.52 ;
     RECT  24.563 78.96 24.659 78.984 ;
     RECT  24.304 91.584 24.689 96.456 ;
     RECT  24.304 119.136 24.877 119.16 ;
     RECT  24.304 122.448 24.905 123 ;
     RECT  24.304 103.728 24.977 104.088 ;
     RECT  24.304 81.12 25.139 81.432 ;
     RECT  24.304 86.496 25.193 87.048 ;
     RECT  25.139 81.408 25.265 81.432 ;
     RECT  24.563 117.792 25.265 117.816 ;
     RECT  24.905 122.544 25.265 123 ;
     RECT  24.304 88.08 25.477 88.104 ;
     RECT  24.304 89.184 25.477 90.408 ;
     RECT  25.477 88.08 25.561 90.408 ;
     RECT  24.304 85.488 25.697 85.512 ;
     RECT  24.304 110.592 25.697 111.336 ;
     RECT  25.621 124.224 25.705 124.248 ;
     RECT  24.304 134.832 25.877 135.336 ;
     RECT  24.304 113.568 25.949 114.888 ;
     RECT  24.304 121.296 25.985 121.32 ;
     RECT  24.304 142.368 26.101 142.392 ;
     RECT  26.089 118.512 26.173 118.536 ;
     RECT  25.333 152.208 26.197 152.232 ;
     RECT  24.304 153.456 26.197 154.248 ;
     RECT  25.265 122.976 26.233 123 ;
     RECT  26.233 122.976 26.305 123.672 ;
     RECT  26.305 122.496 26.317 123.672 ;
     RECT  26.317 122.496 26.389 123 ;
     RECT  26.245 151.056 26.561 151.08 ;
     RECT  26.197 152.208 26.561 154.248 ;
     RECT  24.304 97.776 26.741 98.088 ;
     RECT  24.977 103.728 26.773 103.752 ;
     RECT  26.773 103.728 26.813 103.848 ;
     RECT  25.949 113.568 27.385 114.312 ;
     RECT  26.389 122.976 27.641 123 ;
     RECT  24.581 99.408 28.289 100.008 ;
     RECT  25.877 135.312 29.221 135.336 ;
     RECT  24.304 136.416 29.221 136.44 ;
     RECT  25.193 86.496 29.408 86.52 ;
     RECT  25.561 88.08 29.408 88.104 ;
     RECT  25.561 89.184 29.408 90.408 ;
     RECT  24.689 91.584 29.408 91.608 ;
     RECT  24.689 92.784 29.408 96.456 ;
     RECT  26.741 97.776 29.408 97.8 ;
     RECT  28.289 99.984 29.408 100.008 ;
     RECT  26.813 103.824 29.408 103.848 ;
     RECT  24.304 105.072 29.408 106.488 ;
     RECT  24.304 108.96 29.408 108.984 ;
     RECT  25.697 111.312 29.408 111.336 ;
     RECT  27.385 113.568 29.408 114.84 ;
     RECT  24.304 126.288 29.408 126.456 ;
     RECT  29.221 135.312 29.408 136.44 ;
     RECT  26.101 142.368 29.408 142.92 ;
     RECT  27.637 151.536 29.408 151.56 ;
     RECT  26.561 152.592 29.408 154.248 ;
     RECT  24.304 155.568 29.408 155.592 ;
     RECT  29.408 2.148 29.512 244.092 ;
     RECT  29.512 2.418 29.704 243.822 ;
     RECT  29.704 135.648 29.843 136.44 ;
     RECT  29.704 103.824 30.305 103.848 ;
     RECT  29.704 113.568 30.341 113.592 ;
     RECT  29.704 126.288 30.485 126.456 ;
     RECT  29.704 114.816 30.733 114.84 ;
     RECT  29.704 152.592 30.773 154.248 ;
     RECT  29.704 111.312 31.385 111.336 ;
     RECT  29.704 142.368 33.437 142.92 ;
     RECT  33.437 142.368 34.513 142.392 ;
     RECT  29.704 86.496 34.808 86.52 ;
     RECT  29.704 88.08 34.808 88.104 ;
     RECT  29.704 89.184 34.808 90.408 ;
     RECT  29.704 91.584 34.808 91.608 ;
     RECT  29.704 92.784 34.808 96.456 ;
     RECT  29.704 97.776 34.808 97.8 ;
     RECT  29.704 99.408 34.808 100.008 ;
     RECT  29.704 105.072 34.808 105.384 ;
     RECT  29.704 106.464 34.808 106.488 ;
     RECT  29.704 108.96 34.808 108.984 ;
     RECT  30.733 114.528 34.808 114.84 ;
     RECT  30.485 126.288 34.808 126.312 ;
     RECT  29.843 136.416 34.808 136.44 ;
     RECT  34.513 142.368 34.808 142.92 ;
     RECT  29.704 151.536 34.808 151.56 ;
     RECT  30.773 152.592 34.808 152.664 ;
     RECT  30.773 154.08 34.808 154.248 ;
     RECT  29.704 155.568 34.808 155.592 ;
     RECT  34.808 2.148 34.912 244.092 ;
     RECT  34.912 2.418 35.104 243.822 ;
     RECT  35.104 108.96 35.633 108.984 ;
     RECT  35.104 86.496 36.353 86.52 ;
     RECT  35.104 92.784 37.001 96.216 ;
     RECT  35.104 97.776 37.469 97.8 ;
     RECT  37.001 93.456 37.649 96.216 ;
     RECT  35.104 106.464 38.225 106.488 ;
     RECT  35.104 91.584 38.401 91.608 ;
     RECT  38.401 91.584 38.765 91.704 ;
     RECT  35.104 155.568 40.093 155.592 ;
     RECT  35.104 88.08 40.208 88.104 ;
     RECT  35.104 89.184 40.208 90.408 ;
     RECT  38.765 91.68 40.208 91.704 ;
     RECT  37.649 93.456 40.208 93.48 ;
     RECT  37.649 95.232 40.208 96.216 ;
     RECT  35.104 99.408 40.208 100.008 ;
     RECT  35.104 105.072 40.208 105.384 ;
     RECT  35.104 114.528 40.208 114.84 ;
     RECT  35.104 126.288 40.208 126.312 ;
     RECT  35.104 136.416 40.208 136.44 ;
     RECT  35.104 142.368 40.208 142.92 ;
     RECT  35.104 151.536 40.208 151.56 ;
     RECT  35.104 152.592 40.208 152.664 ;
     RECT  35.104 154.08 40.208 154.248 ;
     RECT  40.093 155.376 40.208 155.592 ;
     RECT  40.208 2.148 40.312 244.092 ;
     RECT  40.312 2.418 40.504 243.822 ;
     RECT  40.504 88.08 40.925 88.104 ;
     RECT  40.504 89.184 42.757 90.408 ;
     RECT  42.757 89.184 45.608 90.552 ;
     RECT  40.504 91.68 45.608 91.704 ;
     RECT  40.504 93.456 45.608 93.48 ;
     RECT  40.504 95.232 45.608 96.216 ;
     RECT  40.504 99.408 45.608 100.008 ;
     RECT  40.504 105.072 45.608 105.384 ;
     RECT  40.504 114.528 45.608 114.84 ;
     RECT  40.504 126.288 45.608 126.312 ;
     RECT  40.504 136.416 45.608 136.44 ;
     RECT  40.504 142.368 45.608 142.92 ;
     RECT  40.504 151.536 45.608 151.56 ;
     RECT  40.504 152.592 45.608 152.664 ;
     RECT  40.504 154.08 45.608 154.248 ;
     RECT  40.504 155.376 45.608 155.4 ;
     RECT  45.608 2.148 45.712 244.092 ;
     RECT  45.712 2.418 45.904 243.822 ;
     RECT  45.904 89.184 46.433 90.552 ;
     RECT  45.904 114.528 48.125 114.84 ;
     RECT  48.125 114.528 49.201 114.552 ;
     RECT  49.201 114.528 49.285 115.128 ;
     RECT  46.433 89.184 51.008 89.976 ;
     RECT  45.904 91.68 51.008 91.704 ;
     RECT  45.904 93.456 51.008 93.48 ;
     RECT  45.904 95.232 51.008 96.216 ;
     RECT  45.904 99.408 51.008 100.008 ;
     RECT  45.904 105.072 51.008 105.384 ;
     RECT  49.285 114.528 51.008 114.552 ;
     RECT  45.904 126.288 51.008 126.312 ;
     RECT  45.904 136.416 51.008 136.44 ;
     RECT  45.904 142.368 51.008 142.92 ;
     RECT  49.237 146.688 51.008 146.712 ;
     RECT  45.904 151.536 51.008 151.56 ;
     RECT  45.904 152.592 51.008 152.664 ;
     RECT  45.904 154.08 51.008 154.248 ;
     RECT  45.904 155.376 51.008 155.4 ;
     RECT  51.008 2.148 51.112 244.092 ;
     RECT  51.112 2.418 51.304 243.822 ;
     RECT  51.304 114.528 51.661 114.552 ;
     RECT  51.304 91.68 52.333 91.752 ;
     RECT  51.304 113.424 52.345 113.544 ;
     RECT  52.333 91.632 52.373 91.752 ;
     RECT  51.304 154.08 53.561 154.248 ;
     RECT  53.593 133.968 53.677 133.992 ;
     RECT  53.605 123.072 53.797 123.096 ;
     RECT  52.345 113.52 53.843 113.544 ;
     RECT  53.797 122.976 53.843 123.096 ;
     RECT  53.561 154.224 53.989 154.248 ;
     RECT  55.141 134.496 55.225 134.52 ;
     RECT  51.304 89.184 56.408 89.976 ;
     RECT  52.373 91.632 56.408 91.656 ;
     RECT  51.304 93.456 56.408 93.48 ;
     RECT  51.304 95.232 56.408 96.216 ;
     RECT  51.304 99.408 56.408 100.008 ;
     RECT  51.304 105.072 56.408 105.384 ;
     RECT  53.843 122.976 56.408 123 ;
     RECT  51.304 126.288 56.408 126.312 ;
     RECT  51.304 136.416 56.408 136.44 ;
     RECT  51.304 142.368 56.408 142.92 ;
     RECT  51.304 146.688 56.408 146.712 ;
     RECT  51.304 150.192 56.408 150.216 ;
     RECT  51.304 151.536 56.408 151.56 ;
     RECT  51.304 152.592 56.408 152.664 ;
     RECT  53.989 154.224 56.408 154.296 ;
     RECT  51.304 155.376 56.408 155.4 ;
     RECT  56.408 2.148 56.512 244.092 ;
     RECT  56.512 2.418 56.704 243.822 ;
     RECT  56.704 105.072 58.745 105.384 ;
     RECT  56.704 89.184 61.808 89.976 ;
     RECT  56.704 91.632 61.808 91.656 ;
     RECT  56.704 93.456 61.808 93.48 ;
     RECT  56.704 95.232 61.808 96.216 ;
     RECT  56.704 99.408 61.808 100.008 ;
     RECT  58.745 105.168 61.808 105.384 ;
     RECT  56.704 122.976 61.808 123 ;
     RECT  56.704 126.288 61.808 126.312 ;
     RECT  56.704 136.416 61.808 136.44 ;
     RECT  56.704 142.368 61.808 142.92 ;
     RECT  56.704 146.688 61.808 146.712 ;
     RECT  56.704 150.192 61.808 150.216 ;
     RECT  56.704 151.536 61.808 151.56 ;
     RECT  56.704 152.592 61.808 152.664 ;
     RECT  56.704 154.224 61.808 154.296 ;
     RECT  56.704 155.376 61.808 155.4 ;
     RECT  61.808 2.148 61.912 244.092 ;
     RECT  61.912 2.418 62.104 243.822 ;
     RECT  62.104 91.632 65.441 91.656 ;
     RECT  65.717 91.728 65.801 91.752 ;
     RECT  62.104 89.184 67.208 89.976 ;
     RECT  62.104 93.456 67.208 93.48 ;
     RECT  62.104 95.232 67.208 96.216 ;
     RECT  62.104 99.408 67.208 100.008 ;
     RECT  62.104 104.928 67.208 105.384 ;
     RECT  62.104 122.976 67.208 123 ;
     RECT  62.104 126.288 67.208 126.312 ;
     RECT  62.104 136.416 67.208 136.44 ;
     RECT  62.104 142.368 67.208 142.92 ;
     RECT  62.104 146.688 67.208 146.712 ;
     RECT  62.104 150.192 67.208 150.216 ;
     RECT  62.104 151.536 67.208 151.56 ;
     RECT  62.104 152.592 67.208 152.664 ;
     RECT  62.104 154.224 67.208 154.296 ;
     RECT  62.104 155.376 67.208 155.4 ;
     RECT  67.208 2.148 67.312 244.092 ;
     RECT  67.312 2.418 67.504 243.822 ;
     RECT  67.504 104.928 67.601 105.384 ;
     RECT  67.504 154.224 68.641 154.296 ;
     RECT  67.504 89.184 70.157 89.208 ;
     RECT  67.504 93.456 72.608 93.48 ;
     RECT  67.504 96.192 72.608 96.216 ;
     RECT  67.504 99.408 72.608 100.008 ;
     RECT  67.601 105.072 72.608 105.384 ;
     RECT  67.504 122.976 72.608 123 ;
     RECT  67.504 126.288 72.608 126.312 ;
     RECT  67.504 136.416 72.608 136.44 ;
     RECT  67.504 142.368 72.608 142.92 ;
     RECT  67.504 146.688 72.608 146.712 ;
     RECT  67.504 150.192 72.608 150.216 ;
     RECT  67.504 151.536 72.608 151.56 ;
     RECT  67.504 152.592 72.608 152.664 ;
     RECT  68.641 154.224 72.608 154.776 ;
     RECT  72.608 2.148 72.712 244.092 ;
     RECT  72.712 2.418 72.904 243.822 ;
     RECT  72.904 122.976 74.653 123 ;
     RECT  74.653 122.88 74.693 123 ;
     RECT  72.904 154.224 76.813 154.776 ;
     RECT  76.813 154.224 76.853 154.872 ;
     RECT  76.853 154.272 77.132 154.872 ;
     RECT  74.693 122.88 77.468 122.904 ;
     RECT  77.845 243.36 77.893 243.384 ;
     RECT  77.845 246.096 77.987 246.12 ;
     RECT  72.904 93.456 78.008 93.48 ;
     RECT  72.904 96.192 78.008 96.216 ;
     RECT  72.904 99.408 78.008 100.008 ;
     RECT  72.904 105.072 78.008 105.384 ;
     RECT  77.468 122.88 78.008 123 ;
     RECT  72.904 126.288 78.008 126.312 ;
     RECT  72.904 136.416 78.008 136.44 ;
     RECT  72.904 142.368 78.008 142.92 ;
     RECT  72.904 146.688 78.008 146.712 ;
     RECT  72.904 150.192 78.008 150.216 ;
     RECT  72.904 151.536 78.008 151.56 ;
     RECT  72.904 152.592 78.008 152.664 ;
     RECT  77.132 154.272 78.008 154.968 ;
     RECT  77.173 218.304 78.008 218.328 ;
     RECT  77.893 239.856 78.008 239.88 ;
     RECT  77.893 242.832 78.008 243.384 ;
     RECT  78.008 2.148 78.112 244.092 ;
     RECT  78.112 2.418 78.304 243.822 ;
     RECT  78.304 154.272 78.653 154.872 ;
     RECT  78.304 93.456 83.408 93.48 ;
     RECT  78.304 96.192 83.408 96.216 ;
     RECT  78.304 99.408 83.408 100.008 ;
     RECT  78.304 105.072 83.408 105.384 ;
     RECT  78.304 126.288 83.408 126.312 ;
     RECT  78.304 136.416 83.408 136.44 ;
     RECT  78.304 142.368 83.408 142.92 ;
     RECT  78.304 146.688 83.408 146.712 ;
     RECT  78.304 150.192 83.408 150.216 ;
     RECT  78.304 151.536 83.408 151.56 ;
     RECT  78.304 152.592 83.408 153.192 ;
     RECT  78.653 154.272 83.408 154.776 ;
     RECT  83.408 2.148 83.512 244.092 ;
     RECT  83.512 2.418 83.704 243.822 ;
     RECT  83.704 93.456 88.808 93.48 ;
     RECT  83.704 96.192 88.808 96.216 ;
     RECT  83.704 99.408 88.808 100.008 ;
     RECT  83.704 105.072 88.808 105.384 ;
     RECT  83.704 126.288 88.808 126.312 ;
     RECT  83.704 136.416 88.808 136.44 ;
     RECT  83.704 142.368 88.808 142.92 ;
     RECT  83.704 146.688 88.808 146.712 ;
     RECT  83.704 150.192 88.808 150.216 ;
     RECT  83.704 151.536 88.808 151.56 ;
     RECT  83.704 152.592 88.808 153.192 ;
     RECT  83.704 154.272 88.808 154.776 ;
     RECT  88.808 2.148 88.912 244.092 ;
     RECT  88.912 2.418 89.104 243.822 ;
     RECT  89.104 105.36 91.249 105.384 ;
     RECT  89.104 93.456 94.208 93.48 ;
     RECT  89.104 96.192 94.208 96.216 ;
     RECT  89.104 99.408 94.208 100.008 ;
     RECT  91.249 105.168 94.208 105.384 ;
     RECT  89.104 126.288 94.208 126.312 ;
     RECT  89.104 136.416 94.208 136.44 ;
     RECT  89.104 142.368 94.208 142.92 ;
     RECT  89.104 146.688 94.208 146.712 ;
     RECT  89.104 150.192 94.208 150.216 ;
     RECT  89.104 151.536 94.208 151.56 ;
     RECT  89.104 152.592 94.208 153.192 ;
     RECT  89.104 154.272 94.208 154.776 ;
     RECT  94.208 2.148 94.312 244.092 ;
     RECT  94.312 2.418 94.504 243.822 ;
     RECT  94.504 152.592 95.897 153.192 ;
     RECT  95.897 152.592 96.973 152.664 ;
     RECT  94.504 93.456 99.608 93.48 ;
     RECT  94.504 96.192 99.608 96.216 ;
     RECT  94.504 99.408 99.608 100.008 ;
     RECT  94.504 105.072 99.608 105.384 ;
     RECT  94.504 126.288 99.608 126.312 ;
     RECT  94.504 136.416 99.608 136.44 ;
     RECT  94.504 142.368 99.608 142.92 ;
     RECT  94.504 146.688 99.608 146.712 ;
     RECT  94.504 150.192 99.608 150.216 ;
     RECT  94.504 151.536 99.608 151.56 ;
     RECT  96.973 152.592 99.608 153.192 ;
     RECT  94.504 154.272 99.608 154.776 ;
     RECT  99.608 2.148 99.712 244.092 ;
     RECT  99.712 2.418 99.904 243.822 ;
     RECT  99.904 154.272 103.853 154.776 ;
     RECT  99.904 93.456 105.008 93.48 ;
     RECT  99.904 96.192 105.008 96.216 ;
     RECT  99.904 99.408 105.008 100.008 ;
     RECT  99.904 105.072 105.008 105.384 ;
     RECT  99.904 126.288 105.008 126.312 ;
     RECT  99.904 136.416 105.008 136.44 ;
     RECT  99.904 142.368 105.008 142.92 ;
     RECT  99.904 146.688 105.008 146.712 ;
     RECT  99.904 150.192 105.008 150.216 ;
     RECT  99.904 151.536 105.008 151.56 ;
     RECT  99.904 152.592 105.008 153.192 ;
     RECT  103.853 154.272 105.008 154.296 ;
     RECT  105.008 2.148 105.112 244.092 ;
     RECT  105.112 2.418 105.304 243.822 ;
     RECT  105.304 93.456 110.408 93.48 ;
     RECT  105.304 96.192 110.408 96.216 ;
     RECT  105.304 99.408 110.408 100.008 ;
     RECT  105.304 105.072 110.408 105.384 ;
     RECT  105.304 126.288 110.408 126.312 ;
     RECT  105.304 136.416 110.408 136.44 ;
     RECT  105.304 142.368 110.408 142.92 ;
     RECT  105.304 146.688 110.408 146.712 ;
     RECT  105.304 150.192 110.408 150.216 ;
     RECT  105.304 151.536 110.408 151.56 ;
     RECT  105.304 152.592 110.408 153.192 ;
     RECT  105.304 154.272 110.408 154.536 ;
     RECT  110.408 2.148 110.512 244.092 ;
     RECT  110.512 2.418 110.704 243.822 ;
     RECT  110.704 93.456 115.808 93.48 ;
     RECT  110.704 96.192 115.808 96.216 ;
     RECT  110.704 99.408 115.808 100.008 ;
     RECT  110.704 105.072 115.808 105.384 ;
     RECT  110.704 126.288 115.808 126.312 ;
     RECT  110.704 136.416 115.808 136.44 ;
     RECT  110.704 142.368 115.808 142.92 ;
     RECT  110.704 146.688 115.808 146.712 ;
     RECT  110.704 150.192 115.808 150.216 ;
     RECT  110.704 151.536 115.808 151.56 ;
     RECT  110.704 152.592 115.808 153.192 ;
     RECT  110.704 154.272 115.808 154.536 ;
     RECT  115.808 2.148 115.912 244.092 ;
     RECT  115.912 2.418 116.104 243.822 ;
     RECT  116.104 93.456 121.208 93.48 ;
     RECT  116.104 96.192 121.208 96.216 ;
     RECT  116.104 99.408 121.208 100.008 ;
     RECT  116.104 105.072 121.208 105.384 ;
     RECT  116.104 126.288 121.208 126.312 ;
     RECT  116.104 136.416 121.208 136.44 ;
     RECT  116.104 142.368 121.208 142.92 ;
     RECT  116.104 146.688 121.208 146.712 ;
     RECT  116.104 150.192 121.208 150.216 ;
     RECT  116.104 151.536 121.208 151.56 ;
     RECT  116.104 152.592 121.208 153.192 ;
     RECT  116.104 154.272 121.208 154.536 ;
     RECT  121.208 2.148 121.312 244.092 ;
     RECT  121.312 2.418 121.504 243.822 ;
     RECT  121.504 93.456 126.608 93.48 ;
     RECT  121.504 96.192 126.608 96.216 ;
     RECT  121.504 99.408 126.608 100.008 ;
     RECT  121.504 105.072 126.608 105.384 ;
     RECT  121.504 126.288 126.608 126.312 ;
     RECT  121.504 136.416 126.608 136.44 ;
     RECT  121.504 142.368 126.608 142.92 ;
     RECT  121.504 146.688 126.608 146.712 ;
     RECT  121.504 150.192 126.608 150.216 ;
     RECT  121.504 151.536 126.608 151.56 ;
     RECT  121.504 152.592 126.608 153.192 ;
     RECT  121.504 154.272 126.608 154.536 ;
     RECT  126.608 2.148 126.712 244.092 ;
     RECT  126.712 2.418 126.904 243.822 ;
     RECT  126.904 93.456 132.008 93.48 ;
     RECT  126.904 96.192 132.008 96.216 ;
     RECT  126.904 99.408 132.008 100.008 ;
     RECT  126.904 105.072 132.008 105.384 ;
     RECT  126.904 126.288 132.008 126.312 ;
     RECT  126.904 136.416 132.008 136.44 ;
     RECT  126.904 142.368 132.008 142.92 ;
     RECT  126.904 146.688 132.008 146.712 ;
     RECT  126.904 150.192 132.008 150.216 ;
     RECT  126.904 151.536 132.008 151.56 ;
     RECT  126.904 152.592 132.008 153.192 ;
     RECT  126.904 154.272 132.008 154.536 ;
     RECT  132.008 2.148 132.112 244.092 ;
     RECT  132.112 2.418 132.304 243.822 ;
     RECT  132.304 93.456 137.408 93.48 ;
     RECT  132.304 96.192 137.408 96.216 ;
     RECT  132.304 99.408 137.408 100.008 ;
     RECT  132.304 105.072 137.408 105.384 ;
     RECT  132.304 126.288 137.408 126.312 ;
     RECT  132.304 136.416 137.408 136.44 ;
     RECT  132.304 142.368 137.408 142.92 ;
     RECT  132.304 146.688 137.408 146.712 ;
     RECT  132.304 150.192 137.408 150.216 ;
     RECT  132.304 151.536 137.408 151.56 ;
     RECT  132.304 152.592 137.408 153.192 ;
     RECT  132.304 154.272 137.408 154.536 ;
     RECT  137.408 2.148 137.512 244.092 ;
     RECT  137.512 2.418 137.704 243.822 ;
     RECT  137.704 93.456 142.513 93.48 ;
     RECT  142.513 93.312 142.808 93.48 ;
     RECT  137.704 96.192 142.808 96.216 ;
     RECT  137.704 99.408 142.808 100.008 ;
     RECT  137.704 105.072 142.808 105.384 ;
     RECT  137.704 126.288 142.808 126.312 ;
     RECT  137.704 136.416 142.808 136.44 ;
     RECT  137.704 142.368 142.808 142.92 ;
     RECT  137.704 146.688 142.808 146.712 ;
     RECT  137.704 150.192 142.808 150.216 ;
     RECT  137.704 151.536 142.808 151.56 ;
     RECT  137.704 152.592 142.808 153.192 ;
     RECT  137.704 154.272 142.808 154.536 ;
     RECT  142.808 2.148 142.912 244.092 ;
     RECT  142.912 2.418 143.104 243.822 ;
     RECT  143.104 93.312 145.577 93.336 ;
     RECT  143.104 99.408 146.041 100.008 ;
     RECT  143.104 126.288 146.329 126.312 ;
     RECT  146.329 126.144 146.473 126.312 ;
     RECT  143.104 151.536 146.473 151.56 ;
     RECT  143.104 152.592 146.473 153.192 ;
     RECT  143.104 105.072 146.513 105.384 ;
     RECT  146.485 117.936 146.585 119.4 ;
     RECT  146.533 95.184 146.621 95.208 ;
     RECT  146.585 117.936 146.621 118.728 ;
     RECT  146.473 151.536 146.917 153.192 ;
     RECT  143.104 154.272 146.917 154.536 ;
     RECT  146.917 151.536 147.089 154.536 ;
     RECT  143.104 96.192 147.337 96.216 ;
     RECT  143.104 146.688 147.337 146.712 ;
     RECT  143.104 150.192 147.337 150.216 ;
     RECT  145.933 93.84 147.349 94.056 ;
     RECT  146.257 109.008 147.349 109.032 ;
     RECT  147.301 137.904 147.349 137.928 ;
     RECT  147.308 139.92 147.349 139.944 ;
     RECT  147.337 133.296 147.445 133.32 ;
     RECT  146.485 120.48 147.517 120.504 ;
     RECT  146.473 126.144 147.517 126.456 ;
     RECT  146.513 105.168 147.596 105.384 ;
     RECT  147.517 126.144 147.596 127.224 ;
     RECT  146.041 98.88 147.769 100.008 ;
     RECT  147.445 133.008 147.836 133.32 ;
     RECT  146.581 134.544 147.836 134.568 ;
     RECT  146.869 103.68 147.877 103.704 ;
     RECT  147.637 122.112 148.057 122.568 ;
     RECT  147.349 93.84 148.208 94.68 ;
     RECT  147.337 96.192 148.208 96.744 ;
     RECT  147.769 98.592 148.208 100.008 ;
     RECT  147.589 101.424 148.208 101.448 ;
     RECT  147.877 102.576 148.208 103.704 ;
     RECT  147.596 104.784 148.208 105.384 ;
     RECT  147.349 107.136 148.208 107.16 ;
     RECT  147.349 108.192 148.208 109.032 ;
     RECT  147.308 110.544 148.208 110.568 ;
     RECT  147.337 112.32 148.208 112.344 ;
     RECT  148.093 113.856 148.208 113.88 ;
     RECT  147.769 115.68 148.208 115.704 ;
     RECT  146.621 118.704 148.208 118.728 ;
     RECT  147.517 120.48 148.208 120.984 ;
     RECT  148.057 122.112 148.208 123.048 ;
     RECT  147.596 126.144 148.208 127.752 ;
     RECT  146.365 131.04 148.208 131.064 ;
     RECT  147.836 133.008 148.208 134.568 ;
     RECT  143.104 136.416 148.208 136.44 ;
     RECT  147.349 137.904 148.208 138.168 ;
     RECT  147.349 139.68 148.208 139.944 ;
     RECT  147.409 141.36 148.208 141.384 ;
     RECT  143.104 142.368 148.208 142.92 ;
     RECT  147.013 144.912 148.208 144.936 ;
     RECT  147.337 146.688 148.208 147 ;
     RECT  148.021 148.656 148.208 148.68 ;
     RECT  147.337 150.192 148.208 150.312 ;
     RECT  147.089 151.536 148.208 152.472 ;
     RECT  147.089 153.552 148.208 154.536 ;
     RECT  148.208 2.148 148.312 244.092 ;
     RECT  148.312 2.418 148.504 243.822 ;
     RECT  148.504 139.68 148.637 139.704 ;
     RECT  148.504 105.168 148.643 106.584 ;
     RECT  148.643 105.408 148.717 106.584 ;
     RECT  148.504 122.112 148.745 123.864 ;
     RECT  148.717 105.408 148.781 105.432 ;
     RECT  148.504 125.424 148.787 125.448 ;
     RECT  148.504 107.76 148.817 108.216 ;
     RECT  148.745 123.312 148.828 123.864 ;
     RECT  148.504 146.976 148.835 147.096 ;
     RECT  148.504 148.176 148.835 148.68 ;
     RECT  148.504 101.424 148.997 101.448 ;
     RECT  148.504 115.104 149.075 115.704 ;
     RECT  148.828 123.312 149.075 123.672 ;
     RECT  148.504 98.88 149.105 99.528 ;
     RECT  148.504 141.36 149.177 143.88 ;
     RECT  148.504 144.912 149.213 144.936 ;
     RECT  149.177 141.504 149.219 143.88 ;
     RECT  148.504 92.88 149.267 97.176 ;
     RECT  148.504 151.536 149.315 154.536 ;
     RECT  148.835 148.176 149.321 148.2 ;
     RECT  148.745 122.112 149.357 122.136 ;
     RECT  148.504 149.76 149.357 150.312 ;
     RECT  148.504 118.464 149.363 118.488 ;
     RECT  149.357 149.76 149.376 150.072 ;
     RECT  148.504 129.36 149.393 129.384 ;
     RECT  148.504 130.512 149.393 130.776 ;
     RECT  149.267 95.712 149.465 97.176 ;
     RECT  148.504 119.664 149.501 120.168 ;
     RECT  148.717 106.56 149.557 106.584 ;
     RECT  148.817 107.76 149.557 107.784 ;
     RECT  149.557 106.56 149.603 107.784 ;
     RECT  148.504 126.432 149.677 126.456 ;
     RECT  148.504 113.424 149.681 114.024 ;
     RECT  149.075 123.312 149.753 123.336 ;
     RECT  148.504 110.208 149.785 110.232 ;
     RECT  149.603 107.136 149.843 107.784 ;
     RECT  148.504 136.176 149.855 136.2 ;
     RECT  149.843 107.136 149.884 107.256 ;
     RECT  149.785 109.968 149.891 110.232 ;
     RECT  149.713 111.408 149.891 111.72 ;
     RECT  149.891 111.696 149.893 111.72 ;
     RECT  149.681 113.424 149.893 113.448 ;
     RECT  149.315 151.536 149.893 154.344 ;
     RECT  148.504 103.056 149.933 103.08 ;
     RECT  149.219 141.648 149.933 143.88 ;
     RECT  149.893 151.44 149.933 154.344 ;
     RECT  149.855 135.552 149.939 136.2 ;
     RECT  149.933 141.648 149.977 142.536 ;
     RECT  149.267 92.88 150.041 94.344 ;
     RECT  149.105 99.168 150.077 99.528 ;
     RECT  149.893 111.696 150.077 113.448 ;
     RECT  149.933 151.44 150.077 153.048 ;
     RECT  149.501 119.664 150.113 119.688 ;
     RECT  148.504 132.864 150.133 133.32 ;
     RECT  149.939 135.552 150.133 135.576 ;
     RECT  150.133 132.864 150.179 133.992 ;
     RECT  150.133 135.024 150.179 135.576 ;
     RECT  150.041 92.88 150.181 94.104 ;
     RECT  150.077 99.168 150.185 99.192 ;
     RECT  150.179 133.968 150.22 133.992 ;
     RECT  149.465 97.152 150.284 97.176 ;
     RECT  150.181 92.448 150.293 94.104 ;
     RECT  150.284 97.152 150.371 97.752 ;
     RECT  150.077 151.44 150.467 151.464 ;
     RECT  150.077 152.448 150.467 153.048 ;
     RECT  149.893 139.104 150.469 139.128 ;
     RECT  149.852 137.184 150.473 137.208 ;
     RECT  150.469 138.768 150.515 139.128 ;
     RECT  149.933 154.224 150.545 154.344 ;
     RECT  149.933 143.856 150.617 143.88 ;
     RECT  150.467 152.448 150.617 152.52 ;
     RECT  149.465 95.712 150.725 95.736 ;
     RECT  149.393 130.512 150.725 130.536 ;
     RECT  150.545 154.272 150.725 154.344 ;
     RECT  149.884 107.232 150.761 107.256 ;
     RECT  150.179 135.024 150.761 135.048 ;
     RECT  150.617 152.448 150.761 152.472 ;
     RECT  150.685 131.616 150.769 131.64 ;
     RECT  150.179 132.864 150.796 132.888 ;
     RECT  149.075 115.104 150.805 115.128 ;
     RECT  150.805 115.104 150.851 115.896 ;
     RECT  150.469 123.456 150.851 123.48 ;
     RECT  150.685 124.8 150.851 124.824 ;
     RECT  150.371 97.152 150.869 97.176 ;
     RECT  150.077 111.696 150.869 112.68 ;
     RECT  150.073 121.392 150.869 121.416 ;
     RECT  149.677 126.432 150.869 126.696 ;
     RECT  149.677 145.872 150.869 145.896 ;
     RECT  148.835 147.072 150.869 147.096 ;
     RECT  150.851 115.872 150.892 115.896 ;
     RECT  150.515 138.768 150.905 138.792 ;
     RECT  149.376 150.048 150.905 150.072 ;
     RECT  148.504 117.456 150.912 117.48 ;
     RECT  150.869 111.696 150.977 111.72 ;
     RECT  150.293 92.448 150.997 92.472 ;
     RECT  150.869 126.432 151.013 126.456 ;
     RECT  150.997 91.968 151.043 92.472 ;
     RECT  150.725 154.32 151.121 154.344 ;
     RECT  150.469 140.208 151.229 140.232 ;
     RECT  149.977 141.648 151.229 142.392 ;
     RECT  150.293 94.08 151.373 94.104 ;
     RECT  151.229 142.368 151.373 142.392 ;
     RECT  151.043 91.968 151.445 91.992 ;
     RECT  153.205 135.168 153.421 135.192 ;
     RECT  153.493 98.88 153.601 98.904 ;
     RECT  153.817 153.744 153.853 153.768 ;
     RECT  153.205 92.832 153.889 92.856 ;
     RECT  153.565 105.36 153.889 105.384 ;
     RECT  153.565 129.984 153.889 130.008 ;
     RECT  153.853 146.832 153.889 146.856 ;
     RECT  153.889 105.36 154.393 105.816 ;
     RECT  153.889 146.4 154.393 146.856 ;
     RECT  153.889 148.56 154.393 148.584 ;
     RECT  153.853 152.88 154.393 153.768 ;
     RECT  153.889 92.832 154.429 93.288 ;
     RECT  154.393 94.56 154.429 94.584 ;
     RECT  154.393 96.72 154.429 96.744 ;
     RECT  153.601 98.016 154.429 98.904 ;
     RECT  154.393 104.496 154.429 105.816 ;
     RECT  153.493 110.112 154.429 110.136 ;
     RECT  153.889 111.408 154.429 111.432 ;
     RECT  153.529 113.136 154.429 113.16 ;
     RECT  153.889 114.432 154.429 114.456 ;
     RECT  153.889 117.888 154.429 117.912 ;
     RECT  153.457 119.184 154.429 119.208 ;
     RECT  153.889 121.776 154.429 121.8 ;
     RECT  154.393 123.072 154.429 123.096 ;
     RECT  153.889 127.824 154.429 127.848 ;
     RECT  153.889 129.984 154.429 130.44 ;
     RECT  153.889 131.712 154.429 131.736 ;
     RECT  153.421 134.304 154.429 135.192 ;
     RECT  153.853 136.464 154.429 136.488 ;
     RECT  154.393 139.056 154.429 139.08 ;
     RECT  153.853 140.352 154.429 140.808 ;
     RECT  153.493 143.376 154.429 143.4 ;
     RECT  153.853 144.672 154.429 144.696 ;
     RECT  154.393 146.4 154.429 148.584 ;
     RECT  153.889 150.288 154.429 150.312 ;
     RECT  154.393 152.016 154.429 153.768 ;
     RECT  154.429 91.968 154.465 98.904 ;
     RECT  154.429 100.176 154.465 113.16 ;
     RECT  154.429 114.432 154.465 154.2 ;
     RECT  154.465 91.968 155.484 154.2 ;
    LAYER M5 ;
     RECT  2.4 2.137 2.52 2.151 ;
     RECT  7.8 2.137 7.92 2.151 ;
     RECT  13.2 2.137 13.32 2.151 ;
     RECT  18.6 2.137 18.72 2.151 ;
     RECT  24 2.137 24.12 2.151 ;
     RECT  29.4 2.137 29.52 2.151 ;
     RECT  34.8 2.137 34.92 2.151 ;
     RECT  40.2 2.137 40.32 2.151 ;
     RECT  45.6 2.137 45.72 2.151 ;
     RECT  51 2.137 51.12 2.151 ;
     RECT  56.4 2.137 56.52 2.151 ;
     RECT  61.8 2.137 61.92 2.151 ;
     RECT  67.2 2.137 67.32 2.151 ;
     RECT  72.6 2.137 72.72 2.151 ;
     RECT  78 2.137 78.12 2.151 ;
     RECT  83.4 2.137 83.52 2.151 ;
     RECT  88.8 2.137 88.92 2.151 ;
     RECT  94.2 2.137 94.32 2.151 ;
     RECT  99.6 2.137 99.72 2.151 ;
     RECT  105 2.137 105.12 2.151 ;
     RECT  110.4 2.137 110.52 2.151 ;
     RECT  115.8 2.137 115.92 2.151 ;
     RECT  121.2 2.137 121.32 2.151 ;
     RECT  126.6 2.137 126.72 2.151 ;
     RECT  132 2.137 132.12 2.151 ;
     RECT  137.4 2.137 137.52 2.151 ;
     RECT  142.8 2.137 142.92 2.151 ;
     RECT  148.2 2.137 148.32 2.151 ;
     RECT  2.4 2.151 2.712 6.277 ;
     RECT  7.8 2.151 8.112 7.381 ;
     RECT  2.4 6.277 3.288 9.589 ;
     RECT  4.8 8.293 4.824 9.637 ;
     RECT  4.8 9.637 5.496 10.067 ;
     RECT  2.4 9.589 3.336 10.883 ;
     RECT  6.864 7.381 8.112 11.027 ;
     RECT  7.68 11.027 8.112 11.365 ;
     RECT  5.472 10.067 5.496 11.941 ;
     RECT  7.68 11.365 9.096 12.227 ;
     RECT  4.848 11.941 5.496 12.517 ;
     RECT  2.4 10.883 3.288 13.139 ;
     RECT  1.056 12.757 1.08 14.485 ;
     RECT  2.4 13.139 2.712 14.485 ;
     RECT  4.848 12.517 6.456 17.509 ;
     RECT  4.752 17.509 6.456 18.899 ;
     RECT  7.8 12.227 9.096 19.765 ;
     RECT  4.848 18.899 6.456 22.453 ;
     RECT  4.56 22.453 6.456 23.411 ;
     RECT  4.848 23.411 6.456 26.197 ;
     RECT  4.416 26.197 6.456 27.635 ;
     RECT  4.56 27.635 6.456 29.219 ;
     RECT  4.848 29.219 6.456 36.421 ;
     RECT  4.752 36.421 6.456 37.667 ;
     RECT  4.848 37.667 6.456 39.877 ;
     RECT  3.936 39.877 6.456 41.267 ;
     RECT  3.984 41.267 6.456 42.227 ;
     RECT  1.056 14.485 2.712 43.813 ;
     RECT  4.848 42.227 6.456 44.053 ;
     RECT  4.8 44.053 6.456 44.965 ;
     RECT  1.056 43.813 3.192 45.829 ;
     RECT  4.464 44.965 6.456 45.829 ;
     RECT  1.056 45.829 6.456 49.763 ;
     RECT  1.056 49.763 3.192 50.005 ;
     RECT  0.336 50.005 3.192 50.053 ;
     RECT  0.144 50.053 3.192 50.339 ;
     RECT  0.336 50.339 3.192 51.301 ;
     RECT  4.272 49.763 6.456 51.301 ;
     RECT  0.336 51.301 6.456 52.979 ;
     RECT  0.336 52.979 3.192 54.085 ;
     RECT  4.272 52.979 6.456 54.085 ;
     RECT  0.336 54.085 6.456 56.389 ;
     RECT  0.336 56.389 6.792 64.405 ;
     RECT  7.8 19.765 9.72 64.405 ;
     RECT  13.2 2.151 13.512 69.973 ;
     RECT  0.336 64.405 9.72 70.645 ;
     RECT  0.336 70.645 9.864 72.805 ;
     RECT  24 2.151 24.312 73.765 ;
     RECT  0.336 72.805 9.96 75.781 ;
     RECT  11.04 71.173 11.064 75.781 ;
     RECT  12.432 69.973 13.512 76.501 ;
     RECT  14.496 68.677 14.52 76.501 ;
     RECT  0.336 75.781 11.112 77.941 ;
     RECT  12.432 76.501 14.52 77.941 ;
     RECT  18.6 2.151 18.912 78.613 ;
     RECT  23.376 73.765 24.312 78.901 ;
     RECT  23.376 78.901 24.552 78.949 ;
     RECT  18.6 78.613 19.32 79.717 ;
     RECT  18.6 79.717 19.704 79.813 ;
     RECT  17.328 78.517 17.352 80.245 ;
     RECT  16.464 80.245 17.352 80.293 ;
     RECT  21.888 70.645 21.912 80.341 ;
     RECT  20.976 80.341 21.912 80.629 ;
     RECT  23.376 78.949 24.648 80.629 ;
     RECT  16.368 80.293 17.352 80.725 ;
     RECT  16.08 80.725 17.352 80.869 ;
     RECT  18.336 79.813 19.704 80.869 ;
     RECT  20.976 80.629 24.648 80.965 ;
     RECT  20.784 80.965 24.648 81.109 ;
     RECT  16.08 80.869 19.704 81.445 ;
     RECT  15.792 81.445 19.704 82.021 ;
     RECT  0.336 77.941 14.52 82.501 ;
     RECT  15.6 82.021 19.704 82.501 ;
     RECT  0.336 82.501 19.704 82.645 ;
     RECT  20.784 81.109 25.128 82.645 ;
     RECT  0.336 82.645 25.128 88.885 ;
     RECT  51 2.151 51.312 91.717 ;
     RECT  151.008 91.957 151.032 92.437 ;
     RECT  150.48 92.437 151.032 92.483 ;
     RECT  148.2 2.151 148.512 92.869 ;
     RECT  150.48 92.483 150.504 94.115 ;
     RECT  146.544 93.829 146.568 94.549 ;
     RECT  148.2 92.869 149.256 94.549 ;
     RECT  146.544 94.549 149.256 94.691 ;
     RECT  148.2 94.691 149.256 95.747 ;
     RECT  0.336 88.885 25.512 96.227 ;
     RECT  150.336 97.141 150.36 97.763 ;
     RECT  148.2 95.747 148.632 98.581 ;
     RECT  146.544 94.691 146.568 98.869 ;
     RECT  147.792 98.581 148.632 98.869 ;
     RECT  146.544 98.869 148.632 99.923 ;
     RECT  148.2 99.923 148.632 102.565 ;
     RECT  0.336 96.227 25.368 103.331 ;
     RECT  147.888 102.565 148.632 103.669 ;
     RECT  147.648 103.669 148.632 104.819 ;
     RECT  65.76 91.717 65.784 104.963 ;
     RECT  148.2 104.819 148.632 105.973 ;
     RECT  148.2 105.973 148.68 106.549 ;
     RECT  0.384 103.331 25.368 106.645 ;
     RECT  146.544 99.923 146.568 107.125 ;
     RECT  148.2 106.549 149.592 107.125 ;
     RECT  146.544 107.125 149.832 107.171 ;
     RECT  0.144 106.645 25.368 107.315 ;
     RECT  149.808 107.171 149.832 107.795 ;
     RECT  149.856 109.957 149.88 111.443 ;
     RECT  146.544 107.171 148.68 112.355 ;
     RECT  149.904 111.685 149.928 112.691 ;
     RECT  51 91.717 52.296 113.459 ;
     RECT  148.2 112.355 148.68 114.035 ;
     RECT  51 113.459 51.312 114.517 ;
     RECT  0.384 107.315 25.368 114.611 ;
     RECT  0.384 114.611 25.128 114.707 ;
     RECT  148.2 114.035 148.512 115.093 ;
     RECT  148.2 115.093 149.064 115.715 ;
     RECT  148.2 115.715 148.512 117.445 ;
     RECT  150.816 115.093 150.84 117.491 ;
     RECT  146.544 112.355 146.568 117.925 ;
     RECT  0.384 114.707 24.84 119.171 ;
     RECT  148.2 117.445 149.352 120.179 ;
     RECT  148.2 120.179 148.512 120.469 ;
     RECT  146.496 117.925 146.568 120.515 ;
     RECT  26.112 118.501 26.136 122.485 ;
     RECT  147.648 120.469 148.512 122.579 ;
     RECT  78 2.151 78.312 122.965 ;
     RECT  53.808 113.509 53.832 123.061 ;
     RECT  53.616 123.061 53.832 123.107 ;
     RECT  148.2 122.579 148.512 123.637 ;
     RECT  26.112 122.485 26.376 124.213 ;
     RECT  148.2 123.637 149.064 126.133 ;
     RECT  150.816 123.445 150.84 126.611 ;
     RECT  147.648 126.133 149.064 127.763 ;
     RECT  0.384 119.171 24.312 129.443 ;
     RECT  0.384 129.443 16.008 130.835 ;
     RECT  17.184 129.443 24.312 131.123 ;
     RECT  20.304 131.123 24.312 131.363 ;
     RECT  17.184 131.123 18.912 131.411 ;
     RECT  20.688 131.363 24.312 131.555 ;
     RECT  17.616 131.411 18.912 131.651 ;
     RECT  20.688 131.555 21.192 131.651 ;
     RECT  17.664 131.651 18.912 131.747 ;
     RECT  0.432 130.835 16.008 131.797 ;
     RECT  0.432 131.797 16.104 131.987 ;
     RECT  18.432 131.747 18.912 131.987 ;
     RECT  21.168 131.651 21.192 132.275 ;
     RECT  148.2 127.763 149.064 132.853 ;
     RECT  150.72 131.605 150.744 132.853 ;
     RECT  148.2 132.853 150.744 132.899 ;
     RECT  148.2 132.899 150.168 133.285 ;
     RECT  53.616 123.107 53.64 134.003 ;
     RECT  22.896 131.555 24.312 134.291 ;
     RECT  147.888 133.285 150.168 134.579 ;
     RECT  23.52 134.291 24.312 135.203 ;
     RECT  148.2 134.579 150.168 135.587 ;
     RECT  29.4 2.151 29.712 135.637 ;
     RECT  148.2 135.587 149.928 137.219 ;
     RECT  146.544 120.515 146.568 137.893 ;
     RECT  148.2 137.219 149.208 137.893 ;
     RECT  18.6 131.987 18.912 138.469 ;
     RECT  17.04 139.717 17.064 139.859 ;
     RECT  146.544 137.893 149.208 139.955 ;
     RECT  150.48 138.757 150.504 140.243 ;
     RECT  148.2 139.955 149.208 141.637 ;
     RECT  18.144 138.469 18.912 141.925 ;
     RECT  21.84 133.909 21.864 142.403 ;
     RECT  148.2 141.637 149.928 142.547 ;
     RECT  17.76 141.925 18.912 144.181 ;
     RECT  49.248 115.093 49.272 146.723 ;
     RECT  17.424 144.181 18.912 147.923 ;
     RECT  148.2 142.547 149.208 149.749 ;
     RECT  51 114.517 51.624 150.227 ;
     RECT  17.76 147.923 18.912 150.467 ;
     RECT  25.632 124.213 26.376 152.243 ;
     RECT  146.544 139.955 146.568 152.485 ;
     RECT  146.544 152.485 146.952 153.157 ;
     RECT  146.544 153.157 147.048 153.203 ;
     RECT  146.928 153.203 147.048 153.587 ;
     RECT  29.4 135.637 29.832 154.115 ;
     RECT  150.432 151.429 150.456 154.259 ;
     RECT  147.024 153.587 147.048 154.355 ;
     RECT  77.52 122.965 78.312 154.453 ;
     RECT  148.2 149.749 149.304 154.547 ;
     RECT  55.152 134.485 55.176 155.411 ;
     RECT  0.432 131.987 16.008 162.371 ;
     RECT  11.952 162.371 16.008 162.851 ;
     RECT  0.432 162.371 10.92 162.899 ;
     RECT  12.528 162.851 16.008 164.387 ;
     RECT  12.528 164.387 15.432 164.531 ;
     RECT  12.528 164.531 13.704 168.323 ;
     RECT  12.768 168.323 13.704 168.851 ;
     RECT  20.784 155.557 20.808 173.891 ;
     RECT  15.072 164.531 15.432 175.859 ;
     RECT  0.432 162.899 10.872 185.123 ;
     RECT  0.48 185.123 10.872 199.619 ;
     RECT  15.072 175.859 15.096 199.907 ;
     RECT  0.48 199.619 1.128 201.347 ;
     RECT  0.528 201.347 1.128 201.827 ;
     RECT  2.304 199.619 10.872 206.963 ;
     RECT  2.304 206.963 3.24 212.099 ;
     RECT  4.32 206.963 10.872 212.099 ;
     RECT  0.528 201.827 0.552 213.443 ;
     RECT  2.304 212.099 3.192 213.685 ;
     RECT  4.32 212.099 8.472 213.685 ;
     RECT  2.304 213.685 8.472 213.779 ;
     RECT  2.304 213.779 8.112 214.931 ;
     RECT  12.768 168.851 13.512 216.371 ;
     RECT  77.184 154.453 78.312 218.339 ;
     RECT  4.32 214.931 8.112 220.643 ;
     RECT  4.32 220.643 5.832 221.219 ;
     RECT  4.896 221.219 5.832 222.229 ;
     RECT  4.656 222.229 5.832 222.899 ;
     RECT  2.304 214.931 3.192 224.533 ;
     RECT  4.896 222.899 5.832 224.533 ;
     RECT  2.304 224.533 3.432 226.403 ;
     RECT  4.848 224.533 5.832 226.741 ;
     RECT  2.304 226.403 3.192 227.555 ;
     RECT  4.848 226.741 5.976 229.763 ;
     RECT  4.848 229.763 5.832 232.019 ;
     RECT  7.344 220.643 8.112 232.019 ;
     RECT  2.4 227.555 3.192 232.405 ;
     RECT  2.4 232.405 3.288 233.747 ;
     RECT  2.4 233.747 3.144 233.795 ;
     RECT  4.848 232.019 4.968 234.275 ;
     RECT  9.936 212.099 10.872 235.043 ;
     RECT  4.848 234.275 4.872 235.141 ;
     RECT  4.704 235.141 4.872 235.187 ;
     RECT  6.288 234.805 6.312 235.475 ;
     RECT  4.704 235.187 4.728 236.003 ;
     RECT  10.848 235.043 10.872 236.099 ;
     RECT  2.4 233.795 2.856 239.603 ;
     RECT  2.4 239.603 2.808 239.795 ;
     RECT  6.096 238.789 6.12 239.843 ;
     RECT  2.4 239.795 2.712 244.089 ;
     RECT  7.8 232.019 8.112 244.089 ;
     RECT  13.2 216.371 13.512 244.089 ;
     RECT  18.6 150.467 18.912 244.089 ;
     RECT  24 135.203 24.312 244.089 ;
     RECT  29.4 154.115 29.712 244.089 ;
     RECT  34.8 2.151 35.112 244.089 ;
     RECT  40.2 2.151 40.512 244.089 ;
     RECT  45.6 2.151 45.912 244.089 ;
     RECT  51 150.227 51.312 244.089 ;
     RECT  56.4 2.151 56.712 244.089 ;
     RECT  61.8 2.151 62.112 244.089 ;
     RECT  67.2 2.151 67.512 244.089 ;
     RECT  72.6 2.151 72.912 244.089 ;
     RECT  77.52 218.339 78.312 244.089 ;
     RECT  83.4 2.151 83.712 244.089 ;
     RECT  88.8 2.151 89.112 244.089 ;
     RECT  94.2 2.151 94.512 244.089 ;
     RECT  99.6 2.151 99.912 244.089 ;
     RECT  105 2.151 105.312 244.089 ;
     RECT  110.4 2.151 110.712 244.089 ;
     RECT  115.8 2.151 116.112 244.089 ;
     RECT  121.2 2.151 121.512 244.089 ;
     RECT  126.6 2.151 126.912 244.089 ;
     RECT  132 2.151 132.312 244.089 ;
     RECT  137.4 2.151 137.712 244.089 ;
     RECT  142.8 2.151 143.112 244.089 ;
     RECT  148.2 154.547 148.512 244.089 ;
     RECT  2.4 244.089 2.52 244.103 ;
     RECT  7.8 244.089 7.92 244.103 ;
     RECT  13.2 244.089 13.32 244.103 ;
     RECT  18.6 244.089 18.72 244.103 ;
     RECT  24 244.089 24.12 244.103 ;
     RECT  29.4 244.089 29.52 244.103 ;
     RECT  34.8 244.089 34.92 244.103 ;
     RECT  40.2 244.089 40.32 244.103 ;
     RECT  45.6 244.089 45.72 244.103 ;
     RECT  51 244.089 51.12 244.103 ;
     RECT  56.4 244.089 56.52 244.103 ;
     RECT  61.8 244.089 61.92 244.103 ;
     RECT  67.2 244.089 67.32 244.103 ;
     RECT  72.6 244.089 72.72 244.103 ;
     RECT  77.52 244.089 78.12 244.103 ;
     RECT  83.4 244.089 83.52 244.103 ;
     RECT  88.8 244.089 88.92 244.103 ;
     RECT  94.2 244.089 94.32 244.103 ;
     RECT  99.6 244.089 99.72 244.103 ;
     RECT  105 244.089 105.12 244.103 ;
     RECT  110.4 244.089 110.52 244.103 ;
     RECT  115.8 244.089 115.92 244.103 ;
     RECT  121.2 244.089 121.32 244.103 ;
     RECT  126.6 244.089 126.72 244.103 ;
     RECT  132 244.089 132.12 244.103 ;
     RECT  137.4 244.089 137.52 244.103 ;
     RECT  142.8 244.089 142.92 244.103 ;
     RECT  148.2 244.089 148.32 244.103 ;
     RECT  77.52 244.103 77.88 246.085 ;
     RECT  77.52 246.085 77.976 246.224 ;
     RECT  3.288 8.293 4.8 9.589 ;
     RECT  3.336 9.589 4.8 10.067 ;
     RECT  5.496 9.637 6.864 11.027 ;
     RECT  5.496 11.027 7.68 12.227 ;
     RECT  5.496 12.227 7.8 12.517 ;
     RECT  6.456 12.517 7.8 56.389 ;
     RECT  1.08 12.757 2.4 14.485 ;
     RECT  2.712 39.877 3.936 41.267 ;
     RECT  2.712 41.267 3.984 42.227 ;
     RECT  3.192 44.965 4.464 45.829 ;
     RECT  3.192 49.763 4.272 51.301 ;
     RECT  3.192 52.979 4.272 54.085 ;
     RECT  6.792 56.389 7.8 64.405 ;
     RECT  13.512 68.677 14.496 76.501 ;
     RECT  9.864 71.173 11.04 72.805 ;
     RECT  11.064 71.173 12.432 75.781 ;
     RECT  9.96 72.805 11.04 75.781 ;
     RECT  21.912 73.765 23.376 80.629 ;
     RECT  11.112 75.781 12.432 77.941 ;
     RECT  17.352 78.517 18.6 79.813 ;
     RECT  17.352 79.813 18.336 80.869 ;
     RECT  19.704 80.341 20.976 80.965 ;
     RECT  19.704 80.965 20.784 82.645 ;
     RECT  14.52 81.445 15.792 82.021 ;
     RECT  14.52 82.021 15.6 82.501 ;
     RECT  65.784 91.717 67.2 104.963 ;
     RECT  149.256 92.869 150.48 94.115 ;
     RECT  146.568 98.581 147.792 98.869 ;
     RECT  146.568 102.565 147.888 103.669 ;
     RECT  146.568 103.669 147.648 104.819 ;
     RECT  148.68 107.171 149.808 107.795 ;
     RECT  148.68 109.957 149.856 111.443 ;
     RECT  148.68 111.443 149.88 111.685 ;
     RECT  148.68 111.685 149.904 112.691 ;
     RECT  51.312 113.459 51.624 114.517 ;
     RECT  148.512 114.035 148.68 115.093 ;
     RECT  149.352 117.445 150.816 117.491 ;
     RECT  24.84 118.501 26.112 119.171 ;
     RECT  146.568 120.469 147.648 122.579 ;
     RECT  24.312 124.213 25.632 152.243 ;
     RECT  146.568 126.133 147.648 127.763 ;
     RECT  16.008 129.443 17.184 131.411 ;
     RECT  18.912 131.123 20.304 131.363 ;
     RECT  16.008 131.411 17.616 131.651 ;
     RECT  16.008 131.651 16.104 131.797 ;
     RECT  146.568 133.285 147.888 134.579 ;
     RECT  21.864 133.909 22.896 134.291 ;
     RECT  55.176 134.485 56.4 155.411 ;
     RECT  149.208 138.757 150.48 140.243 ;
     RECT  16.008 139.717 17.04 139.859 ;
     RECT  17.064 139.717 18.144 139.859 ;
     RECT  149.208 140.243 149.928 141.637 ;
     RECT  16.008 144.181 17.424 147.923 ;
     RECT  149.304 151.429 150.432 154.259 ;
     RECT  146.952 152.485 148.2 153.157 ;
     RECT  147.048 153.157 148.2 154.355 ;
     RECT  10.92 162.371 11.952 162.851 ;
     RECT  13.704 164.531 15.072 168.851 ;
     RECT  1.128 199.619 2.304 201.827 ;
     RECT  3.24 206.963 4.32 212.099 ;
     RECT  3.192 212.099 4.32 213.685 ;
     RECT  8.472 212.099 9.936 213.779 ;
     RECT  3.192 214.931 4.32 221.219 ;
     RECT  5.832 220.643 7.344 226.741 ;
     RECT  3.192 221.219 4.896 222.229 ;
     RECT  3.192 222.229 4.656 222.899 ;
     RECT  3.432 224.533 4.848 226.403 ;
     RECT  5.976 226.741 7.344 229.763 ;
     RECT  5.832 229.763 7.344 232.019 ;
     RECT  4.872 234.275 4.968 234.805 ;
     RECT  4.872 234.805 6.288 235.187 ;
     RECT  6.312 234.805 7.8 235.475 ;
  END
END dsfd_vm_static_fsr_b3
END LIBRARY
